# BSD 3-Clause License
# 
# Copyright 2022 Lawrence T. Clark, Vinay Vashishtha, or Arizona State
# University
# 
# Redistribution and use in source and binary forms, with or without
# modification, are permitted provided that the following conditions are met:
# 
# 1. Redistributions of source code must retain the above copyright notice,
# this list of conditions and the following disclaimer.
# 
# 2. Redistributions in binary form must reproduce the above copyright
# notice, this list of conditions and the following disclaimer in the
# documentation and/or other materials provided with the distribution.
# 
# 3. Neither the name of the copyright holder nor the names of its
# contributors may be used to endorse or promote products derived from this
# software without specific prior written permission.
# 
# THIS SOFTWARE IS PROVIDED BY THE COPYRIGHT HOLDERS AND CONTRIBUTORS "AS IS"
# AND ANY EXPRESS OR IMPLIED WARRANTIES, INCLUDING, BUT NOT LIMITED TO, THE
# IMPLIED WARRANTIES OF MERCHANTABILITY AND FITNESS FOR A PARTICULAR PURPOSE
# ARE DISCLAIMED. IN NO EVENT SHALL THE COPYRIGHT HOLDER OR CONTRIBUTORS BE
# LIABLE FOR ANY DIRECT, INDIRECT, INCIDENTAL, SPECIAL, EXEMPLARY, OR
# CONSEQUENTIAL DAMAGES (INCLUDING, BUT NOT LIMITED TO, PROCUREMENT OF
# SUBSTITUTE GOODS OR SERVICES; LOSS OF USE, DATA, OR PROFITS; OR BUSINESS
# INTERRUPTION) HOWEVER CAUSED AND ON ANY THEORY OF LIABILITY, WHETHER IN
# CONTRACT, STRICT LIABILITY, OR TORT (INCLUDING NEGLIGENCE OR OTHERWISE)
# ARISING IN ANY WAY OUT OF THE USE OF THIS SOFTWARE, EVEN IF ADVISED OF THE
# POSSIBILITY OF SUCH DAMAGE.

VERSION 5.8 ;
BUSBITCHARS "[]" ;
DIVIDERCHAR "/" ;

SITE asap7sc7p5t
 CLASS CORE ;
 SIZE 0.054 BY 0.270 ;
 SYMMETRY Y ;
END asap7sc7p5t

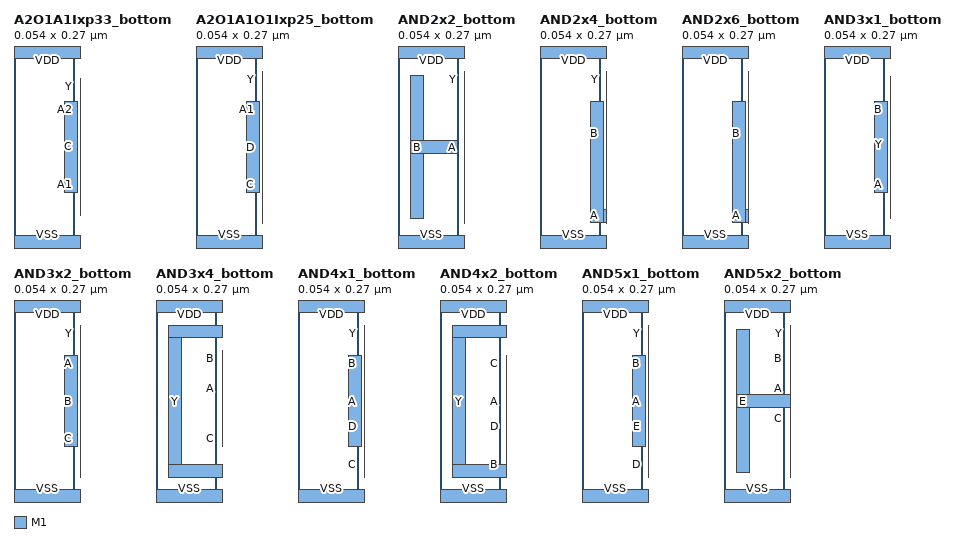
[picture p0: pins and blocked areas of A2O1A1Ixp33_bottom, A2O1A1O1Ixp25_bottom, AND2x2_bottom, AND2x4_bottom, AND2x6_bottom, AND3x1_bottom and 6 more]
MACRO A2O1A1Ixp33_bottom
  CLASS CORE ;
  ORIGIN 0 0 ;
  FOREIGN A2O1A1Ixp33_bottom 0 0 ;
  SIZE 0.054 BY 0.270 ;
  SYMMETRY X Y ;
  SITE asap7sc7p5t ;
  PIN A1
    DIRECTION INPUT ;
    USE SIGNAL ;
    PORT
      LAYER M1 ;
        RECT 0.072 0.07 0.09 0.2 ;
    END
  END A1
  PIN A2
    DIRECTION INPUT ;
    USE SIGNAL ;
    PORT
      LAYER M1 ;
        RECT 0.126 0.07 0.144 0.2 ;
    END
  END A2
  PIN B
    DIRECTION INPUT ;
    USE SIGNAL ;
    PORT
      LAYER M1 ;
        RECT 0.18 0.07 0.198 0.2 ;
    END
  END B
  PIN C
    DIRECTION INPUT ;
    USE SIGNAL ;
    PORT
      LAYER M1 ;
        RECT 0.234 0.081 0.252 0.19 ;
    END
  END C
  PIN VDD
    DIRECTION INOUT ;
    USE POWER ;
    SHAPE ABUTMENT ;
    PORT
      LAYER M1 ;
        RECT 0 0.261 0.324 0.279 ;
    END
  END VDD
  PIN VSS
    DIRECTION INOUT ;
    USE GROUND ;
    SHAPE ABUTMENT ;
    PORT
      LAYER M1 ;
        RECT 0 -0.009 0.324 0.009 ;
    END
  END VSS
  PIN Y
    DIRECTION OUTPUT ;
    USE SIGNAL ;
    PORT
      LAYER M1 ;
        RECT 0.214 0.215 0.306 0.233 ;
        RECT 0.288 0.037 0.306 0.233 ;
        RECT 0.262 0.037 0.306 0.055 ;
    END
  END Y
  OBS
    LAYER M1 ;
      RECT 0 0 0 0 ;
  END
END A2O1A1Ixp33_bottom

MACRO A2O1A1O1Ixp25_bottom
  CLASS CORE ;
  ORIGIN 0 0 ;
  FOREIGN A2O1A1O1Ixp25_bottom 0 0 ;
  SIZE 0.054 BY 0.270 ;
  SYMMETRY X Y ;
  SITE asap7sc7p5t ;
  PIN A1
    DIRECTION INPUT ;
    USE SIGNAL ;
    PORT
      LAYER M1 ;
        RECT 0.126 0.07 0.144 0.2 ;
    END
  END A1
  PIN A2
    DIRECTION INPUT ;
    USE SIGNAL ;
    PORT
      LAYER M1 ;
        RECT 0.072 0.07 0.09 0.2 ;
    END
  END A2
  PIN B
    DIRECTION INPUT ;
    USE SIGNAL ;
    PORT
      LAYER M1 ;
        RECT 0.18 0.07 0.198 0.2 ;
    END
  END B
  PIN C
    DIRECTION INPUT ;
    USE SIGNAL ;
    PORT
      LAYER M1 ;
        RECT 0.234 0.07 0.252 0.2 ;
    END
  END C
  PIN D
    DIRECTION INPUT ;
    USE SIGNAL ;
    PORT
      LAYER M1 ;
        RECT 0.342 0.127 0.414 0.145 ;
        RECT 0.342 0.07 0.36 0.2 ;
    END
  END D
  PIN VDD
    DIRECTION INOUT ;
    USE POWER ;
    SHAPE ABUTMENT ;
    PORT
      LAYER M1 ;
        RECT 0 0.261 0.486 0.279 ;
    END
  END VDD
  PIN VSS
    DIRECTION INOUT ;
    USE GROUND ;
    SHAPE ABUTMENT ;
    PORT
      LAYER M1 ;
        RECT 0 -0.009 0.486 0.009 ;
    END
  END VSS
  PIN Y
    DIRECTION OUTPUT ;
    USE SIGNAL ;
    PORT
      LAYER M1 ;
        RECT 0.423 0.225 0.468 0.243 ;
        RECT 0.45 0.027 0.468 0.243 ;
        RECT 0.261 0.027 0.468 0.045 ;
    END
  END Y
  OBS
    LAYER M1 ;
      RECT 0 0 0 0 ;
  END
END A2O1A1O1Ixp25_bottom

MACRO AND2x2_bottom
  CLASS CORE ;
  ORIGIN 0 0 ;
  FOREIGN AND2x2_bottom 0 0 ;
  SIZE 0.054 BY 0.270 ;
  SYMMETRY X Y ;
  SITE asap7sc7p5t ;
  PIN A
    DIRECTION INPUT ;
    USE SIGNAL ;
    PORT
      LAYER M1 ;
        RECT 0.126 0.07 0.144 0.2 ;
    END
  END A
  PIN B
    DIRECTION INPUT ;
    USE SIGNAL ;
    PORT
      LAYER M1 ;
        RECT 0.018 0.126 0.084 0.144 ;
        RECT 0.018 0.034 0.036 0.236 ;
    END
  END B
  PIN VDD
    DIRECTION INOUT ;
    USE POWER ;
    SHAPE ABUTMENT ;
    PORT
      LAYER M1 ;
        RECT 0 0.261 0.324 0.279 ;
    END
  END VDD
  PIN VSS
    DIRECTION INOUT ;
    USE GROUND ;
    SHAPE ABUTMENT ;
    PORT
      LAYER M1 ;
        RECT 0 -0.009 0.324 0.009 ;
    END
  END VSS
  PIN Y
    DIRECTION OUTPUT ;
    USE SIGNAL ;
    PORT
      LAYER M1 ;
        RECT 0.207 0.225 0.306 0.243 ;
        RECT 0.288 0.027 0.306 0.243 ;
        RECT 0.207 0.027 0.306 0.045 ;
        RECT 0.207 0.184 0.225 0.243 ;
        RECT 0.207 0.027 0.225 0.086 ;
    END
  END Y
  OBS
    LAYER M1 ;
      RECT 0 0 0 0 ;
  END
END AND2x2_bottom

MACRO AND2x4_bottom
  CLASS CORE ;
  ORIGIN 0 0 ;
  FOREIGN AND2x4_bottom 0 0 ;
  SIZE 0.054 BY 0.270 ;
  SYMMETRY X Y ;
  SITE asap7sc7p5t ;
  PIN A
    DIRECTION INPUT ;
    USE SIGNAL ;
    PORT
      LAYER M1 ;
        RECT 0.234 0.028 0.252 0.15 ;
        RECT 0.072 0.028 0.252 0.046 ;
        RECT 0.072 0.028 0.09 0.2 ;
    END
  END A
  PIN B
    DIRECTION INPUT ;
    USE SIGNAL ;
    PORT
      LAYER M1 ;
        RECT 0.126 0.107 0.144 0.2 ;
    END
  END B
  PIN VDD
    DIRECTION INOUT ;
    USE POWER ;
    SHAPE ABUTMENT ;
    PORT
      LAYER M1 ;
        RECT 0 0.261 0.54 0.279 ;
    END
  END VDD
  PIN VSS
    DIRECTION INOUT ;
    USE GROUND ;
    SHAPE ABUTMENT ;
    PORT
      LAYER M1 ;
        RECT 0 -0.009 0.54 0.009 ;
    END
  END VSS
  PIN Y
    DIRECTION OUTPUT ;
    USE SIGNAL ;
    PORT
      LAYER M1 ;
        RECT 0.31 0.225 0.468 0.243 ;
        RECT 0.45 0.027 0.468 0.243 ;
        RECT 0.31 0.027 0.468 0.045 ;
    END
  END Y
  OBS
    LAYER M1 ;
      RECT 0 0 0 0 ;
  END
END AND2x4_bottom

MACRO AND2x6_bottom
  CLASS CORE ;
  ORIGIN 0 0 ;
  FOREIGN AND2x6_bottom 0 0 ;
  SIZE 0.054 BY 0.270 ;
  SYMMETRY X Y ;
  SITE asap7sc7p5t ;
  PIN A
    DIRECTION INPUT ;
    USE SIGNAL ;
    PORT
      LAYER M1 ;
        RECT 0.234 0.028 0.252 0.15 ;
        RECT 0.072 0.028 0.252 0.046 ;
        RECT 0.072 0.028 0.09 0.2 ;
    END
  END A
  PIN B
    DIRECTION INPUT ;
    USE SIGNAL ;
    PORT
      LAYER M1 ;
        RECT 0.126 0.107 0.144 0.2 ;
    END
  END B
  PIN VDD
    DIRECTION INOUT ;
    USE POWER ;
    SHAPE ABUTMENT ;
    PORT
      LAYER M1 ;
        RECT 0 0.261 0.648 0.279 ;
    END
  END VDD
  PIN VSS
    DIRECTION INOUT ;
    USE GROUND ;
    SHAPE ABUTMENT ;
    PORT
      LAYER M1 ;
        RECT 0 -0.009 0.648 0.009 ;
    END
  END VSS
  PIN Y
    DIRECTION OUTPUT ;
    USE SIGNAL ;
    PORT
      LAYER M1 ;
        RECT 0.31 0.225 0.554 0.243 ;
        RECT 0.31 0.027 0.554 0.045 ;
        RECT 0.45 0.027 0.468 0.243 ;
    END
  END Y
  OBS
    LAYER M1 ;
      RECT 0 0 0 0 ;
  END
END AND2x6_bottom

MACRO AND3x1_bottom
  CLASS CORE ;
  ORIGIN 0 0 ;
  FOREIGN AND3x1_bottom 0 0 ;
  SIZE 0.054 BY 0.270 ;
  SYMMETRY X Y ;
  SITE asap7sc7p5t ;
  PIN A
    DIRECTION INPUT ;
    USE SIGNAL ;
    PORT
      LAYER M1 ;
        RECT 0.072 0.07 0.09 0.2 ;
    END
  END A
  PIN B
    DIRECTION INPUT ;
    USE SIGNAL ;
    PORT
      LAYER M1 ;
        RECT 0.126 0.07 0.144 0.2 ;
    END
  END B
  PIN C
    DIRECTION INPUT ;
    USE SIGNAL ;
    PORT
      LAYER M1 ;
        RECT 0.18 0.07 0.198 0.2 ;
    END
  END C
  PIN VDD
    DIRECTION INOUT ;
    USE POWER ;
    SHAPE ABUTMENT ;
    PORT
      LAYER M1 ;
        RECT 0 0.261 0.324 0.279 ;
    END
  END VDD
  PIN VSS
    DIRECTION INOUT ;
    USE GROUND ;
    SHAPE ABUTMENT ;
    PORT
      LAYER M1 ;
        RECT 0 -0.009 0.324 0.009 ;
    END
  END VSS
  PIN Y
    DIRECTION OUTPUT ;
    USE SIGNAL ;
    PORT
      LAYER M1 ;
        RECT 0.261 0.183 0.306 0.201 ;
        RECT 0.288 0.076 0.306 0.201 ;
        RECT 0.261 0.076 0.306 0.094 ;
        RECT 0.261 0.183 0.279 0.235 ;
        RECT 0.261 0.034 0.279 0.094 ;
    END
  END Y
  OBS
    LAYER M1 ;
      RECT 0 0 0 0 ;
  END
END AND3x1_bottom

MACRO AND3x2_bottom
  CLASS CORE ;
  ORIGIN 0 0 ;
  FOREIGN AND3x2_bottom 0 0 ;
  SIZE 0.054 BY 0.270 ;
  SYMMETRY X Y ;
  SITE asap7sc7p5t ;
  PIN A
    DIRECTION INPUT ;
    USE SIGNAL ;
    PORT
      LAYER M1 ;
        RECT 0.072 0.07 0.09 0.2 ;
    END
  END A
  PIN B
    DIRECTION INPUT ;
    USE SIGNAL ;
    PORT
      LAYER M1 ;
        RECT 0.126 0.07 0.144 0.2 ;
    END
  END B
  PIN C
    DIRECTION INPUT ;
    USE SIGNAL ;
    PORT
      LAYER M1 ;
        RECT 0.18 0.07 0.198 0.2 ;
    END
  END C
  PIN VDD
    DIRECTION INOUT ;
    USE POWER ;
    SHAPE ABUTMENT ;
    PORT
      LAYER M1 ;
        RECT 0 0.261 0.378 0.279 ;
    END
  END VDD
  PIN VSS
    DIRECTION INOUT ;
    USE GROUND ;
    SHAPE ABUTMENT ;
    PORT
      LAYER M1 ;
        RECT 0 -0.009 0.378 0.009 ;
    END
  END VSS
  PIN Y
    DIRECTION OUTPUT ;
    USE SIGNAL ;
    PORT
      LAYER M1 ;
        RECT 0.261 0.225 0.36 0.243 ;
        RECT 0.342 0.027 0.36 0.243 ;
        RECT 0.261 0.027 0.36 0.045 ;
        RECT 0.261 0.184 0.279 0.243 ;
        RECT 0.261 0.027 0.279 0.086 ;
    END
  END Y
  OBS
    LAYER M1 ;
      RECT 0 0 0 0 ;
  END
END AND3x2_bottom

MACRO AND3x4_bottom
  CLASS CORE ;
  ORIGIN 0 0 ;
  FOREIGN AND3x4_bottom 0 0 ;
  SIZE 0.054 BY 0.270 ;
  SYMMETRY X Y ;
  SITE asap7sc7p5t ;
  PIN A
    DIRECTION INPUT ;
    USE SIGNAL ;
    PORT
      LAYER M1 ;
        RECT 0.612 0.189 0.649 0.207 ;
        RECT 0.612 0.099 0.649 0.117 ;
        RECT 0.612 0.099 0.63 0.207 ;
    END
  END A
  PIN B
    DIRECTION INPUT ;
    USE SIGNAL ;
    PORT
      LAYER M1 ;
        RECT 0.504 0.189 0.541 0.207 ;
        RECT 0.504 0.099 0.541 0.117 ;
        RECT 0.504 0.099 0.522 0.207 ;
    END
  END B
  PIN C
    DIRECTION INPUT ;
    USE SIGNAL ;
    PORT
      LAYER M1 ;
        RECT 0.342 0.07 0.36 0.2 ;
    END
  END C
  PIN VDD
    DIRECTION INOUT ;
    USE POWER ;
    SHAPE ABUTMENT ;
    PORT
      LAYER M1 ;
        RECT 0 0.261 0.756 0.279 ;
    END
  END VDD
  PIN VSS
    DIRECTION INOUT ;
    USE GROUND ;
    SHAPE ABUTMENT ;
    PORT
      LAYER M1 ;
        RECT 0 -0.009 0.756 0.009 ;
    END
  END VSS
  PIN Y
    DIRECTION OUTPUT ;
    USE SIGNAL ;
    PORT
      LAYER M1 ;
        RECT 0.018 0.225 0.23 0.243 ;
        RECT 0.018 0.027 0.23 0.045 ;
        RECT 0.018 0.027 0.036 0.243 ;
    END
  END Y
  OBS
    LAYER M1 ;
      RECT 0 0 0 0 ;
  END
END AND3x4_bottom

MACRO AND4x1_bottom
  CLASS CORE ;
  ORIGIN 0 0 ;
  FOREIGN AND4x1_bottom 0 0 ;
  SIZE 0.054 BY 0.270 ;
  SYMMETRY X Y ;
  SITE asap7sc7p5t ;
  PIN A
    DIRECTION INPUT ;
    USE SIGNAL ;
    PORT
      LAYER M1 ;
        RECT 0.072 0.07 0.09 0.2 ;
    END
  END A
  PIN B
    DIRECTION INPUT ;
    USE SIGNAL ;
    PORT
      LAYER M1 ;
        RECT 0.126 0.034 0.144 0.2 ;
    END
  END B
  PIN C
    DIRECTION INPUT ;
    USE SIGNAL ;
    PORT
      LAYER M1 ;
        RECT 0.18 0.034 0.198 0.2 ;
    END
  END C
  PIN D
    DIRECTION INPUT ;
    USE SIGNAL ;
    PORT
      LAYER M1 ;
        RECT 0.234 0.034 0.252 0.164 ;
    END
  END D
  PIN VDD
    DIRECTION INOUT ;
    USE POWER ;
    SHAPE ABUTMENT ;
    PORT
      LAYER M1 ;
        RECT 0 0.261 0.378 0.279 ;
    END
  END VDD
  PIN VSS
    DIRECTION INOUT ;
    USE GROUND ;
    SHAPE ABUTMENT ;
    PORT
      LAYER M1 ;
        RECT 0 -0.009 0.378 0.009 ;
    END
  END VSS
  PIN Y
    DIRECTION OUTPUT ;
    USE SIGNAL ;
    PORT
      LAYER M1 ;
        RECT 0.299 0.225 0.36 0.243 ;
        RECT 0.342 0.027 0.36 0.243 ;
        RECT 0.31 0.027 0.36 0.045 ;
    END
  END Y
  OBS
    LAYER M1 ;
      RECT 0 0 0 0 ;
  END
END AND4x1_bottom

MACRO AND4x2_bottom
  CLASS CORE ;
  ORIGIN 0 0 ;
  FOREIGN AND4x2_bottom 0 0 ;
  SIZE 0.054 BY 0.270 ;
  SYMMETRY X Y ;
  SITE asap7sc7p5t ;
  PIN A
    DIRECTION INPUT ;
    USE SIGNAL ;
    PORT
      LAYER M1 ;
        RECT 0.342 0.07 0.36 0.2 ;
    END
  END A
  PIN B
    DIRECTION INPUT ;
    USE SIGNAL ;
    PORT
      LAYER M1 ;
        RECT 0.288 0.034 0.306 0.2 ;
    END
  END B
  PIN C
    DIRECTION INPUT ;
    USE SIGNAL ;
    PORT
      LAYER M1 ;
        RECT 0.234 0.034 0.252 0.2 ;
    END
  END C
  PIN D
    DIRECTION INPUT ;
    USE SIGNAL ;
    PORT
      LAYER M1 ;
        RECT 0.18 0.034 0.198 0.164 ;
    END
  END D
  PIN VDD
    DIRECTION INOUT ;
    USE POWER ;
    SHAPE ABUTMENT ;
    PORT
      LAYER M1 ;
        RECT 0 0.261 0.432 0.279 ;
    END
  END VDD
  PIN VSS
    DIRECTION INOUT ;
    USE GROUND ;
    SHAPE ABUTMENT ;
    PORT
      LAYER M1 ;
        RECT 0 -0.009 0.432 0.009 ;
    END
  END VSS
  PIN Y
    DIRECTION OUTPUT ;
    USE SIGNAL ;
    PORT
      LAYER M1 ;
        RECT 0.018 0.225 0.122 0.243 ;
        RECT 0.018 0.027 0.122 0.045 ;
        RECT 0.018 0.027 0.036 0.243 ;
    END
  END Y
  OBS
    LAYER M1 ;
      RECT 0 0 0 0 ;
  END
END AND4x2_bottom

MACRO AND5x1_bottom
  CLASS CORE ;
  ORIGIN 0 0 ;
  FOREIGN AND5x1_bottom 0 0 ;
  SIZE 0.054 BY 0.270 ;
  SYMMETRY X Y ;
  SITE asap7sc7p5t ;
  PIN A
    DIRECTION INPUT ;
    USE SIGNAL ;
    PORT
      LAYER M1 ;
        RECT 0.072 0.07 0.09 0.2 ;
    END
  END A
  PIN B
    DIRECTION INPUT ;
    USE SIGNAL ;
    PORT
      LAYER M1 ;
        RECT 0.126 0.034 0.144 0.2 ;
    END
  END B
  PIN C
    DIRECTION INPUT ;
    USE SIGNAL ;
    PORT
      LAYER M1 ;
        RECT 0.18 0.034 0.198 0.2 ;
    END
  END C
  PIN D
    DIRECTION INPUT ;
    USE SIGNAL ;
    PORT
      LAYER M1 ;
        RECT 0.234 0.034 0.252 0.2 ;
    END
  END D
  PIN E
    DIRECTION INPUT ;
    USE SIGNAL ;
    PORT
      LAYER M1 ;
        RECT 0.288 0.034 0.306 0.164 ;
    END
  END E
  PIN VDD
    DIRECTION INOUT ;
    USE POWER ;
    SHAPE ABUTMENT ;
    PORT
      LAYER M1 ;
        RECT 0 0.261 0.432 0.279 ;
    END
  END VDD
  PIN VSS
    DIRECTION INOUT ;
    USE GROUND ;
    SHAPE ABUTMENT ;
    PORT
      LAYER M1 ;
        RECT 0 -0.009 0.432 0.009 ;
    END
  END VSS
  PIN Y
    DIRECTION OUTPUT ;
    USE SIGNAL ;
    PORT
      LAYER M1 ;
        RECT 0.349 0.225 0.414 0.243 ;
        RECT 0.396 0.027 0.414 0.243 ;
        RECT 0.35 0.027 0.414 0.045 ;
    END
  END Y
  OBS
    LAYER M1 ;
      RECT 0 0 0 0 ;
  END
END AND5x1_bottom

MACRO AND5x2_bottom
  CLASS CORE ;
  ORIGIN 0 0 ;
  FOREIGN AND5x2_bottom 0 0 ;
  SIZE 0.054 BY 0.270 ;
  SYMMETRY X Y ;
  SITE asap7sc7p5t ;
  PIN A
    DIRECTION INPUT ;
    USE SIGNAL ;
    PORT
      LAYER M1 ;
        RECT 0.72 0.189 0.757 0.207 ;
        RECT 0.72 0.099 0.757 0.117 ;
        RECT 0.72 0.099 0.738 0.207 ;
    END
  END A
  PIN B
    DIRECTION INPUT ;
    USE SIGNAL ;
    PORT
      LAYER M1 ;
        RECT 0.593 0.189 0.63 0.207 ;
        RECT 0.612 0.099 0.63 0.207 ;
        RECT 0.593 0.099 0.63 0.117 ;
    END
  END B
  PIN C
    DIRECTION INPUT ;
    USE SIGNAL ;
    PORT
      LAYER M1 ;
        RECT 0.45 0.189 0.487 0.207 ;
        RECT 0.45 0.099 0.487 0.117 ;
        RECT 0.45 0.099 0.468 0.207 ;
    END
  END C
  PIN D
    DIRECTION INPUT ;
    USE SIGNAL ;
    PORT
      LAYER M1 ;
        RECT 0.269 0.189 0.306 0.207 ;
        RECT 0.288 0.099 0.306 0.207 ;
        RECT 0.269 0.099 0.306 0.117 ;
    END
  END D
  PIN E
    DIRECTION INPUT ;
    USE SIGNAL ;
    PORT
      LAYER M1 ;
        RECT 0.018 0.126 0.095 0.144 ;
        RECT 0.018 0.034 0.036 0.236 ;
    END
  END E
  PIN VDD
    DIRECTION INOUT ;
    USE POWER ;
    SHAPE ABUTMENT ;
    PORT
      LAYER M1 ;
        RECT 0 0.261 1.08 0.279 ;
    END
  END VDD
  PIN VSS
    DIRECTION INOUT ;
    USE GROUND ;
    SHAPE ABUTMENT ;
    PORT
      LAYER M1 ;
        RECT 0 -0.009 1.08 0.009 ;
    END
  END VSS
  PIN Y
    DIRECTION OUTPUT ;
    USE SIGNAL ;
    PORT
      LAYER M1 ;
        RECT 0.958 0.225 1.062 0.243 ;
        RECT 1.044 0.027 1.062 0.243 ;
        RECT 0.958 0.027 1.062 0.045 ;
    END
  END Y
  OBS
    LAYER M1 ;
      RECT 0 0 0 0 ;
  END
END AND5x2_bottom

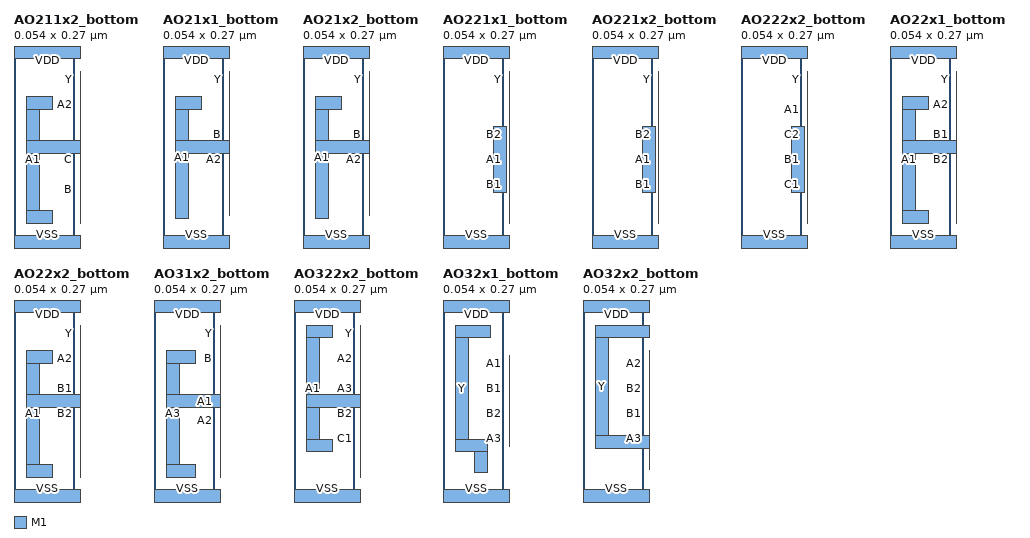
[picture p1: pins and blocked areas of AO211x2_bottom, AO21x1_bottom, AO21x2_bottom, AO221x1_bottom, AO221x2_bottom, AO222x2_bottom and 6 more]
MACRO AO211x2_bottom
  CLASS CORE ;
  ORIGIN 0 0 ;
  FOREIGN AO211x2_bottom 0 0 ;
  SIZE 0.054 BY 0.270 ;
  SYMMETRY X Y ;
  SITE asap7sc7p5t ;
  PIN A1
    DIRECTION INPUT ;
    USE SIGNAL ;
    PORT
      LAYER M1 ;
        RECT 0.018 0.126 0.095 0.144 ;
        RECT 0.018 0.189 0.055 0.207 ;
        RECT 0.018 0.027 0.055 0.045 ;
        RECT 0.018 0.027 0.036 0.207 ;
    END
  END A1
  PIN A2
    DIRECTION INPUT ;
    USE SIGNAL ;
    PORT
      LAYER M1 ;
        RECT 0.126 0.126 0.203 0.144 ;
        RECT 0.107 0.189 0.144 0.207 ;
        RECT 0.126 0.063 0.144 0.207 ;
        RECT 0.107 0.063 0.144 0.081 ;
    END
  END A2
  PIN B
    DIRECTION INPUT ;
    USE SIGNAL ;
    PORT
      LAYER M1 ;
        RECT 0.234 0.126 0.311 0.144 ;
        RECT 0.215 0.189 0.252 0.207 ;
        RECT 0.234 0.063 0.252 0.207 ;
        RECT 0.215 0.063 0.252 0.081 ;
    END
  END B
  PIN C
    DIRECTION INPUT ;
    USE SIGNAL ;
    PORT
      LAYER M1 ;
        RECT 0.504 0.153 0.541 0.171 ;
        RECT 0.504 0.063 0.522 0.171 ;
        RECT 0.485 0.063 0.522 0.081 ;
    END
  END C
  PIN VDD
    DIRECTION INOUT ;
    USE POWER ;
    SHAPE ABUTMENT ;
    PORT
      LAYER M1 ;
        RECT 0 0.261 0.864 0.279 ;
    END
  END VDD
  PIN VSS
    DIRECTION INOUT ;
    USE GROUND ;
    SHAPE ABUTMENT ;
    PORT
      LAYER M1 ;
        RECT 0 -0.009 0.864 0.009 ;
    END
  END VSS
  PIN Y
    DIRECTION OUTPUT ;
    USE SIGNAL ;
    PORT
      LAYER M1 ;
        RECT 0.742 0.225 0.846 0.243 ;
        RECT 0.828 0.027 0.846 0.243 ;
        RECT 0.742 0.027 0.846 0.045 ;
    END
  END Y
  OBS
    LAYER M1 ;
      RECT 0 0 0 0 ;
  END
END AO211x2_bottom

MACRO AO21x1_bottom
  CLASS CORE ;
  ORIGIN 0 0 ;
  FOREIGN AO21x1_bottom 0 0 ;
  SIZE 0.054 BY 0.270 ;
  SYMMETRY X Y ;
  SITE asap7sc7p5t ;
  PIN A1
    DIRECTION INPUT ;
    USE SIGNAL ;
    PORT
      LAYER M1 ;
        RECT 0.018 0.126 0.095 0.144 ;
        RECT 0.018 0.189 0.055 0.207 ;
        RECT 0.018 0.034 0.036 0.207 ;
    END
  END A1
  PIN A2
    DIRECTION INPUT ;
    USE SIGNAL ;
    PORT
      LAYER M1 ;
        RECT 0.126 0.07 0.144 0.164 ;
    END
  END A2
  PIN B
    DIRECTION INPUT ;
    USE SIGNAL ;
    PORT
      LAYER M1 ;
        RECT 0.18 0.07 0.198 0.164 ;
    END
  END B
  PIN VDD
    DIRECTION INOUT ;
    USE POWER ;
    SHAPE ABUTMENT ;
    PORT
      LAYER M1 ;
        RECT 0 0.261 0.324 0.279 ;
    END
  END VDD
  PIN VSS
    DIRECTION INOUT ;
    USE GROUND ;
    SHAPE ABUTMENT ;
    PORT
      LAYER M1 ;
        RECT 0 -0.009 0.324 0.009 ;
    END
  END VSS
  PIN Y
    DIRECTION OUTPUT ;
    USE SIGNAL ;
    PORT
      LAYER M1 ;
        RECT 0.23 0.225 0.295 0.243 ;
        RECT 0.277 0.038 0.295 0.243 ;
    END
  END Y
  OBS
    LAYER M1 ;
      RECT 0 0 0 0 ;
  END
END AO21x1_bottom

MACRO AO21x2_bottom
  CLASS CORE ;
  ORIGIN 0 0 ;
  FOREIGN AO21x2_bottom 0 0 ;
  SIZE 0.054 BY 0.270 ;
  SYMMETRY X Y ;
  SITE asap7sc7p5t ;
  PIN A1
    DIRECTION INPUT ;
    USE SIGNAL ;
    PORT
      LAYER M1 ;
        RECT 0.018 0.126 0.095 0.144 ;
        RECT 0.018 0.189 0.055 0.207 ;
        RECT 0.018 0.034 0.036 0.207 ;
    END
  END A1
  PIN A2
    DIRECTION INPUT ;
    USE SIGNAL ;
    PORT
      LAYER M1 ;
        RECT 0.126 0.07 0.144 0.164 ;
    END
  END A2
  PIN B
    DIRECTION INPUT ;
    USE SIGNAL ;
    PORT
      LAYER M1 ;
        RECT 0.18 0.07 0.198 0.164 ;
    END
  END B
  PIN VDD
    DIRECTION INOUT ;
    USE POWER ;
    SHAPE ABUTMENT ;
    PORT
      LAYER M1 ;
        RECT 0 0.261 0.378 0.279 ;
    END
  END VDD
  PIN VSS
    DIRECTION INOUT ;
    USE GROUND ;
    SHAPE ABUTMENT ;
    PORT
      LAYER M1 ;
        RECT 0 -0.009 0.378 0.009 ;
    END
  END VSS
  PIN Y
    DIRECTION OUTPUT ;
    USE SIGNAL ;
    PORT
      LAYER M1 ;
        RECT 0.23 0.225 0.333 0.243 ;
        RECT 0.315 0.069 0.333 0.243 ;
        RECT 0.276 0.069 0.333 0.087 ;
        RECT 0.276 0.038 0.294 0.087 ;
    END
  END Y
  OBS
    LAYER M1 ;
      RECT 0 0 0 0 ;
  END
END AO21x2_bottom

MACRO AO221x1_bottom
  CLASS CORE ;
  ORIGIN 0 0 ;
  FOREIGN AO221x1_bottom 0 0 ;
  SIZE 0.054 BY 0.270 ;
  SYMMETRY X Y ;
  SITE asap7sc7p5t ;
  PIN A1
    DIRECTION INPUT ;
    USE SIGNAL ;
    PORT
      LAYER M1 ;
        RECT 0.234 0.07 0.252 0.164 ;
    END
  END A1
  PIN A2
    DIRECTION INPUT ;
    USE SIGNAL ;
    PORT
      LAYER M1 ;
        RECT 0.288 0.07 0.306 0.164 ;
    END
  END A2
  PIN B1
    DIRECTION INPUT ;
    USE SIGNAL ;
    PORT
      LAYER M1 ;
        RECT 0.072 0.07 0.09 0.164 ;
    END
  END B1
  PIN B2
    DIRECTION INPUT ;
    USE SIGNAL ;
    PORT
      LAYER M1 ;
        RECT 0.126 0.07 0.144 0.164 ;
    END
  END B2
  PIN C
    DIRECTION INPUT ;
    USE SIGNAL ;
    PORT
      LAYER M1 ;
        RECT 0.18 0.07 0.198 0.164 ;
    END
  END C
  PIN VDD
    DIRECTION INOUT ;
    USE POWER ;
    SHAPE ABUTMENT ;
    PORT
      LAYER M1 ;
        RECT 0 0.261 0.54 0.279 ;
    END
  END VDD
  PIN VSS
    DIRECTION INOUT ;
    USE GROUND ;
    SHAPE ABUTMENT ;
    PORT
      LAYER M1 ;
        RECT 0 -0.009 0.54 0.009 ;
    END
  END VSS
  PIN Y
    DIRECTION OUTPUT ;
    USE SIGNAL ;
    PORT
      LAYER M1 ;
        RECT 0.472 0.225 0.522 0.243 ;
        RECT 0.504 0.027 0.522 0.243 ;
        RECT 0.459 0.027 0.522 0.045 ;
    END
  END Y
  OBS
    LAYER M1 ;
      RECT 0 0 0 0 ;
  END
END AO221x1_bottom

MACRO AO221x2_bottom
  CLASS CORE ;
  ORIGIN 0 0 ;
  FOREIGN AO221x2_bottom 0 0 ;
  SIZE 0.054 BY 0.270 ;
  SYMMETRY X Y ;
  SITE asap7sc7p5t ;
  PIN A1
    DIRECTION INPUT ;
    USE SIGNAL ;
    PORT
      LAYER M1 ;
        RECT 0.234 0.07 0.252 0.164 ;
    END
  END A1
  PIN A2
    DIRECTION INPUT ;
    USE SIGNAL ;
    PORT
      LAYER M1 ;
        RECT 0.288 0.07 0.306 0.164 ;
    END
  END A2
  PIN B1
    DIRECTION INPUT ;
    USE SIGNAL ;
    PORT
      LAYER M1 ;
        RECT 0.072 0.07 0.09 0.164 ;
    END
  END B1
  PIN B2
    DIRECTION INPUT ;
    USE SIGNAL ;
    PORT
      LAYER M1 ;
        RECT 0.126 0.07 0.144 0.164 ;
    END
  END B2
  PIN C
    DIRECTION INPUT ;
    USE SIGNAL ;
    PORT
      LAYER M1 ;
        RECT 0.18 0.07 0.198 0.164 ;
    END
  END C
  PIN VDD
    DIRECTION INOUT ;
    USE POWER ;
    SHAPE ABUTMENT ;
    PORT
      LAYER M1 ;
        RECT 0 0.261 0.594 0.279 ;
    END
  END VDD
  PIN VSS
    DIRECTION INOUT ;
    USE GROUND ;
    SHAPE ABUTMENT ;
    PORT
      LAYER M1 ;
        RECT 0 -0.009 0.594 0.009 ;
    END
  END VSS
  PIN Y
    DIRECTION OUTPUT ;
    USE SIGNAL ;
    PORT
      LAYER M1 ;
        RECT 0.472 0.225 0.549 0.243 ;
        RECT 0.531 0.027 0.549 0.243 ;
        RECT 0.459 0.027 0.549 0.045 ;
    END
  END Y
  OBS
    LAYER M1 ;
      RECT 0 0 0 0 ;
  END
END AO221x2_bottom

MACRO AO222x2_bottom
  CLASS CORE ;
  ORIGIN 0 0 ;
  FOREIGN AO222x2_bottom 0 0 ;
  SIZE 0.054 BY 0.270 ;
  SYMMETRY X Y ;
  SITE asap7sc7p5t ;
  PIN A1
    DIRECTION INPUT ;
    USE SIGNAL ;
    PORT
      LAYER M1 ;
        RECT 0.396 0.07 0.414 0.2 ;
    END
  END A1
  PIN A2
    DIRECTION INPUT ;
    USE SIGNAL ;
    PORT
      LAYER M1 ;
        RECT 0.45 0.07 0.468 0.2 ;
    END
  END A2
  PIN B1
    DIRECTION INPUT ;
    USE SIGNAL ;
    PORT
      LAYER M1 ;
        RECT 0.234 0.07 0.252 0.164 ;
    END
  END B1
  PIN B2
    DIRECTION INPUT ;
    USE SIGNAL ;
    PORT
      LAYER M1 ;
        RECT 0.18 0.07 0.198 0.164 ;
    END
  END B2
  PIN C1
    DIRECTION INPUT ;
    USE SIGNAL ;
    PORT
      LAYER M1 ;
        RECT 0.072 0.07 0.09 0.164 ;
    END
  END C1
  PIN C2
    DIRECTION INPUT ;
    USE SIGNAL ;
    PORT
      LAYER M1 ;
        RECT 0.126 0.07 0.144 0.164 ;
    END
  END C2
  PIN VDD
    DIRECTION INOUT ;
    USE POWER ;
    SHAPE ABUTMENT ;
    PORT
      LAYER M1 ;
        RECT 0 0.261 0.648 0.279 ;
    END
  END VDD
  PIN VSS
    DIRECTION INOUT ;
    USE GROUND ;
    SHAPE ABUTMENT ;
    PORT
      LAYER M1 ;
        RECT 0 -0.009 0.648 0.009 ;
    END
  END VSS
  PIN Y
    DIRECTION OUTPUT ;
    USE SIGNAL ;
    PORT
      LAYER M1 ;
        RECT 0.526 0.225 0.63 0.243 ;
        RECT 0.612 0.027 0.63 0.243 ;
        RECT 0.531 0.027 0.63 0.045 ;
        RECT 0.531 0.027 0.549 0.081 ;
    END
  END Y
  OBS
    LAYER M1 ;
      RECT 0 0 0 0 ;
  END
END AO222x2_bottom

MACRO AO22x1_bottom
  CLASS CORE ;
  ORIGIN 0 0 ;
  FOREIGN AO22x1_bottom 0 0 ;
  SIZE 0.054 BY 0.270 ;
  SYMMETRY X Y ;
  SITE asap7sc7p5t ;
  PIN A1
    DIRECTION INPUT ;
    USE SIGNAL ;
    PORT
      LAYER M1 ;
        RECT 0.018 0.126 0.095 0.144 ;
        RECT 0.018 0.189 0.055 0.207 ;
        RECT 0.018 0.027 0.055 0.045 ;
        RECT 0.018 0.027 0.036 0.207 ;
    END
  END A1
  PIN A2
    DIRECTION INPUT ;
    USE SIGNAL ;
    PORT
      LAYER M1 ;
        RECT 0.107 0.189 0.144 0.207 ;
        RECT 0.126 0.063 0.144 0.207 ;
        RECT 0.107 0.063 0.144 0.081 ;
    END
  END A2
  PIN B1
    DIRECTION INPUT ;
    USE SIGNAL ;
    PORT
      LAYER M1 ;
        RECT 0.234 0.063 0.287 0.081 ;
        RECT 0.234 0.063 0.252 0.164 ;
    END
  END B1
  PIN B2
    DIRECTION INPUT ;
    USE SIGNAL ;
    PORT
      LAYER M1 ;
        RECT 0.18 0.07 0.198 0.164 ;
    END
  END B2
  PIN VDD
    DIRECTION INOUT ;
    USE POWER ;
    SHAPE ABUTMENT ;
    PORT
      LAYER M1 ;
        RECT 0 0.261 0.486 0.279 ;
    END
  END VDD
  PIN VSS
    DIRECTION INOUT ;
    USE GROUND ;
    SHAPE ABUTMENT ;
    PORT
      LAYER M1 ;
        RECT 0 -0.009 0.486 0.009 ;
    END
  END VSS
  PIN Y
    DIRECTION OUTPUT ;
    USE SIGNAL ;
    PORT
      LAYER M1 ;
        RECT 0.418 0.225 0.468 0.243 ;
        RECT 0.45 0.027 0.468 0.243 ;
        RECT 0.418 0.027 0.468 0.045 ;
    END
  END Y
  OBS
    LAYER M1 ;
      RECT 0 0 0 0 ;
  END
END AO22x1_bottom

MACRO AO22x2_bottom
  CLASS CORE ;
  ORIGIN 0 0 ;
  FOREIGN AO22x2_bottom 0 0 ;
  SIZE 0.054 BY 0.270 ;
  SYMMETRY X Y ;
  SITE asap7sc7p5t ;
  PIN A1
    DIRECTION INPUT ;
    USE SIGNAL ;
    PORT
      LAYER M1 ;
        RECT 0.018 0.126 0.095 0.144 ;
        RECT 0.018 0.189 0.055 0.207 ;
        RECT 0.018 0.027 0.055 0.045 ;
        RECT 0.018 0.027 0.036 0.207 ;
    END
  END A1
  PIN A2
    DIRECTION INPUT ;
    USE SIGNAL ;
    PORT
      LAYER M1 ;
        RECT 0.107 0.189 0.144 0.207 ;
        RECT 0.126 0.063 0.144 0.207 ;
        RECT 0.107 0.063 0.144 0.081 ;
    END
  END A2
  PIN B1
    DIRECTION INPUT ;
    USE SIGNAL ;
    PORT
      LAYER M1 ;
        RECT 0.234 0.063 0.287 0.081 ;
        RECT 0.234 0.063 0.252 0.164 ;
    END
  END B1
  PIN B2
    DIRECTION INPUT ;
    USE SIGNAL ;
    PORT
      LAYER M1 ;
        RECT 0.18 0.07 0.198 0.164 ;
    END
  END B2
  PIN VDD
    DIRECTION INOUT ;
    USE POWER ;
    SHAPE ABUTMENT ;
    PORT
      LAYER M1 ;
        RECT 0 0.261 0.54 0.279 ;
    END
  END VDD
  PIN VSS
    DIRECTION INOUT ;
    USE GROUND ;
    SHAPE ABUTMENT ;
    PORT
      LAYER M1 ;
        RECT 0 -0.009 0.54 0.009 ;
    END
  END VSS
  PIN Y
    DIRECTION OUTPUT ;
    USE SIGNAL ;
    PORT
      LAYER M1 ;
        RECT 0.418 0.225 0.522 0.243 ;
        RECT 0.504 0.027 0.522 0.243 ;
        RECT 0.418 0.027 0.522 0.045 ;
    END
  END Y
  OBS
    LAYER M1 ;
      RECT 0 0 0 0 ;
  END
END AO22x2_bottom

MACRO AO31x2_bottom
  CLASS CORE ;
  ORIGIN 0 0 ;
  FOREIGN AO31x2_bottom 0 0 ;
  SIZE 0.054 BY 0.270 ;
  SYMMETRY X Y ;
  SITE asap7sc7p5t ;
  PIN A1
    DIRECTION INPUT ;
    USE SIGNAL ;
    PORT
      LAYER M1 ;
        RECT 0.558 0.099 0.576 0.149 ;
        RECT 0.504 0.099 0.576 0.117 ;
        RECT 0.485 0.153 0.522 0.171 ;
        RECT 0.504 0.099 0.522 0.171 ;
    END
  END A1
  PIN A2
    DIRECTION INPUT ;
    USE SIGNAL ;
    PORT
      LAYER M1 ;
        RECT 0.396 0.099 0.414 0.149 ;
        RECT 0.288 0.099 0.414 0.117 ;
        RECT 0.288 0.153 0.325 0.171 ;
        RECT 0.288 0.07 0.306 0.171 ;
    END
  END A2
  PIN A3
    DIRECTION INPUT ;
    USE SIGNAL ;
    PORT
      LAYER M1 ;
        RECT 0.018 0.126 0.095 0.144 ;
        RECT 0.018 0.189 0.059 0.207 ;
        RECT 0.018 0.027 0.059 0.045 ;
        RECT 0.018 0.027 0.036 0.207 ;
    END
  END A3
  PIN B
    DIRECTION INPUT ;
    USE SIGNAL ;
    PORT
      LAYER M1 ;
        RECT 0.126 0.126 0.203 0.144 ;
        RECT 0.107 0.189 0.144 0.207 ;
        RECT 0.126 0.063 0.144 0.207 ;
        RECT 0.107 0.063 0.144 0.081 ;
    END
  END B
  PIN VDD
    DIRECTION INOUT ;
    USE POWER ;
    SHAPE ABUTMENT ;
    PORT
      LAYER M1 ;
        RECT 0 0.261 0.864 0.279 ;
    END
  END VDD
  PIN VSS
    DIRECTION INOUT ;
    USE GROUND ;
    SHAPE ABUTMENT ;
    PORT
      LAYER M1 ;
        RECT 0 -0.009 0.864 0.009 ;
    END
  END VSS
  PIN Y
    DIRECTION OUTPUT ;
    USE SIGNAL ;
    PORT
      LAYER M1 ;
        RECT 0.741 0.225 0.846 0.243 ;
        RECT 0.828 0.027 0.846 0.243 ;
        RECT 0.742 0.027 0.846 0.045 ;
    END
  END Y
  OBS
    LAYER M1 ;
      RECT 0 0 0 0 ;
  END
END AO31x2_bottom

MACRO AO322x2_bottom
  CLASS CORE ;
  ORIGIN 0 0 ;
  FOREIGN AO322x2_bottom 0 0 ;
  SIZE 0.054 BY 0.270 ;
  SYMMETRY X Y ;
  SITE asap7sc7p5t ;
  PIN A1
    DIRECTION INPUT ;
    USE SIGNAL ;
    PORT
      LAYER M1 ;
        RECT 0.018 0.126 0.095 0.144 ;
        RECT 0.018 0.225 0.055 0.243 ;
        RECT 0.018 0.063 0.055 0.081 ;
        RECT 0.018 0.063 0.036 0.243 ;
    END
  END A1
  PIN A2
    DIRECTION INPUT ;
    USE SIGNAL ;
    PORT
      LAYER M1 ;
        RECT 0.107 0.189 0.144 0.207 ;
        RECT 0.126 0.063 0.144 0.207 ;
        RECT 0.107 0.063 0.144 0.081 ;
    END
  END A2
  PIN A3
    DIRECTION INPUT ;
    USE SIGNAL ;
    PORT
      LAYER M1 ;
        RECT 0.18 0.07 0.198 0.164 ;
    END
  END A3
  PIN B1
    DIRECTION INPUT ;
    USE SIGNAL ;
    PORT
      LAYER M1 ;
        RECT 0.288 0.153 0.325 0.171 ;
        RECT 0.288 0.063 0.325 0.081 ;
        RECT 0.288 0.063 0.306 0.171 ;
    END
  END B1
  PIN B2
    DIRECTION INPUT ;
    USE SIGNAL ;
    PORT
      LAYER M1 ;
        RECT 0.234 0.07 0.252 0.164 ;
    END
  END B2
  PIN C1
    DIRECTION INPUT ;
    USE SIGNAL ;
    PORT
      LAYER M1 ;
        RECT 0.45 0.07 0.468 0.164 ;
    END
  END C1
  PIN C2
    DIRECTION INPUT ;
    USE SIGNAL ;
    PORT
      LAYER M1 ;
        RECT 0.504 0.063 0.541 0.081 ;
        RECT 0.504 0.063 0.522 0.164 ;
    END
  END C2
  PIN VDD
    DIRECTION INOUT ;
    USE POWER ;
    SHAPE ABUTMENT ;
    PORT
      LAYER M1 ;
        RECT 0 0.261 0.81 0.279 ;
    END
  END VDD
  PIN VSS
    DIRECTION INOUT ;
    USE GROUND ;
    SHAPE ABUTMENT ;
    PORT
      LAYER M1 ;
        RECT 0 -0.009 0.81 0.009 ;
    END
  END VSS
  PIN Y
    DIRECTION OUTPUT ;
    USE SIGNAL ;
    PORT
      LAYER M1 ;
        RECT 0.634 0.225 0.792 0.243 ;
        RECT 0.774 0.027 0.792 0.243 ;
        RECT 0.634 0.027 0.792 0.045 ;
    END
  END Y
  OBS
    LAYER M1 ;
      RECT 0 0 0 0 ;
  END
END AO322x2_bottom

MACRO AO32x1_bottom
  CLASS CORE ;
  ORIGIN 0 0 ;
  FOREIGN AO32x1_bottom 0 0 ;
  SIZE 0.054 BY 0.270 ;
  SYMMETRY X Y ;
  SITE asap7sc7p5t ;
  PIN A1
    DIRECTION INPUT ;
    USE SIGNAL ;
    PORT
      LAYER M1 ;
        RECT 0.234 0.07 0.252 0.2 ;
    END
  END A1
  PIN A2
    DIRECTION INPUT ;
    USE SIGNAL ;
    PORT
      LAYER M1 ;
        RECT 0.18 0.07 0.198 0.2 ;
    END
  END A2
  PIN A3
    DIRECTION INPUT ;
    USE SIGNAL ;
    PORT
      LAYER M1 ;
        RECT 0.126 0.07 0.144 0.2 ;
    END
  END A3
  PIN B1
    DIRECTION INPUT ;
    USE SIGNAL ;
    PORT
      LAYER M1 ;
        RECT 0.288 0.07 0.306 0.164 ;
    END
  END B1
  PIN B2
    DIRECTION INPUT ;
    USE SIGNAL ;
    PORT
      LAYER M1 ;
        RECT 0.342 0.07 0.36 0.164 ;
    END
  END B2
  PIN VDD
    DIRECTION INOUT ;
    USE POWER ;
    SHAPE ABUTMENT ;
    PORT
      LAYER M1 ;
        RECT 0 0.261 0.432 0.279 ;
    END
  END VDD
  PIN VSS
    DIRECTION INOUT ;
    USE GROUND ;
    SHAPE ABUTMENT ;
    PORT
      LAYER M1 ;
        RECT 0 -0.009 0.432 0.009 ;
    END
  END VSS
  PIN Y
    DIRECTION OUTPUT ;
    USE SIGNAL ;
    PORT
      LAYER M1 ;
        RECT 0.018 0.225 0.068 0.243 ;
        RECT 0.018 0.063 0.063 0.081 ;
        RECT 0.045 0.034 0.063 0.081 ;
        RECT 0.018 0.063 0.036 0.243 ;
    END
  END Y
  OBS
    LAYER M1 ;
      RECT 0 0 0 0 ;
  END
END AO32x1_bottom

MACRO AO32x2_bottom
  CLASS CORE ;
  ORIGIN 0 0 ;
  FOREIGN AO32x2_bottom 0 0 ;
  SIZE 0.054 BY 0.270 ;
  SYMMETRY X Y ;
  SITE asap7sc7p5t ;
  PIN A1
    DIRECTION INPUT ;
    USE SIGNAL ;
    PORT
      LAYER M1 ;
        RECT 0.288 0.189 0.33 0.207 ;
        RECT 0.288 0.07 0.306 0.207 ;
    END
  END A1
  PIN A2
    DIRECTION INPUT ;
    USE SIGNAL ;
    PORT
      LAYER M1 ;
        RECT 0.234 0.07 0.252 0.2 ;
    END
  END A2
  PIN A3
    DIRECTION INPUT ;
    USE SIGNAL ;
    PORT
      LAYER M1 ;
        RECT 0.18 0.07 0.198 0.2 ;
    END
  END A3
  PIN B1
    DIRECTION INPUT ;
    USE SIGNAL ;
    PORT
      LAYER M1 ;
        RECT 0.342 0.07 0.36 0.164 ;
    END
  END B1
  PIN B2
    DIRECTION INPUT ;
    USE SIGNAL ;
    PORT
      LAYER M1 ;
        RECT 0.396 0.07 0.414 0.164 ;
    END
  END B2
  PIN VDD
    DIRECTION INOUT ;
    USE POWER ;
    SHAPE ABUTMENT ;
    PORT
      LAYER M1 ;
        RECT 0 0.261 0.486 0.279 ;
    END
  END VDD
  PIN VSS
    DIRECTION INOUT ;
    USE GROUND ;
    SHAPE ABUTMENT ;
    PORT
      LAYER M1 ;
        RECT 0 -0.009 0.486 0.009 ;
    END
  END VSS
  PIN Y
    DIRECTION OUTPUT ;
    USE SIGNAL ;
    PORT
      LAYER M1 ;
        RECT 0.018 0.225 0.122 0.243 ;
        RECT 0.018 0.068 0.117 0.086 ;
        RECT 0.099 0.037 0.117 0.086 ;
        RECT 0.018 0.068 0.036 0.243 ;
    END
  END Y
  OBS
    LAYER M1 ;
      RECT 0 0 0 0 ;
  END
END AO32x2_bottom

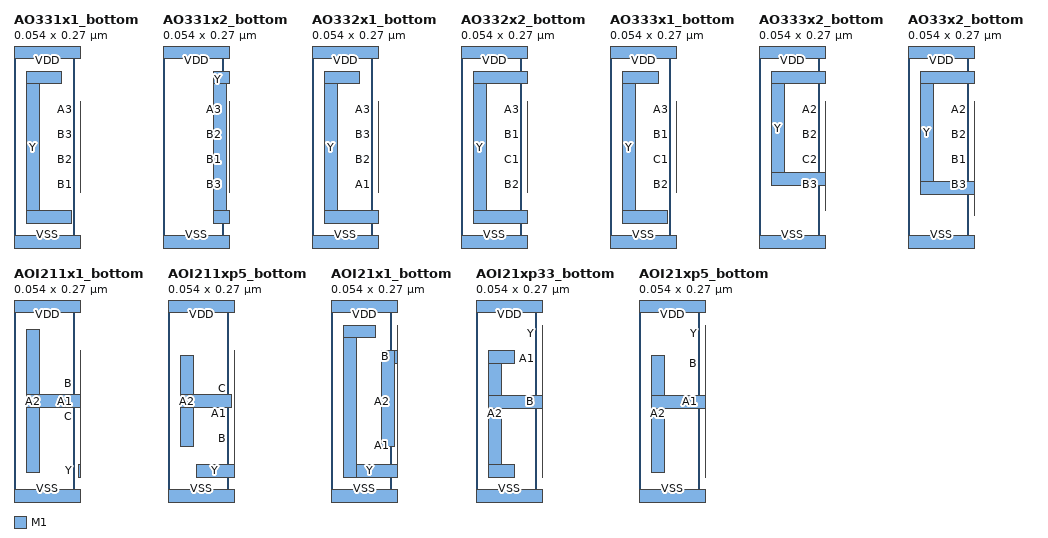
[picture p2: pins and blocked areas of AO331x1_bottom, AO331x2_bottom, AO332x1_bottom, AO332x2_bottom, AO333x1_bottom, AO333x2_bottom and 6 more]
MACRO AO331x1_bottom
  CLASS CORE ;
  ORIGIN 0 0 ;
  FOREIGN AO331x1_bottom 0 0 ;
  SIZE 0.054 BY 0.270 ;
  SYMMETRY X Y ;
  SITE asap7sc7p5t ;
  PIN A1
    DIRECTION INPUT ;
    USE SIGNAL ;
    PORT
      LAYER M1 ;
        RECT 0.234 0.07 0.252 0.2 ;
    END
  END A1
  PIN A2
    DIRECTION INPUT ;
    USE SIGNAL ;
    PORT
      LAYER M1 ;
        RECT 0.18 0.07 0.198 0.2 ;
    END
  END A2
  PIN A3
    DIRECTION INPUT ;
    USE SIGNAL ;
    PORT
      LAYER M1 ;
        RECT 0.126 0.106 0.144 0.2 ;
    END
  END A3
  PIN B1
    DIRECTION INPUT ;
    USE SIGNAL ;
    PORT
      LAYER M1 ;
        RECT 0.288 0.07 0.306 0.164 ;
    END
  END B1
  PIN B2
    DIRECTION INPUT ;
    USE SIGNAL ;
    PORT
      LAYER M1 ;
        RECT 0.342 0.07 0.36 0.164 ;
    END
  END B2
  PIN B3
    DIRECTION INPUT ;
    USE SIGNAL ;
    PORT
      LAYER M1 ;
        RECT 0.396 0.07 0.414 0.164 ;
    END
  END B3
  PIN C
    DIRECTION INPUT ;
    USE SIGNAL ;
    PORT
      LAYER M1 ;
        RECT 0.45 0.07 0.468 0.164 ;
    END
  END C
  PIN VDD
    DIRECTION INOUT ;
    USE POWER ;
    SHAPE ABUTMENT ;
    PORT
      LAYER M1 ;
        RECT 0 0.261 0.54 0.279 ;
    END
  END VDD
  PIN VSS
    DIRECTION INOUT ;
    USE GROUND ;
    SHAPE ABUTMENT ;
    PORT
      LAYER M1 ;
        RECT 0 -0.009 0.54 0.009 ;
    END
  END VSS
  PIN Y
    DIRECTION OUTPUT ;
    USE SIGNAL ;
    PORT
      LAYER M1 ;
        RECT 0.018 0.027 0.081 0.045 ;
        RECT 0.018 0.225 0.068 0.243 ;
        RECT 0.018 0.027 0.036 0.243 ;
    END
  END Y
  OBS
    LAYER M1 ;
      RECT 0 0 0 0 ;
  END
END AO331x1_bottom

MACRO AO331x2_bottom
  CLASS CORE ;
  ORIGIN 0 0 ;
  FOREIGN AO331x2_bottom 0 0 ;
  SIZE 0.054 BY 0.270 ;
  SYMMETRY X Y ;
  SITE asap7sc7p5t ;
  PIN A1
    DIRECTION INPUT ;
    USE SIGNAL ;
    PORT
      LAYER M1 ;
        RECT 0.288 0.07 0.306 0.2 ;
    END
  END A1
  PIN A2
    DIRECTION INPUT ;
    USE SIGNAL ;
    PORT
      LAYER M1 ;
        RECT 0.234 0.07 0.252 0.2 ;
    END
  END A2
  PIN A3
    DIRECTION INPUT ;
    USE SIGNAL ;
    PORT
      LAYER M1 ;
        RECT 0.18 0.106 0.198 0.2 ;
    END
  END A3
  PIN B1
    DIRECTION INPUT ;
    USE SIGNAL ;
    PORT
      LAYER M1 ;
        RECT 0.342 0.07 0.36 0.164 ;
    END
  END B1
  PIN B2
    DIRECTION INPUT ;
    USE SIGNAL ;
    PORT
      LAYER M1 ;
        RECT 0.396 0.07 0.414 0.164 ;
    END
  END B2
  PIN B3
    DIRECTION INPUT ;
    USE SIGNAL ;
    PORT
      LAYER M1 ;
        RECT 0.45 0.07 0.468 0.164 ;
    END
  END B3
  PIN C
    DIRECTION INPUT ;
    USE SIGNAL ;
    PORT
      LAYER M1 ;
        RECT 0.504 0.07 0.522 0.164 ;
    END
  END C
  PIN VDD
    DIRECTION INOUT ;
    USE POWER ;
    SHAPE ABUTMENT ;
    PORT
      LAYER M1 ;
        RECT 0 0.261 0.594 0.279 ;
    END
  END VDD
  PIN VSS
    DIRECTION INOUT ;
    USE GROUND ;
    SHAPE ABUTMENT ;
    PORT
      LAYER M1 ;
        RECT 0 -0.009 0.594 0.009 ;
    END
  END VSS
  PIN Y
    DIRECTION OUTPUT ;
    USE SIGNAL ;
    PORT
      LAYER M1 ;
        RECT 0.072 0.027 0.135 0.045 ;
        RECT 0.072 0.225 0.122 0.243 ;
        RECT 0.072 0.027 0.09 0.243 ;
    END
  END Y
  OBS
    LAYER M1 ;
      RECT 0 0 0 0 ;
  END
END AO331x2_bottom

MACRO AO332x1_bottom
  CLASS CORE ;
  ORIGIN 0 0 ;
  FOREIGN AO332x1_bottom 0 0 ;
  SIZE 0.054 BY 0.270 ;
  SYMMETRY X Y ;
  SITE asap7sc7p5t ;
  PIN A1
    DIRECTION INPUT ;
    USE SIGNAL ;
    PORT
      LAYER M1 ;
        RECT 0.234 0.07 0.252 0.164 ;
    END
  END A1
  PIN A2
    DIRECTION INPUT ;
    USE SIGNAL ;
    PORT
      LAYER M1 ;
        RECT 0.18 0.07 0.198 0.2 ;
    END
  END A2
  PIN A3
    DIRECTION INPUT ;
    USE SIGNAL ;
    PORT
      LAYER M1 ;
        RECT 0.126 0.106 0.144 0.2 ;
    END
  END A3
  PIN B1
    DIRECTION INPUT ;
    USE SIGNAL ;
    PORT
      LAYER M1 ;
        RECT 0.288 0.07 0.306 0.164 ;
    END
  END B1
  PIN B2
    DIRECTION INPUT ;
    USE SIGNAL ;
    PORT
      LAYER M1 ;
        RECT 0.342 0.07 0.36 0.164 ;
    END
  END B2
  PIN B3
    DIRECTION INPUT ;
    USE SIGNAL ;
    PORT
      LAYER M1 ;
        RECT 0.396 0.07 0.414 0.164 ;
    END
  END B3
  PIN C1
    DIRECTION INPUT ;
    USE SIGNAL ;
    PORT
      LAYER M1 ;
        RECT 0.504 0.07 0.522 0.164 ;
    END
  END C1
  PIN C2
    DIRECTION INPUT ;
    USE SIGNAL ;
    PORT
      LAYER M1 ;
        RECT 0.45 0.07 0.468 0.164 ;
    END
  END C2
  PIN VDD
    DIRECTION INOUT ;
    USE POWER ;
    SHAPE ABUTMENT ;
    PORT
      LAYER M1 ;
        RECT 0 0.261 0.594 0.279 ;
    END
  END VDD
  PIN VSS
    DIRECTION INOUT ;
    USE GROUND ;
    SHAPE ABUTMENT ;
    PORT
      LAYER M1 ;
        RECT 0 -0.009 0.594 0.009 ;
    END
  END VSS
  PIN Y
    DIRECTION OUTPUT ;
    USE SIGNAL ;
    PORT
      LAYER M1 ;
        RECT 0.018 0.027 0.094 0.045 ;
        RECT 0.018 0.225 0.068 0.243 ;
        RECT 0.018 0.027 0.036 0.243 ;
    END
  END Y
  OBS
    LAYER M1 ;
      RECT 0 0 0 0 ;
  END
END AO332x1_bottom

MACRO AO332x2_bottom
  CLASS CORE ;
  ORIGIN 0 0 ;
  FOREIGN AO332x2_bottom 0 0 ;
  SIZE 0.054 BY 0.270 ;
  SYMMETRY X Y ;
  SITE asap7sc7p5t ;
  PIN A1
    DIRECTION INPUT ;
    USE SIGNAL ;
    PORT
      LAYER M1 ;
        RECT 0.288 0.07 0.306 0.164 ;
    END
  END A1
  PIN A2
    DIRECTION INPUT ;
    USE SIGNAL ;
    PORT
      LAYER M1 ;
        RECT 0.234 0.07 0.252 0.2 ;
    END
  END A2
  PIN A3
    DIRECTION INPUT ;
    USE SIGNAL ;
    PORT
      LAYER M1 ;
        RECT 0.18 0.106 0.198 0.2 ;
    END
  END A3
  PIN B1
    DIRECTION INPUT ;
    USE SIGNAL ;
    PORT
      LAYER M1 ;
        RECT 0.342 0.07 0.36 0.164 ;
    END
  END B1
  PIN B2
    DIRECTION INPUT ;
    USE SIGNAL ;
    PORT
      LAYER M1 ;
        RECT 0.396 0.07 0.414 0.164 ;
    END
  END B2
  PIN B3
    DIRECTION INPUT ;
    USE SIGNAL ;
    PORT
      LAYER M1 ;
        RECT 0.45 0.07 0.468 0.164 ;
    END
  END B3
  PIN C1
    DIRECTION INPUT ;
    USE SIGNAL ;
    PORT
      LAYER M1 ;
        RECT 0.558 0.07 0.576 0.164 ;
    END
  END C1
  PIN C2
    DIRECTION INPUT ;
    USE SIGNAL ;
    PORT
      LAYER M1 ;
        RECT 0.504 0.07 0.522 0.164 ;
    END
  END C2
  PIN VDD
    DIRECTION INOUT ;
    USE POWER ;
    SHAPE ABUTMENT ;
    PORT
      LAYER M1 ;
        RECT 0 0.261 0.648 0.279 ;
    END
  END VDD
  PIN VSS
    DIRECTION INOUT ;
    USE GROUND ;
    SHAPE ABUTMENT ;
    PORT
      LAYER M1 ;
        RECT 0 -0.009 0.648 0.009 ;
    END
  END VSS
  PIN Y
    DIRECTION OUTPUT ;
    USE SIGNAL ;
    PORT
      LAYER M1 ;
        RECT 0.018 0.027 0.148 0.045 ;
        RECT 0.018 0.225 0.122 0.243 ;
        RECT 0.018 0.027 0.036 0.243 ;
    END
  END Y
  OBS
    LAYER M1 ;
      RECT 0 0 0 0 ;
  END
END AO332x2_bottom

MACRO AO333x1_bottom
  CLASS CORE ;
  ORIGIN 0 0 ;
  FOREIGN AO333x1_bottom 0 0 ;
  SIZE 0.054 BY 0.270 ;
  SYMMETRY X Y ;
  SITE asap7sc7p5t ;
  PIN A1
    DIRECTION INPUT ;
    USE SIGNAL ;
    PORT
      LAYER M1 ;
        RECT 0.234 0.07 0.252 0.2 ;
    END
  END A1
  PIN A2
    DIRECTION INPUT ;
    USE SIGNAL ;
    PORT
      LAYER M1 ;
        RECT 0.18 0.07 0.198 0.2 ;
    END
  END A2
  PIN A3
    DIRECTION INPUT ;
    USE SIGNAL ;
    PORT
      LAYER M1 ;
        RECT 0.126 0.106 0.144 0.2 ;
    END
  END A3
  PIN B1
    DIRECTION INPUT ;
    USE SIGNAL ;
    PORT
      LAYER M1 ;
        RECT 0.396 0.07 0.414 0.164 ;
    END
  END B1
  PIN B2
    DIRECTION INPUT ;
    USE SIGNAL ;
    PORT
      LAYER M1 ;
        RECT 0.342 0.07 0.36 0.164 ;
    END
  END B2
  PIN B3
    DIRECTION INPUT ;
    USE SIGNAL ;
    PORT
      LAYER M1 ;
        RECT 0.288 0.07 0.306 0.164 ;
    END
  END B3
  PIN C1
    DIRECTION INPUT ;
    USE SIGNAL ;
    PORT
      LAYER M1 ;
        RECT 0.558 0.07 0.576 0.164 ;
    END
  END C1
  PIN C2
    DIRECTION INPUT ;
    USE SIGNAL ;
    PORT
      LAYER M1 ;
        RECT 0.504 0.07 0.522 0.164 ;
    END
  END C2
  PIN C3
    DIRECTION INPUT ;
    USE SIGNAL ;
    PORT
      LAYER M1 ;
        RECT 0.45 0.07 0.468 0.164 ;
    END
  END C3
  PIN VDD
    DIRECTION INOUT ;
    USE POWER ;
    SHAPE ABUTMENT ;
    PORT
      LAYER M1 ;
        RECT 0 0.261 0.648 0.279 ;
    END
  END VDD
  PIN VSS
    DIRECTION INOUT ;
    USE GROUND ;
    SHAPE ABUTMENT ;
    PORT
      LAYER M1 ;
        RECT 0 -0.009 0.648 0.009 ;
    END
  END VSS
  PIN Y
    DIRECTION OUTPUT ;
    USE SIGNAL ;
    PORT
      LAYER M1 ;
        RECT 0.018 0.027 0.081 0.045 ;
        RECT 0.018 0.225 0.069 0.243 ;
        RECT 0.018 0.027 0.036 0.243 ;
    END
  END Y
  OBS
    LAYER M1 ;
      RECT 0 0 0 0 ;
  END
END AO333x1_bottom

MACRO AO333x2_bottom
  CLASS CORE ;
  ORIGIN 0 0 ;
  FOREIGN AO333x2_bottom 0 0 ;
  SIZE 0.054 BY 0.270 ;
  SYMMETRY X Y ;
  SITE asap7sc7p5t ;
  PIN A1
    DIRECTION INPUT ;
    USE SIGNAL ;
    PORT
      LAYER M1 ;
        RECT 0.288 0.07 0.306 0.2 ;
    END
  END A1
  PIN A2
    DIRECTION INPUT ;
    USE SIGNAL ;
    PORT
      LAYER M1 ;
        RECT 0.234 0.07 0.252 0.2 ;
    END
  END A2
  PIN A3
    DIRECTION INPUT ;
    USE SIGNAL ;
    PORT
      LAYER M1 ;
        RECT 0.18 0.07 0.198 0.2 ;
    END
  END A3
  PIN B1
    DIRECTION INPUT ;
    USE SIGNAL ;
    PORT
      LAYER M1 ;
        RECT 0.45 0.07 0.468 0.164 ;
    END
  END B1
  PIN B2
    DIRECTION INPUT ;
    USE SIGNAL ;
    PORT
      LAYER M1 ;
        RECT 0.396 0.07 0.414 0.164 ;
    END
  END B2
  PIN B3
    DIRECTION INPUT ;
    USE SIGNAL ;
    PORT
      LAYER M1 ;
        RECT 0.342 0.07 0.36 0.164 ;
    END
  END B3
  PIN C1
    DIRECTION INPUT ;
    USE SIGNAL ;
    PORT
      LAYER M1 ;
        RECT 0.612 0.07 0.63 0.164 ;
    END
  END C1
  PIN C2
    DIRECTION INPUT ;
    USE SIGNAL ;
    PORT
      LAYER M1 ;
        RECT 0.558 0.07 0.576 0.164 ;
    END
  END C2
  PIN C3
    DIRECTION INPUT ;
    USE SIGNAL ;
    PORT
      LAYER M1 ;
        RECT 0.504 0.07 0.522 0.164 ;
    END
  END C3
  PIN VDD
    DIRECTION INOUT ;
    USE POWER ;
    SHAPE ABUTMENT ;
    PORT
      LAYER M1 ;
        RECT 0 0.261 0.702 0.279 ;
    END
  END VDD
  PIN VSS
    DIRECTION INOUT ;
    USE GROUND ;
    SHAPE ABUTMENT ;
    PORT
      LAYER M1 ;
        RECT 0 -0.009 0.702 0.009 ;
    END
  END VSS
  PIN Y
    DIRECTION OUTPUT ;
    USE SIGNAL ;
    PORT
      LAYER M1 ;
        RECT 0.018 0.225 0.122 0.243 ;
        RECT 0.018 0.081 0.117 0.099 ;
        RECT 0.099 0.045 0.117 0.099 ;
        RECT 0.018 0.081 0.036 0.243 ;
    END
  END Y
  OBS
    LAYER M1 ;
      RECT 0 0 0 0 ;
  END
END AO333x2_bottom

MACRO AO33x2_bottom
  CLASS CORE ;
  ORIGIN 0 0 ;
  FOREIGN AO33x2_bottom 0 0 ;
  SIZE 0.054 BY 0.270 ;
  SYMMETRY X Y ;
  SITE asap7sc7p5t ;
  PIN A1
    DIRECTION INPUT ;
    USE SIGNAL ;
    PORT
      LAYER M1 ;
        RECT 0.288 0.07 0.306 0.2 ;
    END
  END A1
  PIN A2
    DIRECTION INPUT ;
    USE SIGNAL ;
    PORT
      LAYER M1 ;
        RECT 0.234 0.07 0.252 0.2 ;
    END
  END A2
  PIN A3
    DIRECTION INPUT ;
    USE SIGNAL ;
    PORT
      LAYER M1 ;
        RECT 0.18 0.07 0.198 0.2 ;
    END
  END A3
  PIN B1
    DIRECTION INPUT ;
    USE SIGNAL ;
    PORT
      LAYER M1 ;
        RECT 0.342 0.07 0.36 0.164 ;
    END
  END B1
  PIN B2
    DIRECTION INPUT ;
    USE SIGNAL ;
    PORT
      LAYER M1 ;
        RECT 0.396 0.07 0.414 0.164 ;
    END
  END B2
  PIN B3
    DIRECTION INPUT ;
    USE SIGNAL ;
    PORT
      LAYER M1 ;
        RECT 0.45 0.07 0.468 0.164 ;
    END
  END B3
  PIN VDD
    DIRECTION INOUT ;
    USE POWER ;
    SHAPE ABUTMENT ;
    PORT
      LAYER M1 ;
        RECT 0 0.261 0.54 0.279 ;
    END
  END VDD
  PIN VSS
    DIRECTION INOUT ;
    USE GROUND ;
    SHAPE ABUTMENT ;
    PORT
      LAYER M1 ;
        RECT 0 -0.009 0.54 0.009 ;
    END
  END VSS
  PIN Y
    DIRECTION OUTPUT ;
    USE SIGNAL ;
    PORT
      LAYER M1 ;
        RECT 0.018 0.225 0.122 0.243 ;
        RECT 0.018 0.068 0.117 0.086 ;
        RECT 0.099 0.037 0.117 0.086 ;
        RECT 0.018 0.068 0.036 0.243 ;
    END
  END Y
  OBS
    LAYER M1 ;
      RECT 0 0 0 0 ;
  END
END AO33x2_bottom

MACRO AOI211x1_bottom
  CLASS CORE ;
  ORIGIN 0 0 ;
  FOREIGN AOI211x1_bottom 0 0 ;
  SIZE 0.054 BY 0.270 ;
  SYMMETRY X Y ;
  SITE asap7sc7p5t ;
  PIN A1
    DIRECTION INPUT ;
    USE SIGNAL ;
    PORT
      LAYER M1 ;
        RECT 0.18 0.126 0.229 0.144 ;
        RECT 0.18 0.189 0.223 0.207 ;
        RECT 0.18 0.063 0.22 0.081 ;
        RECT 0.18 0.063 0.198 0.207 ;
    END
  END A1
  PIN A2
    DIRECTION INPUT ;
    USE SIGNAL ;
    PORT
      LAYER M1 ;
        RECT 0.018 0.126 0.123 0.144 ;
        RECT 0.018 0.034 0.036 0.236 ;
    END
  END A2
  PIN B
    DIRECTION INPUT ;
    USE SIGNAL ;
    PORT
      LAYER M1 ;
        RECT 0.396 0.153 0.442 0.171 ;
        RECT 0.396 0.063 0.442 0.081 ;
        RECT 0.396 0.063 0.414 0.171 ;
    END
  END B
  PIN C
    DIRECTION INPUT ;
    USE SIGNAL ;
    PORT
      LAYER M1 ;
        RECT 0.504 0.126 0.554 0.144 ;
        RECT 0.504 0.063 0.55 0.081 ;
        RECT 0.504 0.063 0.522 0.164 ;
    END
  END C
  PIN VDD
    DIRECTION INOUT ;
    USE POWER ;
    SHAPE ABUTMENT ;
    PORT
      LAYER M1 ;
        RECT 0 0.261 0.648 0.279 ;
    END
  END VDD
  PIN VSS
    DIRECTION INOUT ;
    USE GROUND ;
    SHAPE ABUTMENT ;
    PORT
      LAYER M1 ;
        RECT 0 -0.009 0.648 0.009 ;
    END
  END VSS
  PIN Y
    DIRECTION OUTPUT ;
    USE SIGNAL ;
    PORT
      LAYER M1 ;
        RECT 0.519 0.189 0.63 0.207 ;
        RECT 0.612 0.027 0.63 0.207 ;
        RECT 0.091 0.027 0.63 0.045 ;
    END
  END Y
  OBS
    LAYER M1 ;
      RECT 0 0 0 0 ;
  END
END AOI211x1_bottom

MACRO AOI211xp5_bottom
  CLASS CORE ;
  ORIGIN 0 0 ;
  FOREIGN AOI211xp5_bottom 0 0 ;
  SIZE 0.054 BY 0.270 ;
  SYMMETRY X Y ;
  SITE asap7sc7p5t ;
  PIN A1
    DIRECTION INPUT ;
    USE SIGNAL ;
    PORT
      LAYER M1 ;
        RECT 0.126 0.07 0.144 0.164 ;
    END
  END A1
  PIN A2
    DIRECTION INPUT ;
    USE SIGNAL ;
    PORT
      LAYER M1 ;
        RECT 0.018 0.126 0.09 0.144 ;
        RECT 0.018 0.07 0.036 0.2 ;
    END
  END A2
  PIN B
    DIRECTION INPUT ;
    USE SIGNAL ;
    PORT
      LAYER M1 ;
        RECT 0.18 0.07 0.198 0.164 ;
    END
  END B
  PIN C
    DIRECTION INPUT ;
    USE SIGNAL ;
    PORT
      LAYER M1 ;
        RECT 0.234 0.07 0.252 0.164 ;
    END
  END C
  PIN VDD
    DIRECTION INOUT ;
    USE POWER ;
    SHAPE ABUTMENT ;
    PORT
      LAYER M1 ;
        RECT 0 0.261 0.324 0.279 ;
    END
  END VDD
  PIN VSS
    DIRECTION INOUT ;
    USE GROUND ;
    SHAPE ABUTMENT ;
    PORT
      LAYER M1 ;
        RECT 0 -0.009 0.324 0.009 ;
    END
  END VSS
  PIN Y
    DIRECTION OUTPUT ;
    USE SIGNAL ;
    PORT
      LAYER M1 ;
        RECT 0.099 0.189 0.306 0.207 ;
        RECT 0.288 0.027 0.306 0.207 ;
        RECT 0.04 0.027 0.306 0.045 ;
    END
  END Y
  OBS
    LAYER M1 ;
      RECT 0 0 0 0 ;
  END
END AOI211xp5_bottom

MACRO AOI21x1_bottom
  CLASS CORE ;
  ORIGIN 0 0 ;
  FOREIGN AOI21x1_bottom 0 0 ;
  SIZE 0.054 BY 0.270 ;
  SYMMETRY X Y ;
  SITE asap7sc7p5t ;
  PIN A1
    DIRECTION INPUT ;
    USE SIGNAL ;
    PORT
      LAYER M1 ;
        RECT 0.288 0.063 0.306 0.164 ;
        RECT 0.126 0.063 0.306 0.081 ;
        RECT 0.126 0.063 0.144 0.164 ;
    END
  END A1
  PIN A2
    DIRECTION INPUT ;
    USE SIGNAL ;
    PORT
      LAYER M1 ;
        RECT 0.19 0.125 0.256 0.143 ;
        RECT 0.19 0.099 0.227 0.171 ;
    END
  END A2
  PIN B
    DIRECTION INPUT ;
    USE SIGNAL ;
    PORT
      LAYER M1 ;
        RECT 0.072 0.189 0.36 0.207 ;
        RECT 0.342 0.116 0.36 0.207 ;
        RECT 0.072 0.07 0.09 0.207 ;
    END
  END B
  PIN VDD
    DIRECTION INOUT ;
    USE POWER ;
    SHAPE ABUTMENT ;
    PORT
      LAYER M1 ;
        RECT 0 0.261 0.432 0.279 ;
    END
  END VDD
  PIN VSS
    DIRECTION INOUT ;
    USE GROUND ;
    SHAPE ABUTMENT ;
    PORT
      LAYER M1 ;
        RECT 0 -0.009 0.432 0.009 ;
    END
  END VSS
  PIN Y
    DIRECTION OUTPUT ;
    USE SIGNAL ;
    PORT
      LAYER M1 ;
        RECT 0.369 0.225 0.414 0.243 ;
        RECT 0.396 0.027 0.414 0.243 ;
        RECT 0.018 0.027 0.414 0.045 ;
        RECT 0.018 0.225 0.063 0.243 ;
        RECT 0.018 0.027 0.036 0.243 ;
    END
  END Y
  OBS
    LAYER M1 ;
      RECT 0 0 0 0 ;
  END
END AOI21x1_bottom

MACRO AOI21xp33_bottom
  CLASS CORE ;
  ORIGIN 0 0 ;
  FOREIGN AOI21xp33_bottom 0 0 ;
  SIZE 0.054 BY 0.270 ;
  SYMMETRY X Y ;
  SITE asap7sc7p5t ;
  PIN A1
    DIRECTION INPUT ;
    USE SIGNAL ;
    PORT
      LAYER M1 ;
        RECT 0.107 0.189 0.144 0.207 ;
        RECT 0.126 0.063 0.144 0.207 ;
        RECT 0.107 0.063 0.144 0.081 ;
    END
  END A1
  PIN A2
    DIRECTION INPUT ;
    USE SIGNAL ;
    PORT
      LAYER M1 ;
        RECT 0.018 0.125 0.095 0.143 ;
        RECT 0.018 0.189 0.055 0.207 ;
        RECT 0.018 0.027 0.055 0.045 ;
        RECT 0.018 0.027 0.036 0.207 ;
    END
  END A2
  PIN B
    DIRECTION INPUT ;
    USE SIGNAL ;
    PORT
      LAYER M1 ;
        RECT 0.18 0.07 0.198 0.2 ;
    END
  END B
  PIN VDD
    DIRECTION INOUT ;
    USE POWER ;
    SHAPE ABUTMENT ;
    PORT
      LAYER M1 ;
        RECT 0 0.261 0.27 0.279 ;
    END
  END VDD
  PIN VSS
    DIRECTION INOUT ;
    USE GROUND ;
    SHAPE ABUTMENT ;
    PORT
      LAYER M1 ;
        RECT 0 -0.009 0.27 0.009 ;
    END
  END VSS
  PIN Y
    DIRECTION OUTPUT ;
    USE SIGNAL ;
    PORT
      LAYER M1 ;
        RECT 0.202 0.225 0.252 0.243 ;
        RECT 0.234 0.027 0.252 0.243 ;
        RECT 0.107 0.027 0.252 0.045 ;
    END
  END Y
  OBS
    LAYER M1 ;
      RECT 0 0 0 0 ;
  END
END AOI21xp33_bottom

MACRO AOI21xp5_bottom
  CLASS CORE ;
  ORIGIN 0 0 ;
  FOREIGN AOI21xp5_bottom 0 0 ;
  SIZE 0.054 BY 0.270 ;
  SYMMETRY X Y ;
  SITE asap7sc7p5t ;
  PIN A1
    DIRECTION INPUT ;
    USE SIGNAL ;
    PORT
      LAYER M1 ;
        RECT 0.126 0.07 0.144 0.2 ;
    END
  END A1
  PIN A2
    DIRECTION INPUT ;
    USE SIGNAL ;
    PORT
      LAYER M1 ;
        RECT 0.018 0.125 0.095 0.143 ;
        RECT 0.018 0.034 0.036 0.2 ;
    END
  END A2
  PIN B
    DIRECTION INPUT ;
    USE SIGNAL ;
    PORT
      LAYER M1 ;
        RECT 0.18 0.07 0.198 0.2 ;
    END
  END B
  PIN VDD
    DIRECTION INOUT ;
    USE POWER ;
    SHAPE ABUTMENT ;
    PORT
      LAYER M1 ;
        RECT 0 0.261 0.27 0.279 ;
    END
  END VDD
  PIN VSS
    DIRECTION INOUT ;
    USE GROUND ;
    SHAPE ABUTMENT ;
    PORT
      LAYER M1 ;
        RECT 0 -0.009 0.27 0.009 ;
    END
  END VSS
  PIN Y
    DIRECTION OUTPUT ;
    USE SIGNAL ;
    PORT
      LAYER M1 ;
        RECT 0.202 0.225 0.252 0.243 ;
        RECT 0.234 0.027 0.252 0.243 ;
        RECT 0.142 0.027 0.252 0.045 ;
    END
  END Y
  OBS
    LAYER M1 ;
      RECT 0 0 0 0 ;
  END
END AOI21xp5_bottom

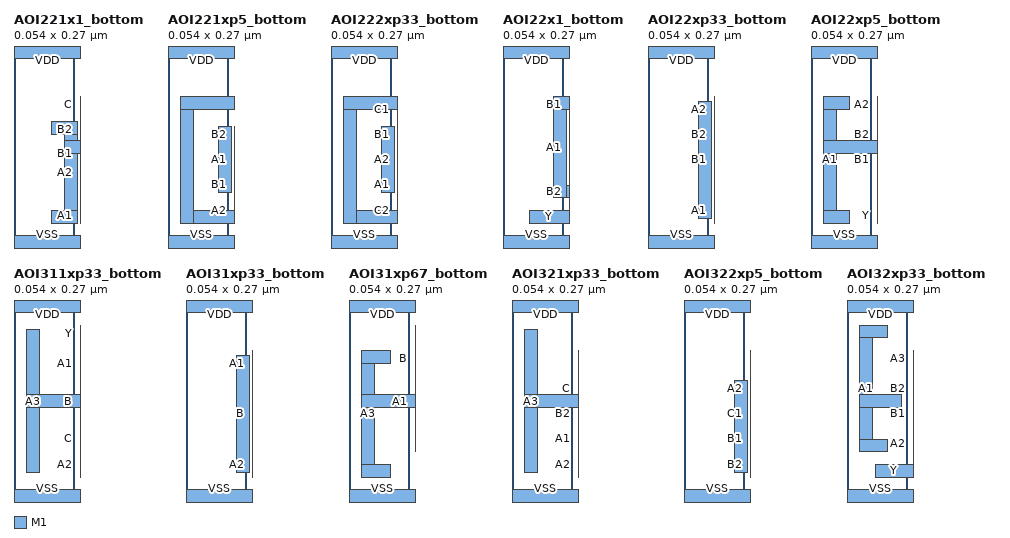
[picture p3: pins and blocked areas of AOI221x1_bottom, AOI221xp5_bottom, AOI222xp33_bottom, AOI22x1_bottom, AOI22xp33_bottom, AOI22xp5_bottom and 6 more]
MACRO AOI221x1_bottom
  CLASS CORE ;
  ORIGIN 0 0 ;
  FOREIGN AOI221x1_bottom 0 0 ;
  SIZE 0.054 BY 0.270 ;
  SYMMETRY X Y ;
  SITE asap7sc7p5t ;
  PIN A1
    DIRECTION INPUT ;
    USE SIGNAL ;
    PORT
      LAYER M1 ;
        RECT 0.18 0.153 0.217 0.171 ;
        RECT 0.18 0.027 0.198 0.171 ;
        RECT 0.161 0.027 0.198 0.045 ;
    END
  END A1
  PIN A2
    DIRECTION INPUT ;
    USE SIGNAL ;
    PORT
      LAYER M1 ;
        RECT 0.072 0.126 0.149 0.144 ;
        RECT 0.053 0.153 0.09 0.171 ;
        RECT 0.072 0.027 0.09 0.171 ;
        RECT 0.053 0.027 0.09 0.045 ;
    END
  END A2
  PIN B1
    DIRECTION INPUT ;
    USE SIGNAL ;
    PORT
      LAYER M1 ;
        RECT 0.288 0.081 0.325 0.099 ;
        RECT 0.269 0.153 0.306 0.171 ;
        RECT 0.288 0.081 0.306 0.171 ;
    END
  END B1
  PIN B2
    DIRECTION INPUT ;
    USE SIGNAL ;
    PORT
      LAYER M1 ;
        RECT 0.45 0.153 0.487 0.171 ;
        RECT 0.45 0.081 0.468 0.171 ;
        RECT 0.391 0.126 0.468 0.144 ;
        RECT 0.431 0.081 0.468 0.099 ;
    END
  END B2
  PIN C
    DIRECTION INPUT ;
    USE SIGNAL ;
    PORT
      LAYER M1 ;
        RECT 0.558 0.126 0.636 0.144 ;
        RECT 0.539 0.189 0.576 0.207 ;
        RECT 0.558 0.081 0.576 0.207 ;
        RECT 0.539 0.081 0.576 0.099 ;
    END
  END C
  PIN VDD
    DIRECTION INOUT ;
    USE POWER ;
    SHAPE ABUTMENT ;
    PORT
      LAYER M1 ;
        RECT 0 0.261 0.756 0.279 ;
    END
  END VDD
  PIN VSS
    DIRECTION INOUT ;
    USE GROUND ;
    SHAPE ABUTMENT ;
    PORT
      LAYER M1 ;
        RECT 0 -0.009 0.756 0.009 ;
    END
  END VSS
  PIN Y
    DIRECTION OUTPUT ;
    USE SIGNAL ;
    PORT
      LAYER M1 ;
        RECT 0.634 0.189 0.738 0.207 ;
        RECT 0.72 0.045 0.738 0.207 ;
        RECT 0.256 0.045 0.738 0.063 ;
    END
  END Y
  OBS
    LAYER M1 ;
      RECT 0 0 0 0 ;
  END
END AOI221x1_bottom

MACRO AOI221xp5_bottom
  CLASS CORE ;
  ORIGIN 0 0 ;
  FOREIGN AOI221xp5_bottom 0 0 ;
  SIZE 0.054 BY 0.270 ;
  SYMMETRY X Y ;
  SITE asap7sc7p5t ;
  PIN A1
    DIRECTION INPUT ;
    USE SIGNAL ;
    PORT
      LAYER M1 ;
        RECT 0.234 0.07 0.252 0.164 ;
    END
  END A1
  PIN A2
    DIRECTION INPUT ;
    USE SIGNAL ;
    PORT
      LAYER M1 ;
        RECT 0.288 0.034 0.306 0.164 ;
    END
  END A2
  PIN B1
    DIRECTION INPUT ;
    USE SIGNAL ;
    PORT
      LAYER M1 ;
        RECT 0.072 0.07 0.09 0.164 ;
    END
  END B1
  PIN B2
    DIRECTION INPUT ;
    USE SIGNAL ;
    PORT
      LAYER M1 ;
        RECT 0.126 0.07 0.144 0.164 ;
    END
  END B2
  PIN C
    DIRECTION INPUT ;
    USE SIGNAL ;
    PORT
      LAYER M1 ;
        RECT 0.18 0.07 0.198 0.164 ;
    END
  END C
  PIN VDD
    DIRECTION INOUT ;
    USE POWER ;
    SHAPE ABUTMENT ;
    PORT
      LAYER M1 ;
        RECT 0 0.261 0.378 0.279 ;
    END
  END VDD
  PIN VSS
    DIRECTION INOUT ;
    USE GROUND ;
    SHAPE ABUTMENT ;
    PORT
      LAYER M1 ;
        RECT 0 -0.009 0.378 0.009 ;
    END
  END VSS
  PIN Y
    DIRECTION OUTPUT ;
    USE SIGNAL ;
    PORT
      LAYER M1 ;
        RECT 0.018 0.027 0.23 0.045 ;
        RECT 0.018 0.189 0.123 0.207 ;
        RECT 0.018 0.027 0.036 0.207 ;
    END
  END Y
  OBS
    LAYER M1 ;
      RECT 0 0 0 0 ;
  END
END AOI221xp5_bottom

MACRO AOI222xp33_bottom
  CLASS CORE ;
  ORIGIN 0 0 ;
  FOREIGN AOI222xp33_bottom 0 0 ;
  SIZE 0.054 BY 0.270 ;
  SYMMETRY X Y ;
  SITE asap7sc7p5t ;
  PIN A1
    DIRECTION INPUT ;
    USE SIGNAL ;
    PORT
      LAYER M1 ;
        RECT 0.072 0.07 0.09 0.164 ;
    END
  END A1
  PIN A2
    DIRECTION INPUT ;
    USE SIGNAL ;
    PORT
      LAYER M1 ;
        RECT 0.126 0.07 0.144 0.164 ;
    END
  END A2
  PIN B1
    DIRECTION INPUT ;
    USE SIGNAL ;
    PORT
      LAYER M1 ;
        RECT 0.234 0.07 0.252 0.164 ;
    END
  END B1
  PIN B2
    DIRECTION INPUT ;
    USE SIGNAL ;
    PORT
      LAYER M1 ;
        RECT 0.18 0.07 0.198 0.164 ;
    END
  END B2
  PIN C1
    DIRECTION INPUT ;
    USE SIGNAL ;
    PORT
      LAYER M1 ;
        RECT 0.396 0.07 0.414 0.2 ;
    END
  END C1
  PIN C2
    DIRECTION INPUT ;
    USE SIGNAL ;
    PORT
      LAYER M1 ;
        RECT 0.45 0.034 0.468 0.2 ;
    END
  END C2
  PIN VDD
    DIRECTION INOUT ;
    USE POWER ;
    SHAPE ABUTMENT ;
    PORT
      LAYER M1 ;
        RECT 0 0.261 0.54 0.279 ;
    END
  END VDD
  PIN VSS
    DIRECTION INOUT ;
    USE GROUND ;
    SHAPE ABUTMENT ;
    PORT
      LAYER M1 ;
        RECT 0 -0.009 0.54 0.009 ;
    END
  END VSS
  PIN Y
    DIRECTION OUTPUT ;
    USE SIGNAL ;
    PORT
      LAYER M1 ;
        RECT 0.018 0.027 0.399 0.045 ;
        RECT 0.018 0.189 0.122 0.207 ;
        RECT 0.018 0.027 0.036 0.207 ;
    END
  END Y
  OBS
    LAYER M1 ;
      RECT 0 0 0 0 ;
  END
END AOI222xp33_bottom

MACRO AOI22x1_bottom
  CLASS CORE ;
  ORIGIN 0 0 ;
  FOREIGN AOI22x1_bottom 0 0 ;
  SIZE 0.054 BY 0.270 ;
  SYMMETRY X Y ;
  SITE asap7sc7p5t ;
  PIN A1
    DIRECTION INPUT ;
    USE SIGNAL ;
    PORT
      LAYER M1 ;
        RECT 0.342 0.153 0.379 0.171 ;
        RECT 0.342 0.099 0.379 0.117 ;
        RECT 0.342 0.099 0.36 0.171 ;
    END
  END A1
  PIN A2
    DIRECTION INPUT ;
    USE SIGNAL ;
    PORT
      LAYER M1 ;
        RECT 0.431 0.153 0.468 0.171 ;
        RECT 0.45 0.063 0.468 0.171 ;
        RECT 0.288 0.063 0.468 0.081 ;
        RECT 0.288 0.063 0.306 0.152 ;
    END
  END A2
  PIN B1
    DIRECTION INPUT ;
    USE SIGNAL ;
    PORT
      LAYER M1 ;
        RECT 0.161 0.189 0.198 0.207 ;
        RECT 0.18 0.099 0.198 0.207 ;
        RECT 0.161 0.099 0.198 0.117 ;
    END
  END B1
  PIN B2
    DIRECTION INPUT ;
    USE SIGNAL ;
    PORT
      LAYER M1 ;
        RECT 0.234 0.063 0.252 0.154 ;
        RECT 0.072 0.063 0.252 0.081 ;
        RECT 0.072 0.189 0.109 0.207 ;
        RECT 0.072 0.063 0.09 0.207 ;
    END
  END B2
  PIN VDD
    DIRECTION INOUT ;
    USE POWER ;
    SHAPE ABUTMENT ;
    PORT
      LAYER M1 ;
        RECT 0 0.261 0.54 0.279 ;
    END
  END VDD
  PIN VSS
    DIRECTION INOUT ;
    USE GROUND ;
    SHAPE ABUTMENT ;
    PORT
      LAYER M1 ;
        RECT 0 -0.009 0.54 0.009 ;
    END
  END VSS
  PIN Y
    DIRECTION OUTPUT ;
    USE SIGNAL ;
    PORT
      LAYER M1 ;
        RECT 0.309 0.189 0.522 0.207 ;
        RECT 0.504 0.027 0.522 0.207 ;
        RECT 0.038 0.027 0.522 0.045 ;
    END
  END Y
  OBS
    LAYER M1 ;
      RECT 0 0 0 0 ;
  END
END AOI22x1_bottom

MACRO AOI22xp33_bottom
  CLASS CORE ;
  ORIGIN 0 0 ;
  FOREIGN AOI22xp33_bottom 0 0 ;
  SIZE 0.054 BY 0.270 ;
  SYMMETRY X Y ;
  SITE asap7sc7p5t ;
  PIN A1
    DIRECTION INPUT ;
    USE SIGNAL ;
    PORT
      LAYER M1 ;
        RECT 0.072 0.034 0.09 0.2 ;
    END
  END A1
  PIN A2
    DIRECTION INPUT ;
    USE SIGNAL ;
    PORT
      LAYER M1 ;
        RECT 0.126 0.07 0.144 0.2 ;
    END
  END A2
  PIN B1
    DIRECTION INPUT ;
    USE SIGNAL ;
    PORT
      LAYER M1 ;
        RECT 0.234 0.07 0.252 0.164 ;
    END
  END B1
  PIN B2
    DIRECTION INPUT ;
    USE SIGNAL ;
    PORT
      LAYER M1 ;
        RECT 0.18 0.07 0.198 0.164 ;
    END
  END B2
  PIN VDD
    DIRECTION INOUT ;
    USE POWER ;
    SHAPE ABUTMENT ;
    PORT
      LAYER M1 ;
        RECT 0 0.261 0.324 0.279 ;
    END
  END VDD
  PIN VSS
    DIRECTION INOUT ;
    USE GROUND ;
    SHAPE ABUTMENT ;
    PORT
      LAYER M1 ;
        RECT 0 -0.009 0.324 0.009 ;
    END
  END VSS
  PIN Y
    DIRECTION OUTPUT ;
    USE SIGNAL ;
    PORT
      LAYER M1 ;
        RECT 0.202 0.189 0.306 0.207 ;
        RECT 0.288 0.027 0.306 0.207 ;
        RECT 0.148 0.027 0.306 0.045 ;
    END
  END Y
  OBS
    LAYER M1 ;
      RECT 0 0 0 0 ;
  END
END AOI22xp33_bottom

MACRO AOI22xp5_bottom
  CLASS CORE ;
  ORIGIN 0 0 ;
  FOREIGN AOI22xp5_bottom 0 0 ;
  SIZE 0.054 BY 0.270 ;
  SYMMETRY X Y ;
  SITE asap7sc7p5t ;
  PIN A1
    DIRECTION INPUT ;
    USE SIGNAL ;
    PORT
      LAYER M1 ;
        RECT 0.018 0.126 0.095 0.144 ;
        RECT 0.018 0.189 0.055 0.207 ;
        RECT 0.018 0.027 0.055 0.045 ;
        RECT 0.018 0.027 0.036 0.207 ;
    END
  END A1
  PIN A2
    DIRECTION INPUT ;
    USE SIGNAL ;
    PORT
      LAYER M1 ;
        RECT 0.107 0.189 0.144 0.207 ;
        RECT 0.126 0.07 0.144 0.207 ;
    END
  END A2
  PIN B1
    DIRECTION INPUT ;
    USE SIGNAL ;
    PORT
      LAYER M1 ;
        RECT 0.234 0.07 0.252 0.164 ;
    END
  END B1
  PIN B2
    DIRECTION INPUT ;
    USE SIGNAL ;
    PORT
      LAYER M1 ;
        RECT 0.18 0.07 0.198 0.164 ;
    END
  END B2
  PIN VDD
    DIRECTION INOUT ;
    USE POWER ;
    SHAPE ABUTMENT ;
    PORT
      LAYER M1 ;
        RECT 0 0.261 0.324 0.279 ;
    END
  END VDD
  PIN VSS
    DIRECTION INOUT ;
    USE GROUND ;
    SHAPE ABUTMENT ;
    PORT
      LAYER M1 ;
        RECT 0 -0.009 0.324 0.009 ;
    END
  END VSS
  PIN Y
    DIRECTION OUTPUT ;
    USE SIGNAL ;
    PORT
      LAYER M1 ;
        RECT 0.202 0.189 0.306 0.207 ;
        RECT 0.288 0.027 0.306 0.207 ;
        RECT 0.148 0.027 0.306 0.045 ;
    END
  END Y
  OBS
    LAYER M1 ;
      RECT 0 0 0 0 ;
  END
END AOI22xp5_bottom

MACRO AOI311xp33_bottom
  CLASS CORE ;
  ORIGIN 0 0 ;
  FOREIGN AOI311xp33_bottom 0 0 ;
  SIZE 0.054 BY 0.270 ;
  SYMMETRY X Y ;
  SITE asap7sc7p5t ;
  PIN A1
    DIRECTION INPUT ;
    USE SIGNAL ;
    PORT
      LAYER M1 ;
        RECT 0.18 0.07 0.198 0.2 ;
    END
  END A1
  PIN A2
    DIRECTION INPUT ;
    USE SIGNAL ;
    PORT
      LAYER M1 ;
        RECT 0.126 0.034 0.144 0.2 ;
    END
  END A2
  PIN A3
    DIRECTION INPUT ;
    USE SIGNAL ;
    PORT
      LAYER M1 ;
        RECT 0.018 0.126 0.095 0.144 ;
        RECT 0.018 0.034 0.036 0.236 ;
    END
  END A3
  PIN B
    DIRECTION INPUT ;
    USE SIGNAL ;
    PORT
      LAYER M1 ;
        RECT 0.234 0.07 0.252 0.2 ;
    END
  END B
  PIN C
    DIRECTION INPUT ;
    USE SIGNAL ;
    PORT
      LAYER M1 ;
        RECT 0.288 0.07 0.306 0.2 ;
    END
  END C
  PIN VDD
    DIRECTION INOUT ;
    USE POWER ;
    SHAPE ABUTMENT ;
    PORT
      LAYER M1 ;
        RECT 0 0.261 0.378 0.279 ;
    END
  END VDD
  PIN VSS
    DIRECTION INOUT ;
    USE GROUND ;
    SHAPE ABUTMENT ;
    PORT
      LAYER M1 ;
        RECT 0 -0.009 0.378 0.009 ;
    END
  END VSS
  PIN Y
    DIRECTION OUTPUT ;
    USE SIGNAL ;
    PORT
      LAYER M1 ;
        RECT 0.31 0.225 0.36 0.243 ;
        RECT 0.342 0.027 0.36 0.243 ;
        RECT 0.198 0.027 0.36 0.045 ;
    END
  END Y
  OBS
    LAYER M1 ;
      RECT 0 0 0 0 ;
  END
END AOI311xp33_bottom

MACRO AOI31xp33_bottom
  CLASS CORE ;
  ORIGIN 0 0 ;
  FOREIGN AOI31xp33_bottom 0 0 ;
  SIZE 0.054 BY 0.270 ;
  SYMMETRY X Y ;
  SITE asap7sc7p5t ;
  PIN A1
    DIRECTION INPUT ;
    USE SIGNAL ;
    PORT
      LAYER M1 ;
        RECT 0.18 0.07 0.198 0.2 ;
    END
  END A1
  PIN A2
    DIRECTION INPUT ;
    USE SIGNAL ;
    PORT
      LAYER M1 ;
        RECT 0.126 0.034 0.144 0.2 ;
    END
  END A2
  PIN A3
    DIRECTION INPUT ;
    USE SIGNAL ;
    PORT
      LAYER M1 ;
        RECT 0.072 0.034 0.09 0.2 ;
    END
  END A3
  PIN B
    DIRECTION INPUT ;
    USE SIGNAL ;
    PORT
      LAYER M1 ;
        RECT 0.234 0.07 0.252 0.164 ;
    END
  END B
  PIN VDD
    DIRECTION INOUT ;
    USE POWER ;
    SHAPE ABUTMENT ;
    PORT
      LAYER M1 ;
        RECT 0 0.261 0.324 0.279 ;
    END
  END VDD
  PIN VSS
    DIRECTION INOUT ;
    USE GROUND ;
    SHAPE ABUTMENT ;
    PORT
      LAYER M1 ;
        RECT 0 -0.009 0.324 0.009 ;
    END
  END VSS
  PIN Y
    DIRECTION OUTPUT ;
    USE SIGNAL ;
    PORT
      LAYER M1 ;
        RECT 0.256 0.189 0.306 0.207 ;
        RECT 0.288 0.027 0.306 0.207 ;
        RECT 0.201 0.027 0.306 0.045 ;
    END
  END Y
  OBS
    LAYER M1 ;
      RECT 0 0 0 0 ;
  END
END AOI31xp33_bottom

MACRO AOI31xp67_bottom
  CLASS CORE ;
  ORIGIN 0 0 ;
  FOREIGN AOI31xp67_bottom 0 0 ;
  SIZE 0.054 BY 0.270 ;
  SYMMETRY X Y ;
  SITE asap7sc7p5t ;
  PIN A1
    DIRECTION INPUT ;
    USE SIGNAL ;
    PORT
      LAYER M1 ;
        RECT 0.666 0.07 0.684 0.2 ;
        RECT 0.553 0.126 0.684 0.144 ;
    END
  END A1
  PIN A2
    DIRECTION INPUT ;
    USE SIGNAL ;
    PORT
      LAYER M1 ;
        RECT 0.288 0.126 0.419 0.144 ;
        RECT 0.288 0.063 0.325 0.081 ;
        RECT 0.288 0.063 0.306 0.164 ;
    END
  END A2
  PIN A3
    DIRECTION INPUT ;
    USE SIGNAL ;
    PORT
      LAYER M1 ;
        RECT 0.018 0.126 0.095 0.144 ;
        RECT 0.018 0.189 0.059 0.207 ;
        RECT 0.018 0.027 0.059 0.045 ;
        RECT 0.018 0.027 0.036 0.207 ;
    END
  END A3
  PIN B
    DIRECTION INPUT ;
    USE SIGNAL ;
    PORT
      LAYER M1 ;
        RECT 0.126 0.126 0.203 0.144 ;
        RECT 0.107 0.189 0.144 0.207 ;
        RECT 0.126 0.063 0.144 0.207 ;
        RECT 0.107 0.063 0.144 0.081 ;
    END
  END B
  PIN VDD
    DIRECTION INOUT ;
    USE POWER ;
    SHAPE ABUTMENT ;
    PORT
      LAYER M1 ;
        RECT 0 0.261 0.702 0.279 ;
    END
  END VDD
  PIN VSS
    DIRECTION INOUT ;
    USE GROUND ;
    SHAPE ABUTMENT ;
    PORT
      LAYER M1 ;
        RECT 0 -0.009 0.702 0.009 ;
    END
  END VSS
  PIN Y
    DIRECTION OUTPUT ;
    USE SIGNAL ;
    PORT
      LAYER M1 ;
        RECT 0.585 0.225 0.663 0.243 ;
        RECT 0.585 0.189 0.603 0.243 ;
        RECT 0.202 0.189 0.603 0.207 ;
        RECT 0.234 0.063 0.252 0.207 ;
        RECT 0.202 0.063 0.252 0.081 ;
    END
  END Y
  OBS
    LAYER M1 ;
      RECT 0 0 0 0 ;
  END
END AOI31xp67_bottom

MACRO AOI321xp33_bottom
  CLASS CORE ;
  ORIGIN 0 0 ;
  FOREIGN AOI321xp33_bottom 0 0 ;
  SIZE 0.054 BY 0.270 ;
  SYMMETRY X Y ;
  SITE asap7sc7p5t ;
  PIN A1
    DIRECTION INPUT ;
    USE SIGNAL ;
    PORT
      LAYER M1 ;
        RECT 0.18 0.07 0.198 0.164 ;
    END
  END A1
  PIN A2
    DIRECTION INPUT ;
    USE SIGNAL ;
    PORT
      LAYER M1 ;
        RECT 0.126 0.034 0.144 0.164 ;
    END
  END A2
  PIN A3
    DIRECTION INPUT ;
    USE SIGNAL ;
    PORT
      LAYER M1 ;
        RECT 0.018 0.126 0.095 0.144 ;
        RECT 0.018 0.034 0.036 0.236 ;
    END
  END A3
  PIN B1
    DIRECTION INPUT ;
    USE SIGNAL ;
    PORT
      LAYER M1 ;
        RECT 0.288 0.07 0.306 0.164 ;
    END
  END B1
  PIN B2
    DIRECTION INPUT ;
    USE SIGNAL ;
    PORT
      LAYER M1 ;
        RECT 0.342 0.07 0.36 0.164 ;
    END
  END B2
  PIN C
    DIRECTION INPUT ;
    USE SIGNAL ;
    PORT
      LAYER M1 ;
        RECT 0.234 0.07 0.252 0.164 ;
    END
  END C
  PIN VDD
    DIRECTION INOUT ;
    USE POWER ;
    SHAPE ABUTMENT ;
    PORT
      LAYER M1 ;
        RECT 0 0.261 0.432 0.279 ;
    END
  END VDD
  PIN VSS
    DIRECTION INOUT ;
    USE GROUND ;
    SHAPE ABUTMENT ;
    PORT
      LAYER M1 ;
        RECT 0 -0.009 0.432 0.009 ;
    END
  END VSS
  PIN Y
    DIRECTION OUTPUT ;
    USE SIGNAL ;
    PORT
      LAYER M1 ;
        RECT 0.31 0.189 0.414 0.207 ;
        RECT 0.396 0.027 0.414 0.207 ;
        RECT 0.198 0.027 0.414 0.045 ;
    END
  END Y
  OBS
    LAYER M1 ;
      RECT 0 0 0 0 ;
  END
END AOI321xp33_bottom

MACRO AOI322xp5_bottom
  CLASS CORE ;
  ORIGIN 0 0 ;
  FOREIGN AOI322xp5_bottom 0 0 ;
  SIZE 0.054 BY 0.270 ;
  SYMMETRY X Y ;
  SITE asap7sc7p5t ;
  PIN A1
    DIRECTION INPUT ;
    USE SIGNAL ;
    PORT
      LAYER M1 ;
        RECT 0.18 0.07 0.198 0.164 ;
    END
  END A1
  PIN A2
    DIRECTION INPUT ;
    USE SIGNAL ;
    PORT
      LAYER M1 ;
        RECT 0.234 0.07 0.252 0.164 ;
    END
  END A2
  PIN A3
    DIRECTION INPUT ;
    USE SIGNAL ;
    PORT
      LAYER M1 ;
        RECT 0.288 0.07 0.306 0.165 ;
    END
  END A3
  PIN B1
    DIRECTION INPUT ;
    USE SIGNAL ;
    PORT
      LAYER M1 ;
        RECT 0.126 0.07 0.144 0.164 ;
    END
  END B1
  PIN B2
    DIRECTION INPUT ;
    USE SIGNAL ;
    PORT
      LAYER M1 ;
        RECT 0.072 0.034 0.09 0.164 ;
    END
  END B2
  PIN C1
    DIRECTION INPUT ;
    USE SIGNAL ;
    PORT
      LAYER M1 ;
        RECT 0.396 0.07 0.414 0.164 ;
    END
  END C1
  PIN C2
    DIRECTION INPUT ;
    USE SIGNAL ;
    PORT
      LAYER M1 ;
        RECT 0.342 0.07 0.36 0.165 ;
    END
  END C2
  PIN VDD
    DIRECTION INOUT ;
    USE POWER ;
    SHAPE ABUTMENT ;
    PORT
      LAYER M1 ;
        RECT 0 0.261 0.486 0.279 ;
    END
  END VDD
  PIN VSS
    DIRECTION INOUT ;
    USE GROUND ;
    SHAPE ABUTMENT ;
    PORT
      LAYER M1 ;
        RECT 0 -0.009 0.486 0.009 ;
    END
  END VSS
  PIN Y
    DIRECTION OUTPUT ;
    USE SIGNAL ;
    PORT
      LAYER M1 ;
        RECT 0.364 0.189 0.468 0.207 ;
        RECT 0.45 0.027 0.468 0.207 ;
        RECT 0.147 0.027 0.468 0.045 ;
    END
  END Y
  OBS
    LAYER M1 ;
      RECT 0 0 0 0 ;
  END
END AOI322xp5_bottom

MACRO AOI32xp33_bottom
  CLASS CORE ;
  ORIGIN 0 0 ;
  FOREIGN AOI32xp33_bottom 0 0 ;
  SIZE 0.054 BY 0.270 ;
  SYMMETRY X Y ;
  SITE asap7sc7p5t ;
  PIN A1
    DIRECTION INPUT ;
    USE SIGNAL ;
    PORT
      LAYER M1 ;
        RECT 0.018 0.126 0.078 0.144 ;
        RECT 0.018 0.225 0.058 0.243 ;
        RECT 0.018 0.063 0.058 0.081 ;
        RECT 0.018 0.063 0.036 0.243 ;
    END
  END A1
  PIN A2
    DIRECTION INPUT ;
    USE SIGNAL ;
    PORT
      LAYER M1 ;
        RECT 0.104 0.189 0.144 0.207 ;
        RECT 0.126 0.063 0.144 0.207 ;
        RECT 0.104 0.063 0.144 0.081 ;
    END
  END A2
  PIN A3
    DIRECTION INPUT ;
    USE SIGNAL ;
    PORT
      LAYER M1 ;
        RECT 0.18 0.189 0.222 0.207 ;
        RECT 0.18 0.07 0.198 0.207 ;
    END
  END A3
  PIN B1
    DIRECTION INPUT ;
    USE SIGNAL ;
    PORT
      LAYER M1 ;
        RECT 0.234 0.07 0.252 0.164 ;
    END
  END B1
  PIN B2
    DIRECTION INPUT ;
    USE SIGNAL ;
    PORT
      LAYER M1 ;
        RECT 0.288 0.07 0.306 0.164 ;
    END
  END B2
  PIN VDD
    DIRECTION INOUT ;
    USE POWER ;
    SHAPE ABUTMENT ;
    PORT
      LAYER M1 ;
        RECT 0 0.261 0.378 0.279 ;
    END
  END VDD
  PIN VSS
    DIRECTION INOUT ;
    USE GROUND ;
    SHAPE ABUTMENT ;
    PORT
      LAYER M1 ;
        RECT 0 -0.009 0.378 0.009 ;
    END
  END VSS
  PIN Y
    DIRECTION OUTPUT ;
    USE SIGNAL ;
    PORT
      LAYER M1 ;
        RECT 0.256 0.189 0.36 0.207 ;
        RECT 0.342 0.027 0.36 0.207 ;
        RECT 0.04 0.027 0.36 0.045 ;
    END
  END Y
  OBS
    LAYER M1 ;
      RECT 0 0 0 0 ;
  END
END AOI32xp33_bottom

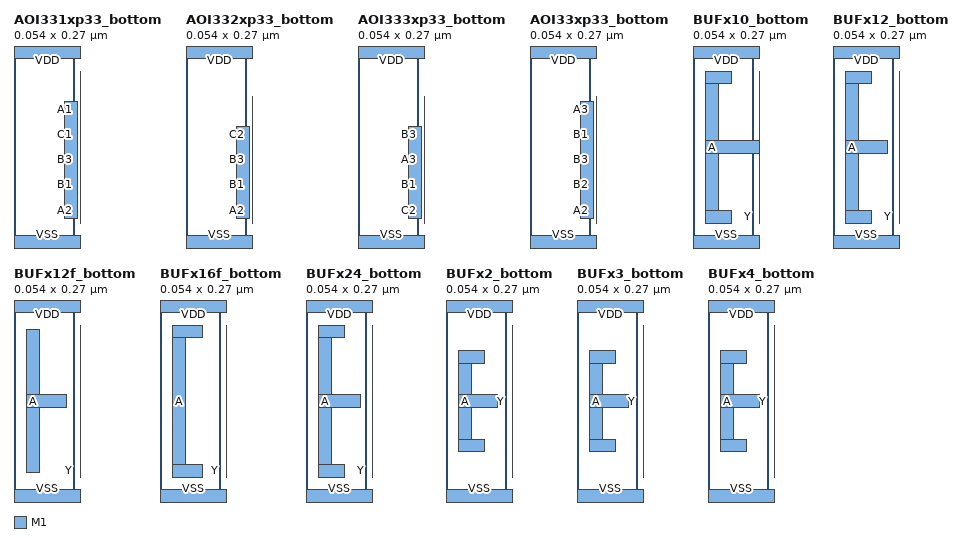
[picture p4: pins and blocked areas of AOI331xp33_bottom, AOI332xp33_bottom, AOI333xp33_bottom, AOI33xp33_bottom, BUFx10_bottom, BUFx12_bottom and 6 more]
MACRO AOI331xp33_bottom
  CLASS CORE ;
  ORIGIN 0 0 ;
  FOREIGN AOI331xp33_bottom 0 0 ;
  SIZE 0.054 BY 0.270 ;
  SYMMETRY X Y ;
  SITE asap7sc7p5t ;
  PIN A1
    DIRECTION INPUT ;
    USE SIGNAL ;
    PORT
      LAYER M1 ;
        RECT 0.18 0.07 0.198 0.2 ;
    END
  END A1
  PIN A2
    DIRECTION INPUT ;
    USE SIGNAL ;
    PORT
      LAYER M1 ;
        RECT 0.126 0.034 0.144 0.2 ;
    END
  END A2
  PIN A3
    DIRECTION INPUT ;
    USE SIGNAL ;
    PORT
      LAYER M1 ;
        RECT 0.072 0.034 0.09 0.2 ;
    END
  END A3
  PIN B1
    DIRECTION INPUT ;
    USE SIGNAL ;
    PORT
      LAYER M1 ;
        RECT 0.234 0.07 0.252 0.164 ;
    END
  END B1
  PIN B2
    DIRECTION INPUT ;
    USE SIGNAL ;
    PORT
      LAYER M1 ;
        RECT 0.288 0.07 0.306 0.164 ;
    END
  END B2
  PIN B3
    DIRECTION INPUT ;
    USE SIGNAL ;
    PORT
      LAYER M1 ;
        RECT 0.342 0.07 0.36 0.164 ;
    END
  END B3
  PIN C1
    DIRECTION INPUT ;
    USE SIGNAL ;
    PORT
      LAYER M1 ;
        RECT 0.396 0.07 0.414 0.164 ;
    END
  END C1
  PIN VDD
    DIRECTION INOUT ;
    USE POWER ;
    SHAPE ABUTMENT ;
    PORT
      LAYER M1 ;
        RECT 0 0.261 0.486 0.279 ;
    END
  END VDD
  PIN VSS
    DIRECTION INOUT ;
    USE GROUND ;
    SHAPE ABUTMENT ;
    PORT
      LAYER M1 ;
        RECT 0 -0.009 0.486 0.009 ;
    END
  END VSS
  PIN Y
    DIRECTION OUTPUT ;
    USE SIGNAL ;
    PORT
      LAYER M1 ;
        RECT 0.417 0.225 0.468 0.243 ;
        RECT 0.45 0.027 0.468 0.243 ;
        RECT 0.201 0.027 0.468 0.045 ;
    END
  END Y
  OBS
    LAYER M1 ;
      RECT 0 0 0 0 ;
  END
END AOI331xp33_bottom

MACRO AOI332xp33_bottom
  CLASS CORE ;
  ORIGIN 0 0 ;
  FOREIGN AOI332xp33_bottom 0 0 ;
  SIZE 0.054 BY 0.270 ;
  SYMMETRY X Y ;
  SITE asap7sc7p5t ;
  PIN A1
    DIRECTION INPUT ;
    USE SIGNAL ;
    PORT
      LAYER M1 ;
        RECT 0.18 0.07 0.198 0.164 ;
    END
  END A1
  PIN A2
    DIRECTION INPUT ;
    USE SIGNAL ;
    PORT
      LAYER M1 ;
        RECT 0.126 0.034 0.144 0.164 ;
    END
  END A2
  PIN A3
    DIRECTION INPUT ;
    USE SIGNAL ;
    PORT
      LAYER M1 ;
        RECT 0.072 0.034 0.09 0.164 ;
    END
  END A3
  PIN B1
    DIRECTION INPUT ;
    USE SIGNAL ;
    PORT
      LAYER M1 ;
        RECT 0.234 0.07 0.252 0.164 ;
    END
  END B1
  PIN B2
    DIRECTION INPUT ;
    USE SIGNAL ;
    PORT
      LAYER M1 ;
        RECT 0.288 0.07 0.306 0.164 ;
    END
  END B2
  PIN B3
    DIRECTION INPUT ;
    USE SIGNAL ;
    PORT
      LAYER M1 ;
        RECT 0.342 0.07 0.36 0.164 ;
    END
  END B3
  PIN C1
    DIRECTION INPUT ;
    USE SIGNAL ;
    PORT
      LAYER M1 ;
        RECT 0.45 0.07 0.468 0.164 ;
    END
  END C1
  PIN C2
    DIRECTION INPUT ;
    USE SIGNAL ;
    PORT
      LAYER M1 ;
        RECT 0.396 0.07 0.414 0.164 ;
    END
  END C2
  PIN VDD
    DIRECTION INOUT ;
    USE POWER ;
    SHAPE ABUTMENT ;
    PORT
      LAYER M1 ;
        RECT 0 0.261 0.54 0.279 ;
    END
  END VDD
  PIN VSS
    DIRECTION INOUT ;
    USE GROUND ;
    SHAPE ABUTMENT ;
    PORT
      LAYER M1 ;
        RECT 0 -0.009 0.54 0.009 ;
    END
  END VSS
  PIN Y
    DIRECTION OUTPUT ;
    USE SIGNAL ;
    PORT
      LAYER M1 ;
        RECT 0.417 0.189 0.522 0.207 ;
        RECT 0.504 0.027 0.522 0.207 ;
        RECT 0.201 0.027 0.522 0.045 ;
    END
  END Y
  OBS
    LAYER M1 ;
      RECT 0 0 0 0 ;
  END
END AOI332xp33_bottom

MACRO AOI333xp33_bottom
  CLASS CORE ;
  ORIGIN 0 0 ;
  FOREIGN AOI333xp33_bottom 0 0 ;
  SIZE 0.054 BY 0.270 ;
  SYMMETRY X Y ;
  SITE asap7sc7p5t ;
  PIN A1
    DIRECTION INPUT ;
    USE SIGNAL ;
    PORT
      LAYER M1 ;
        RECT 0.504 0.07 0.522 0.164 ;
    END
  END A1
  PIN A2
    DIRECTION INPUT ;
    USE SIGNAL ;
    PORT
      LAYER M1 ;
        RECT 0.45 0.07 0.468 0.164 ;
    END
  END A2
  PIN A3
    DIRECTION INPUT ;
    USE SIGNAL ;
    PORT
      LAYER M1 ;
        RECT 0.396 0.07 0.414 0.164 ;
    END
  END A3
  PIN B1
    DIRECTION INPUT ;
    USE SIGNAL ;
    PORT
      LAYER M1 ;
        RECT 0.234 0.07 0.252 0.164 ;
    END
  END B1
  PIN B2
    DIRECTION INPUT ;
    USE SIGNAL ;
    PORT
      LAYER M1 ;
        RECT 0.288 0.07 0.306 0.164 ;
    END
  END B2
  PIN B3
    DIRECTION INPUT ;
    USE SIGNAL ;
    PORT
      LAYER M1 ;
        RECT 0.342 0.07 0.36 0.164 ;
    END
  END B3
  PIN C1
    DIRECTION INPUT ;
    USE SIGNAL ;
    PORT
      LAYER M1 ;
        RECT 0.18 0.07 0.198 0.164 ;
    END
  END C1
  PIN C2
    DIRECTION INPUT ;
    USE SIGNAL ;
    PORT
      LAYER M1 ;
        RECT 0.126 0.034 0.144 0.164 ;
    END
  END C2
  PIN C3
    DIRECTION INPUT ;
    USE SIGNAL ;
    PORT
      LAYER M1 ;
        RECT 0.072 0.034 0.09 0.164 ;
    END
  END C3
  PIN VDD
    DIRECTION INOUT ;
    USE POWER ;
    SHAPE ABUTMENT ;
    PORT
      LAYER M1 ;
        RECT 0 0.261 0.594 0.279 ;
    END
  END VDD
  PIN VSS
    DIRECTION INOUT ;
    USE GROUND ;
    SHAPE ABUTMENT ;
    PORT
      LAYER M1 ;
        RECT 0 -0.009 0.594 0.009 ;
    END
  END VSS
  PIN Y
    DIRECTION OUTPUT ;
    USE SIGNAL ;
    PORT
      LAYER M1 ;
        RECT 0.413 0.189 0.576 0.207 ;
        RECT 0.558 0.027 0.576 0.207 ;
        RECT 0.201 0.027 0.576 0.045 ;
    END
  END Y
  OBS
    LAYER M1 ;
      RECT 0 0 0 0 ;
  END
END AOI333xp33_bottom

MACRO AOI33xp33_bottom
  CLASS CORE ;
  ORIGIN 0 0 ;
  FOREIGN AOI33xp33_bottom 0 0 ;
  SIZE 0.054 BY 0.270 ;
  SYMMETRY X Y ;
  SITE asap7sc7p5t ;
  PIN A1
    DIRECTION INPUT ;
    USE SIGNAL ;
    PORT
      LAYER M1 ;
        RECT 0.072 0.034 0.09 0.2 ;
    END
  END A1
  PIN A2
    DIRECTION INPUT ;
    USE SIGNAL ;
    PORT
      LAYER M1 ;
        RECT 0.126 0.034 0.144 0.2 ;
    END
  END A2
  PIN A3
    DIRECTION INPUT ;
    USE SIGNAL ;
    PORT
      LAYER M1 ;
        RECT 0.18 0.07 0.198 0.2 ;
    END
  END A3
  PIN B1
    DIRECTION INPUT ;
    USE SIGNAL ;
    PORT
      LAYER M1 ;
        RECT 0.234 0.07 0.252 0.164 ;
    END
  END B1
  PIN B2
    DIRECTION INPUT ;
    USE SIGNAL ;
    PORT
      LAYER M1 ;
        RECT 0.288 0.07 0.306 0.164 ;
    END
  END B2
  PIN B3
    DIRECTION INPUT ;
    USE SIGNAL ;
    PORT
      LAYER M1 ;
        RECT 0.342 0.07 0.36 0.164 ;
    END
  END B3
  PIN VDD
    DIRECTION INOUT ;
    USE POWER ;
    SHAPE ABUTMENT ;
    PORT
      LAYER M1 ;
        RECT 0 0.261 0.432 0.279 ;
    END
  END VDD
  PIN VSS
    DIRECTION INOUT ;
    USE GROUND ;
    SHAPE ABUTMENT ;
    PORT
      LAYER M1 ;
        RECT 0 -0.009 0.432 0.009 ;
    END
  END VSS
  PIN Y
    DIRECTION OUTPUT ;
    USE SIGNAL ;
    PORT
      LAYER M1 ;
        RECT 0.256 0.189 0.414 0.207 ;
        RECT 0.396 0.027 0.414 0.207 ;
        RECT 0.201 0.027 0.414 0.045 ;
    END
  END Y
  OBS
    LAYER M1 ;
      RECT 0 0 0 0 ;
  END
END AOI33xp33_bottom

MACRO BUFx10_bottom
  CLASS CORE ;
  ORIGIN 0 0 ;
  FOREIGN BUFx10_bottom 0 0 ;
  SIZE 0.054 BY 0.270 ;
  SYMMETRY X Y ;
  SITE asap7sc7p5t ;
  PIN A
    DIRECTION INPUT ;
    USE SIGNAL ;
    PORT
      LAYER M1 ;
        RECT 0.018 0.126 0.095 0.144 ;
        RECT 0.018 0.225 0.055 0.243 ;
        RECT 0.018 0.027 0.055 0.045 ;
        RECT 0.018 0.027 0.036 0.243 ;
    END
  END A
  PIN VDD
    DIRECTION INOUT ;
    USE POWER ;
    SHAPE ABUTMENT ;
    PORT
      LAYER M1 ;
        RECT 0 0.261 0.756 0.279 ;
    END
  END VDD
  PIN VSS
    DIRECTION INOUT ;
    USE GROUND ;
    SHAPE ABUTMENT ;
    PORT
      LAYER M1 ;
        RECT 0 -0.009 0.756 0.009 ;
    END
  END VSS
  PIN Y
    DIRECTION OUTPUT ;
    USE SIGNAL ;
    PORT
      LAYER M1 ;
        RECT 0.199 0.225 0.738 0.243 ;
        RECT 0.72 0.027 0.738 0.243 ;
        RECT 0.199 0.027 0.738 0.045 ;
    END
  END Y
  OBS
    LAYER M1 ;
      RECT 0 0 0 0 ;
  END
END BUFx10_bottom

MACRO BUFx12_bottom
  CLASS CORE ;
  ORIGIN 0 0 ;
  FOREIGN BUFx12_bottom 0 0 ;
  SIZE 0.054 BY 0.270 ;
  SYMMETRY X Y ;
  SITE asap7sc7p5t ;
  PIN A
    DIRECTION INPUT ;
    USE SIGNAL ;
    PORT
      LAYER M1 ;
        RECT 0.018 0.126 0.078 0.144 ;
        RECT 0.018 0.225 0.055 0.243 ;
        RECT 0.018 0.027 0.055 0.045 ;
        RECT 0.018 0.027 0.036 0.243 ;
    END
  END A
  PIN VDD
    DIRECTION INOUT ;
    USE POWER ;
    SHAPE ABUTMENT ;
    PORT
      LAYER M1 ;
        RECT 0 0.261 0.864 0.279 ;
    END
  END VDD
  PIN VSS
    DIRECTION INOUT ;
    USE GROUND ;
    SHAPE ABUTMENT ;
    PORT
      LAYER M1 ;
        RECT 0 -0.009 0.864 0.009 ;
    END
  END VSS
  PIN Y
    DIRECTION OUTPUT ;
    USE SIGNAL ;
    PORT
      LAYER M1 ;
        RECT 0.199 0.225 0.846 0.243 ;
        RECT 0.828 0.027 0.846 0.243 ;
        RECT 0.199 0.027 0.846 0.045 ;
    END
  END Y
  OBS
    LAYER M1 ;
      RECT 0 0 0 0 ;
  END
END BUFx12_bottom

MACRO BUFx12f_bottom
  CLASS CORE ;
  ORIGIN 0 0 ;
  FOREIGN BUFx12f_bottom 0 0 ;
  SIZE 0.054 BY 0.270 ;
  SYMMETRY X Y ;
  SITE asap7sc7p5t ;
  PIN A
    DIRECTION INPUT ;
    USE SIGNAL ;
    PORT
      LAYER M1 ;
        RECT 0.018 0.126 0.074 0.144 ;
        RECT 0.018 0.034 0.036 0.236 ;
    END
  END A
  PIN VDD
    DIRECTION INOUT ;
    USE POWER ;
    SHAPE ABUTMENT ;
    PORT
      LAYER M1 ;
        RECT 0 0.261 0.972 0.279 ;
    END
  END VDD
  PIN VSS
    DIRECTION INOUT ;
    USE GROUND ;
    SHAPE ABUTMENT ;
    PORT
      LAYER M1 ;
        RECT 0 -0.009 0.972 0.009 ;
    END
  END VSS
  PIN Y
    DIRECTION OUTPUT ;
    USE SIGNAL ;
    PORT
      LAYER M1 ;
        RECT 0.31 0.225 0.954 0.243 ;
        RECT 0.936 0.027 0.954 0.243 ;
        RECT 0.31 0.027 0.954 0.045 ;
    END
  END Y
  OBS
    LAYER M1 ;
      RECT 0 0 0 0 ;
  END
END BUFx12f_bottom

MACRO BUFx16f_bottom
  CLASS CORE ;
  ORIGIN 0 0 ;
  FOREIGN BUFx16f_bottom 0 0 ;
  SIZE 0.054 BY 0.270 ;
  SYMMETRY X Y ;
  SITE asap7sc7p5t ;
  PIN A
    DIRECTION INPUT ;
    USE SIGNAL ;
    PORT
      LAYER M1 ;
        RECT 0.018 0.225 0.06 0.243 ;
        RECT 0.018 0.027 0.06 0.045 ;
        RECT 0.018 0.027 0.036 0.243 ;
    END
  END A
  PIN VDD
    DIRECTION INOUT ;
    USE POWER ;
    SHAPE ABUTMENT ;
    PORT
      LAYER M1 ;
        RECT 0 0.261 1.188 0.279 ;
    END
  END VDD
  PIN VSS
    DIRECTION INOUT ;
    USE GROUND ;
    SHAPE ABUTMENT ;
    PORT
      LAYER M1 ;
        RECT 0 -0.009 1.188 0.009 ;
    END
  END VSS
  PIN Y
    DIRECTION OUTPUT ;
    USE SIGNAL ;
    PORT
      LAYER M1 ;
        RECT 0.31 0.225 1.17 0.243 ;
        RECT 1.152 0.027 1.17 0.243 ;
        RECT 0.31 0.027 1.17 0.045 ;
    END
  END Y
  OBS
    LAYER M1 ;
      RECT 0 0 0 0 ;
  END
END BUFx16f_bottom

MACRO BUFx24_bottom
  CLASS CORE ;
  ORIGIN 0 0 ;
  FOREIGN BUFx24_bottom 0 0 ;
  SIZE 0.054 BY 0.270 ;
  SYMMETRY X Y ;
  SITE asap7sc7p5t ;
  PIN A
    DIRECTION INPUT ;
    USE SIGNAL ;
    PORT
      LAYER M1 ;
        RECT 0.018 0.126 0.078 0.144 ;
        RECT 0.018 0.225 0.055 0.243 ;
        RECT 0.018 0.027 0.055 0.045 ;
        RECT 0.018 0.027 0.036 0.243 ;
    END
  END A
  PIN VDD
    DIRECTION INOUT ;
    USE POWER ;
    SHAPE ABUTMENT ;
    PORT
      LAYER M1 ;
        RECT 0 0.261 1.62 0.279 ;
    END
  END VDD
  PIN VSS
    DIRECTION INOUT ;
    USE GROUND ;
    SHAPE ABUTMENT ;
    PORT
      LAYER M1 ;
        RECT 0 -0.009 1.62 0.009 ;
    END
  END VSS
  PIN Y
    DIRECTION OUTPUT ;
    USE SIGNAL ;
    PORT
      LAYER M1 ;
        RECT 0.31 0.225 1.602 0.243 ;
        RECT 1.584 0.027 1.602 0.243 ;
        RECT 0.31 0.027 1.602 0.045 ;
    END
  END Y
  OBS
    LAYER M1 ;
      RECT 0 0 0 0 ;
  END
END BUFx24_bottom

MACRO BUFx2_bottom
  CLASS CORE ;
  ORIGIN 0 0 ;
  FOREIGN BUFx2_bottom 0 0 ;
  SIZE 0.054 BY 0.270 ;
  SYMMETRY X Y ;
  SITE asap7sc7p5t ;
  PIN A
    DIRECTION INPUT ;
    USE SIGNAL ;
    PORT
      LAYER M1 ;
        RECT 0.018 0.126 0.073 0.144 ;
        RECT 0.018 0.189 0.055 0.207 ;
        RECT 0.018 0.063 0.055 0.081 ;
        RECT 0.018 0.063 0.036 0.207 ;
    END
  END A
  PIN VDD
    DIRECTION INOUT ;
    USE POWER ;
    SHAPE ABUTMENT ;
    PORT
      LAYER M1 ;
        RECT 0 0.261 0.27 0.279 ;
    END
  END VDD
  PIN VSS
    DIRECTION INOUT ;
    USE GROUND ;
    SHAPE ABUTMENT ;
    PORT
      LAYER M1 ;
        RECT 0 -0.009 0.27 0.009 ;
    END
  END VSS
  PIN Y
    DIRECTION OUTPUT ;
    USE SIGNAL ;
    PORT
      LAYER M1 ;
        RECT 0.145 0.225 0.252 0.243 ;
        RECT 0.234 0.027 0.252 0.243 ;
        RECT 0.145 0.027 0.252 0.045 ;
    END
  END Y
  OBS
    LAYER M1 ;
      RECT 0 0 0 0 ;
  END
END BUFx2_bottom

MACRO BUFx3_bottom
  CLASS CORE ;
  ORIGIN 0 0 ;
  FOREIGN BUFx3_bottom 0 0 ;
  SIZE 0.054 BY 0.270 ;
  SYMMETRY X Y ;
  SITE asap7sc7p5t ;
  PIN A
    DIRECTION INPUT ;
    USE SIGNAL ;
    PORT
      LAYER M1 ;
        RECT 0.018 0.126 0.073 0.144 ;
        RECT 0.018 0.189 0.055 0.207 ;
        RECT 0.018 0.063 0.055 0.081 ;
        RECT 0.018 0.063 0.036 0.207 ;
    END
  END A
  PIN VDD
    DIRECTION INOUT ;
    USE POWER ;
    SHAPE ABUTMENT ;
    PORT
      LAYER M1 ;
        RECT 0 0.261 0.324 0.279 ;
    END
  END VDD
  PIN VSS
    DIRECTION INOUT ;
    USE GROUND ;
    SHAPE ABUTMENT ;
    PORT
      LAYER M1 ;
        RECT 0 -0.009 0.324 0.009 ;
    END
  END VSS
  PIN Y
    DIRECTION OUTPUT ;
    USE SIGNAL ;
    PORT
      LAYER M1 ;
        RECT 0.145 0.225 0.306 0.243 ;
        RECT 0.288 0.027 0.306 0.243 ;
        RECT 0.145 0.027 0.306 0.045 ;
    END
  END Y
  OBS
    LAYER M1 ;
      RECT 0 0 0 0 ;
  END
END BUFx3_bottom

MACRO BUFx4_bottom
  CLASS CORE ;
  ORIGIN 0 0 ;
  FOREIGN BUFx4_bottom 0 0 ;
  SIZE 0.054 BY 0.270 ;
  SYMMETRY X Y ;
  SITE asap7sc7p5t ;
  PIN A
    DIRECTION INPUT ;
    USE SIGNAL ;
    PORT
      LAYER M1 ;
        RECT 0.018 0.126 0.073 0.144 ;
        RECT 0.018 0.189 0.055 0.207 ;
        RECT 0.018 0.063 0.055 0.081 ;
        RECT 0.018 0.063 0.036 0.207 ;
    END
  END A
  PIN VDD
    DIRECTION INOUT ;
    USE POWER ;
    SHAPE ABUTMENT ;
    PORT
      LAYER M1 ;
        RECT 0 0.261 0.378 0.279 ;
    END
  END VDD
  PIN VSS
    DIRECTION INOUT ;
    USE GROUND ;
    SHAPE ABUTMENT ;
    PORT
      LAYER M1 ;
        RECT 0 -0.009 0.378 0.009 ;
    END
  END VSS
  PIN Y
    DIRECTION OUTPUT ;
    USE SIGNAL ;
    PORT
      LAYER M1 ;
        RECT 0.145 0.225 0.357 0.243 ;
        RECT 0.339 0.027 0.357 0.243 ;
        RECT 0.145 0.027 0.357 0.045 ;
    END
  END Y
  OBS
    LAYER M1 ;
      RECT 0 0 0 0 ;
  END
END BUFx4_bottom

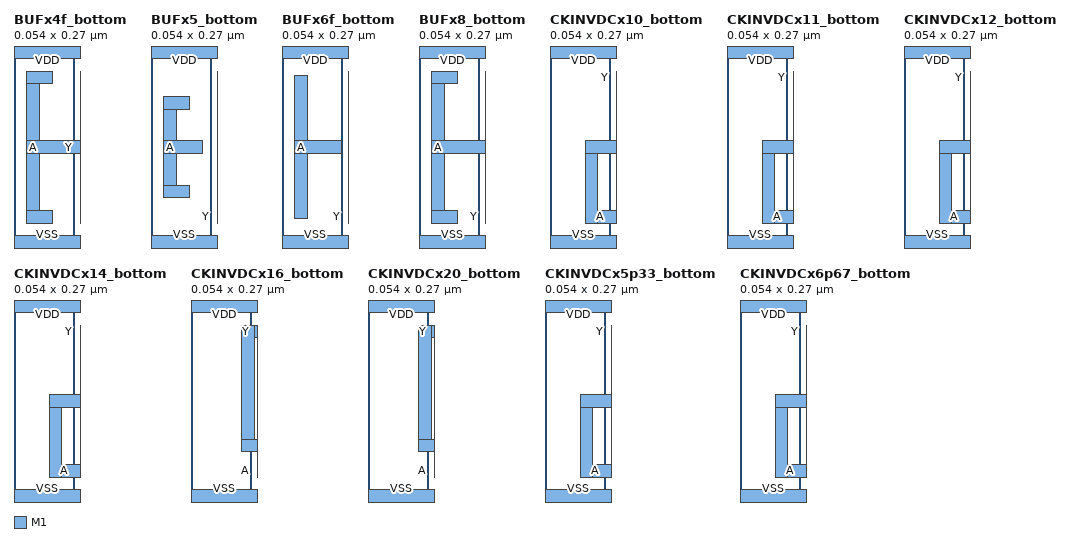
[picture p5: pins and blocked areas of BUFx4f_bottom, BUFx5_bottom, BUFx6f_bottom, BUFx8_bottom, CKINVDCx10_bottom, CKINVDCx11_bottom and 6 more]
MACRO BUFx4f_bottom
  CLASS CORE ;
  ORIGIN 0 0 ;
  FOREIGN BUFx4f_bottom 0 0 ;
  SIZE 0.054 BY 0.270 ;
  SYMMETRY X Y ;
  SITE asap7sc7p5t ;
  PIN A
    DIRECTION INPUT ;
    USE SIGNAL ;
    PORT
      LAYER M1 ;
        RECT 0.018 0.126 0.098 0.144 ;
        RECT 0.018 0.225 0.055 0.243 ;
        RECT 0.018 0.027 0.055 0.045 ;
        RECT 0.018 0.027 0.036 0.243 ;
    END
  END A
  PIN VDD
    DIRECTION INOUT ;
    USE POWER ;
    SHAPE ABUTMENT ;
    PORT
      LAYER M1 ;
        RECT 0 0.261 0.432 0.279 ;
    END
  END VDD
  PIN VSS
    DIRECTION INOUT ;
    USE GROUND ;
    SHAPE ABUTMENT ;
    PORT
      LAYER M1 ;
        RECT 0 -0.009 0.432 0.009 ;
    END
  END VSS
  PIN Y
    DIRECTION OUTPUT ;
    USE SIGNAL ;
    PORT
      LAYER M1 ;
        RECT 0.199 0.225 0.414 0.243 ;
        RECT 0.396 0.027 0.414 0.243 ;
        RECT 0.199 0.027 0.414 0.045 ;
    END
  END Y
  OBS
    LAYER M1 ;
      RECT 0 0 0 0 ;
  END
END BUFx4f_bottom

MACRO BUFx5_bottom
  CLASS CORE ;
  ORIGIN 0 0 ;
  FOREIGN BUFx5_bottom 0 0 ;
  SIZE 0.054 BY 0.270 ;
  SYMMETRY X Y ;
  SITE asap7sc7p5t ;
  PIN A
    DIRECTION INPUT ;
    USE SIGNAL ;
    PORT
      LAYER M1 ;
        RECT 0.018 0.126 0.073 0.144 ;
        RECT 0.018 0.189 0.055 0.207 ;
        RECT 0.018 0.063 0.055 0.081 ;
        RECT 0.018 0.063 0.036 0.207 ;
    END
  END A
  PIN VDD
    DIRECTION INOUT ;
    USE POWER ;
    SHAPE ABUTMENT ;
    PORT
      LAYER M1 ;
        RECT 0 0.261 0.432 0.279 ;
    END
  END VDD
  PIN VSS
    DIRECTION INOUT ;
    USE GROUND ;
    SHAPE ABUTMENT ;
    PORT
      LAYER M1 ;
        RECT 0 -0.009 0.432 0.009 ;
    END
  END VSS
  PIN Y
    DIRECTION OUTPUT ;
    USE SIGNAL ;
    PORT
      LAYER M1 ;
        RECT 0.145 0.225 0.414 0.243 ;
        RECT 0.396 0.027 0.414 0.243 ;
        RECT 0.145 0.027 0.414 0.045 ;
    END
  END Y
  OBS
    LAYER M1 ;
      RECT 0 0 0 0 ;
  END
END BUFx5_bottom

MACRO BUFx6f_bottom
  CLASS CORE ;
  ORIGIN 0 0 ;
  FOREIGN BUFx6f_bottom 0 0 ;
  SIZE 0.054 BY 0.270 ;
  SYMMETRY X Y ;
  SITE asap7sc7p5t ;
  PIN A
    DIRECTION INPUT ;
    USE SIGNAL ;
    PORT
      LAYER M1 ;
        RECT 0.018 0.126 0.084 0.144 ;
        RECT 0.018 0.034 0.036 0.236 ;
    END
  END A
  PIN VDD
    DIRECTION INOUT ;
    USE POWER ;
    SHAPE ABUTMENT ;
    PORT
      LAYER M1 ;
        RECT 0 0.261 0.54 0.279 ;
    END
  END VDD
  PIN VSS
    DIRECTION INOUT ;
    USE GROUND ;
    SHAPE ABUTMENT ;
    PORT
      LAYER M1 ;
        RECT 0 -0.009 0.54 0.009 ;
    END
  END VSS
  PIN Y
    DIRECTION OUTPUT ;
    USE SIGNAL ;
    PORT
      LAYER M1 ;
        RECT 0.202 0.225 0.522 0.243 ;
        RECT 0.504 0.027 0.522 0.243 ;
        RECT 0.202 0.027 0.522 0.045 ;
    END
  END Y
  OBS
    LAYER M1 ;
      RECT 0 0 0 0 ;
  END
END BUFx6f_bottom

MACRO BUFx8_bottom
  CLASS CORE ;
  ORIGIN 0 0 ;
  FOREIGN BUFx8_bottom 0 0 ;
  SIZE 0.054 BY 0.270 ;
  SYMMETRY X Y ;
  SITE asap7sc7p5t ;
  PIN A
    DIRECTION INPUT ;
    USE SIGNAL ;
    PORT
      LAYER M1 ;
        RECT 0.018 0.126 0.098 0.144 ;
        RECT 0.018 0.225 0.055 0.243 ;
        RECT 0.018 0.027 0.055 0.045 ;
        RECT 0.018 0.027 0.036 0.243 ;
    END
  END A
  PIN VDD
    DIRECTION INOUT ;
    USE POWER ;
    SHAPE ABUTMENT ;
    PORT
      LAYER M1 ;
        RECT 0 0.261 0.648 0.279 ;
    END
  END VDD
  PIN VSS
    DIRECTION INOUT ;
    USE GROUND ;
    SHAPE ABUTMENT ;
    PORT
      LAYER M1 ;
        RECT 0 -0.009 0.648 0.009 ;
    END
  END VSS
  PIN Y
    DIRECTION OUTPUT ;
    USE SIGNAL ;
    PORT
      LAYER M1 ;
        RECT 0.202 0.225 0.63 0.243 ;
        RECT 0.612 0.027 0.63 0.243 ;
        RECT 0.202 0.027 0.63 0.045 ;
    END
  END Y
  OBS
    LAYER M1 ;
      RECT 0 0 0 0 ;
  END
END BUFx8_bottom

MACRO CKINVDCx10_bottom
  CLASS CORE ;
  ORIGIN 0 0 ;
  FOREIGN CKINVDCx10_bottom 0 0 ;
  SIZE 0.054 BY 0.270 ;
  SYMMETRY X Y ;
  SITE asap7sc7p5t ;
  PIN A
    DIRECTION INPUT ;
    USE SIGNAL ;
    PORT
      LAYER M1 ;
        RECT 1.088 0.126 1.17 0.144 ;
        RECT 1.12 0.027 1.138 0.144 ;
        RECT 0.05 0.027 1.138 0.045 ;
        RECT 0.764 0.126 0.814 0.144 ;
        RECT 0.796 0.027 0.814 0.144 ;
        RECT 0.374 0.126 0.424 0.144 ;
        RECT 0.374 0.027 0.392 0.144 ;
        RECT 0.05 0.126 0.1 0.144 ;
        RECT 0.05 0.027 0.068 0.144 ;
    END
  END A
  PIN VDD
    DIRECTION INOUT ;
    USE POWER ;
    SHAPE ABUTMENT ;
    PORT
      LAYER M1 ;
        RECT 0 0.261 1.296 0.279 ;
    END
  END VDD
  PIN VSS
    DIRECTION INOUT ;
    USE GROUND ;
    SHAPE ABUTMENT ;
    PORT
      LAYER M1 ;
        RECT 0 -0.009 1.296 0.009 ;
    END
  END VSS
  PIN Y
    DIRECTION OUTPUT ;
    USE SIGNAL ;
    PORT
      LAYER M1 ;
        RECT 0.094 0.225 1.224 0.243 ;
        RECT 1.206 0.063 1.224 0.243 ;
        RECT 1.174 0.063 1.224 0.081 ;
        RECT 1.044 0.063 1.094 0.081 ;
        RECT 1.044 0.063 1.062 0.243 ;
        RECT 0.72 0.063 0.77 0.081 ;
        RECT 0.72 0.063 0.738 0.243 ;
        RECT 0.45 0.063 0.468 0.243 ;
        RECT 0.418 0.063 0.468 0.081 ;
        RECT 0.126 0.063 0.144 0.243 ;
        RECT 0.094 0.063 0.144 0.081 ;
    END
  END Y
  OBS
    LAYER M1 ;
      RECT 0 0 0 0 ;
  END
END CKINVDCx10_bottom

MACRO CKINVDCx11_bottom
  CLASS CORE ;
  ORIGIN 0 0 ;
  FOREIGN CKINVDCx11_bottom 0 0 ;
  SIZE 0.054 BY 0.270 ;
  SYMMETRY X Y ;
  SITE asap7sc7p5t ;
  PIN A
    DIRECTION INPUT ;
    USE SIGNAL ;
    PORT
      LAYER M1 ;
        RECT 1.304 0.126 1.354 0.144 ;
        RECT 1.336 0.027 1.354 0.144 ;
        RECT 0.05 0.027 1.354 0.045 ;
        RECT 0.872 0.126 0.964 0.144 ;
        RECT 0.909 0.027 0.927 0.144 ;
        RECT 0.439 0.126 0.531 0.144 ;
        RECT 0.476 0.027 0.494 0.144 ;
        RECT 0.05 0.126 0.1 0.144 ;
        RECT 0.05 0.027 0.068 0.144 ;
    END
  END A
  PIN VDD
    DIRECTION INOUT ;
    USE POWER ;
    SHAPE ABUTMENT ;
    PORT
      LAYER M1 ;
        RECT 0 0.261 1.404 0.279 ;
    END
  END VDD
  PIN VSS
    DIRECTION INOUT ;
    USE GROUND ;
    SHAPE ABUTMENT ;
    PORT
      LAYER M1 ;
        RECT 0 -0.009 1.404 0.009 ;
    END
  END VSS
  PIN Y
    DIRECTION OUTPUT ;
    USE SIGNAL ;
    PORT
      LAYER M1 ;
        RECT 0.094 0.225 1.31 0.243 ;
        RECT 1.26 0.063 1.31 0.081 ;
        RECT 1.26 0.063 1.278 0.243 ;
        RECT 0.99 0.063 1.008 0.243 ;
        RECT 0.958 0.063 1.008 0.081 ;
        RECT 0.828 0.063 0.878 0.081 ;
        RECT 0.828 0.063 0.846 0.243 ;
        RECT 0.558 0.063 0.576 0.243 ;
        RECT 0.526 0.063 0.576 0.081 ;
        RECT 0.396 0.063 0.446 0.081 ;
        RECT 0.396 0.063 0.414 0.243 ;
        RECT 0.126 0.063 0.144 0.243 ;
        RECT 0.094 0.063 0.144 0.081 ;
    END
  END Y
  OBS
    LAYER M1 ;
      RECT 0 0 0 0 ;
  END
END CKINVDCx11_bottom

MACRO CKINVDCx12_bottom
  CLASS CORE ;
  ORIGIN 0 0 ;
  FOREIGN CKINVDCx12_bottom 0 0 ;
  SIZE 0.054 BY 0.270 ;
  SYMMETRY X Y ;
  SITE asap7sc7p5t ;
  PIN A
    DIRECTION INPUT ;
    USE SIGNAL ;
    PORT
      LAYER M1 ;
        RECT 1.304 0.126 1.354 0.144 ;
        RECT 1.336 0.027 1.354 0.144 ;
        RECT 0.05 0.027 1.354 0.045 ;
        RECT 0.872 0.126 0.964 0.144 ;
        RECT 0.909 0.027 0.927 0.144 ;
        RECT 0.439 0.126 0.531 0.144 ;
        RECT 0.476 0.027 0.494 0.144 ;
        RECT 0.05 0.126 0.1 0.144 ;
        RECT 0.05 0.027 0.068 0.144 ;
    END
  END A
  PIN VDD
    DIRECTION INOUT ;
    USE POWER ;
    SHAPE ABUTMENT ;
    PORT
      LAYER M1 ;
        RECT 0 0.261 1.404 0.279 ;
    END
  END VDD
  PIN VSS
    DIRECTION INOUT ;
    USE GROUND ;
    SHAPE ABUTMENT ;
    PORT
      LAYER M1 ;
        RECT 0 -0.009 1.404 0.009 ;
    END
  END VSS
  PIN Y
    DIRECTION OUTPUT ;
    USE SIGNAL ;
    PORT
      LAYER M1 ;
        RECT 0.094 0.225 1.31 0.243 ;
        RECT 1.26 0.063 1.31 0.081 ;
        RECT 1.26 0.063 1.278 0.243 ;
        RECT 0.99 0.063 1.008 0.243 ;
        RECT 0.958 0.063 1.008 0.081 ;
        RECT 0.828 0.063 0.878 0.081 ;
        RECT 0.828 0.063 0.846 0.243 ;
        RECT 0.558 0.063 0.576 0.243 ;
        RECT 0.526 0.063 0.576 0.081 ;
        RECT 0.396 0.063 0.446 0.081 ;
        RECT 0.396 0.063 0.414 0.243 ;
        RECT 0.126 0.063 0.144 0.243 ;
        RECT 0.094 0.063 0.144 0.081 ;
    END
  END Y
  OBS
    LAYER M1 ;
      RECT 0 0 0 0 ;
  END
END CKINVDCx12_bottom

MACRO CKINVDCx14_bottom
  CLASS CORE ;
  ORIGIN 0 0 ;
  FOREIGN CKINVDCx14_bottom 0 0 ;
  SIZE 0.054 BY 0.270 ;
  SYMMETRY X Y ;
  SITE asap7sc7p5t ;
  PIN A
    DIRECTION INPUT ;
    USE SIGNAL ;
    PORT
      LAYER M1 ;
        RECT 1.304 0.126 1.397 0.144 ;
        RECT 1.336 0.027 1.354 0.144 ;
        RECT 0.05 0.027 1.354 0.045 ;
        RECT 0.872 0.126 0.964 0.144 ;
        RECT 0.909 0.027 0.927 0.144 ;
        RECT 0.439 0.126 0.531 0.144 ;
        RECT 0.476 0.027 0.494 0.144 ;
        RECT 0.05 0.126 0.1 0.144 ;
        RECT 0.05 0.027 0.068 0.144 ;
    END
  END A
  PIN VDD
    DIRECTION INOUT ;
    USE POWER ;
    SHAPE ABUTMENT ;
    PORT
      LAYER M1 ;
        RECT 0 0.261 1.512 0.279 ;
    END
  END VDD
  PIN VSS
    DIRECTION INOUT ;
    USE GROUND ;
    SHAPE ABUTMENT ;
    PORT
      LAYER M1 ;
        RECT 0 -0.009 1.512 0.009 ;
    END
  END VSS
  PIN Y
    DIRECTION OUTPUT ;
    USE SIGNAL ;
    PORT
      LAYER M1 ;
        RECT 0.094 0.225 1.44 0.243 ;
        RECT 1.422 0.063 1.44 0.243 ;
        RECT 1.39 0.063 1.44 0.081 ;
        RECT 1.26 0.063 1.31 0.081 ;
        RECT 1.26 0.063 1.278 0.243 ;
        RECT 0.99 0.063 1.008 0.243 ;
        RECT 0.958 0.063 1.008 0.081 ;
        RECT 0.828 0.063 0.878 0.081 ;
        RECT 0.828 0.063 0.846 0.243 ;
        RECT 0.558 0.063 0.576 0.243 ;
        RECT 0.526 0.063 0.576 0.081 ;
        RECT 0.396 0.063 0.446 0.081 ;
        RECT 0.396 0.063 0.414 0.243 ;
        RECT 0.126 0.063 0.144 0.243 ;
        RECT 0.094 0.063 0.144 0.081 ;
    END
  END Y
  OBS
    LAYER M1 ;
      RECT 0 0 0 0 ;
  END
END CKINVDCx14_bottom

MACRO CKINVDCx16_bottom
  CLASS CORE ;
  ORIGIN 0 0 ;
  FOREIGN CKINVDCx16_bottom 0 0 ;
  SIZE 0.054 BY 0.270 ;
  SYMMETRY X Y ;
  SITE asap7sc7p5t ;
  PIN A
    DIRECTION INPUT ;
    USE SIGNAL ;
    PORT
      LAYER M1 ;
        RECT 1.412 0.126 1.505 0.144 ;
        RECT 1.444 0.027 1.462 0.144 ;
        RECT 0.158 0.027 1.462 0.045 ;
        RECT 0.98 0.126 1.072 0.144 ;
        RECT 1.017 0.027 1.035 0.144 ;
        RECT 0.547 0.126 0.639 0.144 ;
        RECT 0.584 0.027 0.602 0.144 ;
        RECT 0.126 0.126 0.208 0.144 ;
        RECT 0.158 0.027 0.176 0.144 ;
    END
  END A
  PIN VDD
    DIRECTION INOUT ;
    USE POWER ;
    SHAPE ABUTMENT ;
    PORT
      LAYER M1 ;
        RECT 0 0.261 1.62 0.279 ;
    END
  END VDD
  PIN VSS
    DIRECTION INOUT ;
    USE GROUND ;
    SHAPE ABUTMENT ;
    PORT
      LAYER M1 ;
        RECT 0 -0.009 1.62 0.009 ;
    END
  END VSS
  PIN Y
    DIRECTION OUTPUT ;
    USE SIGNAL ;
    PORT
      LAYER M1 ;
        RECT 0.072 0.225 1.548 0.243 ;
        RECT 1.53 0.063 1.548 0.243 ;
        RECT 1.498 0.063 1.548 0.081 ;
        RECT 1.368 0.063 1.418 0.081 ;
        RECT 1.368 0.063 1.386 0.243 ;
        RECT 1.098 0.063 1.116 0.243 ;
        RECT 1.066 0.063 1.116 0.081 ;
        RECT 0.936 0.063 0.986 0.081 ;
        RECT 0.936 0.063 0.954 0.243 ;
        RECT 0.666 0.063 0.684 0.243 ;
        RECT 0.634 0.063 0.684 0.081 ;
        RECT 0.504 0.063 0.554 0.081 ;
        RECT 0.504 0.063 0.522 0.243 ;
        RECT 0.234 0.063 0.252 0.243 ;
        RECT 0.202 0.063 0.252 0.081 ;
        RECT 0.072 0.063 0.122 0.081 ;
        RECT 0.072 0.063 0.09 0.243 ;
    END
  END Y
  OBS
    LAYER M1 ;
      RECT 0 0 0 0 ;
  END
END CKINVDCx16_bottom

MACRO CKINVDCx20_bottom
  CLASS CORE ;
  ORIGIN 0 0 ;
  FOREIGN CKINVDCx20_bottom 0 0 ;
  SIZE 0.054 BY 0.270 ;
  SYMMETRY X Y ;
  SITE asap7sc7p5t ;
  PIN A
    DIRECTION INPUT ;
    USE SIGNAL ;
    PORT
      LAYER M1 ;
        RECT 1.844 0.126 1.937 0.144 ;
        RECT 1.876 0.027 1.894 0.144 ;
        RECT 0.158 0.027 1.894 0.045 ;
        RECT 1.412 0.126 1.505 0.144 ;
        RECT 1.444 0.027 1.462 0.144 ;
        RECT 0.98 0.126 1.072 0.144 ;
        RECT 1.017 0.027 1.035 0.144 ;
        RECT 0.547 0.126 0.639 0.144 ;
        RECT 0.584 0.027 0.602 0.144 ;
        RECT 0.126 0.126 0.208 0.144 ;
        RECT 0.158 0.027 0.176 0.144 ;
    END
  END A
  PIN VDD
    DIRECTION INOUT ;
    USE POWER ;
    SHAPE ABUTMENT ;
    PORT
      LAYER M1 ;
        RECT 0 0.261 2.052 0.279 ;
    END
  END VDD
  PIN VSS
    DIRECTION INOUT ;
    USE GROUND ;
    SHAPE ABUTMENT ;
    PORT
      LAYER M1 ;
        RECT 0 -0.009 2.052 0.009 ;
    END
  END VSS
  PIN Y
    DIRECTION OUTPUT ;
    USE SIGNAL ;
    PORT
      LAYER M1 ;
        RECT 0.072 0.225 1.98 0.243 ;
        RECT 1.962 0.063 1.98 0.243 ;
        RECT 1.93 0.063 1.98 0.081 ;
        RECT 1.8 0.063 1.85 0.081 ;
        RECT 1.8 0.063 1.818 0.243 ;
        RECT 1.53 0.063 1.548 0.243 ;
        RECT 1.498 0.063 1.548 0.081 ;
        RECT 1.368 0.063 1.418 0.081 ;
        RECT 1.368 0.063 1.386 0.243 ;
        RECT 1.098 0.063 1.116 0.243 ;
        RECT 1.066 0.063 1.116 0.081 ;
        RECT 0.936 0.063 0.986 0.081 ;
        RECT 0.936 0.063 0.954 0.243 ;
        RECT 0.666 0.063 0.684 0.243 ;
        RECT 0.634 0.063 0.684 0.081 ;
        RECT 0.504 0.063 0.554 0.081 ;
        RECT 0.504 0.063 0.522 0.243 ;
        RECT 0.234 0.063 0.252 0.243 ;
        RECT 0.202 0.063 0.252 0.081 ;
        RECT 0.072 0.063 0.122 0.081 ;
        RECT 0.072 0.063 0.09 0.243 ;
    END
  END Y
  OBS
    LAYER M1 ;
      RECT 0 0 0 0 ;
  END
END CKINVDCx20_bottom

MACRO CKINVDCx5p33_bottom
  CLASS CORE ;
  ORIGIN 0 0 ;
  FOREIGN CKINVDCx5p33_bottom 0 0 ;
  SIZE 0.054 BY 0.270 ;
  SYMMETRY X Y ;
  SITE asap7sc7p5t ;
  PIN A
    DIRECTION INPUT ;
    USE SIGNAL ;
    PORT
      LAYER M1 ;
        RECT 1.088 0.126 1.138 0.144 ;
        RECT 1.12 0.027 1.138 0.144 ;
        RECT 0.05 0.027 1.138 0.045 ;
        RECT 0.764 0.126 0.814 0.144 ;
        RECT 0.796 0.027 0.814 0.144 ;
        RECT 0.374 0.126 0.424 0.144 ;
        RECT 0.374 0.027 0.392 0.144 ;
        RECT 0.05 0.126 0.1 0.144 ;
        RECT 0.05 0.027 0.068 0.144 ;
    END
  END A
  PIN VDD
    DIRECTION INOUT ;
    USE POWER ;
    SHAPE ABUTMENT ;
    PORT
      LAYER M1 ;
        RECT 0 0.261 1.188 0.279 ;
    END
  END VDD
  PIN VSS
    DIRECTION INOUT ;
    USE GROUND ;
    SHAPE ABUTMENT ;
    PORT
      LAYER M1 ;
        RECT 0 -0.009 1.188 0.009 ;
    END
  END VSS
  PIN Y
    DIRECTION OUTPUT ;
    USE SIGNAL ;
    PORT
      LAYER M1 ;
        RECT 0.094 0.225 1.094 0.243 ;
        RECT 1.044 0.063 1.094 0.081 ;
        RECT 1.044 0.063 1.062 0.243 ;
        RECT 0.72 0.063 0.77 0.081 ;
        RECT 0.72 0.063 0.738 0.243 ;
        RECT 0.45 0.063 0.468 0.243 ;
        RECT 0.418 0.063 0.468 0.081 ;
        RECT 0.126 0.063 0.144 0.243 ;
        RECT 0.094 0.063 0.144 0.081 ;
    END
  END Y
  OBS
    LAYER M1 ;
      RECT 0 0 0 0 ;
  END
END CKINVDCx5p33_bottom

MACRO CKINVDCx6p67_bottom
  CLASS CORE ;
  ORIGIN 0 0 ;
  FOREIGN CKINVDCx6p67_bottom 0 0 ;
  SIZE 0.054 BY 0.270 ;
  SYMMETRY X Y ;
  SITE asap7sc7p5t ;
  PIN A
    DIRECTION INPUT ;
    USE SIGNAL ;
    PORT
      LAYER M1 ;
        RECT 1.088 0.126 1.17 0.144 ;
        RECT 1.12 0.027 1.138 0.144 ;
        RECT 0.05 0.027 1.138 0.045 ;
        RECT 0.764 0.126 0.814 0.144 ;
        RECT 0.796 0.027 0.814 0.144 ;
        RECT 0.374 0.126 0.424 0.144 ;
        RECT 0.374 0.027 0.392 0.144 ;
        RECT 0.05 0.126 0.1 0.144 ;
        RECT 0.05 0.027 0.068 0.144 ;
    END
  END A
  PIN VDD
    DIRECTION INOUT ;
    USE POWER ;
    SHAPE ABUTMENT ;
    PORT
      LAYER M1 ;
        RECT 0 0.261 1.296 0.279 ;
    END
  END VDD
  PIN VSS
    DIRECTION INOUT ;
    USE GROUND ;
    SHAPE ABUTMENT ;
    PORT
      LAYER M1 ;
        RECT 0 -0.009 1.296 0.009 ;
    END
  END VSS
  PIN Y
    DIRECTION OUTPUT ;
    USE SIGNAL ;
    PORT
      LAYER M1 ;
        RECT 0.094 0.225 1.224 0.243 ;
        RECT 1.206 0.063 1.224 0.243 ;
        RECT 1.174 0.063 1.224 0.081 ;
        RECT 1.044 0.063 1.094 0.081 ;
        RECT 1.044 0.063 1.062 0.243 ;
        RECT 0.72 0.063 0.77 0.081 ;
        RECT 0.72 0.063 0.738 0.243 ;
        RECT 0.45 0.063 0.468 0.243 ;
        RECT 0.418 0.063 0.468 0.081 ;
        RECT 0.126 0.063 0.144 0.243 ;
        RECT 0.094 0.063 0.144 0.081 ;
    END
  END Y
  OBS
    LAYER M1 ;
      RECT 0 0 0 0 ;
  END
END CKINVDCx6p67_bottom

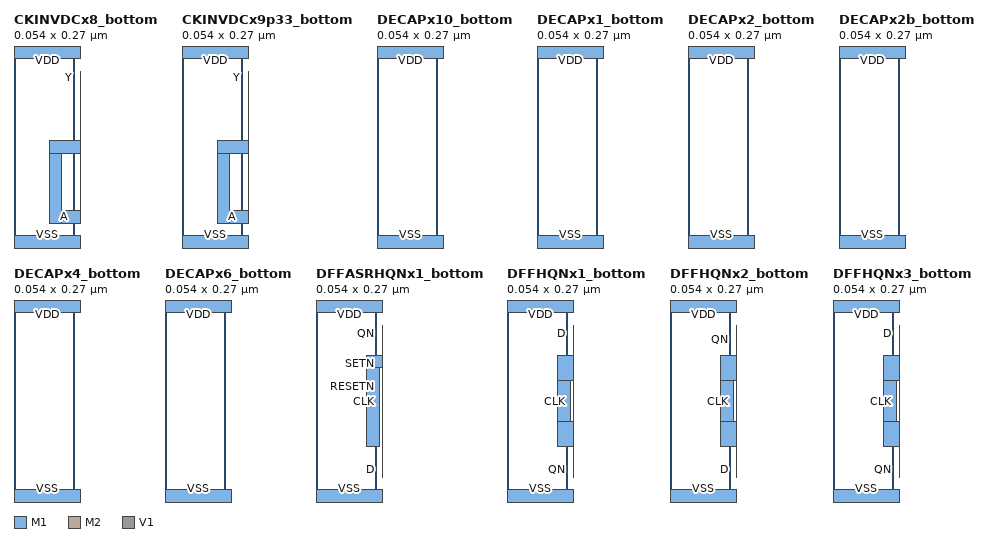
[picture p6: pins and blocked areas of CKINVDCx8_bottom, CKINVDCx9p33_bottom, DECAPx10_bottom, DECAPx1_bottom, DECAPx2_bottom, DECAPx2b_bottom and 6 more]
MACRO CKINVDCx8_bottom
  CLASS CORE ;
  ORIGIN 0 0 ;
  FOREIGN CKINVDCx8_bottom 0 0 ;
  SIZE 0.054 BY 0.270 ;
  SYMMETRY X Y ;
  SITE asap7sc7p5t ;
  PIN A
    DIRECTION INPUT ;
    USE SIGNAL ;
    PORT
      LAYER M1 ;
        RECT 1.088 0.126 1.138 0.144 ;
        RECT 1.12 0.027 1.138 0.144 ;
        RECT 0.05 0.027 1.138 0.045 ;
        RECT 0.764 0.126 0.814 0.144 ;
        RECT 0.796 0.027 0.814 0.144 ;
        RECT 0.374 0.126 0.424 0.144 ;
        RECT 0.374 0.027 0.392 0.144 ;
        RECT 0.05 0.126 0.1 0.144 ;
        RECT 0.05 0.027 0.068 0.144 ;
    END
  END A
  PIN VDD
    DIRECTION INOUT ;
    USE POWER ;
    SHAPE ABUTMENT ;
    PORT
      LAYER M1 ;
        RECT 0 0.261 1.188 0.279 ;
    END
  END VDD
  PIN VSS
    DIRECTION INOUT ;
    USE GROUND ;
    SHAPE ABUTMENT ;
    PORT
      LAYER M1 ;
        RECT 0 -0.009 1.188 0.009 ;
    END
  END VSS
  PIN Y
    DIRECTION OUTPUT ;
    USE SIGNAL ;
    PORT
      LAYER M1 ;
        RECT 0.094 0.225 1.094 0.243 ;
        RECT 1.044 0.063 1.094 0.081 ;
        RECT 1.044 0.063 1.062 0.243 ;
        RECT 0.72 0.063 0.77 0.081 ;
        RECT 0.72 0.063 0.738 0.243 ;
        RECT 0.45 0.063 0.468 0.243 ;
        RECT 0.418 0.063 0.468 0.081 ;
        RECT 0.126 0.063 0.144 0.243 ;
        RECT 0.094 0.063 0.144 0.081 ;
    END
  END Y
  OBS
    LAYER M1 ;
      RECT 0 0 0 0 ;
  END
END CKINVDCx8_bottom

MACRO CKINVDCx9p33_bottom
  CLASS CORE ;
  ORIGIN 0 0 ;
  FOREIGN CKINVDCx9p33_bottom 0 0 ;
  SIZE 0.054 BY 0.270 ;
  SYMMETRY X Y ;
  SITE asap7sc7p5t ;
  PIN A
    DIRECTION INPUT ;
    USE SIGNAL ;
    PORT
      LAYER M1 ;
        RECT 1.304 0.126 1.397 0.144 ;
        RECT 1.336 0.027 1.354 0.144 ;
        RECT 0.05 0.027 1.354 0.045 ;
        RECT 0.872 0.126 0.964 0.144 ;
        RECT 0.909 0.027 0.927 0.144 ;
        RECT 0.439 0.126 0.531 0.144 ;
        RECT 0.476 0.027 0.494 0.144 ;
        RECT 0.05 0.126 0.1 0.144 ;
        RECT 0.05 0.027 0.068 0.144 ;
    END
  END A
  PIN VDD
    DIRECTION INOUT ;
    USE POWER ;
    SHAPE ABUTMENT ;
    PORT
      LAYER M1 ;
        RECT 0 0.261 1.512 0.279 ;
    END
  END VDD
  PIN VSS
    DIRECTION INOUT ;
    USE GROUND ;
    SHAPE ABUTMENT ;
    PORT
      LAYER M1 ;
        RECT 0 -0.009 1.512 0.009 ;
    END
  END VSS
  PIN Y
    DIRECTION OUTPUT ;
    USE SIGNAL ;
    PORT
      LAYER M1 ;
        RECT 0.094 0.225 1.44 0.243 ;
        RECT 1.422 0.063 1.44 0.243 ;
        RECT 1.39 0.063 1.44 0.081 ;
        RECT 1.26 0.063 1.31 0.081 ;
        RECT 1.26 0.063 1.278 0.243 ;
        RECT 0.99 0.063 1.008 0.243 ;
        RECT 0.958 0.063 1.008 0.081 ;
        RECT 0.828 0.063 0.878 0.081 ;
        RECT 0.828 0.063 0.846 0.243 ;
        RECT 0.558 0.063 0.576 0.243 ;
        RECT 0.526 0.063 0.576 0.081 ;
        RECT 0.396 0.063 0.446 0.081 ;
        RECT 0.396 0.063 0.414 0.243 ;
        RECT 0.126 0.063 0.144 0.243 ;
        RECT 0.094 0.063 0.144 0.081 ;
    END
  END Y
  OBS
    LAYER M1 ;
      RECT 0 0 0 0 ;
  END
END CKINVDCx9p33_bottom

MACRO DECAPx10_bottom
  CLASS CORE SPACER ;
  ORIGIN 0 0 ;
  FOREIGN DECAPx10_bottom 0 0 ;
  SIZE 0.054 BY 0.270 ;
  SYMMETRY X Y ;
  SITE asap7sc7p5t ;
  PIN VDD
    DIRECTION INOUT ;
    USE POWER ;
    SHAPE ABUTMENT ;
    PORT
      LAYER M1 ;
        RECT 0 0.261 1.188 0.279 ;
    END
  END VDD
  PIN VSS
    DIRECTION INOUT ;
    USE GROUND ;
    SHAPE ABUTMENT ;
    PORT
      LAYER M1 ;
        RECT 0 -0.009 1.188 0.009 ;
    END
  END VSS
  OBS
    LAYER M1 ;
      RECT 0 0 0 0 ;
  END
END DECAPx10_bottom

MACRO DECAPx1_bottom
  CLASS CORE SPACER ;
  ORIGIN 0 0 ;
  FOREIGN DECAPx1_bottom 0 0 ;
  SIZE 0.054 BY 0.270 ;
  SYMMETRY X Y ;
  SITE asap7sc7p5t ;
  PIN VDD
    DIRECTION INOUT ;
    USE POWER ;
    SHAPE ABUTMENT ;
    PORT
      LAYER M1 ;
        RECT 0 0.261 0.216 0.279 ;
    END
  END VDD
  PIN VSS
    DIRECTION INOUT ;
    USE GROUND ;
    SHAPE ABUTMENT ;
    PORT
      LAYER M1 ;
        RECT 0 -0.009 0.216 0.009 ;
    END
  END VSS
  OBS
    LAYER M1 ;
      RECT 0 0 0 0 ;
  END
END DECAPx1_bottom

MACRO DECAPx2_bottom
  CLASS CORE SPACER ;
  ORIGIN 0 0 ;
  FOREIGN DECAPx2_bottom 0 0 ;
  SIZE 0.054 BY 0.270 ;
  SYMMETRY X Y ;
  SITE asap7sc7p5t ;
  PIN VDD
    DIRECTION INOUT ;
    USE POWER ;
    SHAPE ABUTMENT ;
    PORT
      LAYER M1 ;
        RECT 0 0.261 0.324 0.279 ;
    END
  END VDD
  PIN VSS
    DIRECTION INOUT ;
    USE GROUND ;
    SHAPE ABUTMENT ;
    PORT
      LAYER M1 ;
        RECT 0 -0.009 0.324 0.009 ;
    END
  END VSS
  OBS
    LAYER M1 ;
      RECT 0 0 0 0 ;
  END
END DECAPx2_bottom

MACRO DECAPx2b_bottom
  CLASS CORE SPACER ;
  ORIGIN 0 0 ;
  FOREIGN DECAPx2b_bottom 0 0 ;
  SIZE 0.054 BY 0.270 ;
  SYMMETRY X Y ;
  SITE asap7sc7p5t ;
  PIN VDD
    DIRECTION INOUT ;
    USE POWER ;
    SHAPE ABUTMENT ;
    PORT
      LAYER M1 ;
        RECT 0 0.261 0.324 0.279 ;
    END
  END VDD
  PIN VSS
    DIRECTION INOUT ;
    USE GROUND ;
    SHAPE ABUTMENT ;
    PORT
      LAYER M1 ;
        RECT 0 -0.009 0.324 0.009 ;
    END
  END VSS
  OBS
    LAYER M1 ;
      RECT 0 0 0 0 ;
  END
END DECAPx2b_bottom

MACRO DECAPx4_bottom
  CLASS CORE SPACER ;
  ORIGIN 0 0 ;
  FOREIGN DECAPx4_bottom 0 0 ;
  SIZE 0.054 BY 0.270 ;
  SYMMETRY X Y ;
  SITE asap7sc7p5t ;
  PIN VDD
    DIRECTION INOUT ;
    USE POWER ;
    SHAPE ABUTMENT ;
    PORT
      LAYER M1 ;
        RECT 0 0.261 0.54 0.279 ;
    END
  END VDD
  PIN VSS
    DIRECTION INOUT ;
    USE GROUND ;
    SHAPE ABUTMENT ;
    PORT
      LAYER M1 ;
        RECT 0 -0.009 0.54 0.009 ;
    END
  END VSS
  OBS
    LAYER M1 ;
      RECT 0 0 0 0 ;
  END
END DECAPx4_bottom

MACRO DECAPx6_bottom
  CLASS CORE SPACER ;
  ORIGIN 0 0 ;
  FOREIGN DECAPx6_bottom 0 0 ;
  SIZE 0.054 BY 0.270 ;
  SYMMETRY X Y ;
  SITE asap7sc7p5t ;
  PIN VDD
    DIRECTION INOUT ;
    USE POWER ;
    SHAPE ABUTMENT ;
    PORT
      LAYER M1 ;
        RECT 0 0.261 0.756 0.279 ;
    END
  END VDD
  PIN VSS
    DIRECTION INOUT ;
    USE GROUND ;
    SHAPE ABUTMENT ;
    PORT
      LAYER M1 ;
        RECT 0 -0.009 0.756 0.009 ;
    END
  END VSS
  OBS
    LAYER M1 ;
      RECT 0 0 0 0 ;
  END
END DECAPx6_bottom

MACRO DFFASRHQNx1_bottom
  CLASS CORE ;
  ORIGIN 0 0 ;
  FOREIGN DFFASRHQNx1_bottom 0 0 ;
  SIZE 0.054 BY 0.270 ;
  SYMMETRY X Y ;
  SITE asap7sc7p5t ;
  PIN CLK
    DIRECTION INPUT ;
    USE CLOCK ;
    PORT
      LAYER M1 ;
        RECT 0.099 0.182 0.117 0.236 ;
        RECT 0.072 0.182 0.117 0.2 ;
        RECT 0.072 0.07 0.09 0.2 ;
    END
  END CLK
  PIN D
    DIRECTION INPUT ;
    USE SIGNAL ;
    PORT
      LAYER M1 ;
        RECT 0.234 0.126 0.29 0.144 ;
        RECT 0.234 0.225 0.271 0.243 ;
        RECT 0.234 0.027 0.271 0.045 ;
        RECT 0.234 0.027 0.252 0.243 ;
    END
  END D
  PIN QN
    DIRECTION OUTPUT ;
    USE SIGNAL ;
    PORT
      LAYER M1 ;
        RECT 1.336 0.225 1.386 0.243 ;
        RECT 1.368 0.027 1.386 0.243 ;
        RECT 1.336 0.027 1.386 0.045 ;
    END
  END QN
  PIN VDD
    DIRECTION INOUT ;
    USE POWER ;
    SHAPE ABUTMENT ;
    PORT
      LAYER M1 ;
        RECT 0 0.261 1.404 0.279 ;
    END
  END VDD
  PIN VSS
    DIRECTION INOUT ;
    USE GROUND ;
    SHAPE ABUTMENT ;
    PORT
      LAYER M1 ;
        RECT 0 -0.009 1.404 0.009 ;
    END
  END VSS
  PIN RESETN
    DIRECTION INPUT ;
    USE SIGNAL ;
    PORT
      LAYER M2 ;
        RECT 0.632 0.144 1.067 0.162 ;
      LAYER M1 ;
        RECT 1.044 0.102 1.062 0.167 ;
        RECT 0.612 0.072 0.668 0.09 ;
        RECT 0.612 0.144 0.662 0.162 ;
        RECT 0.612 0.072 0.63 0.162 ;
      LAYER V1 ;
        RECT 0.637 0.144 0.655 0.162 ;
        RECT 1.044 0.144 1.062 0.162 ;
    END
  END RESETN
  PIN SETN
    DIRECTION INPUT ;
    USE SIGNAL ;
    PORT
      LAYER M2 ;
        RECT 0.783 0.18 1.067 0.198 ;
      LAYER M1 ;
        RECT 0.774 0.18 0.811 0.198 ;
        RECT 0.774 0.097 0.792 0.198 ;
      LAYER V1 ;
        RECT 0.788 0.18 0.806 0.198 ;
    END
  END SETN
  OBS
    LAYER M1 ;
      RECT 0 0 0 0 ;
  END
END DFFASRHQNx1_bottom

MACRO DFFHQNx1_bottom
  CLASS CORE ;
  ORIGIN 0 0 ;
  FOREIGN DFFHQNx1_bottom 0 0 ;
  SIZE 0.054 BY 0.270 ;
  SYMMETRY X Y ;
  SITE asap7sc7p5t ;
  PIN CLK
    DIRECTION INPUT ;
    USE CLOCK ;
    PORT
      LAYER M1 ;
        RECT 0.099 0.164 0.117 0.236 ;
        RECT 0.072 0.07 0.117 0.106 ;
        RECT 0.099 0.034 0.117 0.106 ;
        RECT 0.072 0.164 0.117 0.2 ;
        RECT 0.072 0.07 0.09 0.2 ;
    END
  END CLK
  PIN D
    DIRECTION INPUT ;
    USE SIGNAL ;
    PORT
      LAYER M1 ;
        RECT 0.234 0.126 0.29 0.144 ;
        RECT 0.234 0.225 0.271 0.243 ;
        RECT 0.234 0.027 0.271 0.045 ;
        RECT 0.234 0.027 0.252 0.243 ;
    END
  END D
  PIN QN
    DIRECTION OUTPUT ;
    USE SIGNAL ;
    PORT
      LAYER M1 ;
        RECT 1.012 0.225 1.062 0.243 ;
        RECT 1.044 0.027 1.062 0.243 ;
        RECT 1.012 0.027 1.062 0.045 ;
    END
  END QN
  PIN VDD
    DIRECTION INOUT ;
    USE POWER ;
    SHAPE ABUTMENT ;
    PORT
      LAYER M1 ;
        RECT 0 0.261 1.08 0.279 ;
    END
  END VDD
  PIN VSS
    DIRECTION INOUT ;
    USE GROUND ;
    SHAPE ABUTMENT ;
    PORT
      LAYER M1 ;
        RECT 0 -0.009 1.08 0.009 ;
    END
  END VSS
  OBS
    LAYER M1 ;
      RECT 0 0 0 0 ;
  END
END DFFHQNx1_bottom

MACRO DFFHQNx2_bottom
  CLASS CORE ;
  ORIGIN 0 0 ;
  FOREIGN DFFHQNx2_bottom 0 0 ;
  SIZE 0.054 BY 0.270 ;
  SYMMETRY X Y ;
  SITE asap7sc7p5t ;
  PIN CLK
    DIRECTION INPUT ;
    USE CLOCK ;
    PORT
      LAYER M1 ;
        RECT 0.099 0.164 0.117 0.236 ;
        RECT 0.072 0.07 0.117 0.106 ;
        RECT 0.099 0.034 0.117 0.106 ;
        RECT 0.072 0.164 0.117 0.2 ;
        RECT 0.072 0.07 0.09 0.2 ;
    END
  END CLK
  PIN D
    DIRECTION INPUT ;
    USE SIGNAL ;
    PORT
      LAYER M1 ;
        RECT 0.234 0.126 0.29 0.144 ;
        RECT 0.234 0.225 0.271 0.243 ;
        RECT 0.234 0.027 0.271 0.045 ;
        RECT 0.234 0.027 0.252 0.243 ;
    END
  END D
  PIN QN
    DIRECTION OUTPUT ;
    USE SIGNAL ;
    PORT
      LAYER M1 ;
        RECT 1.012 0.216 1.117 0.234 ;
        RECT 1.099 0.036 1.117 0.234 ;
        RECT 1.012 0.036 1.117 0.054 ;
    END
  END QN
  PIN VDD
    DIRECTION INOUT ;
    USE POWER ;
    SHAPE ABUTMENT ;
    PORT
      LAYER M1 ;
        RECT 0 0.261 1.134 0.279 ;
    END
  END VDD
  PIN VSS
    DIRECTION INOUT ;
    USE GROUND ;
    SHAPE ABUTMENT ;
    PORT
      LAYER M1 ;
        RECT 0 -0.009 1.134 0.009 ;
    END
  END VSS
  OBS
    LAYER M1 ;
      RECT 0 0 0 0 ;
  END
END DFFHQNx2_bottom

MACRO DFFHQNx3_bottom
  CLASS CORE ;
  ORIGIN 0 0 ;
  FOREIGN DFFHQNx3_bottom 0 0 ;
  SIZE 0.054 BY 0.270 ;
  SYMMETRY X Y ;
  SITE asap7sc7p5t ;
  PIN CLK
    DIRECTION INPUT ;
    USE CLOCK ;
    PORT
      LAYER M1 ;
        RECT 0.099 0.164 0.117 0.236 ;
        RECT 0.072 0.07 0.117 0.106 ;
        RECT 0.099 0.034 0.117 0.106 ;
        RECT 0.072 0.164 0.117 0.2 ;
        RECT 0.072 0.07 0.09 0.2 ;
    END
  END CLK
  PIN D
    DIRECTION INPUT ;
    USE SIGNAL ;
    PORT
      LAYER M1 ;
        RECT 0.234 0.126 0.29 0.144 ;
        RECT 0.234 0.225 0.271 0.243 ;
        RECT 0.234 0.027 0.271 0.045 ;
        RECT 0.234 0.027 0.252 0.243 ;
    END
  END D
  PIN QN
    DIRECTION OUTPUT ;
    USE SIGNAL ;
    PORT
      LAYER M1 ;
        RECT 1.012 0.225 1.171 0.243 ;
        RECT 1.153 0.027 1.171 0.243 ;
        RECT 1.012 0.027 1.171 0.045 ;
    END
  END QN
  PIN VDD
    DIRECTION INOUT ;
    USE POWER ;
    SHAPE ABUTMENT ;
    PORT
      LAYER M1 ;
        RECT 0 0.261 1.188 0.279 ;
    END
  END VDD
  PIN VSS
    DIRECTION INOUT ;
    USE GROUND ;
    SHAPE ABUTMENT ;
    PORT
      LAYER M1 ;
        RECT 0 -0.009 1.188 0.009 ;
    END
  END VSS
  OBS
    LAYER M1 ;
      RECT 0 0 0 0 ;
  END
END DFFHQNx3_bottom

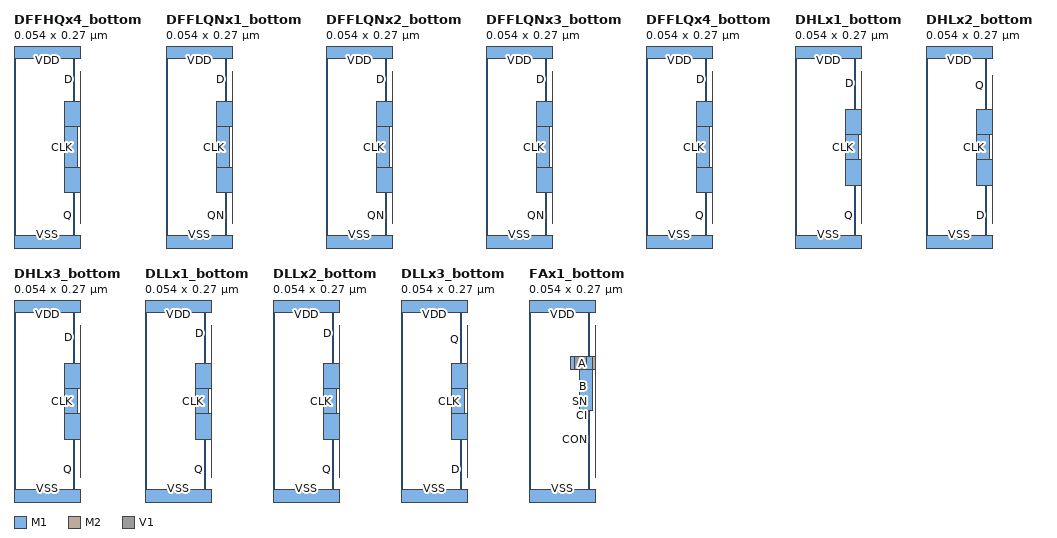
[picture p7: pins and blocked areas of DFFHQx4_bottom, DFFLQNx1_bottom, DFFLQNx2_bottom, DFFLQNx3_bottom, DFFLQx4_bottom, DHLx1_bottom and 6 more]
MACRO DFFHQx4_bottom
  CLASS CORE ;
  ORIGIN 0 0 ;
  FOREIGN DFFHQx4_bottom 0 0 ;
  SIZE 0.054 BY 0.270 ;
  SYMMETRY X Y ;
  SITE asap7sc7p5t ;
  PIN CLK
    DIRECTION INPUT ;
    USE CLOCK ;
    PORT
      LAYER M1 ;
        RECT 0.099 0.164 0.117 0.236 ;
        RECT 0.072 0.07 0.117 0.106 ;
        RECT 0.099 0.034 0.117 0.106 ;
        RECT 0.072 0.164 0.117 0.2 ;
        RECT 0.072 0.07 0.09 0.2 ;
    END
  END CLK
  PIN D
    DIRECTION INPUT ;
    USE SIGNAL ;
    PORT
      LAYER M1 ;
        RECT 0.234 0.126 0.29 0.144 ;
        RECT 0.234 0.225 0.271 0.243 ;
        RECT 0.234 0.027 0.271 0.045 ;
        RECT 0.234 0.027 0.252 0.243 ;
    END
  END D
  PIN Q
    DIRECTION OUTPUT ;
    USE SIGNAL ;
    PORT
      LAYER M1 ;
        RECT 1.125 0.225 1.333 0.243 ;
        RECT 1.313 0.027 1.333 0.243 ;
        RECT 1.125 0.027 1.333 0.045 ;
        RECT 1.125 0.201 1.143 0.243 ;
        RECT 1.125 0.027 1.143 0.069 ;
    END
  END Q
  PIN VDD
    DIRECTION INOUT ;
    USE POWER ;
    SHAPE ABUTMENT ;
    PORT
      LAYER M1 ;
        RECT 0 0.261 1.35 0.279 ;
    END
  END VDD
  PIN VSS
    DIRECTION INOUT ;
    USE GROUND ;
    SHAPE ABUTMENT ;
    PORT
      LAYER M1 ;
        RECT 0 -0.009 1.35 0.009 ;
    END
  END VSS
  OBS
    LAYER M1 ;
      RECT 0 0 0 0 ;
  END
END DFFHQx4_bottom

MACRO DFFLQNx1_bottom
  CLASS CORE ;
  ORIGIN 0 0 ;
  FOREIGN DFFLQNx1_bottom 0 0 ;
  SIZE 0.054 BY 0.270 ;
  SYMMETRY X Y ;
  SITE asap7sc7p5t ;
  PIN CLK
    DIRECTION INPUT ;
    USE CLOCK ;
    PORT
      LAYER M1 ;
        RECT 0.099 0.164 0.117 0.236 ;
        RECT 0.072 0.07 0.117 0.106 ;
        RECT 0.099 0.034 0.117 0.106 ;
        RECT 0.072 0.164 0.117 0.2 ;
        RECT 0.072 0.07 0.09 0.2 ;
    END
  END CLK
  PIN D
    DIRECTION INPUT ;
    USE SIGNAL ;
    PORT
      LAYER M1 ;
        RECT 0.288 0.225 0.325 0.243 ;
        RECT 0.288 0.027 0.325 0.045 ;
        RECT 0.288 0.027 0.306 0.243 ;
    END
  END D
  PIN QN
    DIRECTION OUTPUT ;
    USE SIGNAL ;
    PORT
      LAYER M1 ;
        RECT 1.012 0.225 1.062 0.243 ;
        RECT 1.044 0.027 1.062 0.243 ;
        RECT 1.012 0.027 1.062 0.045 ;
    END
  END QN
  PIN VDD
    DIRECTION INOUT ;
    USE POWER ;
    SHAPE ABUTMENT ;
    PORT
      LAYER M1 ;
        RECT 0 0.261 1.08 0.279 ;
    END
  END VDD
  PIN VSS
    DIRECTION INOUT ;
    USE GROUND ;
    SHAPE ABUTMENT ;
    PORT
      LAYER M1 ;
        RECT 0 -0.009 1.08 0.009 ;
    END
  END VSS
  OBS
    LAYER M1 ;
      RECT 0 0 0 0 ;
  END
END DFFLQNx1_bottom

MACRO DFFLQNx2_bottom
  CLASS CORE ;
  ORIGIN 0 0 ;
  FOREIGN DFFLQNx2_bottom 0 0 ;
  SIZE 0.054 BY 0.270 ;
  SYMMETRY X Y ;
  SITE asap7sc7p5t ;
  PIN QN
    DIRECTION OUTPUT ;
    USE SIGNAL ;
    PORT
      LAYER M1 ;
        RECT 1.012 0.225 1.115 0.243 ;
        RECT 1.097 0.027 1.115 0.243 ;
        RECT 1.012 0.027 1.115 0.045 ;
    END
  END QN
  PIN CLK
    DIRECTION INPUT ;
    USE CLOCK ;
    PORT
      LAYER M1 ;
        RECT 0.099 0.164 0.117 0.236 ;
        RECT 0.072 0.07 0.117 0.106 ;
        RECT 0.099 0.034 0.117 0.106 ;
        RECT 0.072 0.164 0.117 0.2 ;
        RECT 0.072 0.07 0.09 0.2 ;
    END
  END CLK
  PIN D
    DIRECTION INPUT ;
    USE SIGNAL ;
    PORT
      LAYER M1 ;
        RECT 0.288 0.225 0.325 0.243 ;
        RECT 0.288 0.027 0.325 0.045 ;
        RECT 0.288 0.027 0.306 0.243 ;
    END
  END D
  PIN VDD
    DIRECTION INOUT ;
    USE POWER ;
    SHAPE ABUTMENT ;
    PORT
      LAYER M1 ;
        RECT 0 0.261 1.134 0.279 ;
    END
  END VDD
  PIN VSS
    DIRECTION INOUT ;
    USE GROUND ;
    SHAPE ABUTMENT ;
    PORT
      LAYER M1 ;
        RECT 0 -0.009 1.134 0.009 ;
    END
  END VSS
  OBS
    LAYER M1 ;
      RECT 0 0 0 0 ;
  END
END DFFLQNx2_bottom

MACRO DFFLQNx3_bottom
  CLASS CORE ;
  ORIGIN 0 0 ;
  FOREIGN DFFLQNx3_bottom 0 0 ;
  SIZE 0.054 BY 0.270 ;
  SYMMETRY X Y ;
  SITE asap7sc7p5t ;
  PIN CLK
    DIRECTION INPUT ;
    USE CLOCK ;
    PORT
      LAYER M1 ;
        RECT 0.099 0.164 0.117 0.236 ;
        RECT 0.072 0.07 0.117 0.106 ;
        RECT 0.099 0.034 0.117 0.106 ;
        RECT 0.072 0.164 0.117 0.2 ;
        RECT 0.072 0.07 0.09 0.2 ;
    END
  END CLK
  PIN D
    DIRECTION INPUT ;
    USE SIGNAL ;
    PORT
      LAYER M1 ;
        RECT 0.288 0.225 0.325 0.243 ;
        RECT 0.288 0.027 0.325 0.045 ;
        RECT 0.288 0.027 0.306 0.243 ;
    END
  END D
  PIN QN
    DIRECTION OUTPUT ;
    USE SIGNAL ;
    PORT
      LAYER M1 ;
        RECT 1.012 0.225 1.171 0.243 ;
        RECT 1.153 0.027 1.171 0.243 ;
        RECT 1.011 0.027 1.171 0.045 ;
    END
  END QN
  PIN VDD
    DIRECTION INOUT ;
    USE POWER ;
    SHAPE ABUTMENT ;
    PORT
      LAYER M1 ;
        RECT 0 0.261 1.188 0.279 ;
    END
  END VDD
  PIN VSS
    DIRECTION INOUT ;
    USE GROUND ;
    SHAPE ABUTMENT ;
    PORT
      LAYER M1 ;
        RECT 0 -0.009 1.188 0.009 ;
    END
  END VSS
  OBS
    LAYER M1 ;
      RECT 0 0 0 0 ;
  END
END DFFLQNx3_bottom

MACRO DFFLQx4_bottom
  CLASS CORE ;
  ORIGIN 0 0 ;
  FOREIGN DFFLQx4_bottom 0 0 ;
  SIZE 0.054 BY 0.270 ;
  SYMMETRY X Y ;
  SITE asap7sc7p5t ;
  PIN CLK
    DIRECTION INPUT ;
    USE CLOCK ;
    PORT
      LAYER M1 ;
        RECT 0.099 0.164 0.117 0.236 ;
        RECT 0.072 0.07 0.117 0.106 ;
        RECT 0.099 0.034 0.117 0.106 ;
        RECT 0.072 0.164 0.117 0.2 ;
        RECT 0.072 0.07 0.09 0.2 ;
    END
  END CLK
  PIN D
    DIRECTION INPUT ;
    USE SIGNAL ;
    PORT
      LAYER M1 ;
        RECT 0.288 0.225 0.325 0.243 ;
        RECT 0.288 0.027 0.325 0.045 ;
        RECT 0.288 0.027 0.306 0.243 ;
    END
  END D
  PIN Q
    DIRECTION OUTPUT ;
    USE SIGNAL ;
    PORT
      LAYER M1 ;
        RECT 1.125 0.225 1.333 0.243 ;
        RECT 1.313 0.027 1.333 0.243 ;
        RECT 1.125 0.027 1.333 0.045 ;
        RECT 1.125 0.201 1.143 0.243 ;
        RECT 1.125 0.027 1.143 0.069 ;
    END
  END Q
  PIN VDD
    DIRECTION INOUT ;
    USE POWER ;
    SHAPE ABUTMENT ;
    PORT
      LAYER M1 ;
        RECT 0 0.261 1.35 0.279 ;
    END
  END VDD
  PIN VSS
    DIRECTION INOUT ;
    USE GROUND ;
    SHAPE ABUTMENT ;
    PORT
      LAYER M1 ;
        RECT 0 -0.009 1.35 0.009 ;
    END
  END VSS
  OBS
    LAYER M1 ;
      RECT 0 0 0 0 ;
  END
END DFFLQx4_bottom

MACRO DHLx1_bottom
  CLASS CORE ;
  ORIGIN 0 0 ;
  FOREIGN DHLx1_bottom 0 0 ;
  SIZE 0.054 BY 0.270 ;
  SYMMETRY X Y ;
  SITE asap7sc7p5t ;
  PIN CLK
    DIRECTION INPUT ;
    USE CLOCK ;
    PORT
      LAYER M1 ;
        RECT 0.099 0.153 0.117 0.236 ;
        RECT 0.072 0.081 0.117 0.117 ;
        RECT 0.099 0.034 0.117 0.117 ;
        RECT 0.072 0.153 0.117 0.189 ;
        RECT 0.072 0.081 0.09 0.189 ;
    END
  END CLK
  PIN D
    DIRECTION INPUT ;
    USE SIGNAL ;
    PORT
      LAYER M1 ;
        RECT 0.288 0.027 0.325 0.045 ;
        RECT 0.288 0.027 0.306 0.236 ;
    END
  END D
  PIN Q
    DIRECTION OUTPUT ;
    USE SIGNAL ;
    PORT
      LAYER M1 ;
        RECT 0.742 0.225 0.792 0.243 ;
        RECT 0.774 0.027 0.792 0.243 ;
        RECT 0.742 0.027 0.792 0.045 ;
    END
  END Q
  PIN VDD
    DIRECTION INOUT ;
    USE POWER ;
    SHAPE ABUTMENT ;
    PORT
      LAYER M1 ;
        RECT 0 0.261 0.81 0.279 ;
    END
  END VDD
  PIN VSS
    DIRECTION INOUT ;
    USE GROUND ;
    SHAPE ABUTMENT ;
    PORT
      LAYER M1 ;
        RECT 0 -0.009 0.81 0.009 ;
    END
  END VSS
  OBS
    LAYER M1 ;
      RECT 0 0 0 0 ;
  END
END DHLx1_bottom

MACRO DHLx2_bottom
  CLASS CORE ;
  ORIGIN 0 0 ;
  FOREIGN DHLx2_bottom 0 0 ;
  SIZE 0.054 BY 0.270 ;
  SYMMETRY X Y ;
  SITE asap7sc7p5t ;
  PIN CLK
    DIRECTION INPUT ;
    USE CLOCK ;
    PORT
      LAYER M1 ;
        RECT 0.099 0.153 0.117 0.236 ;
        RECT 0.072 0.081 0.117 0.117 ;
        RECT 0.099 0.034 0.117 0.117 ;
        RECT 0.072 0.153 0.117 0.189 ;
        RECT 0.072 0.081 0.09 0.189 ;
    END
  END CLK
  PIN D
    DIRECTION INPUT ;
    USE SIGNAL ;
    PORT
      LAYER M1 ;
        RECT 0.288 0.027 0.325 0.045 ;
        RECT 0.288 0.027 0.306 0.236 ;
    END
  END D
  PIN Q
    DIRECTION OUTPUT ;
    USE SIGNAL ;
    PORT
      LAYER M1 ;
        RECT 0.741 0.216 0.85 0.234 ;
        RECT 0.832 0.036 0.85 0.234 ;
        RECT 0.742 0.036 0.85 0.054 ;
    END
  END Q
  PIN VDD
    DIRECTION INOUT ;
    USE POWER ;
    SHAPE ABUTMENT ;
    PORT
      LAYER M1 ;
        RECT 0 0.261 0.864 0.279 ;
    END
  END VDD
  PIN VSS
    DIRECTION INOUT ;
    USE GROUND ;
    SHAPE ABUTMENT ;
    PORT
      LAYER M1 ;
        RECT 0 -0.009 0.864 0.009 ;
    END
  END VSS
  OBS
    LAYER M1 ;
      RECT 0 0 0 0 ;
  END
END DHLx2_bottom

MACRO DHLx3_bottom
  CLASS CORE ;
  ORIGIN 0 0 ;
  FOREIGN DHLx3_bottom 0 0 ;
  SIZE 0.054 BY 0.270 ;
  SYMMETRY X Y ;
  SITE asap7sc7p5t ;
  PIN CLK
    DIRECTION INPUT ;
    USE CLOCK ;
    PORT
      LAYER M1 ;
        RECT 0.099 0.153 0.117 0.236 ;
        RECT 0.072 0.081 0.117 0.117 ;
        RECT 0.099 0.034 0.117 0.117 ;
        RECT 0.072 0.153 0.117 0.189 ;
        RECT 0.072 0.081 0.09 0.189 ;
    END
  END CLK
  PIN D
    DIRECTION INPUT ;
    USE SIGNAL ;
    PORT
      LAYER M1 ;
        RECT 0.288 0.027 0.325 0.045 ;
        RECT 0.288 0.027 0.306 0.236 ;
    END
  END D
  PIN Q
    DIRECTION OUTPUT ;
    USE SIGNAL ;
    PORT
      LAYER M1 ;
        RECT 0.688 0.225 0.9 0.243 ;
        RECT 0.882 0.027 0.9 0.243 ;
        RECT 0.688 0.027 0.9 0.045 ;
    END
  END Q
  PIN VDD
    DIRECTION INOUT ;
    USE POWER ;
    SHAPE ABUTMENT ;
    PORT
      LAYER M1 ;
        RECT 0 0.261 0.918 0.279 ;
    END
  END VDD
  PIN VSS
    DIRECTION INOUT ;
    USE GROUND ;
    SHAPE ABUTMENT ;
    PORT
      LAYER M1 ;
        RECT 0 -0.009 0.918 0.009 ;
    END
  END VSS
  OBS
    LAYER M1 ;
      RECT 0 0 0 0 ;
  END
END DHLx3_bottom

MACRO DLLx1_bottom
  CLASS CORE ;
  ORIGIN 0 0 ;
  FOREIGN DLLx1_bottom 0 0 ;
  SIZE 0.054 BY 0.270 ;
  SYMMETRY X Y ;
  SITE asap7sc7p5t ;
  PIN CLK
    DIRECTION INPUT ;
    USE CLOCK ;
    PORT
      LAYER M1 ;
        RECT 0.099 0.153 0.117 0.236 ;
        RECT 0.072 0.081 0.117 0.117 ;
        RECT 0.099 0.034 0.117 0.117 ;
        RECT 0.072 0.153 0.117 0.189 ;
        RECT 0.072 0.081 0.09 0.189 ;
    END
  END CLK
  PIN D
    DIRECTION INPUT ;
    USE SIGNAL ;
    PORT
      LAYER M1 ;
        RECT 0.288 0.225 0.325 0.243 ;
        RECT 0.288 0.027 0.325 0.045 ;
        RECT 0.288 0.027 0.306 0.243 ;
    END
  END D
  PIN Q
    DIRECTION OUTPUT ;
    USE SIGNAL ;
    PORT
      LAYER M1 ;
        RECT 0.742 0.225 0.792 0.243 ;
        RECT 0.774 0.027 0.792 0.243 ;
        RECT 0.735 0.027 0.792 0.045 ;
    END
  END Q
  PIN VDD
    DIRECTION INOUT ;
    USE POWER ;
    SHAPE ABUTMENT ;
    PORT
      LAYER M1 ;
        RECT 0 0.261 0.81 0.279 ;
    END
  END VDD
  PIN VSS
    DIRECTION INOUT ;
    USE GROUND ;
    SHAPE ABUTMENT ;
    PORT
      LAYER M1 ;
        RECT 0 -0.009 0.81 0.009 ;
    END
  END VSS
  OBS
    LAYER M1 ;
      RECT 0 0 0 0 ;
  END
END DLLx1_bottom

MACRO DLLx2_bottom
  CLASS CORE ;
  ORIGIN 0 0 ;
  FOREIGN DLLx2_bottom 0 0 ;
  SIZE 0.054 BY 0.270 ;
  SYMMETRY X Y ;
  SITE asap7sc7p5t ;
  PIN CLK
    DIRECTION INPUT ;
    USE CLOCK ;
    PORT
      LAYER M1 ;
        RECT 0.099 0.153 0.117 0.236 ;
        RECT 0.072 0.081 0.117 0.117 ;
        RECT 0.099 0.034 0.117 0.117 ;
        RECT 0.072 0.153 0.117 0.189 ;
        RECT 0.072 0.081 0.09 0.189 ;
    END
  END CLK
  PIN D
    DIRECTION INPUT ;
    USE SIGNAL ;
    PORT
      LAYER M1 ;
        RECT 0.288 0.225 0.325 0.243 ;
        RECT 0.288 0.027 0.325 0.045 ;
        RECT 0.288 0.027 0.306 0.243 ;
    END
  END D
  PIN Q
    DIRECTION OUTPUT ;
    USE SIGNAL ;
    PORT
      LAYER M1 ;
        RECT 0.688 0.225 0.847 0.243 ;
        RECT 0.829 0.027 0.847 0.243 ;
        RECT 0.688 0.027 0.847 0.045 ;
    END
  END Q
  PIN VDD
    DIRECTION INOUT ;
    USE POWER ;
    SHAPE ABUTMENT ;
    PORT
      LAYER M1 ;
        RECT 0 0.261 0.864 0.279 ;
    END
  END VDD
  PIN VSS
    DIRECTION INOUT ;
    USE GROUND ;
    SHAPE ABUTMENT ;
    PORT
      LAYER M1 ;
        RECT 0 -0.009 0.864 0.009 ;
    END
  END VSS
  OBS
    LAYER M1 ;
      RECT 0 0 0 0 ;
  END
END DLLx2_bottom

MACRO DLLx3_bottom
  CLASS CORE ;
  ORIGIN 0 0 ;
  FOREIGN DLLx3_bottom 0 0 ;
  SIZE 0.054 BY 0.270 ;
  SYMMETRY X Y ;
  SITE asap7sc7p5t ;
  PIN CLK
    DIRECTION INPUT ;
    USE CLOCK ;
    PORT
      LAYER M1 ;
        RECT 0.099 0.153 0.117 0.236 ;
        RECT 0.072 0.081 0.117 0.117 ;
        RECT 0.099 0.034 0.117 0.117 ;
        RECT 0.072 0.153 0.117 0.189 ;
        RECT 0.072 0.081 0.09 0.189 ;
    END
  END CLK
  PIN D
    DIRECTION INPUT ;
    USE SIGNAL ;
    PORT
      LAYER M1 ;
        RECT 0.288 0.225 0.325 0.243 ;
        RECT 0.288 0.027 0.325 0.045 ;
        RECT 0.288 0.027 0.306 0.243 ;
    END
  END D
  PIN Q
    DIRECTION OUTPUT ;
    USE SIGNAL ;
    PORT
      LAYER M1 ;
        RECT 0.742 0.216 0.901 0.234 ;
        RECT 0.882 0.036 0.901 0.234 ;
        RECT 0.742 0.036 0.901 0.054 ;
    END
  END Q
  PIN VDD
    DIRECTION INOUT ;
    USE POWER ;
    SHAPE ABUTMENT ;
    PORT
      LAYER M1 ;
        RECT 0 0.261 0.918 0.279 ;
    END
  END VDD
  PIN VSS
    DIRECTION INOUT ;
    USE GROUND ;
    SHAPE ABUTMENT ;
    PORT
      LAYER M1 ;
        RECT 0 -0.009 0.918 0.009 ;
    END
  END VSS
  OBS
    LAYER M1 ;
      RECT 0 0 0 0 ;
  END
END DLLx3_bottom

MACRO FAx1_bottom
  CLASS CORE ;
  ORIGIN 0 0 ;
  FOREIGN FAx1_bottom 0 0 ;
  SIZE 0.054 BY 0.270 ;
  SYMMETRY X Y ;
  SITE asap7sc7p5t ;
  PIN SN
    DIRECTION OUTPUT ;
    USE SIGNAL ;
    PORT
      LAYER M1 ;
        RECT 0.324 0.225 0.495 0.243 ;
        RECT 0.477 0.184 0.495 0.243 ;
        RECT 0.477 0.027 0.495 0.068 ;
        RECT 0.324 0.027 0.495 0.045 ;
        RECT 0.324 0.027 0.342 0.243 ;
    END
  END SN
  PIN VDD
    DIRECTION INOUT ;
    USE POWER ;
    SHAPE ABUTMENT ;
    PORT
      LAYER M1 ;
        RECT 0 0.261 0.756 0.279 ;
    END
  END VDD
  PIN VSS
    DIRECTION INOUT ;
    USE GROUND ;
    SHAPE ABUTMENT ;
    PORT
      LAYER M1 ;
        RECT 0 -0.009 0.756 0.009 ;
    END
  END VSS
  PIN A
    DIRECTION INPUT ;
    USE SIGNAL ;
    PORT
      LAYER M2 ;
        RECT 0.059 0.18 0.627 0.198 ;
      LAYER M1 ;
        RECT 0.599 0.18 0.63 0.198 ;
        RECT 0.612 0.121 0.63 0.198 ;
        RECT 0.383 0.18 0.414 0.198 ;
        RECT 0.396 0.121 0.414 0.198 ;
        RECT 0.059 0.18 0.09 0.198 ;
        RECT 0.072 0.121 0.09 0.198 ;
      LAYER V1 ;
        RECT 0.064 0.18 0.082 0.198 ;
        RECT 0.388 0.18 0.406 0.198 ;
        RECT 0.604 0.18 0.622 0.198 ;
    END
  END A
  PIN B
    DIRECTION INPUT ;
    USE SIGNAL ;
    PORT
      LAYER M2 ;
        RECT 0.167 0.144 0.689 0.162 ;
      LAYER M1 ;
        RECT 0.666 0.121 0.684 0.167 ;
        RECT 0.288 0.121 0.306 0.167 ;
        RECT 0.167 0.144 0.198 0.162 ;
        RECT 0.18 0.121 0.198 0.162 ;
      LAYER V1 ;
        RECT 0.172 0.144 0.19 0.162 ;
        RECT 0.288 0.144 0.306 0.162 ;
        RECT 0.666 0.144 0.684 0.162 ;
    END
  END B
  PIN CI
    DIRECTION INPUT ;
    USE SIGNAL ;
    PORT
      LAYER M2 ;
        RECT 0.229 0.108 0.587 0.126 ;
      LAYER M1 ;
        RECT 0.558 0.108 0.587 0.126 ;
        RECT 0.558 0.108 0.576 0.149 ;
        RECT 0.45 0.103 0.468 0.149 ;
        RECT 0.226 0.108 0.263 0.126 ;
        RECT 0.234 0.108 0.252 0.149 ;
      LAYER V1 ;
        RECT 0.234 0.108 0.252 0.126 ;
        RECT 0.45 0.108 0.468 0.126 ;
        RECT 0.564 0.108 0.582 0.126 ;
    END
  END CI
  PIN CON
    DIRECTION OUTPUT ;
    USE SIGNAL ;
    PORT
      LAYER M2 ;
        RECT 0.128 0.072 0.543 0.09 ;
      LAYER M1 ;
        RECT 0.515 0.072 0.543 0.09 ;
        RECT 0.504 0.09 0.533 0.108 ;
        RECT 0.504 0.09 0.522 0.149 ;
        RECT 0.124 0.072 0.282 0.09 ;
        RECT 0.124 0.189 0.23 0.207 ;
        RECT 0.124 0.072 0.142 0.207 ;
      LAYER V1 ;
        RECT 0.133 0.072 0.151 0.09 ;
        RECT 0.52 0.072 0.538 0.09 ;
    END
  END CON
  OBS
    LAYER M1 ;
      RECT 0 0 0 0 ;
  END
END FAx1_bottom

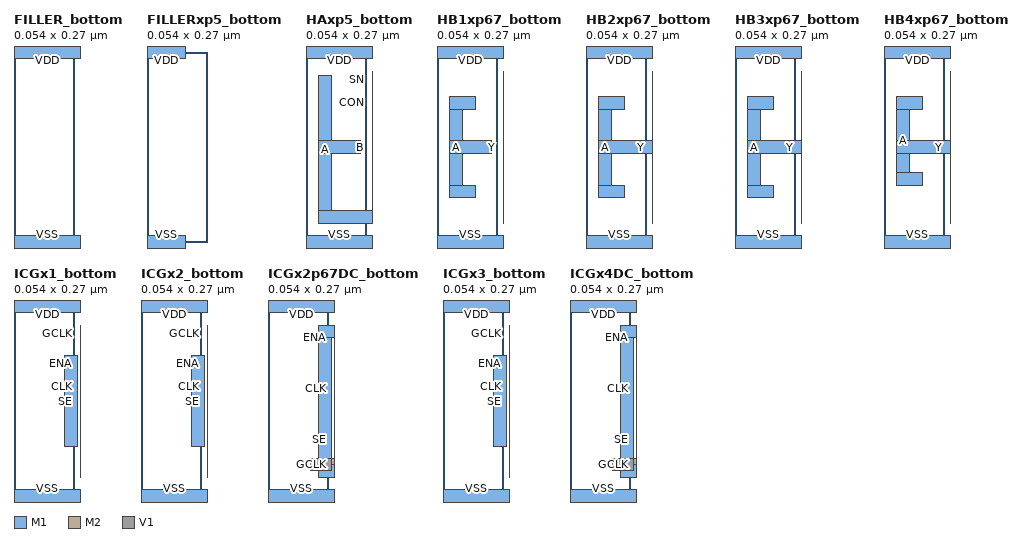
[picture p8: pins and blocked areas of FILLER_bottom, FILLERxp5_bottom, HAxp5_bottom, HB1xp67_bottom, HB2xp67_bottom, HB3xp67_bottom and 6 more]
MACRO FILLER_bottom
  CLASS CORE SPACER ;
  ORIGIN 0 0 ;
  FOREIGN FILLER_bottom 0 0 ;
  SIZE 0.054 BY 0.270 ;
  SYMMETRY X Y ;
  SITE asap7sc7p5t ;
  PIN VDD
    DIRECTION INOUT ;
    USE POWER ;
    SHAPE ABUTMENT ;
    PORT
      LAYER M1 ;
        RECT 0 0.261 0.108 0.279 ;
    END
  END VDD
  PIN VSS
    DIRECTION INOUT ;
    USE GROUND ;
    SHAPE ABUTMENT ;
    PORT
      LAYER M1 ;
        RECT 0 -0.009 0.108 0.009 ;
    END
  END VSS
END FILLER_bottom

MACRO FILLERxp5_bottom
  CLASS CORE SPACER ;
  ORIGIN 0 0 ;
  FOREIGN FILLERxp5_bottom 0 0 ;
  SIZE 0.054 BY 0.270 ;
  SYMMETRY X Y ;
  SITE asap7sc7p5t ;
  PIN VDD
    DIRECTION INOUT ;
    USE POWER ;
    SHAPE ABUTMENT ;
    PORT
      LAYER M1 ;
        RECT 0 0.261 0.054 0.279 ;
    END
  END VDD
  PIN VSS
    DIRECTION INOUT ;
    USE GROUND ;
    SHAPE ABUTMENT ;
    PORT
      LAYER M1 ;
        RECT 0 -0.009 0.054 0.009 ;
    END
  END VSS
END FILLERxp5_bottom

MACRO HAxp5_bottom
  CLASS CORE ;
  ORIGIN 0 0 ;
  FOREIGN HAxp5_bottom 0 0 ;
  SIZE 0.054 BY 0.270 ;
  SYMMETRY X Y ;
  SITE asap7sc7p5t ;
  PIN A
    DIRECTION INPUT ;
    USE SIGNAL ;
    PORT
      LAYER M1 ;
        RECT 0.342 0.063 0.36 0.15 ;
        RECT 0.207 0.063 0.36 0.081 ;
        RECT 0.207 0.027 0.225 0.081 ;
        RECT 0.018 0.027 0.225 0.045 ;
        RECT 0.018 0.126 0.078 0.144 ;
        RECT 0.018 0.027 0.036 0.236 ;
    END
  END A
  PIN B
    DIRECTION INPUT ;
    USE SIGNAL ;
    PORT
      LAYER M1 ;
        RECT 0.107 0.189 0.144 0.207 ;
        RECT 0.126 0.063 0.144 0.207 ;
        RECT 0.106 0.063 0.144 0.081 ;
    END
  END B
  PIN CON
    DIRECTION OUTPUT ;
    USE SIGNAL ;
    PORT
      LAYER M1 ;
        RECT 0.162 0.189 0.414 0.207 ;
        RECT 0.396 0.121 0.414 0.207 ;
        RECT 0.094 0.225 0.18 0.243 ;
        RECT 0.162 0.075 0.18 0.243 ;
    END
  END CON
  PIN SN
    DIRECTION OUTPUT ;
    USE SIGNAL ;
    PORT
      LAYER M1 ;
        RECT 0.256 0.225 0.468 0.243 ;
        RECT 0.45 0.027 0.468 0.243 ;
        RECT 0.423 0.027 0.468 0.045 ;
    END
  END SN
  PIN VDD
    DIRECTION INOUT ;
    USE POWER ;
    SHAPE ABUTMENT ;
    PORT
      LAYER M1 ;
        RECT 0 0.261 0.486 0.279 ;
    END
  END VDD
  PIN VSS
    DIRECTION INOUT ;
    USE GROUND ;
    SHAPE ABUTMENT ;
    PORT
      LAYER M1 ;
        RECT 0 -0.009 0.486 0.009 ;
    END
  END VSS
  OBS
    LAYER M1 ;
      RECT 0 0 0 0 ;
  END
END HAxp5_bottom

MACRO HB1xp67_bottom
  CLASS CORE ;
  ORIGIN 0 0 ;
  FOREIGN HB1xp67_bottom 0 0 ;
  SIZE 0.054 BY 0.270 ;
  SYMMETRY X Y ;
  SITE asap7sc7p5t ;
  PIN A
    DIRECTION INPUT ;
    USE SIGNAL ;
    PORT
      LAYER M1 ;
        RECT 0.018 0.126 0.078 0.144 ;
        RECT 0.018 0.189 0.055 0.207 ;
        RECT 0.018 0.063 0.055 0.081 ;
        RECT 0.018 0.063 0.036 0.207 ;
    END
  END A
  PIN VDD
    DIRECTION INOUT ;
    USE POWER ;
    SHAPE ABUTMENT ;
    PORT
      LAYER M1 ;
        RECT 0 0.261 0.216 0.279 ;
    END
  END VDD
  PIN VSS
    DIRECTION INOUT ;
    USE GROUND ;
    SHAPE ABUTMENT ;
    PORT
      LAYER M1 ;
        RECT 0 -0.009 0.216 0.009 ;
    END
  END VSS
  PIN Y
    DIRECTION OUTPUT ;
    USE SIGNAL ;
    PORT
      LAYER M1 ;
        RECT 0.148 0.225 0.198 0.243 ;
        RECT 0.18 0.027 0.198 0.243 ;
        RECT 0.148 0.027 0.198 0.045 ;
    END
  END Y
  OBS
    LAYER M1 ;
      RECT 0 0 0 0 ;
  END
END HB1xp67_bottom

MACRO HB2xp67_bottom
  CLASS CORE ;
  ORIGIN 0 0 ;
  FOREIGN HB2xp67_bottom 0 0 ;
  SIZE 0.054 BY 0.270 ;
  SYMMETRY X Y ;
  SITE asap7sc7p5t ;
  PIN A
    DIRECTION INPUT ;
    USE SIGNAL ;
    PORT
      LAYER M1 ;
        RECT 0.018 0.126 0.095 0.144 ;
        RECT 0.018 0.189 0.055 0.207 ;
        RECT 0.018 0.063 0.055 0.081 ;
        RECT 0.018 0.063 0.036 0.207 ;
    END
  END A
  PIN VDD
    DIRECTION INOUT ;
    USE POWER ;
    SHAPE ABUTMENT ;
    PORT
      LAYER M1 ;
        RECT 0 0.261 0.27 0.279 ;
    END
  END VDD
  PIN VSS
    DIRECTION INOUT ;
    USE GROUND ;
    SHAPE ABUTMENT ;
    PORT
      LAYER M1 ;
        RECT 0 -0.009 0.27 0.009 ;
    END
  END VSS
  PIN Y
    DIRECTION OUTPUT ;
    USE SIGNAL ;
    PORT
      LAYER M1 ;
        RECT 0.202 0.225 0.252 0.243 ;
        RECT 0.234 0.027 0.252 0.243 ;
        RECT 0.202 0.027 0.252 0.045 ;
    END
  END Y
  OBS
    LAYER M1 ;
      RECT 0 0 0 0 ;
  END
END HB2xp67_bottom

MACRO HB3xp67_bottom
  CLASS CORE ;
  ORIGIN 0 0 ;
  FOREIGN HB3xp67_bottom 0 0 ;
  SIZE 0.054 BY 0.270 ;
  SYMMETRY X Y ;
  SITE asap7sc7p5t ;
  PIN A
    DIRECTION INPUT ;
    USE SIGNAL ;
    PORT
      LAYER M1 ;
        RECT 0.018 0.126 0.095 0.144 ;
        RECT 0.018 0.189 0.055 0.207 ;
        RECT 0.018 0.063 0.055 0.081 ;
        RECT 0.018 0.063 0.036 0.207 ;
    END
  END A
  PIN VDD
    DIRECTION INOUT ;
    USE POWER ;
    SHAPE ABUTMENT ;
    PORT
      LAYER M1 ;
        RECT 0 0.261 0.324 0.279 ;
    END
  END VDD
  PIN VSS
    DIRECTION INOUT ;
    USE GROUND ;
    SHAPE ABUTMENT ;
    PORT
      LAYER M1 ;
        RECT 0 -0.009 0.324 0.009 ;
    END
  END VSS
  PIN Y
    DIRECTION OUTPUT ;
    USE SIGNAL ;
    PORT
      LAYER M1 ;
        RECT 0.256 0.225 0.306 0.243 ;
        RECT 0.288 0.027 0.306 0.243 ;
        RECT 0.256 0.027 0.306 0.045 ;
    END
  END Y
  OBS
    LAYER M1 ;
      RECT 0 0 0 0 ;
  END
END HB3xp67_bottom

MACRO HB4xp67_bottom
  CLASS CORE ;
  ORIGIN 0 0 ;
  FOREIGN HB4xp67_bottom 0 0 ;
  SIZE 0.054 BY 0.270 ;
  SYMMETRY X Y ;
  SITE asap7sc7p5t ;
  PIN A
    DIRECTION INPUT ;
    USE SIGNAL ;
    PORT
      LAYER M1 ;
        RECT 0.018 0.126 0.095 0.144 ;
        RECT 0.018 0.189 0.055 0.207 ;
        RECT 0.018 0.081 0.055 0.099 ;
        RECT 0.018 0.081 0.036 0.207 ;
    END
  END A
  PIN VDD
    DIRECTION INOUT ;
    USE POWER ;
    SHAPE ABUTMENT ;
    PORT
      LAYER M1 ;
        RECT 0 0.261 0.378 0.279 ;
    END
  END VDD
  PIN VSS
    DIRECTION INOUT ;
    USE GROUND ;
    SHAPE ABUTMENT ;
    PORT
      LAYER M1 ;
        RECT 0 -0.009 0.378 0.009 ;
    END
  END VSS
  PIN Y
    DIRECTION OUTPUT ;
    USE SIGNAL ;
    PORT
      LAYER M1 ;
        RECT 0.31 0.225 0.36 0.243 ;
        RECT 0.342 0.027 0.36 0.243 ;
        RECT 0.31 0.027 0.36 0.045 ;
    END
  END Y
  OBS
    LAYER M1 ;
      RECT 0 0 0 0 ;
  END
END HB4xp67_bottom

MACRO ICGx1_bottom
  CLASS CORE ;
  ORIGIN 0 0 ;
  FOREIGN ICGx1_bottom 0 0 ;
  SIZE 0.054 BY 0.270 ;
  SYMMETRY X Y ;
  SITE asap7sc7p5t ;
  PIN ENA
    DIRECTION INPUT ;
    USE SIGNAL ;
    PORT
      LAYER M1 ;
        RECT 0.072 0.07 0.09 0.199 ;
    END
  END ENA
  PIN GCLK
    DIRECTION OUTPUT ;
    USE SIGNAL ;
    PORT
      LAYER M1 ;
        RECT 0.899 0.225 0.954 0.243 ;
        RECT 0.936 0.027 0.954 0.243 ;
        RECT 0.879 0.027 0.954 0.045 ;
    END
  END GCLK
  PIN SE
    DIRECTION INPUT ;
    USE SIGNAL ;
    PORT
      LAYER M1 ;
        RECT 0.126 0.07 0.144 0.199 ;
    END
  END SE
  PIN VDD
    DIRECTION INOUT ;
    USE POWER ;
    SHAPE ABUTMENT ;
    PORT
      LAYER M1 ;
        RECT 0 0.261 0.972 0.279 ;
    END
  END VDD
  PIN VSS
    DIRECTION INOUT ;
    USE GROUND ;
    SHAPE ABUTMENT ;
    PORT
      LAYER M1 ;
        RECT 0 -0.009 0.972 0.009 ;
    END
  END VSS
  PIN CLK
    DIRECTION INPUT ;
    USE CLOCK ;
    PORT
      LAYER M2 ;
        RECT 0.229 0.144 0.635 0.162 ;
      LAYER M1 ;
        RECT 0.612 0.178 0.765 0.196 ;
        RECT 0.747 0.142 0.765 0.196 ;
        RECT 0.612 0.116 0.63 0.196 ;
        RECT 0.396 0.144 0.447 0.162 ;
        RECT 0.396 0.12 0.414 0.162 ;
        RECT 0.234 0.119 0.252 0.184 ;
      LAYER V1 ;
        RECT 0.234 0.144 0.252 0.162 ;
        RECT 0.414 0.144 0.432 0.162 ;
        RECT 0.612 0.144 0.63 0.162 ;
    END
  END CLK
  OBS
    LAYER M1 ;
      RECT 0 0 0 0 ;
  END
END ICGx1_bottom

MACRO ICGx2_bottom
  CLASS CORE ;
  ORIGIN 0 0 ;
  FOREIGN ICGx2_bottom 0 0 ;
  SIZE 0.054 BY 0.270 ;
  SYMMETRY X Y ;
  SITE asap7sc7p5t ;
  PIN ENA
    DIRECTION INPUT ;
    USE SIGNAL ;
    PORT
      LAYER M1 ;
        RECT 0.072 0.07 0.09 0.199 ;
    END
  END ENA
  PIN GCLK
    DIRECTION OUTPUT ;
    USE SIGNAL ;
    PORT
      LAYER M1 ;
        RECT 0.899 0.225 1.008 0.243 ;
        RECT 0.99 0.027 1.008 0.243 ;
        RECT 0.879 0.027 1.008 0.045 ;
    END
  END GCLK
  PIN SE
    DIRECTION INPUT ;
    USE SIGNAL ;
    PORT
      LAYER M1 ;
        RECT 0.126 0.07 0.144 0.199 ;
    END
  END SE
  PIN VDD
    DIRECTION INOUT ;
    USE POWER ;
    SHAPE ABUTMENT ;
    PORT
      LAYER M1 ;
        RECT 0 0.261 1.026 0.279 ;
    END
  END VDD
  PIN VSS
    DIRECTION INOUT ;
    USE GROUND ;
    SHAPE ABUTMENT ;
    PORT
      LAYER M1 ;
        RECT 0 -0.009 1.026 0.009 ;
    END
  END VSS
  PIN CLK
    DIRECTION INPUT ;
    USE CLOCK ;
    PORT
      LAYER M2 ;
        RECT 0.229 0.144 0.635 0.162 ;
      LAYER M1 ;
        RECT 0.612 0.178 0.765 0.196 ;
        RECT 0.747 0.142 0.765 0.196 ;
        RECT 0.612 0.116 0.63 0.196 ;
        RECT 0.396 0.144 0.447 0.162 ;
        RECT 0.396 0.12 0.414 0.162 ;
        RECT 0.234 0.119 0.252 0.184 ;
      LAYER V1 ;
        RECT 0.234 0.144 0.252 0.162 ;
        RECT 0.414 0.144 0.432 0.162 ;
        RECT 0.612 0.144 0.63 0.162 ;
    END
  END CLK
  OBS
    LAYER M1 ;
      RECT 0 0 0 0 ;
  END
END ICGx2_bottom

MACRO ICGx2p67DC_bottom
  CLASS CORE ;
  ORIGIN 0 0 ;
  FOREIGN ICGx2p67DC_bottom 0 0 ;
  SIZE 0.054 BY 0.270 ;
  SYMMETRY X Y ;
  SITE asap7sc7p5t ;
  PIN GCLK
    DIRECTION OUTPUT ;
    USE SIGNAL ;
    PORT
      LAYER M1 ;
        RECT 2.465 0.225 2.52 0.243 ;
        RECT 2.502 0.027 2.52 0.243 ;
        RECT 2.445 0.027 2.52 0.045 ;
        RECT 1.925 0.225 1.98 0.243 ;
        RECT 1.962 0.027 1.98 0.243 ;
        RECT 1.905 0.027 1.98 0.045 ;
        RECT 0.612 0.027 0.687 0.045 ;
        RECT 0.612 0.225 0.667 0.243 ;
        RECT 0.612 0.027 0.63 0.243 ;
        RECT 0.072 0.027 0.147 0.045 ;
        RECT 0.072 0.225 0.127 0.243 ;
        RECT 0.072 0.027 0.09 0.243 ;
      LAYER M2 ;
        RECT 0.061 0.036 2.531 0.054 ;
      LAYER V1 ;
        RECT 0.072 0.036 0.09 0.054 ;
        RECT 0.612 0.036 0.63 0.054 ;
        RECT 1.962 0.036 1.98 0.054 ;
        RECT 2.502 0.036 2.52 0.054 ;
    END
  END GCLK
  PIN VDD
    DIRECTION INOUT ;
    USE POWER ;
    SHAPE ABUTMENT ;
    PORT
      LAYER M1 ;
        RECT 0 0.261 2.592 0.279 ;
    END
  END VDD
  PIN VSS
    DIRECTION INOUT ;
    USE GROUND ;
    SHAPE ABUTMENT ;
    PORT
      LAYER M1 ;
        RECT 0 -0.009 2.592 0.009 ;
    END
  END VSS
  PIN CLK
    DIRECTION INPUT ;
    USE CLOCK ;
    PORT
      LAYER M1 ;
        RECT 2.281 0.171 2.35 0.189 ;
        RECT 2.332 0.135 2.35 0.189 ;
        RECT 2.292 0.135 2.35 0.153 ;
        RECT 1.638 0.178 1.791 0.196 ;
        RECT 1.773 0.142 1.791 0.196 ;
        RECT 1.638 0.116 1.656 0.196 ;
        RECT 1.422 0.144 1.473 0.162 ;
        RECT 1.422 0.12 1.44 0.162 ;
        RECT 1.26 0.119 1.278 0.184 ;
        RECT 0.801 0.178 0.954 0.196 ;
        RECT 0.936 0.116 0.954 0.196 ;
        RECT 0.801 0.142 0.819 0.196 ;
        RECT 0.248 0.171 0.317 0.189 ;
        RECT 0.248 0.135 0.306 0.153 ;
        RECT 0.248 0.135 0.266 0.189 ;
      LAYER M2 ;
        RECT 0.235 0.144 2.358 0.162 ;
      LAYER V1 ;
        RECT 0.248 0.144 0.266 0.162 ;
        RECT 0.936 0.144 0.954 0.162 ;
        RECT 1.26 0.144 1.278 0.162 ;
        RECT 1.44 0.144 1.458 0.162 ;
        RECT 1.638 0.144 1.656 0.162 ;
        RECT 2.332 0.144 2.35 0.162 ;
    END
  END CLK
  PIN ENA
    DIRECTION INPUT ;
    USE SIGNAL ;
    PORT
      LAYER M1 ;
        RECT 1.076 0.172 1.116 0.199 ;
        RECT 1.098 0.07 1.116 0.199 ;
        RECT 1.032 0.222 1.095 0.241 ;
        RECT 1.076 0.172 1.095 0.241 ;
      LAYER M2 ;
        RECT 0.982 0.216 1.237 0.234 ;
      LAYER V1 ;
        RECT 1.076 0.216 1.095 0.234 ;
    END
  END ENA
  PIN SE
    DIRECTION INPUT ;
    USE SIGNAL ;
    PORT
      LAYER M1 ;
        RECT 1.152 0.07 1.17 0.199 ;
      LAYER M2 ;
        RECT 0.982 0.072 1.237 0.09 ;
      LAYER V1 ;
        RECT 1.152 0.072 1.17 0.09 ;
    END
  END SE
  OBS
    LAYER M1 ;
      RECT 0 0 0 0 ;
  END
END ICGx2p67DC_bottom

MACRO ICGx3_bottom
  CLASS CORE ;
  ORIGIN 0 0 ;
  FOREIGN ICGx3_bottom 0 0 ;
  SIZE 0.054 BY 0.270 ;
  SYMMETRY X Y ;
  SITE asap7sc7p5t ;
  PIN ENA
    DIRECTION INPUT ;
    USE SIGNAL ;
    PORT
      LAYER M1 ;
        RECT 0.072 0.07 0.09 0.199 ;
    END
  END ENA
  PIN GCLK
    DIRECTION OUTPUT ;
    USE SIGNAL ;
    PORT
      LAYER M1 ;
        RECT 0.899 0.225 1.062 0.243 ;
        RECT 1.044 0.027 1.062 0.243 ;
        RECT 0.879 0.027 1.062 0.045 ;
    END
  END GCLK
  PIN SE
    DIRECTION INPUT ;
    USE SIGNAL ;
    PORT
      LAYER M1 ;
        RECT 0.126 0.07 0.144 0.199 ;
    END
  END SE
  PIN VDD
    DIRECTION INOUT ;
    USE POWER ;
    SHAPE ABUTMENT ;
    PORT
      LAYER M1 ;
        RECT 0 0.261 1.08 0.279 ;
    END
  END VDD
  PIN VSS
    DIRECTION INOUT ;
    USE GROUND ;
    SHAPE ABUTMENT ;
    PORT
      LAYER M1 ;
        RECT 0 -0.009 1.08 0.009 ;
    END
  END VSS
  PIN CLK
    DIRECTION INPUT ;
    USE CLOCK ;
    PORT
      LAYER M2 ;
        RECT 0.229 0.144 0.635 0.162 ;
      LAYER M1 ;
        RECT 0.612 0.178 0.765 0.196 ;
        RECT 0.747 0.142 0.765 0.196 ;
        RECT 0.612 0.116 0.63 0.196 ;
        RECT 0.396 0.144 0.447 0.162 ;
        RECT 0.396 0.12 0.414 0.162 ;
        RECT 0.234 0.119 0.252 0.184 ;
      LAYER V1 ;
        RECT 0.234 0.144 0.252 0.162 ;
        RECT 0.414 0.144 0.432 0.162 ;
        RECT 0.612 0.144 0.63 0.162 ;
    END
  END CLK
  OBS
    LAYER M1 ;
      RECT 0 0 0 0 ;
  END
END ICGx3_bottom

MACRO ICGx4DC_bottom
  CLASS CORE ;
  ORIGIN 0 0 ;
  FOREIGN ICGx4DC_bottom 0 0 ;
  SIZE 0.054 BY 0.270 ;
  SYMMETRY X Y ;
  SITE asap7sc7p5t ;
  PIN GCLK
    DIRECTION OUTPUT ;
    USE SIGNAL ;
    PORT
      LAYER M1 ;
        RECT 2.465 0.225 2.52 0.243 ;
        RECT 2.502 0.027 2.52 0.243 ;
        RECT 2.445 0.027 2.52 0.045 ;
        RECT 1.925 0.225 1.98 0.243 ;
        RECT 1.962 0.027 1.98 0.243 ;
        RECT 1.905 0.027 1.98 0.045 ;
        RECT 0.612 0.027 0.687 0.045 ;
        RECT 0.612 0.225 0.667 0.243 ;
        RECT 0.612 0.027 0.63 0.243 ;
        RECT 0.072 0.027 0.147 0.045 ;
        RECT 0.072 0.225 0.127 0.243 ;
        RECT 0.072 0.027 0.09 0.243 ;
      LAYER M2 ;
        RECT 0.061 0.036 2.531 0.054 ;
      LAYER V1 ;
        RECT 0.072 0.036 0.09 0.054 ;
        RECT 0.612 0.036 0.63 0.054 ;
        RECT 1.962 0.036 1.98 0.054 ;
        RECT 2.502 0.036 2.52 0.054 ;
    END
  END GCLK
  PIN VDD
    DIRECTION INOUT ;
    USE POWER ;
    SHAPE ABUTMENT ;
    PORT
      LAYER M1 ;
        RECT 0 0.261 2.592 0.279 ;
    END
  END VDD
  PIN VSS
    DIRECTION INOUT ;
    USE GROUND ;
    SHAPE ABUTMENT ;
    PORT
      LAYER M1 ;
        RECT 0 -0.009 2.592 0.009 ;
    END
  END VSS
  PIN CLK
    DIRECTION INPUT ;
    USE CLOCK ;
    PORT
      LAYER M1 ;
        RECT 2.281 0.171 2.35 0.189 ;
        RECT 2.332 0.135 2.35 0.189 ;
        RECT 2.292 0.135 2.35 0.153 ;
        RECT 1.638 0.178 1.791 0.196 ;
        RECT 1.773 0.142 1.791 0.196 ;
        RECT 1.638 0.116 1.656 0.196 ;
        RECT 1.422 0.144 1.473 0.162 ;
        RECT 1.422 0.12 1.44 0.162 ;
        RECT 1.26 0.119 1.278 0.184 ;
        RECT 0.801 0.178 0.954 0.196 ;
        RECT 0.936 0.116 0.954 0.196 ;
        RECT 0.801 0.142 0.819 0.196 ;
        RECT 0.248 0.171 0.317 0.189 ;
        RECT 0.248 0.135 0.306 0.153 ;
        RECT 0.248 0.135 0.266 0.189 ;
      LAYER M2 ;
        RECT 0.235 0.144 2.358 0.162 ;
      LAYER V1 ;
        RECT 0.248 0.144 0.266 0.162 ;
        RECT 0.936 0.144 0.954 0.162 ;
        RECT 1.26 0.144 1.278 0.162 ;
        RECT 1.44 0.144 1.458 0.162 ;
        RECT 1.638 0.144 1.656 0.162 ;
        RECT 2.332 0.144 2.35 0.162 ;
    END
  END CLK
  PIN ENA
    DIRECTION INPUT ;
    USE SIGNAL ;
    PORT
      LAYER M1 ;
        RECT 1.076 0.172 1.116 0.199 ;
        RECT 1.098 0.07 1.116 0.199 ;
        RECT 1.032 0.222 1.095 0.241 ;
        RECT 1.076 0.172 1.095 0.241 ;
      LAYER M2 ;
        RECT 0.982 0.216 1.237 0.234 ;
      LAYER V1 ;
        RECT 1.076 0.216 1.095 0.234 ;
    END
  END ENA
  PIN SE
    DIRECTION INPUT ;
    USE SIGNAL ;
    PORT
      LAYER M1 ;
        RECT 1.152 0.07 1.17 0.199 ;
      LAYER M2 ;
        RECT 0.982 0.072 1.237 0.09 ;
      LAYER V1 ;
        RECT 1.152 0.072 1.17 0.09 ;
    END
  END SE
  OBS
    LAYER M1 ;
      RECT 0 0 0 0 ;
  END
END ICGx4DC_bottom

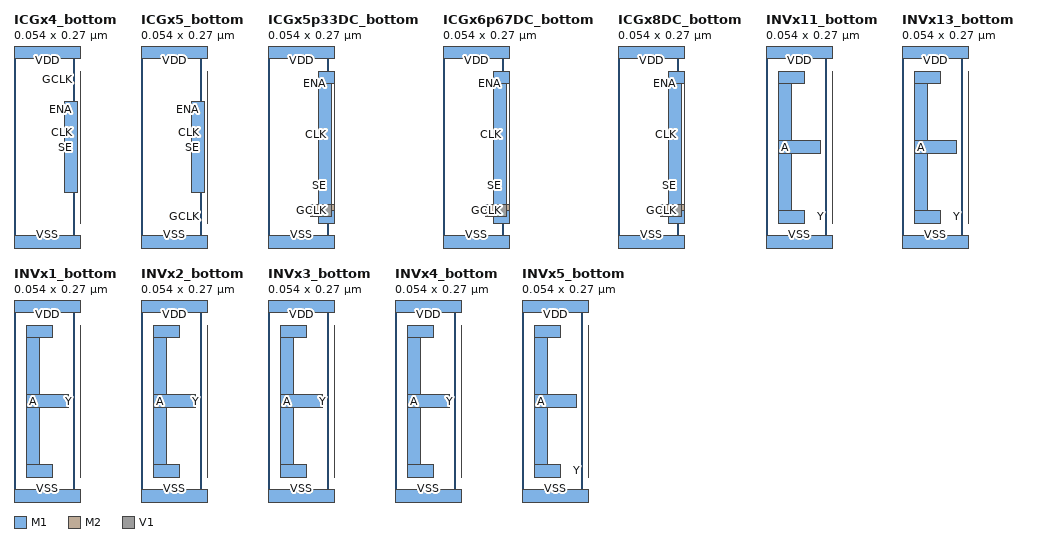
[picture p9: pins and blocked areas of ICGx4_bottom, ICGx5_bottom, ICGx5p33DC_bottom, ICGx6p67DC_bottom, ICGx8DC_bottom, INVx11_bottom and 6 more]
MACRO ICGx4_bottom
  CLASS CORE ;
  ORIGIN 0 0 ;
  FOREIGN ICGx4_bottom 0 0 ;
  SIZE 0.054 BY 0.270 ;
  SYMMETRY X Y ;
  SITE asap7sc7p5t ;
  PIN ENA
    DIRECTION INPUT ;
    USE SIGNAL ;
    PORT
      LAYER M1 ;
        RECT 0.072 0.07 0.09 0.199 ;
    END
  END ENA
  PIN GCLK
    DIRECTION OUTPUT ;
    USE SIGNAL ;
    PORT
      LAYER M1 ;
        RECT 0.89 0.225 1.062 0.243 ;
        RECT 1.044 0.027 1.062 0.243 ;
        RECT 0.889 0.027 1.062 0.045 ;
    END
  END GCLK
  PIN SE
    DIRECTION INPUT ;
    USE SIGNAL ;
    PORT
      LAYER M1 ;
        RECT 0.126 0.07 0.144 0.199 ;
    END
  END SE
  PIN VDD
    DIRECTION INOUT ;
    USE POWER ;
    SHAPE ABUTMENT ;
    PORT
      LAYER M1 ;
        RECT 0 0.261 1.134 0.279 ;
    END
  END VDD
  PIN VSS
    DIRECTION INOUT ;
    USE GROUND ;
    SHAPE ABUTMENT ;
    PORT
      LAYER M1 ;
        RECT 0 -0.009 1.134 0.009 ;
    END
  END VSS
  PIN CLK
    DIRECTION INPUT ;
    USE CLOCK ;
    PORT
      LAYER M2 ;
        RECT 0.229 0.144 0.635 0.162 ;
      LAYER M1 ;
        RECT 0.612 0.178 0.765 0.196 ;
        RECT 0.747 0.142 0.765 0.196 ;
        RECT 0.612 0.116 0.63 0.196 ;
        RECT 0.396 0.144 0.447 0.162 ;
        RECT 0.396 0.12 0.414 0.162 ;
        RECT 0.234 0.119 0.252 0.184 ;
      LAYER V1 ;
        RECT 0.234 0.144 0.252 0.162 ;
        RECT 0.414 0.144 0.432 0.162 ;
        RECT 0.612 0.144 0.63 0.162 ;
    END
  END CLK
  OBS
    LAYER M1 ;
      RECT 0 0 0 0 ;
  END
END ICGx4_bottom

MACRO ICGx5_bottom
  CLASS CORE ;
  ORIGIN 0 0 ;
  FOREIGN ICGx5_bottom 0 0 ;
  SIZE 0.054 BY 0.270 ;
  SYMMETRY X Y ;
  SITE asap7sc7p5t ;
  PIN ENA
    DIRECTION INPUT ;
    USE SIGNAL ;
    PORT
      LAYER M1 ;
        RECT 0.072 0.07 0.09 0.199 ;
    END
  END ENA
  PIN GCLK
    DIRECTION OUTPUT ;
    USE SIGNAL ;
    PORT
      LAYER M1 ;
        RECT 0.89 0.225 1.17 0.243 ;
        RECT 1.152 0.027 1.17 0.243 ;
        RECT 0.889 0.027 1.17 0.045 ;
    END
  END GCLK
  PIN SE
    DIRECTION INPUT ;
    USE SIGNAL ;
    PORT
      LAYER M1 ;
        RECT 0.126 0.07 0.144 0.199 ;
    END
  END SE
  PIN VDD
    DIRECTION INOUT ;
    USE POWER ;
    SHAPE ABUTMENT ;
    PORT
      LAYER M1 ;
        RECT 0 0.261 1.188 0.279 ;
    END
  END VDD
  PIN VSS
    DIRECTION INOUT ;
    USE GROUND ;
    SHAPE ABUTMENT ;
    PORT
      LAYER M1 ;
        RECT 0 -0.009 1.188 0.009 ;
    END
  END VSS
  PIN CLK
    DIRECTION INPUT ;
    USE CLOCK ;
    PORT
      LAYER M2 ;
        RECT 0.229 0.144 0.635 0.162 ;
      LAYER M1 ;
        RECT 0.612 0.178 0.765 0.196 ;
        RECT 0.747 0.142 0.765 0.196 ;
        RECT 0.612 0.116 0.63 0.196 ;
        RECT 0.396 0.144 0.447 0.162 ;
        RECT 0.396 0.12 0.414 0.162 ;
        RECT 0.234 0.119 0.252 0.184 ;
      LAYER V1 ;
        RECT 0.234 0.144 0.252 0.162 ;
        RECT 0.414 0.144 0.432 0.162 ;
        RECT 0.612 0.144 0.63 0.162 ;
    END
  END CLK
  OBS
    LAYER M1 ;
      RECT 0 0 0 0 ;
  END
END ICGx5_bottom

MACRO ICGx5p33DC_bottom
  CLASS CORE ;
  ORIGIN 0 0 ;
  FOREIGN ICGx5p33DC_bottom 0 0 ;
  SIZE 0.054 BY 0.270 ;
  SYMMETRY X Y ;
  SITE asap7sc7p5t ;
  PIN GCLK
    DIRECTION OUTPUT ;
    USE SIGNAL ;
    PORT
      LAYER M1 ;
        RECT 2.465 0.225 2.52 0.243 ;
        RECT 2.502 0.027 2.52 0.243 ;
        RECT 2.445 0.027 2.52 0.045 ;
        RECT 1.925 0.225 1.98 0.243 ;
        RECT 1.962 0.027 1.98 0.243 ;
        RECT 1.905 0.027 1.98 0.045 ;
        RECT 0.612 0.027 0.687 0.045 ;
        RECT 0.612 0.225 0.667 0.243 ;
        RECT 0.612 0.027 0.63 0.243 ;
        RECT 0.072 0.027 0.147 0.045 ;
        RECT 0.072 0.225 0.127 0.243 ;
        RECT 0.072 0.027 0.09 0.243 ;
      LAYER M2 ;
        RECT 0.061 0.036 2.531 0.054 ;
      LAYER V1 ;
        RECT 0.072 0.036 0.09 0.054 ;
        RECT 0.612 0.036 0.63 0.054 ;
        RECT 1.962 0.036 1.98 0.054 ;
        RECT 2.502 0.036 2.52 0.054 ;
    END
  END GCLK
  PIN VDD
    DIRECTION INOUT ;
    USE POWER ;
    SHAPE ABUTMENT ;
    PORT
      LAYER M1 ;
        RECT 0 0.261 2.592 0.279 ;
    END
  END VDD
  PIN VSS
    DIRECTION INOUT ;
    USE GROUND ;
    SHAPE ABUTMENT ;
    PORT
      LAYER M1 ;
        RECT 0 -0.009 2.592 0.009 ;
    END
  END VSS
  PIN CLK
    DIRECTION INPUT ;
    USE CLOCK ;
    PORT
      LAYER M1 ;
        RECT 2.281 0.171 2.35 0.189 ;
        RECT 2.332 0.135 2.35 0.189 ;
        RECT 2.292 0.135 2.35 0.153 ;
        RECT 1.638 0.178 1.791 0.196 ;
        RECT 1.773 0.142 1.791 0.196 ;
        RECT 1.638 0.116 1.656 0.196 ;
        RECT 1.422 0.144 1.473 0.162 ;
        RECT 1.422 0.12 1.44 0.162 ;
        RECT 1.26 0.119 1.278 0.184 ;
        RECT 0.801 0.178 0.954 0.196 ;
        RECT 0.936 0.116 0.954 0.196 ;
        RECT 0.801 0.142 0.819 0.196 ;
        RECT 0.248 0.171 0.317 0.189 ;
        RECT 0.248 0.135 0.306 0.153 ;
        RECT 0.248 0.135 0.266 0.189 ;
      LAYER M2 ;
        RECT 0.235 0.144 2.358 0.162 ;
      LAYER V1 ;
        RECT 0.248 0.144 0.266 0.162 ;
        RECT 0.936 0.144 0.954 0.162 ;
        RECT 1.26 0.144 1.278 0.162 ;
        RECT 1.44 0.144 1.458 0.162 ;
        RECT 1.638 0.144 1.656 0.162 ;
        RECT 2.332 0.144 2.35 0.162 ;
    END
  END CLK
  PIN ENA
    DIRECTION INPUT ;
    USE SIGNAL ;
    PORT
      LAYER M1 ;
        RECT 1.076 0.172 1.116 0.199 ;
        RECT 1.098 0.07 1.116 0.199 ;
        RECT 1.032 0.222 1.095 0.241 ;
        RECT 1.076 0.172 1.095 0.241 ;
      LAYER M2 ;
        RECT 0.982 0.216 1.237 0.234 ;
      LAYER V1 ;
        RECT 1.076 0.216 1.095 0.234 ;
    END
  END ENA
  PIN SE
    DIRECTION INPUT ;
    USE SIGNAL ;
    PORT
      LAYER M1 ;
        RECT 1.152 0.07 1.17 0.199 ;
      LAYER M2 ;
        RECT 0.982 0.072 1.237 0.09 ;
      LAYER V1 ;
        RECT 1.152 0.072 1.17 0.09 ;
    END
  END SE
  OBS
    LAYER M1 ;
      RECT 0 0 0 0 ;
  END
END ICGx5p33DC_bottom

MACRO ICGx6p67DC_bottom
  CLASS CORE ;
  ORIGIN 0 0 ;
  FOREIGN ICGx6p67DC_bottom 0 0 ;
  SIZE 0.054 BY 0.270 ;
  SYMMETRY X Y ;
  SITE asap7sc7p5t ;
  PIN GCLK
    DIRECTION OUTPUT ;
    USE SIGNAL ;
    PORT
      LAYER M1 ;
        RECT 2.465 0.225 2.52 0.243 ;
        RECT 2.502 0.027 2.52 0.243 ;
        RECT 2.445 0.027 2.52 0.045 ;
        RECT 1.925 0.225 1.98 0.243 ;
        RECT 1.962 0.027 1.98 0.243 ;
        RECT 1.905 0.027 1.98 0.045 ;
        RECT 0.612 0.027 0.687 0.045 ;
        RECT 0.612 0.225 0.667 0.243 ;
        RECT 0.612 0.027 0.63 0.243 ;
        RECT 0.072 0.027 0.147 0.045 ;
        RECT 0.072 0.225 0.127 0.243 ;
        RECT 0.072 0.027 0.09 0.243 ;
      LAYER M2 ;
        RECT 0.061 0.036 2.531 0.054 ;
      LAYER V1 ;
        RECT 0.072 0.036 0.09 0.054 ;
        RECT 0.612 0.036 0.63 0.054 ;
        RECT 1.962 0.036 1.98 0.054 ;
        RECT 2.502 0.036 2.52 0.054 ;
    END
  END GCLK
  PIN VDD
    DIRECTION INOUT ;
    USE POWER ;
    SHAPE ABUTMENT ;
    PORT
      LAYER M1 ;
        RECT 0 0.261 2.592 0.279 ;
    END
  END VDD
  PIN VSS
    DIRECTION INOUT ;
    USE GROUND ;
    SHAPE ABUTMENT ;
    PORT
      LAYER M1 ;
        RECT 0 -0.009 2.592 0.009 ;
    END
  END VSS
  PIN CLK
    DIRECTION INPUT ;
    USE CLOCK ;
    PORT
      LAYER M1 ;
        RECT 2.281 0.171 2.35 0.189 ;
        RECT 2.332 0.135 2.35 0.189 ;
        RECT 2.292 0.135 2.35 0.153 ;
        RECT 1.638 0.178 1.791 0.196 ;
        RECT 1.773 0.142 1.791 0.196 ;
        RECT 1.638 0.116 1.656 0.196 ;
        RECT 1.422 0.144 1.473 0.162 ;
        RECT 1.422 0.12 1.44 0.162 ;
        RECT 1.26 0.119 1.278 0.184 ;
        RECT 0.801 0.178 0.954 0.196 ;
        RECT 0.936 0.116 0.954 0.196 ;
        RECT 0.801 0.142 0.819 0.196 ;
        RECT 0.248 0.171 0.317 0.189 ;
        RECT 0.248 0.135 0.306 0.153 ;
        RECT 0.248 0.135 0.266 0.189 ;
      LAYER M2 ;
        RECT 0.235 0.144 2.358 0.162 ;
      LAYER V1 ;
        RECT 0.248 0.144 0.266 0.162 ;
        RECT 0.936 0.144 0.954 0.162 ;
        RECT 1.26 0.144 1.278 0.162 ;
        RECT 1.44 0.144 1.458 0.162 ;
        RECT 1.638 0.144 1.656 0.162 ;
        RECT 2.332 0.144 2.35 0.162 ;
    END
  END CLK
  PIN ENA
    DIRECTION INPUT ;
    USE SIGNAL ;
    PORT
      LAYER M1 ;
        RECT 1.076 0.172 1.116 0.199 ;
        RECT 1.098 0.07 1.116 0.199 ;
        RECT 1.032 0.222 1.095 0.241 ;
        RECT 1.076 0.172 1.095 0.241 ;
      LAYER M2 ;
        RECT 0.982 0.216 1.237 0.234 ;
      LAYER V1 ;
        RECT 1.076 0.216 1.095 0.234 ;
    END
  END ENA
  PIN SE
    DIRECTION INPUT ;
    USE SIGNAL ;
    PORT
      LAYER M1 ;
        RECT 1.152 0.07 1.17 0.199 ;
      LAYER M2 ;
        RECT 0.982 0.072 1.237 0.09 ;
      LAYER V1 ;
        RECT 1.152 0.072 1.17 0.09 ;
    END
  END SE
  OBS
    LAYER M1 ;
      RECT 0 0 0 0 ;
  END
END ICGx6p67DC_bottom

MACRO ICGx8DC_bottom
  CLASS CORE ;
  ORIGIN 0 0 ;
  FOREIGN ICGx8DC_bottom 0 0 ;
  SIZE 0.054 BY 0.270 ;
  SYMMETRY X Y ;
  SITE asap7sc7p5t ;
  PIN GCLK
    DIRECTION OUTPUT ;
    USE SIGNAL ;
    PORT
      LAYER M1 ;
        RECT 2.465 0.225 2.52 0.243 ;
        RECT 2.502 0.027 2.52 0.243 ;
        RECT 2.445 0.027 2.52 0.045 ;
        RECT 1.925 0.225 1.98 0.243 ;
        RECT 1.962 0.027 1.98 0.243 ;
        RECT 1.905 0.027 1.98 0.045 ;
        RECT 0.612 0.027 0.687 0.045 ;
        RECT 0.612 0.225 0.667 0.243 ;
        RECT 0.612 0.027 0.63 0.243 ;
        RECT 0.072 0.027 0.147 0.045 ;
        RECT 0.072 0.225 0.127 0.243 ;
        RECT 0.072 0.027 0.09 0.243 ;
      LAYER M2 ;
        RECT 0.061 0.036 2.531 0.054 ;
      LAYER V1 ;
        RECT 0.072 0.036 0.09 0.054 ;
        RECT 0.612 0.036 0.63 0.054 ;
        RECT 1.962 0.036 1.98 0.054 ;
        RECT 2.502 0.036 2.52 0.054 ;
    END
  END GCLK
  PIN VDD
    DIRECTION INOUT ;
    USE POWER ;
    SHAPE ABUTMENT ;
    PORT
      LAYER M1 ;
        RECT 0 0.261 2.592 0.279 ;
    END
  END VDD
  PIN VSS
    DIRECTION INOUT ;
    USE GROUND ;
    SHAPE ABUTMENT ;
    PORT
      LAYER M1 ;
        RECT 0 -0.009 2.592 0.009 ;
    END
  END VSS
  PIN CLK
    DIRECTION INPUT ;
    USE CLOCK ;
    PORT
      LAYER M1 ;
        RECT 2.281 0.171 2.35 0.189 ;
        RECT 2.332 0.135 2.35 0.189 ;
        RECT 2.292 0.135 2.35 0.153 ;
        RECT 1.638 0.178 1.791 0.196 ;
        RECT 1.773 0.142 1.791 0.196 ;
        RECT 1.638 0.116 1.656 0.196 ;
        RECT 1.422 0.144 1.473 0.162 ;
        RECT 1.422 0.12 1.44 0.162 ;
        RECT 1.26 0.119 1.278 0.184 ;
        RECT 0.801 0.178 0.954 0.196 ;
        RECT 0.936 0.116 0.954 0.196 ;
        RECT 0.801 0.142 0.819 0.196 ;
        RECT 0.248 0.171 0.317 0.189 ;
        RECT 0.248 0.135 0.306 0.153 ;
        RECT 0.248 0.135 0.266 0.189 ;
      LAYER M2 ;
        RECT 0.235 0.144 2.358 0.162 ;
      LAYER V1 ;
        RECT 0.248 0.144 0.266 0.162 ;
        RECT 0.936 0.144 0.954 0.162 ;
        RECT 1.26 0.144 1.278 0.162 ;
        RECT 1.44 0.144 1.458 0.162 ;
        RECT 1.638 0.144 1.656 0.162 ;
        RECT 2.332 0.144 2.35 0.162 ;
    END
  END CLK
  PIN ENA
    DIRECTION INPUT ;
    USE SIGNAL ;
    PORT
      LAYER M1 ;
        RECT 1.076 0.172 1.116 0.199 ;
        RECT 1.098 0.07 1.116 0.199 ;
        RECT 1.032 0.222 1.095 0.241 ;
        RECT 1.076 0.172 1.095 0.241 ;
      LAYER M2 ;
        RECT 0.982 0.216 1.237 0.234 ;
      LAYER V1 ;
        RECT 1.076 0.216 1.095 0.234 ;
    END
  END ENA
  PIN SE
    DIRECTION INPUT ;
    USE SIGNAL ;
    PORT
      LAYER M1 ;
        RECT 1.152 0.07 1.17 0.199 ;
      LAYER M2 ;
        RECT 0.982 0.072 1.237 0.09 ;
      LAYER V1 ;
        RECT 1.152 0.072 1.17 0.09 ;
    END
  END SE
  OBS
    LAYER M1 ;
      RECT 0 0 0 0 ;
  END
END ICGx8DC_bottom

MACRO INVx11_bottom
  CLASS CORE ;
  ORIGIN 0 0 ;
  FOREIGN INVx11_bottom 0 0 ;
  SIZE 0.054 BY 0.270 ;
  SYMMETRY X Y ;
  SITE asap7sc7p5t ;
  PIN A
    DIRECTION INPUT ;
    USE SIGNAL ;
    PORT
      LAYER M1 ;
        RECT 0.018 0.126 0.078 0.144 ;
        RECT 0.018 0.225 0.055 0.243 ;
        RECT 0.018 0.027 0.055 0.045 ;
        RECT 0.018 0.027 0.036 0.243 ;
    END
  END A
  PIN VDD
    DIRECTION INOUT ;
    USE POWER ;
    SHAPE ABUTMENT ;
    PORT
      LAYER M1 ;
        RECT 0 0.261 0.702 0.279 ;
    END
  END VDD
  PIN VSS
    DIRECTION INOUT ;
    USE GROUND ;
    SHAPE ABUTMENT ;
    PORT
      LAYER M1 ;
        RECT 0 -0.009 0.702 0.009 ;
    END
  END VSS
  PIN Y
    DIRECTION OUTPUT ;
    USE SIGNAL ;
    PORT
      LAYER M1 ;
        RECT 0.094 0.225 0.684 0.243 ;
        RECT 0.666 0.027 0.684 0.243 ;
        RECT 0.094 0.027 0.684 0.045 ;
    END
  END Y
END INVx11_bottom

MACRO INVx13_bottom
  CLASS CORE ;
  ORIGIN 0 0 ;
  FOREIGN INVx13_bottom 0 0 ;
  SIZE 0.054 BY 0.270 ;
  SYMMETRY X Y ;
  SITE asap7sc7p5t ;
  PIN A
    DIRECTION INPUT ;
    USE SIGNAL ;
    PORT
      LAYER M1 ;
        RECT 0.018 0.126 0.078 0.144 ;
        RECT 0.018 0.225 0.055 0.243 ;
        RECT 0.018 0.027 0.055 0.045 ;
        RECT 0.018 0.027 0.036 0.243 ;
    END
  END A
  PIN VDD
    DIRECTION INOUT ;
    USE POWER ;
    SHAPE ABUTMENT ;
    PORT
      LAYER M1 ;
        RECT 0 0.261 0.81 0.279 ;
    END
  END VDD
  PIN VSS
    DIRECTION INOUT ;
    USE GROUND ;
    SHAPE ABUTMENT ;
    PORT
      LAYER M1 ;
        RECT 0 -0.009 0.81 0.009 ;
    END
  END VSS
  PIN Y
    DIRECTION OUTPUT ;
    USE SIGNAL ;
    PORT
      LAYER M1 ;
        RECT 0.094 0.225 0.792 0.243 ;
        RECT 0.774 0.027 0.792 0.243 ;
        RECT 0.094 0.027 0.792 0.045 ;
    END
  END Y
END INVx13_bottom

MACRO INVx1_bottom
  CLASS CORE ;
  ORIGIN 0 0 ;
  FOREIGN INVx1_bottom 0 0 ;
  SIZE 0.054 BY 0.270 ;
  SYMMETRY X Y ;
  SITE asap7sc7p5t ;
  PIN A
    DIRECTION INPUT ;
    USE SIGNAL ;
    PORT
      LAYER M1 ;
        RECT 0.018 0.126 0.078 0.144 ;
        RECT 0.018 0.225 0.055 0.243 ;
        RECT 0.018 0.027 0.055 0.045 ;
        RECT 0.018 0.027 0.036 0.243 ;
    END
  END A
  PIN VDD
    DIRECTION INOUT ;
    USE POWER ;
    SHAPE ABUTMENT ;
    PORT
      LAYER M1 ;
        RECT 0 0.261 0.162 0.279 ;
    END
  END VDD
  PIN VSS
    DIRECTION INOUT ;
    USE GROUND ;
    SHAPE ABUTMENT ;
    PORT
      LAYER M1 ;
        RECT 0 -0.009 0.162 0.009 ;
    END
  END VSS
  PIN Y
    DIRECTION OUTPUT ;
    USE SIGNAL ;
    PORT
      LAYER M1 ;
        RECT 0.094 0.225 0.144 0.243 ;
        RECT 0.126 0.027 0.144 0.243 ;
        RECT 0.094 0.027 0.144 0.045 ;
    END
  END Y
END INVx1_bottom

MACRO INVx2_bottom
  CLASS CORE ;
  ORIGIN 0 0 ;
  FOREIGN INVx2_bottom 0 0 ;
  SIZE 0.054 BY 0.270 ;
  SYMMETRY X Y ;
  SITE asap7sc7p5t ;
  PIN A
    DIRECTION INPUT ;
    USE SIGNAL ;
    PORT
      LAYER M1 ;
        RECT 0.018 0.126 0.078 0.144 ;
        RECT 0.018 0.225 0.055 0.243 ;
        RECT 0.018 0.027 0.055 0.045 ;
        RECT 0.018 0.027 0.036 0.243 ;
    END
  END A
  PIN VDD
    DIRECTION INOUT ;
    USE POWER ;
    SHAPE ABUTMENT ;
    PORT
      LAYER M1 ;
        RECT 0 0.261 0.216 0.279 ;
    END
  END VDD
  PIN VSS
    DIRECTION INOUT ;
    USE GROUND ;
    SHAPE ABUTMENT ;
    PORT
      LAYER M1 ;
        RECT 0 -0.009 0.216 0.009 ;
    END
  END VSS
  PIN Y
    DIRECTION OUTPUT ;
    USE SIGNAL ;
    PORT
      LAYER M1 ;
        RECT 0.094 0.225 0.144 0.243 ;
        RECT 0.126 0.027 0.144 0.243 ;
        RECT 0.094 0.027 0.144 0.045 ;
    END
  END Y
END INVx2_bottom

MACRO INVx3_bottom
  CLASS CORE ;
  ORIGIN 0 0 ;
  FOREIGN INVx3_bottom 0 0 ;
  SIZE 0.054 BY 0.270 ;
  SYMMETRY X Y ;
  SITE asap7sc7p5t ;
  PIN A
    DIRECTION INPUT ;
    USE SIGNAL ;
    PORT
      LAYER M1 ;
        RECT 0.018 0.126 0.078 0.144 ;
        RECT 0.018 0.225 0.055 0.243 ;
        RECT 0.018 0.027 0.055 0.045 ;
        RECT 0.018 0.027 0.036 0.243 ;
    END
  END A
  PIN VDD
    DIRECTION INOUT ;
    USE POWER ;
    SHAPE ABUTMENT ;
    PORT
      LAYER M1 ;
        RECT 0 0.261 0.27 0.279 ;
    END
  END VDD
  PIN VSS
    DIRECTION INOUT ;
    USE GROUND ;
    SHAPE ABUTMENT ;
    PORT
      LAYER M1 ;
        RECT 0 -0.009 0.27 0.009 ;
    END
  END VSS
  PIN Y
    DIRECTION OUTPUT ;
    USE SIGNAL ;
    PORT
      LAYER M1 ;
        RECT 0.094 0.225 0.252 0.243 ;
        RECT 0.234 0.027 0.252 0.243 ;
        RECT 0.094 0.027 0.252 0.045 ;
    END
  END Y
END INVx3_bottom

MACRO INVx4_bottom
  CLASS CORE ;
  ORIGIN 0 0 ;
  FOREIGN INVx4_bottom 0 0 ;
  SIZE 0.054 BY 0.270 ;
  SYMMETRY X Y ;
  SITE asap7sc7p5t ;
  PIN A
    DIRECTION INPUT ;
    USE SIGNAL ;
    PORT
      LAYER M1 ;
        RECT 0.018 0.126 0.078 0.144 ;
        RECT 0.018 0.225 0.055 0.243 ;
        RECT 0.018 0.027 0.055 0.045 ;
        RECT 0.018 0.027 0.036 0.243 ;
    END
  END A
  PIN VDD
    DIRECTION INOUT ;
    USE POWER ;
    SHAPE ABUTMENT ;
    PORT
      LAYER M1 ;
        RECT 0 0.261 0.324 0.279 ;
    END
  END VDD
  PIN VSS
    DIRECTION INOUT ;
    USE GROUND ;
    SHAPE ABUTMENT ;
    PORT
      LAYER M1 ;
        RECT 0 -0.009 0.324 0.009 ;
    END
  END VSS
  PIN Y
    DIRECTION OUTPUT ;
    USE SIGNAL ;
    PORT
      LAYER M1 ;
        RECT 0.094 0.225 0.306 0.243 ;
        RECT 0.288 0.027 0.306 0.243 ;
        RECT 0.094 0.027 0.306 0.045 ;
    END
  END Y
END INVx4_bottom

MACRO INVx5_bottom
  CLASS CORE ;
  ORIGIN 0 0 ;
  FOREIGN INVx5_bottom 0 0 ;
  SIZE 0.054 BY 0.270 ;
  SYMMETRY X Y ;
  SITE asap7sc7p5t ;
  PIN A
    DIRECTION INPUT ;
    USE SIGNAL ;
    PORT
      LAYER M1 ;
        RECT 0.018 0.126 0.078 0.144 ;
        RECT 0.018 0.225 0.055 0.243 ;
        RECT 0.018 0.027 0.055 0.045 ;
        RECT 0.018 0.027 0.036 0.243 ;
    END
  END A
  PIN VDD
    DIRECTION INOUT ;
    USE POWER ;
    SHAPE ABUTMENT ;
    PORT
      LAYER M1 ;
        RECT 0 0.261 0.378 0.279 ;
    END
  END VDD
  PIN VSS
    DIRECTION INOUT ;
    USE GROUND ;
    SHAPE ABUTMENT ;
    PORT
      LAYER M1 ;
        RECT 0 -0.009 0.378 0.009 ;
    END
  END VSS
  PIN Y
    DIRECTION OUTPUT ;
    USE SIGNAL ;
    PORT
      LAYER M1 ;
        RECT 0.094 0.225 0.36 0.243 ;
        RECT 0.342 0.027 0.36 0.243 ;
        RECT 0.094 0.027 0.36 0.045 ;
    END
  END Y
END INVx5_bottom

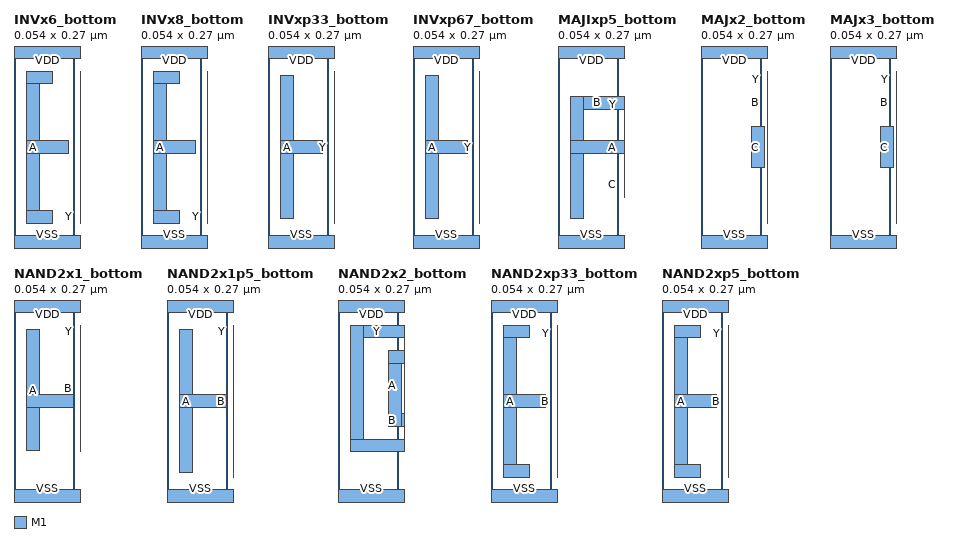
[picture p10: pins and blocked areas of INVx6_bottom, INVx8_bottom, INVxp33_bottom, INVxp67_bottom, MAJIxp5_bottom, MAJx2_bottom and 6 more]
MACRO INVx6_bottom
  CLASS CORE ;
  ORIGIN 0 0 ;
  FOREIGN INVx6_bottom 0 0 ;
  SIZE 0.054 BY 0.270 ;
  SYMMETRY X Y ;
  SITE asap7sc7p5t ;
  PIN A
    DIRECTION INPUT ;
    USE SIGNAL ;
    PORT
      LAYER M1 ;
        RECT 0.018 0.126 0.078 0.144 ;
        RECT 0.018 0.225 0.055 0.243 ;
        RECT 0.018 0.027 0.055 0.045 ;
        RECT 0.018 0.027 0.036 0.243 ;
    END
  END A
  PIN VDD
    DIRECTION INOUT ;
    USE POWER ;
    SHAPE ABUTMENT ;
    PORT
      LAYER M1 ;
        RECT 0 0.261 0.432 0.279 ;
    END
  END VDD
  PIN VSS
    DIRECTION INOUT ;
    USE GROUND ;
    SHAPE ABUTMENT ;
    PORT
      LAYER M1 ;
        RECT 0 -0.009 0.432 0.009 ;
    END
  END VSS
  PIN Y
    DIRECTION OUTPUT ;
    USE SIGNAL ;
    PORT
      LAYER M1 ;
        RECT 0.094 0.225 0.414 0.243 ;
        RECT 0.396 0.027 0.414 0.243 ;
        RECT 0.094 0.027 0.414 0.045 ;
    END
  END Y
END INVx6_bottom

MACRO INVx8_bottom
  CLASS CORE ;
  ORIGIN 0 0 ;
  FOREIGN INVx8_bottom 0 0 ;
  SIZE 0.054 BY 0.270 ;
  SYMMETRY X Y ;
  SITE asap7sc7p5t ;
  PIN A
    DIRECTION INPUT ;
    USE SIGNAL ;
    PORT
      LAYER M1 ;
        RECT 0.018 0.126 0.078 0.144 ;
        RECT 0.018 0.225 0.055 0.243 ;
        RECT 0.018 0.027 0.055 0.045 ;
        RECT 0.018 0.027 0.036 0.243 ;
    END
  END A
  PIN VDD
    DIRECTION INOUT ;
    USE POWER ;
    SHAPE ABUTMENT ;
    PORT
      LAYER M1 ;
        RECT 0 0.261 0.54 0.279 ;
    END
  END VDD
  PIN VSS
    DIRECTION INOUT ;
    USE GROUND ;
    SHAPE ABUTMENT ;
    PORT
      LAYER M1 ;
        RECT 0 -0.009 0.54 0.009 ;
    END
  END VSS
  PIN Y
    DIRECTION OUTPUT ;
    USE SIGNAL ;
    PORT
      LAYER M1 ;
        RECT 0.094 0.225 0.522 0.243 ;
        RECT 0.504 0.027 0.522 0.243 ;
        RECT 0.094 0.027 0.522 0.045 ;
    END
  END Y
END INVx8_bottom

MACRO INVxp33_bottom
  CLASS CORE ;
  ORIGIN 0 0 ;
  FOREIGN INVxp33_bottom 0 0 ;
  SIZE 0.054 BY 0.270 ;
  SYMMETRY X Y ;
  SITE asap7sc7p5t ;
  PIN A
    DIRECTION INPUT ;
    USE SIGNAL ;
    PORT
      LAYER M1 ;
        RECT 0.018 0.126 0.078 0.144 ;
        RECT 0.018 0.034 0.036 0.236 ;
    END
  END A
  PIN VDD
    DIRECTION INOUT ;
    USE POWER ;
    SHAPE ABUTMENT ;
    PORT
      LAYER M1 ;
        RECT 0 0.261 0.162 0.279 ;
    END
  END VDD
  PIN VSS
    DIRECTION INOUT ;
    USE GROUND ;
    SHAPE ABUTMENT ;
    PORT
      LAYER M1 ;
        RECT 0 -0.009 0.162 0.009 ;
    END
  END VSS
  PIN Y
    DIRECTION OUTPUT ;
    USE SIGNAL ;
    PORT
      LAYER M1 ;
        RECT 0.094 0.225 0.144 0.243 ;
        RECT 0.126 0.027 0.144 0.243 ;
        RECT 0.094 0.027 0.144 0.045 ;
    END
  END Y
END INVxp33_bottom

MACRO INVxp67_bottom
  CLASS CORE ;
  ORIGIN 0 0 ;
  FOREIGN INVxp67_bottom 0 0 ;
  SIZE 0.054 BY 0.270 ;
  SYMMETRY X Y ;
  SITE asap7sc7p5t ;
  PIN A
    DIRECTION INPUT ;
    USE SIGNAL ;
    PORT
      LAYER M1 ;
        RECT 0.018 0.126 0.078 0.144 ;
        RECT 0.018 0.034 0.036 0.236 ;
    END
  END A
  PIN VDD
    DIRECTION INOUT ;
    USE POWER ;
    SHAPE ABUTMENT ;
    PORT
      LAYER M1 ;
        RECT 0 0.261 0.162 0.279 ;
    END
  END VDD
  PIN VSS
    DIRECTION INOUT ;
    USE GROUND ;
    SHAPE ABUTMENT ;
    PORT
      LAYER M1 ;
        RECT 0 -0.009 0.162 0.009 ;
    END
  END VSS
  PIN Y
    DIRECTION OUTPUT ;
    USE SIGNAL ;
    PORT
      LAYER M1 ;
        RECT 0.094 0.225 0.144 0.243 ;
        RECT 0.126 0.027 0.144 0.243 ;
        RECT 0.094 0.027 0.144 0.045 ;
    END
  END Y
END INVxp67_bottom

MACRO MAJIxp5_bottom
  CLASS CORE ;
  ORIGIN 0 0 ;
  FOREIGN MAJIxp5_bottom 0 0 ;
  SIZE 0.054 BY 0.270 ;
  SYMMETRY X Y ;
  SITE asap7sc7p5t ;
  PIN A
    DIRECTION INPUT ;
    USE SIGNAL ;
    PORT
      LAYER M1 ;
        RECT 0.288 0.106 0.306 0.164 ;
    END
  END A
  PIN B
    DIRECTION INPUT ;
    USE SIGNAL ;
    PORT
      LAYER M1 ;
        RECT 0.18 0.126 0.257 0.144 ;
        RECT 0.018 0.189 0.198 0.207 ;
        RECT 0.18 0.126 0.198 0.207 ;
        RECT 0.018 0.126 0.095 0.144 ;
        RECT 0.018 0.034 0.036 0.207 ;
    END
  END B
  PIN C
    DIRECTION INPUT ;
    USE SIGNAL ;
    PORT
      LAYER M1 ;
        RECT 0.126 0.07 0.144 0.164 ;
    END
  END C
  PIN VDD
    DIRECTION INOUT ;
    USE POWER ;
    SHAPE ABUTMENT ;
    PORT
      LAYER M1 ;
        RECT 0 0.261 0.378 0.279 ;
    END
  END VDD
  PIN VSS
    DIRECTION INOUT ;
    USE GROUND ;
    SHAPE ABUTMENT ;
    PORT
      LAYER M1 ;
        RECT 0 -0.009 0.378 0.009 ;
    END
  END VSS
  PIN Y
    DIRECTION OUTPUT ;
    USE SIGNAL ;
    PORT
      LAYER M1 ;
        RECT 0.255 0.189 0.361 0.207 ;
        RECT 0.343 0.063 0.361 0.207 ;
        RECT 0.255 0.063 0.361 0.081 ;
    END
  END Y
  OBS
    LAYER M1 ;
      RECT 0 0 0 0 ;
  END
END MAJIxp5_bottom

MACRO MAJx2_bottom
  CLASS CORE ;
  ORIGIN 0 0 ;
  FOREIGN MAJx2_bottom 0 0 ;
  SIZE 0.054 BY 0.270 ;
  SYMMETRY X Y ;
  SITE asap7sc7p5t ;
  PIN A
    DIRECTION INPUT ;
    USE SIGNAL ;
    PORT
      LAYER M1 ;
        RECT 0.072 0.106 0.09 0.164 ;
    END
  END A
  PIN B
    DIRECTION INPUT ;
    USE SIGNAL ;
    PORT
      LAYER M1 ;
        RECT 0.18 0.189 0.333 0.207 ;
        RECT 0.315 0.106 0.333 0.207 ;
        RECT 0.283 0.126 0.333 0.144 ;
        RECT 0.18 0.126 0.198 0.207 ;
        RECT 0.121 0.126 0.198 0.144 ;
    END
  END B
  PIN C
    DIRECTION INPUT ;
    USE SIGNAL ;
    PORT
      LAYER M1 ;
        RECT 0.234 0.106 0.252 0.164 ;
    END
  END C
  PIN VDD
    DIRECTION INOUT ;
    USE POWER ;
    SHAPE ABUTMENT ;
    PORT
      LAYER M1 ;
        RECT 0 0.261 0.486 0.279 ;
    END
  END VDD
  PIN VSS
    DIRECTION INOUT ;
    USE GROUND ;
    SHAPE ABUTMENT ;
    PORT
      LAYER M1 ;
        RECT 0 -0.009 0.486 0.009 ;
    END
  END VSS
  PIN Y
    DIRECTION OUTPUT ;
    USE SIGNAL ;
    PORT
      LAYER M1 ;
        RECT 0.364 0.225 0.468 0.243 ;
        RECT 0.45 0.027 0.468 0.243 ;
        RECT 0.364 0.027 0.468 0.045 ;
    END
  END Y
  OBS
    LAYER M1 ;
      RECT 0 0 0 0 ;
  END
END MAJx2_bottom

MACRO MAJx3_bottom
  CLASS CORE ;
  ORIGIN 0 0 ;
  FOREIGN MAJx3_bottom 0 0 ;
  SIZE 0.054 BY 0.270 ;
  SYMMETRY X Y ;
  SITE asap7sc7p5t ;
  PIN A
    DIRECTION INPUT ;
    USE SIGNAL ;
    PORT
      LAYER M1 ;
        RECT 0.072 0.106 0.09 0.164 ;
    END
  END A
  PIN B
    DIRECTION INPUT ;
    USE SIGNAL ;
    PORT
      LAYER M1 ;
        RECT 0.18 0.189 0.333 0.207 ;
        RECT 0.315 0.106 0.333 0.207 ;
        RECT 0.283 0.126 0.333 0.144 ;
        RECT 0.18 0.126 0.198 0.207 ;
        RECT 0.121 0.126 0.198 0.144 ;
    END
  END B
  PIN C
    DIRECTION INPUT ;
    USE SIGNAL ;
    PORT
      LAYER M1 ;
        RECT 0.234 0.106 0.252 0.164 ;
    END
  END C
  PIN VDD
    DIRECTION INOUT ;
    USE POWER ;
    SHAPE ABUTMENT ;
    PORT
      LAYER M1 ;
        RECT 0 0.261 0.54 0.279 ;
    END
  END VDD
  PIN VSS
    DIRECTION INOUT ;
    USE GROUND ;
    SHAPE ABUTMENT ;
    PORT
      LAYER M1 ;
        RECT 0 -0.009 0.54 0.009 ;
    END
  END VSS
  PIN Y
    DIRECTION OUTPUT ;
    USE SIGNAL ;
    PORT
      LAYER M1 ;
        RECT 0.364 0.225 0.504 0.243 ;
        RECT 0.364 0.027 0.504 0.045 ;
        RECT 0.45 0.027 0.468 0.243 ;
    END
  END Y
  OBS
    LAYER M1 ;
      RECT 0 0 0 0 ;
  END
END MAJx3_bottom

MACRO NAND2x1_bottom
  CLASS CORE ;
  ORIGIN 0 0 ;
  FOREIGN NAND2x1_bottom 0 0 ;
  SIZE 0.054 BY 0.270 ;
  SYMMETRY X Y ;
  SITE asap7sc7p5t ;
  PIN A
    DIRECTION INPUT ;
    USE SIGNAL ;
    PORT
      LAYER M1 ;
        RECT 0.018 0.126 0.084 0.144 ;
        RECT 0.018 0.065 0.036 0.236 ;
    END
  END A
  PIN B
    DIRECTION INPUT ;
    USE SIGNAL ;
    PORT
      LAYER M1 ;
        RECT 0.234 0.106 0.252 0.2 ;
    END
  END B
  PIN VDD
    DIRECTION INOUT ;
    USE POWER ;
    SHAPE ABUTMENT ;
    PORT
      LAYER M1 ;
        RECT 0 0.261 0.324 0.279 ;
    END
  END VDD
  PIN VSS
    DIRECTION INOUT ;
    USE GROUND ;
    SHAPE ABUTMENT ;
    PORT
      LAYER M1 ;
        RECT 0 -0.009 0.324 0.009 ;
    END
  END VSS
  PIN Y
    DIRECTION OUTPUT ;
    USE SIGNAL ;
    PORT
      LAYER M1 ;
        RECT 0.094 0.225 0.306 0.243 ;
        RECT 0.288 0.063 0.306 0.243 ;
        RECT 0.202 0.063 0.306 0.081 ;
    END
  END Y
  OBS
    LAYER M1 ;
      RECT 0 0 0 0 ;
  END
END NAND2x1_bottom

MACRO NAND2x1p5_bottom
  CLASS CORE ;
  ORIGIN 0 0 ;
  FOREIGN NAND2x1p5_bottom 0 0 ;
  SIZE 0.054 BY 0.270 ;
  SYMMETRY X Y ;
  SITE asap7sc7p5t ;
  PIN A
    DIRECTION INPUT ;
    USE SIGNAL ;
    PORT
      LAYER M1 ;
        RECT 0.018 0.126 0.084 0.144 ;
        RECT 0.018 0.034 0.036 0.236 ;
    END
  END A
  PIN B
    DIRECTION INPUT ;
    USE SIGNAL ;
    PORT
      LAYER M1 ;
        RECT 0.126 0.126 0.257 0.144 ;
        RECT 0.126 0.07 0.144 0.2 ;
    END
  END B
  PIN VDD
    DIRECTION INOUT ;
    USE POWER ;
    SHAPE ABUTMENT ;
    PORT
      LAYER M1 ;
        RECT 0 0.261 0.432 0.279 ;
    END
  END VDD
  PIN VSS
    DIRECTION INOUT ;
    USE GROUND ;
    SHAPE ABUTMENT ;
    PORT
      LAYER M1 ;
        RECT 0 -0.009 0.432 0.009 ;
    END
  END VSS
  PIN Y
    DIRECTION OUTPUT ;
    USE SIGNAL ;
    PORT
      LAYER M1 ;
        RECT 0.094 0.225 0.414 0.243 ;
        RECT 0.396 0.027 0.414 0.243 ;
        RECT 0.261 0.027 0.414 0.045 ;
    END
  END Y
  OBS
    LAYER M1 ;
      RECT 0 0 0 0 ;
  END
END NAND2x1p5_bottom

MACRO NAND2x2_bottom
  CLASS CORE ;
  ORIGIN 0 0 ;
  FOREIGN NAND2x2_bottom 0 0 ;
  SIZE 0.054 BY 0.270 ;
  SYMMETRY X Y ;
  SITE asap7sc7p5t ;
  PIN A
    DIRECTION INPUT ;
    USE SIGNAL ;
    PORT
      LAYER M1 ;
        RECT 0.242 0.189 0.279 0.207 ;
        RECT 0.261 0.106 0.279 0.207 ;
    END
  END A
  PIN B
    DIRECTION INPUT ;
    USE SIGNAL ;
    PORT
      LAYER M1 ;
        RECT 0.45 0.099 0.468 0.177 ;
        RECT 0.322 0.099 0.468 0.117 ;
        RECT 0.322 0.063 0.34 0.117 ;
        RECT 0.2 0.063 0.34 0.081 ;
        RECT 0.072 0.099 0.218 0.117 ;
        RECT 0.2 0.063 0.218 0.117 ;
        RECT 0.072 0.189 0.109 0.207 ;
        RECT 0.072 0.099 0.09 0.207 ;
    END
  END B
  PIN VDD
    DIRECTION INOUT ;
    USE POWER ;
    SHAPE ABUTMENT ;
    PORT
      LAYER M1 ;
        RECT 0 0.261 0.54 0.279 ;
    END
  END VDD
  PIN VSS
    DIRECTION INOUT ;
    USE GROUND ;
    SHAPE ABUTMENT ;
    PORT
      LAYER M1 ;
        RECT 0 -0.009 0.54 0.009 ;
    END
  END VSS
  PIN Y
    DIRECTION OUTPUT ;
    USE SIGNAL ;
    PORT
      LAYER M1 ;
        RECT 0.018 0.225 0.522 0.243 ;
        RECT 0.504 0.063 0.522 0.243 ;
        RECT 0.418 0.063 0.522 0.081 ;
        RECT 0.018 0.063 0.122 0.081 ;
        RECT 0.018 0.063 0.036 0.243 ;
    END
  END Y
  OBS
    LAYER M1 ;
      RECT 0 0 0 0 ;
  END
END NAND2x2_bottom

MACRO NAND2xp33_bottom
  CLASS CORE ;
  ORIGIN 0 0 ;
  FOREIGN NAND2xp33_bottom 0 0 ;
  SIZE 0.054 BY 0.270 ;
  SYMMETRY X Y ;
  SITE asap7sc7p5t ;
  PIN A
    DIRECTION INPUT ;
    USE SIGNAL ;
    PORT
      LAYER M1 ;
        RECT 0.018 0.126 0.078 0.144 ;
        RECT 0.018 0.225 0.055 0.243 ;
        RECT 0.018 0.027 0.055 0.045 ;
        RECT 0.018 0.027 0.036 0.243 ;
    END
  END A
  PIN B
    DIRECTION INPUT ;
    USE SIGNAL ;
    PORT
      LAYER M1 ;
        RECT 0.107 0.189 0.144 0.207 ;
        RECT 0.126 0.063 0.144 0.207 ;
        RECT 0.107 0.063 0.144 0.081 ;
    END
  END B
  PIN VDD
    DIRECTION INOUT ;
    USE POWER ;
    SHAPE ABUTMENT ;
    PORT
      LAYER M1 ;
        RECT 0 0.261 0.216 0.279 ;
    END
  END VDD
  PIN VSS
    DIRECTION INOUT ;
    USE GROUND ;
    SHAPE ABUTMENT ;
    PORT
      LAYER M1 ;
        RECT 0 -0.009 0.216 0.009 ;
    END
  END VSS
  PIN Y
    DIRECTION OUTPUT ;
    USE SIGNAL ;
    PORT
      LAYER M1 ;
        RECT 0.094 0.225 0.198 0.243 ;
        RECT 0.18 0.027 0.198 0.243 ;
        RECT 0.143 0.027 0.198 0.045 ;
    END
  END Y
END NAND2xp33_bottom

MACRO NAND2xp5_bottom
  CLASS CORE ;
  ORIGIN 0 0 ;
  FOREIGN NAND2xp5_bottom 0 0 ;
  SIZE 0.054 BY 0.270 ;
  SYMMETRY X Y ;
  SITE asap7sc7p5t ;
  PIN A
    DIRECTION INPUT ;
    USE SIGNAL ;
    PORT
      LAYER M1 ;
        RECT 0.018 0.126 0.078 0.144 ;
        RECT 0.018 0.225 0.055 0.243 ;
        RECT 0.018 0.027 0.055 0.045 ;
        RECT 0.018 0.027 0.036 0.243 ;
    END
  END A
  PIN B
    DIRECTION INPUT ;
    USE SIGNAL ;
    PORT
      LAYER M1 ;
        RECT 0.107 0.189 0.144 0.207 ;
        RECT 0.126 0.063 0.144 0.207 ;
        RECT 0.106 0.063 0.144 0.081 ;
    END
  END B
  PIN VDD
    DIRECTION INOUT ;
    USE POWER ;
    SHAPE ABUTMENT ;
    PORT
      LAYER M1 ;
        RECT 0 0.261 0.216 0.279 ;
    END
  END VDD
  PIN VSS
    DIRECTION INOUT ;
    USE GROUND ;
    SHAPE ABUTMENT ;
    PORT
      LAYER M1 ;
        RECT 0 -0.009 0.216 0.009 ;
    END
  END VSS
  PIN Y
    DIRECTION OUTPUT ;
    USE SIGNAL ;
    PORT
      LAYER M1 ;
        RECT 0.094 0.225 0.198 0.243 ;
        RECT 0.18 0.027 0.198 0.243 ;
        RECT 0.143 0.027 0.198 0.045 ;
    END
  END Y
END NAND2xp5_bottom

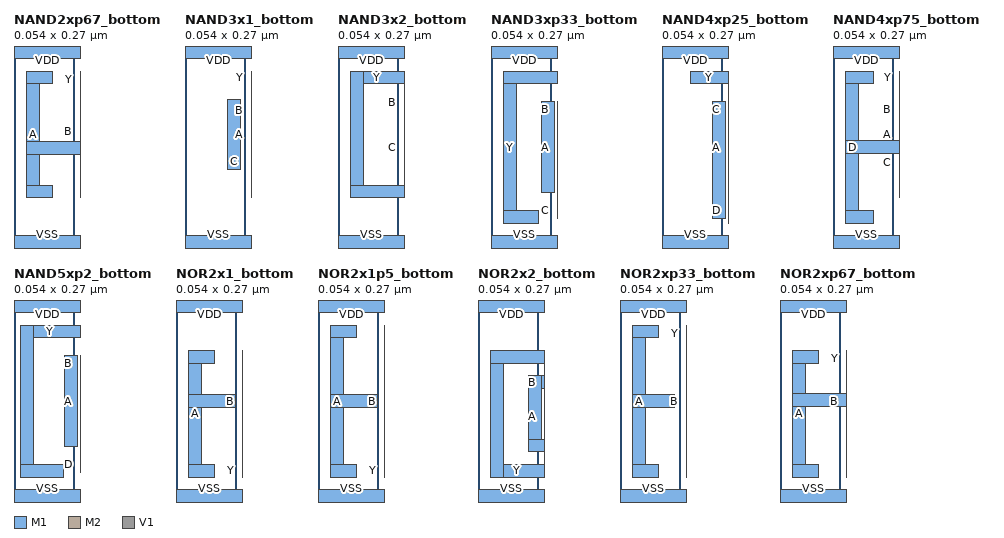
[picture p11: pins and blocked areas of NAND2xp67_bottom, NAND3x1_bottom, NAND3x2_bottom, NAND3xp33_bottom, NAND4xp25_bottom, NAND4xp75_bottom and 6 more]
MACRO NAND2xp67_bottom
  CLASS CORE ;
  ORIGIN 0 0 ;
  FOREIGN NAND2xp67_bottom 0 0 ;
  SIZE 0.054 BY 0.270 ;
  SYMMETRY X Y ;
  SITE asap7sc7p5t ;
  PIN A
    DIRECTION INPUT ;
    USE SIGNAL ;
    PORT
      LAYER M1 ;
        RECT 0.018 0.125 0.095 0.143 ;
        RECT 0.018 0.225 0.055 0.243 ;
        RECT 0.018 0.063 0.055 0.081 ;
        RECT 0.018 0.063 0.036 0.243 ;
    END
  END A
  PIN B
    DIRECTION INPUT ;
    USE SIGNAL ;
    PORT
      LAYER M1 ;
        RECT 0.215 0.189 0.252 0.207 ;
        RECT 0.234 0.106 0.252 0.207 ;
    END
  END B
  PIN VDD
    DIRECTION INOUT ;
    USE POWER ;
    SHAPE ABUTMENT ;
    PORT
      LAYER M1 ;
        RECT 0 0.261 0.324 0.279 ;
    END
  END VDD
  PIN VSS
    DIRECTION INOUT ;
    USE GROUND ;
    SHAPE ABUTMENT ;
    PORT
      LAYER M1 ;
        RECT 0 -0.009 0.324 0.009 ;
    END
  END VSS
  PIN Y
    DIRECTION OUTPUT ;
    USE SIGNAL ;
    PORT
      LAYER M1 ;
        RECT 0.148 0.225 0.306 0.243 ;
        RECT 0.288 0.063 0.306 0.243 ;
        RECT 0.202 0.063 0.306 0.081 ;
    END
  END Y
  OBS
    LAYER M1 ;
      RECT 0 0 0 0 ;
  END
END NAND2xp67_bottom

MACRO NAND3x1_bottom
  CLASS CORE ;
  ORIGIN 0 0 ;
  FOREIGN NAND3x1_bottom 0 0 ;
  SIZE 0.054 BY 0.270 ;
  SYMMETRY X Y ;
  SITE asap7sc7p5t ;
  PIN A
    DIRECTION INPUT ;
    USE SIGNAL ;
    PORT
      LAYER M1 ;
        RECT 0.402 0.18 0.468 0.198 ;
        RECT 0.45 0.108 0.468 0.198 ;
        RECT 0.4 0.108 0.468 0.126 ;
    END
  END A
  PIN B
    DIRECTION INPUT ;
    USE SIGNAL ;
    PORT
      LAYER M1 ;
        RECT 0.243 0.18 0.306 0.198 ;
        RECT 0.288 0.108 0.306 0.198 ;
        RECT 0.246 0.108 0.306 0.126 ;
    END
  END B
  PIN C
    DIRECTION INPUT ;
    USE SIGNAL ;
    PORT
      LAYER M1 ;
        RECT 0.061 0.103 0.079 0.203 ;
    END
  END C
  PIN VDD
    DIRECTION INOUT ;
    USE POWER ;
    SHAPE ABUTMENT ;
    PORT
      LAYER M1 ;
        RECT 0 0.261 0.594 0.279 ;
    END
  END VDD
  PIN VSS
    DIRECTION INOUT ;
    USE GROUND ;
    SHAPE ABUTMENT ;
    PORT
      LAYER M1 ;
        RECT 0 -0.009 0.594 0.009 ;
    END
  END VSS
  PIN Y
    DIRECTION OUTPUT ;
    USE SIGNAL ;
    PORT
      LAYER M1 ;
        RECT 0.202 0.225 0.576 0.243 ;
        RECT 0.558 0.063 0.576 0.243 ;
        RECT 0.418 0.063 0.576 0.081 ;
    END
  END Y
  OBS
    LAYER M1 ;
      RECT 0 0 0 0 ;
  END
END NAND3x1_bottom

MACRO NAND3x2_bottom
  CLASS CORE ;
  ORIGIN 0 0 ;
  FOREIGN NAND3x2_bottom 0 0 ;
  SIZE 0.054 BY 0.270 ;
  SYMMETRY X Y ;
  SITE asap7sc7p5t ;
  PIN B
    DIRECTION INPUT ;
    USE SIGNAL ;
    PORT
      LAYER M1 ;
        RECT 0.338 0.189 0.743 0.207 ;
        RECT 0.725 0.106 0.743 0.207 ;
        RECT 0.338 0.106 0.356 0.207 ;
    END
  END B
  PIN C
    DIRECTION INPUT ;
    USE SIGNAL ;
    PORT
      LAYER M1 ;
        RECT 0.547 0.106 0.565 0.164 ;
    END
  END C
  PIN VDD
    DIRECTION INOUT ;
    USE POWER ;
    SHAPE ABUTMENT ;
    PORT
      LAYER M1 ;
        RECT 0 0.261 1.08 0.279 ;
    END
  END VDD
  PIN VSS
    DIRECTION INOUT ;
    USE GROUND ;
    SHAPE ABUTMENT ;
    PORT
      LAYER M1 ;
        RECT 0 -0.009 1.08 0.009 ;
    END
  END VSS
  PIN Y
    DIRECTION OUTPUT ;
    USE SIGNAL ;
    PORT
      LAYER M1 ;
        RECT 0.018 0.225 1.062 0.243 ;
        RECT 1.044 0.063 1.062 0.243 ;
        RECT 0.904 0.063 1.062 0.081 ;
        RECT 0.018 0.063 0.176 0.081 ;
        RECT 0.018 0.063 0.036 0.243 ;
    END
  END Y
  PIN A
    DIRECTION INPUT ;
    USE SIGNAL ;
    PORT
      LAYER M2 ;
        RECT 0.169 0.18 0.908 0.198 ;
      LAYER M1 ;
        RECT 0.866 0.189 0.903 0.207 ;
        RECT 0.885 0.108 0.903 0.207 ;
        RECT 0.174 0.189 0.211 0.207 ;
        RECT 0.174 0.106 0.192 0.207 ;
      LAYER V1 ;
        RECT 0.174 0.18 0.192 0.198 ;
        RECT 0.885 0.18 0.903 0.198 ;
    END
  END A
  OBS
    LAYER M1 ;
      RECT 0 0 0 0 ;
  END
END NAND3x2_bottom

MACRO NAND3xp33_bottom
  CLASS CORE ;
  ORIGIN 0 0 ;
  FOREIGN NAND3xp33_bottom 0 0 ;
  SIZE 0.054 BY 0.270 ;
  SYMMETRY X Y ;
  SITE asap7sc7p5t ;
  PIN A
    DIRECTION INPUT ;
    USE SIGNAL ;
    PORT
      LAYER M1 ;
        RECT 0.072 0.07 0.09 0.2 ;
    END
  END A
  PIN B
    DIRECTION INPUT ;
    USE SIGNAL ;
    PORT
      LAYER M1 ;
        RECT 0.126 0.034 0.144 0.2 ;
    END
  END B
  PIN C
    DIRECTION INPUT ;
    USE SIGNAL ;
    PORT
      LAYER M1 ;
        RECT 0.18 0.034 0.198 0.2 ;
    END
  END C
  PIN VDD
    DIRECTION INOUT ;
    USE POWER ;
    SHAPE ABUTMENT ;
    PORT
      LAYER M1 ;
        RECT 0 0.261 0.27 0.279 ;
    END
  END VDD
  PIN VSS
    DIRECTION INOUT ;
    USE GROUND ;
    SHAPE ABUTMENT ;
    PORT
      LAYER M1 ;
        RECT 0 -0.009 0.27 0.009 ;
    END
  END VSS
  PIN Y
    DIRECTION OUTPUT ;
    USE SIGNAL ;
    PORT
      LAYER M1 ;
        RECT 0.018 0.225 0.176 0.243 ;
        RECT 0.018 0.027 0.068 0.045 ;
        RECT 0.018 0.027 0.036 0.243 ;
    END
  END Y
END NAND3xp33_bottom

MACRO NAND4xp25_bottom
  CLASS CORE ;
  ORIGIN 0 0 ;
  FOREIGN NAND4xp25_bottom 0 0 ;
  SIZE 0.054 BY 0.270 ;
  SYMMETRY X Y ;
  SITE asap7sc7p5t ;
  PIN A
    DIRECTION INPUT ;
    USE SIGNAL ;
    PORT
      LAYER M1 ;
        RECT 0.234 0.07 0.252 0.2 ;
    END
  END A
  PIN B
    DIRECTION INPUT ;
    USE SIGNAL ;
    PORT
      LAYER M1 ;
        RECT 0.18 0.034 0.198 0.2 ;
    END
  END B
  PIN C
    DIRECTION INPUT ;
    USE SIGNAL ;
    PORT
      LAYER M1 ;
        RECT 0.126 0.034 0.144 0.2 ;
    END
  END C
  PIN D
    DIRECTION INPUT ;
    USE SIGNAL ;
    PORT
      LAYER M1 ;
        RECT 0.072 0.034 0.09 0.2 ;
    END
  END D
  PIN VDD
    DIRECTION INOUT ;
    USE POWER ;
    SHAPE ABUTMENT ;
    PORT
      LAYER M1 ;
        RECT 0 0.261 0.324 0.279 ;
    END
  END VDD
  PIN VSS
    DIRECTION INOUT ;
    USE GROUND ;
    SHAPE ABUTMENT ;
    PORT
      LAYER M1 ;
        RECT 0 -0.009 0.324 0.009 ;
    END
  END VSS
  PIN Y
    DIRECTION OUTPUT ;
    USE SIGNAL ;
    PORT
      LAYER M1 ;
        RECT 0.04 0.225 0.306 0.243 ;
        RECT 0.288 0.027 0.306 0.243 ;
        RECT 0.256 0.027 0.306 0.045 ;
    END
  END Y
END NAND4xp25_bottom

MACRO NAND4xp75_bottom
  CLASS CORE ;
  ORIGIN 0 0 ;
  FOREIGN NAND4xp75_bottom 0 0 ;
  SIZE 0.054 BY 0.270 ;
  SYMMETRY X Y ;
  SITE asap7sc7p5t ;
  PIN A
    DIRECTION INPUT ;
    USE SIGNAL ;
    PORT
      LAYER M1 ;
        RECT 0.612 0.106 0.63 0.2 ;
    END
  END A
  PIN B
    DIRECTION INPUT ;
    USE SIGNAL ;
    PORT
      LAYER M1 ;
        RECT 0.504 0.101 0.549 0.119 ;
        RECT 0.531 0.07 0.549 0.119 ;
        RECT 0.504 0.101 0.522 0.2 ;
    END
  END B
  PIN C
    DIRECTION INPUT ;
    USE SIGNAL ;
    PORT
      LAYER M1 ;
        RECT 0.288 0.101 0.306 0.2 ;
        RECT 0.207 0.101 0.306 0.119 ;
        RECT 0.207 0.07 0.225 0.119 ;
    END
  END C
  PIN D
    DIRECTION INPUT ;
    USE SIGNAL ;
    PORT
      LAYER M1 ;
        RECT 0.018 0.126 0.095 0.144 ;
        RECT 0.018 0.225 0.057 0.243 ;
        RECT 0.018 0.027 0.057 0.045 ;
        RECT 0.018 0.027 0.036 0.243 ;
    END
  END D
  PIN VDD
    DIRECTION INOUT ;
    USE POWER ;
    SHAPE ABUTMENT ;
    PORT
      LAYER M1 ;
        RECT 0 0.261 0.756 0.279 ;
    END
  END VDD
  PIN VSS
    DIRECTION INOUT ;
    USE GROUND ;
    SHAPE ABUTMENT ;
    PORT
      LAYER M1 ;
        RECT 0 -0.009 0.756 0.009 ;
    END
  END VSS
  PIN Y
    DIRECTION OUTPUT ;
    USE SIGNAL ;
    PORT
      LAYER M1 ;
        RECT 0.094 0.225 0.738 0.243 ;
        RECT 0.72 0.063 0.738 0.243 ;
        RECT 0.58 0.063 0.738 0.081 ;
    END
  END Y
  OBS
    LAYER M1 ;
      RECT 0 0 0 0 ;
  END
END NAND4xp75_bottom

MACRO NAND5xp2_bottom
  CLASS CORE ;
  ORIGIN 0 0 ;
  FOREIGN NAND5xp2_bottom 0 0 ;
  SIZE 0.054 BY 0.270 ;
  SYMMETRY X Y ;
  SITE asap7sc7p5t ;
  PIN A
    DIRECTION INPUT ;
    USE SIGNAL ;
    PORT
      LAYER M1 ;
        RECT 0.072 0.07 0.09 0.2 ;
    END
  END A
  PIN B
    DIRECTION INPUT ;
    USE SIGNAL ;
    PORT
      LAYER M1 ;
        RECT 0.126 0.034 0.144 0.2 ;
    END
  END B
  PIN C
    DIRECTION INPUT ;
    USE SIGNAL ;
    PORT
      LAYER M1 ;
        RECT 0.18 0.034 0.198 0.2 ;
    END
  END C
  PIN D
    DIRECTION INPUT ;
    USE SIGNAL ;
    PORT
      LAYER M1 ;
        RECT 0.234 0.034 0.252 0.2 ;
    END
  END D
  PIN E
    DIRECTION INPUT ;
    USE SIGNAL ;
    PORT
      LAYER M1 ;
        RECT 0.288 0.034 0.306 0.2 ;
    END
  END E
  PIN VDD
    DIRECTION INOUT ;
    USE POWER ;
    SHAPE ABUTMENT ;
    PORT
      LAYER M1 ;
        RECT 0 0.261 0.378 0.279 ;
    END
  END VDD
  PIN VSS
    DIRECTION INOUT ;
    USE GROUND ;
    SHAPE ABUTMENT ;
    PORT
      LAYER M1 ;
        RECT 0 -0.009 0.378 0.009 ;
    END
  END VSS
  PIN Y
    DIRECTION OUTPUT ;
    USE SIGNAL ;
    PORT
      LAYER M1 ;
        RECT 0.009 0.225 0.317 0.243 ;
        RECT 0.009 0.027 0.07 0.045 ;
        RECT 0.009 0.027 0.027 0.243 ;
    END
  END Y
END NAND5xp2_bottom

MACRO NOR2x1_bottom
  CLASS CORE ;
  ORIGIN 0 0 ;
  FOREIGN NOR2x1_bottom 0 0 ;
  SIZE 0.054 BY 0.270 ;
  SYMMETRY X Y ;
  SITE asap7sc7p5t ;
  PIN A
    DIRECTION INPUT ;
    USE SIGNAL ;
    PORT
      LAYER M1 ;
        RECT 0.018 0.126 0.084 0.144 ;
        RECT 0.018 0.189 0.055 0.207 ;
        RECT 0.018 0.027 0.055 0.045 ;
        RECT 0.018 0.027 0.036 0.207 ;
    END
  END A
  PIN B
    DIRECTION INPUT ;
    USE SIGNAL ;
    PORT
      LAYER M1 ;
        RECT 0.126 0.126 0.23 0.144 ;
        RECT 0.107 0.189 0.144 0.207 ;
        RECT 0.126 0.063 0.144 0.207 ;
        RECT 0.107 0.063 0.144 0.081 ;
    END
  END B
  PIN VDD
    DIRECTION INOUT ;
    USE POWER ;
    SHAPE ABUTMENT ;
    PORT
      LAYER M1 ;
        RECT 0 0.261 0.324 0.279 ;
    END
  END VDD
  PIN VSS
    DIRECTION INOUT ;
    USE GROUND ;
    SHAPE ABUTMENT ;
    PORT
      LAYER M1 ;
        RECT 0 -0.009 0.324 0.009 ;
    END
  END VSS
  PIN Y
    DIRECTION OUTPUT ;
    USE SIGNAL ;
    PORT
      LAYER M1 ;
        RECT 0.202 0.189 0.306 0.207 ;
        RECT 0.288 0.027 0.306 0.207 ;
        RECT 0.094 0.027 0.306 0.045 ;
    END
  END Y
  OBS
    LAYER M1 ;
      RECT 0 0 0 0 ;
  END
END NOR2x1_bottom

MACRO NOR2x1p5_bottom
  CLASS CORE ;
  ORIGIN 0 0 ;
  FOREIGN NOR2x1p5_bottom 0 0 ;
  SIZE 0.054 BY 0.270 ;
  SYMMETRY X Y ;
  SITE asap7sc7p5t ;
  PIN A
    DIRECTION INPUT ;
    USE SIGNAL ;
    PORT
      LAYER M1 ;
        RECT 0.018 0.126 0.084 0.144 ;
        RECT 0.018 0.225 0.055 0.243 ;
        RECT 0.018 0.027 0.055 0.045 ;
        RECT 0.018 0.027 0.036 0.243 ;
    END
  END A
  PIN B
    DIRECTION INPUT ;
    USE SIGNAL ;
    PORT
      LAYER M1 ;
        RECT 0.126 0.126 0.257 0.144 ;
        RECT 0.126 0.063 0.163 0.081 ;
        RECT 0.107 0.189 0.144 0.207 ;
        RECT 0.126 0.063 0.144 0.207 ;
    END
  END B
  PIN VDD
    DIRECTION INOUT ;
    USE POWER ;
    SHAPE ABUTMENT ;
    PORT
      LAYER M1 ;
        RECT 0 0.261 0.432 0.279 ;
    END
  END VDD
  PIN VSS
    DIRECTION INOUT ;
    USE GROUND ;
    SHAPE ABUTMENT ;
    PORT
      LAYER M1 ;
        RECT 0 -0.009 0.432 0.009 ;
    END
  END VSS
  PIN Y
    DIRECTION OUTPUT ;
    USE SIGNAL ;
    PORT
      LAYER M1 ;
        RECT 0.261 0.225 0.414 0.243 ;
        RECT 0.396 0.027 0.414 0.243 ;
        RECT 0.094 0.027 0.414 0.045 ;
    END
  END Y
  OBS
    LAYER M1 ;
      RECT 0 0 0 0 ;
  END
END NOR2x1p5_bottom

MACRO NOR2x2_bottom
  CLASS CORE ;
  ORIGIN 0 0 ;
  FOREIGN NOR2x2_bottom 0 0 ;
  SIZE 0.054 BY 0.270 ;
  SYMMETRY X Y ;
  SITE asap7sc7p5t ;
  PIN A
    DIRECTION INPUT ;
    USE SIGNAL ;
    PORT
      LAYER M1 ;
        RECT 0.261 0.063 0.279 0.164 ;
        RECT 0.242 0.063 0.279 0.081 ;
    END
  END A
  PIN B
    DIRECTION INPUT ;
    USE SIGNAL ;
    PORT
      LAYER M1 ;
        RECT 0.322 0.153 0.468 0.171 ;
        RECT 0.45 0.093 0.468 0.171 ;
        RECT 0.2 0.189 0.34 0.207 ;
        RECT 0.322 0.153 0.34 0.207 ;
        RECT 0.2 0.153 0.218 0.207 ;
        RECT 0.072 0.153 0.218 0.171 ;
        RECT 0.072 0.063 0.109 0.081 ;
        RECT 0.072 0.063 0.09 0.171 ;
    END
  END B
  PIN VDD
    DIRECTION INOUT ;
    USE POWER ;
    SHAPE ABUTMENT ;
    PORT
      LAYER M1 ;
        RECT 0 0.261 0.54 0.279 ;
    END
  END VDD
  PIN VSS
    DIRECTION INOUT ;
    USE GROUND ;
    SHAPE ABUTMENT ;
    PORT
      LAYER M1 ;
        RECT 0 -0.009 0.54 0.009 ;
    END
  END VSS
  PIN Y
    DIRECTION OUTPUT ;
    USE SIGNAL ;
    PORT
      LAYER M1 ;
        RECT 0.418 0.189 0.522 0.207 ;
        RECT 0.504 0.027 0.522 0.207 ;
        RECT 0.018 0.027 0.522 0.045 ;
        RECT 0.018 0.189 0.122 0.207 ;
        RECT 0.018 0.027 0.036 0.207 ;
    END
  END Y
  OBS
    LAYER M1 ;
      RECT 0 0 0 0 ;
  END
END NOR2x2_bottom

MACRO NOR2xp33_bottom
  CLASS CORE ;
  ORIGIN 0 0 ;
  FOREIGN NOR2xp33_bottom 0 0 ;
  SIZE 0.054 BY 0.270 ;
  SYMMETRY X Y ;
  SITE asap7sc7p5t ;
  PIN A
    DIRECTION INPUT ;
    USE SIGNAL ;
    PORT
      LAYER M1 ;
        RECT 0.018 0.126 0.078 0.144 ;
        RECT 0.018 0.225 0.055 0.243 ;
        RECT 0.018 0.027 0.055 0.045 ;
        RECT 0.018 0.027 0.036 0.243 ;
    END
  END A
  PIN B
    DIRECTION INPUT ;
    USE SIGNAL ;
    PORT
      LAYER M1 ;
        RECT 0.107 0.189 0.144 0.207 ;
        RECT 0.126 0.063 0.144 0.207 ;
        RECT 0.107 0.063 0.144 0.081 ;
    END
  END B
  PIN VDD
    DIRECTION INOUT ;
    USE POWER ;
    SHAPE ABUTMENT ;
    PORT
      LAYER M1 ;
        RECT 0 0.261 0.216 0.279 ;
    END
  END VDD
  PIN VSS
    DIRECTION INOUT ;
    USE GROUND ;
    SHAPE ABUTMENT ;
    PORT
      LAYER M1 ;
        RECT 0 -0.009 0.216 0.009 ;
    END
  END VSS
  PIN Y
    DIRECTION OUTPUT ;
    USE SIGNAL ;
    PORT
      LAYER M1 ;
        RECT 0.143 0.225 0.198 0.243 ;
        RECT 0.18 0.027 0.198 0.243 ;
        RECT 0.094 0.027 0.198 0.045 ;
    END
  END Y
END NOR2xp33_bottom

MACRO NOR2xp67_bottom
  CLASS CORE ;
  ORIGIN 0 0 ;
  FOREIGN NOR2xp67_bottom 0 0 ;
  SIZE 0.054 BY 0.270 ;
  SYMMETRY X Y ;
  SITE asap7sc7p5t ;
  PIN A
    DIRECTION INPUT ;
    USE SIGNAL ;
    PORT
      LAYER M1 ;
        RECT 0.018 0.127 0.095 0.145 ;
        RECT 0.018 0.189 0.055 0.207 ;
        RECT 0.018 0.027 0.055 0.045 ;
        RECT 0.018 0.027 0.036 0.207 ;
    END
  END A
  PIN B
    DIRECTION INPUT ;
    USE SIGNAL ;
    PORT
      LAYER M1 ;
        RECT 0.126 0.126 0.257 0.144 ;
        RECT 0.126 0.063 0.163 0.081 ;
        RECT 0.107 0.189 0.144 0.207 ;
        RECT 0.126 0.063 0.144 0.207 ;
    END
  END B
  PIN VDD
    DIRECTION INOUT ;
    USE POWER ;
    SHAPE ABUTMENT ;
    PORT
      LAYER M1 ;
        RECT 0 0.261 0.324 0.279 ;
    END
  END VDD
  PIN VSS
    DIRECTION INOUT ;
    USE GROUND ;
    SHAPE ABUTMENT ;
    PORT
      LAYER M1 ;
        RECT 0 -0.009 0.324 0.009 ;
    END
  END VSS
  PIN Y
    DIRECTION OUTPUT ;
    USE SIGNAL ;
    PORT
      LAYER M1 ;
        RECT 0.202 0.189 0.306 0.207 ;
        RECT 0.288 0.027 0.306 0.207 ;
        RECT 0.148 0.027 0.306 0.045 ;
    END
  END Y
  OBS
    LAYER M1 ;
      RECT 0 0 0 0 ;
  END
END NOR2xp67_bottom

MACRO NOR3x1_bottom
  CLASS CORE ;
  ORIGIN 0 0 ;
  FOREIGN NOR3x1_bottom 0 0 ;
  SIZE 0.054 BY 0.270 ;
  SYMMETRY X Y ;
  SITE asap7sc7p5t ;
  PIN A
    DIRECTION INPUT ;
    USE SIGNAL ;
    PORT
      LAYER M1 ;
        RECT 0.396 0.153 0.468 0.171 ;
        RECT 0.45 0.063 0.468 0.171 ;
        RECT 0.396 0.063 0.468 0.081 ;
    END
  END A
  PIN B
    DIRECTION INPUT ;
    USE SIGNAL ;
    PORT
      LAYER M1 ;
        RECT 0.234 0.153 0.306 0.171 ;
        RECT 0.288 0.063 0.306 0.171 ;
        RECT 0.234 0.063 0.306 0.081 ;
    END
  END B
  PIN C
    DIRECTION INPUT ;
    USE SIGNAL ;
    PORT
      LAYER M1 ;
        RECT 0.018 0.126 0.09 0.144 ;
        RECT 0.018 0.189 0.055 0.207 ;
        RECT 0.018 0.027 0.055 0.045 ;
        RECT 0.018 0.027 0.036 0.207 ;
    END
  END C
  PIN VDD
    DIRECTION INOUT ;
    USE POWER ;
    SHAPE ABUTMENT ;
    PORT
      LAYER M1 ;
        RECT 0 0.261 0.594 0.279 ;
    END
  END VDD
  PIN VSS
    DIRECTION INOUT ;
    USE GROUND ;
    SHAPE ABUTMENT ;
    PORT
      LAYER M1 ;
        RECT 0 -0.009 0.594 0.009 ;
    END
  END VSS
  PIN Y
    DIRECTION OUTPUT ;
    USE SIGNAL ;
    PORT
      LAYER M1 ;
        RECT 0.418 0.189 0.576 0.207 ;
        RECT 0.558 0.027 0.576 0.207 ;
        RECT 0.202 0.027 0.576 0.045 ;
    END
  END Y
  OBS
    LAYER M1 ;
      RECT 0 0 0 0 ;
  END
END NOR3x1_bottom

MACRO NOR3x2_bottom
  CLASS CORE ;
  ORIGIN 0 0 ;
  FOREIGN NOR3x2_bottom 0 0 ;
  SIZE 0.054 BY 0.270 ;
  SYMMETRY X Y ;
  SITE asap7sc7p5t ;
  PIN B
    DIRECTION INPUT ;
    USE SIGNAL ;
    PORT
      LAYER M1 ;
        RECT 0.725 0.063 0.743 0.164 ;
        RECT 0.338 0.063 0.743 0.081 ;
        RECT 0.338 0.063 0.356 0.164 ;
    END
  END B
  PIN C
    DIRECTION INPUT ;
    USE SIGNAL ;
    PORT
      LAYER M1 ;
        RECT 0.547 0.106 0.565 0.164 ;
    END
  END C
  PIN VDD
    DIRECTION INOUT ;
    USE POWER ;
    SHAPE ABUTMENT ;
    PORT
      LAYER M1 ;
        RECT 0 0.261 1.08 0.279 ;
    END
  END VDD
  PIN VSS
    DIRECTION INOUT ;
    USE GROUND ;
    SHAPE ABUTMENT ;
    PORT
      LAYER M1 ;
        RECT 0 -0.009 1.08 0.009 ;
    END
  END VSS
  PIN Y
    DIRECTION OUTPUT ;
    USE SIGNAL ;
    PORT
      LAYER M1 ;
        RECT 0.904 0.189 1.062 0.207 ;
        RECT 1.044 0.027 1.062 0.207 ;
        RECT 0.018 0.027 1.062 0.045 ;
        RECT 0.018 0.189 0.176 0.207 ;
        RECT 0.018 0.027 0.036 0.207 ;
    END
  END Y
  PIN A
    DIRECTION INPUT ;
    USE SIGNAL ;
    PORT
      LAYER M2 ;
        RECT 0.169 0.072 0.908 0.09 ;
      LAYER M1 ;
        RECT 0.885 0.063 0.903 0.162 ;
        RECT 0.866 0.063 0.903 0.081 ;
        RECT 0.174 0.063 0.211 0.081 ;
        RECT 0.174 0.063 0.192 0.164 ;
      LAYER V1 ;
        RECT 0.174 0.072 0.192 0.09 ;
        RECT 0.885 0.072 0.903 0.09 ;
    END
  END A
  OBS
    LAYER M1 ;
      RECT 0 0 0 0 ;
  END
END NOR3x2_bottom

MACRO NOR3xp33_bottom
  CLASS CORE ;
  ORIGIN 0 0 ;
  FOREIGN NOR3xp33_bottom 0 0 ;
  SIZE 0.054 BY 0.270 ;
  SYMMETRY X Y ;
  SITE asap7sc7p5t ;
  PIN A
    DIRECTION INPUT ;
    USE SIGNAL ;
    PORT
      LAYER M1 ;
        RECT 0.072 0.07 0.09 0.2 ;
    END
  END A
  PIN B
    DIRECTION INPUT ;
    USE SIGNAL ;
    PORT
      LAYER M1 ;
        RECT 0.126 0.07 0.144 0.236 ;
    END
  END B
  PIN C
    DIRECTION INPUT ;
    USE SIGNAL ;
    PORT
      LAYER M1 ;
        RECT 0.18 0.07 0.198 0.236 ;
    END
  END C
  PIN VDD
    DIRECTION INOUT ;
    USE POWER ;
    SHAPE ABUTMENT ;
    PORT
      LAYER M1 ;
        RECT 0 0.261 0.27 0.279 ;
    END
  END VDD
  PIN VSS
    DIRECTION INOUT ;
    USE GROUND ;
    SHAPE ABUTMENT ;
    PORT
      LAYER M1 ;
        RECT 0 -0.009 0.27 0.009 ;
    END
  END VSS
  PIN Y
    DIRECTION OUTPUT ;
    USE SIGNAL ;
    PORT
      LAYER M1 ;
        RECT 0.018 0.027 0.176 0.045 ;
        RECT 0.018 0.225 0.068 0.243 ;
        RECT 0.018 0.027 0.036 0.243 ;
    END
  END Y
END NOR3xp33_bottom

MACRO NOR4xp25_bottom
  CLASS CORE ;
  ORIGIN 0 0 ;
  FOREIGN NOR4xp25_bottom 0 0 ;
  SIZE 0.054 BY 0.270 ;
  SYMMETRY X Y ;
  SITE asap7sc7p5t ;
  PIN A
    DIRECTION INPUT ;
    USE SIGNAL ;
    PORT
      LAYER M1 ;
        RECT 0.234 0.07 0.252 0.2 ;
    END
  END A
  PIN B
    DIRECTION INPUT ;
    USE SIGNAL ;
    PORT
      LAYER M1 ;
        RECT 0.18 0.07 0.198 0.236 ;
    END
  END B
  PIN C
    DIRECTION INPUT ;
    USE SIGNAL ;
    PORT
      LAYER M1 ;
        RECT 0.126 0.07 0.144 0.236 ;
    END
  END C
  PIN D
    DIRECTION INPUT ;
    USE SIGNAL ;
    PORT
      LAYER M1 ;
        RECT 0.072 0.07 0.09 0.236 ;
    END
  END D
  PIN VDD
    DIRECTION INOUT ;
    USE POWER ;
    SHAPE ABUTMENT ;
    PORT
      LAYER M1 ;
        RECT 0 0.261 0.324 0.279 ;
    END
  END VDD
  PIN VSS
    DIRECTION INOUT ;
    USE GROUND ;
    SHAPE ABUTMENT ;
    PORT
      LAYER M1 ;
        RECT 0 -0.009 0.324 0.009 ;
    END
  END VSS
  PIN Y
    DIRECTION OUTPUT ;
    USE SIGNAL ;
    PORT
      LAYER M1 ;
        RECT 0.256 0.225 0.306 0.243 ;
        RECT 0.288 0.027 0.306 0.243 ;
        RECT 0.04 0.027 0.306 0.045 ;
    END
  END Y
END NOR4xp25_bottom

MACRO NOR4xp75_bottom
  CLASS CORE ;
  ORIGIN 0 0 ;
  FOREIGN NOR4xp75_bottom 0 0 ;
  SIZE 0.054 BY 0.270 ;
  SYMMETRY X Y ;
  SITE asap7sc7p5t ;
  PIN A
    DIRECTION INPUT ;
    USE SIGNAL ;
    PORT
      LAYER M1 ;
        RECT 0.612 0.07 0.63 0.164 ;
    END
  END A
  PIN B
    DIRECTION INPUT ;
    USE SIGNAL ;
    PORT
      LAYER M1 ;
        RECT 0.531 0.151 0.549 0.2 ;
        RECT 0.504 0.151 0.549 0.169 ;
        RECT 0.504 0.07 0.522 0.169 ;
    END
  END B
  PIN C
    DIRECTION INPUT ;
    USE SIGNAL ;
    PORT
      LAYER M1 ;
        RECT 0.207 0.151 0.306 0.169 ;
        RECT 0.288 0.07 0.306 0.169 ;
        RECT 0.207 0.151 0.225 0.2 ;
    END
  END C
  PIN D
    DIRECTION INPUT ;
    USE SIGNAL ;
    PORT
      LAYER M1 ;
        RECT 0.018 0.126 0.095 0.144 ;
        RECT 0.018 0.225 0.057 0.243 ;
        RECT 0.018 0.027 0.057 0.045 ;
        RECT 0.018 0.027 0.036 0.243 ;
    END
  END D
  PIN VDD
    DIRECTION INOUT ;
    USE POWER ;
    SHAPE ABUTMENT ;
    PORT
      LAYER M1 ;
        RECT 0 0.261 0.756 0.279 ;
    END
  END VDD
  PIN VSS
    DIRECTION INOUT ;
    USE GROUND ;
    SHAPE ABUTMENT ;
    PORT
      LAYER M1 ;
        RECT 0 -0.009 0.756 0.009 ;
    END
  END VSS
  PIN Y
    DIRECTION OUTPUT ;
    USE SIGNAL ;
    PORT
      LAYER M1 ;
        RECT 0.58 0.189 0.738 0.207 ;
        RECT 0.72 0.027 0.738 0.207 ;
        RECT 0.094 0.027 0.738 0.045 ;
    END
  END Y
  OBS
    LAYER M1 ;
      RECT 0 0 0 0 ;
  END
END NOR4xp75_bottom

MACRO NOR5xp2_bottom
  CLASS CORE ;
  ORIGIN 0 0 ;
  FOREIGN NOR5xp2_bottom 0 0 ;
  SIZE 0.054 BY 0.270 ;
  SYMMETRY X Y ;
  SITE asap7sc7p5t ;
  PIN A
    DIRECTION INPUT ;
    USE SIGNAL ;
    PORT
      LAYER M1 ;
        RECT 0.072 0.07 0.09 0.198 ;
    END
  END A
  PIN B
    DIRECTION INPUT ;
    USE SIGNAL ;
    PORT
      LAYER M1 ;
        RECT 0.126 0.07 0.144 0.236 ;
    END
  END B
  PIN C
    DIRECTION INPUT ;
    USE SIGNAL ;
    PORT
      LAYER M1 ;
        RECT 0.18 0.07 0.198 0.236 ;
    END
  END C
  PIN D
    DIRECTION INPUT ;
    USE SIGNAL ;
    PORT
      LAYER M1 ;
        RECT 0.234 0.07 0.252 0.236 ;
    END
  END D
  PIN E
    DIRECTION INPUT ;
    USE SIGNAL ;
    PORT
      LAYER M1 ;
        RECT 0.288 0.07 0.306 0.236 ;
    END
  END E
  PIN VDD
    DIRECTION INOUT ;
    USE POWER ;
    SHAPE ABUTMENT ;
    PORT
      LAYER M1 ;
        RECT 0 0.261 0.378 0.279 ;
    END
  END VDD
  PIN VSS
    DIRECTION INOUT ;
    USE GROUND ;
    SHAPE ABUTMENT ;
    PORT
      LAYER M1 ;
        RECT 0 -0.009 0.378 0.009 ;
    END
  END VSS
  PIN Y
    DIRECTION OUTPUT ;
    USE SIGNAL ;
    PORT
      LAYER M1 ;
        RECT 0.017 0.027 0.338 0.045 ;
        RECT 0.017 0.225 0.07 0.243 ;
        RECT 0.017 0.027 0.037 0.243 ;
    END
  END Y
END NOR5xp2_bottom

MACRO O2A1O1Ixp33_bottom
  CLASS CORE ;
  ORIGIN 0 0 ;
  FOREIGN O2A1O1Ixp33_bottom 0 0 ;
  SIZE 0.054 BY 0.270 ;
  SYMMETRY X Y ;
  SITE asap7sc7p5t ;
  PIN A1
    DIRECTION INPUT ;
    USE SIGNAL ;
    PORT
      LAYER M1 ;
        RECT 0.126 0.106 0.144 0.2 ;
    END
  END A1
  PIN A2
    DIRECTION INPUT ;
    USE SIGNAL ;
    PORT
      LAYER M1 ;
        RECT 0.072 0.106 0.09 0.2 ;
    END
  END A2
  PIN B
    DIRECTION INPUT ;
    USE SIGNAL ;
    PORT
      LAYER M1 ;
        RECT 0.18 0.106 0.198 0.2 ;
    END
  END B
  PIN C
    DIRECTION INPUT ;
    USE SIGNAL ;
    PORT
      LAYER M1 ;
        RECT 0.234 0.07 0.252 0.206 ;
    END
  END C
  PIN VDD
    DIRECTION INOUT ;
    USE POWER ;
    SHAPE ABUTMENT ;
    PORT
      LAYER M1 ;
        RECT 0 0.261 0.324 0.279 ;
    END
  END VDD
  PIN VSS
    DIRECTION INOUT ;
    USE GROUND ;
    SHAPE ABUTMENT ;
    PORT
      LAYER M1 ;
        RECT 0 -0.009 0.324 0.009 ;
    END
  END VSS
  PIN Y
    DIRECTION OUTPUT ;
    USE SIGNAL ;
    PORT
      LAYER M1 ;
        RECT 0.261 0.225 0.306 0.243 ;
        RECT 0.288 0.027 0.306 0.243 ;
        RECT 0.094 0.027 0.306 0.045 ;
    END
  END Y
  OBS
    LAYER M1 ;
      RECT 0 0 0 0 ;
  END
END O2A1O1Ixp33_bottom

MACRO O2A1O1Ixp5_bottom
  CLASS CORE ;
  ORIGIN 0 0 ;
  FOREIGN O2A1O1Ixp5_bottom 0 0 ;
  SIZE 0.054 BY 0.270 ;
  SYMMETRY X Y ;
  SITE asap7sc7p5t ;
  PIN A1
    DIRECTION INPUT ;
    USE SIGNAL ;
    PORT
      LAYER M1 ;
        RECT 0.234 0.063 0.252 0.164 ;
        RECT 0.072 0.063 0.252 0.081 ;
        RECT 0.072 0.063 0.09 0.2 ;
    END
  END A1
  PIN A2
    DIRECTION INPUT ;
    USE SIGNAL ;
    PORT
      LAYER M1 ;
        RECT 0.126 0.106 0.144 0.164 ;
    END
  END A2
  PIN B
    DIRECTION INPUT ;
    USE SIGNAL ;
    PORT
      LAYER M1 ;
        RECT 0.288 0.07 0.306 0.164 ;
    END
  END B
  PIN C
    DIRECTION INPUT ;
    USE SIGNAL ;
    PORT
      LAYER M1 ;
        RECT 0.342 0.07 0.36 0.164 ;
    END
  END C
  PIN VDD
    DIRECTION INOUT ;
    USE POWER ;
    SHAPE ABUTMENT ;
    PORT
      LAYER M1 ;
        RECT 0 0.261 0.432 0.279 ;
    END
  END VDD
  PIN VSS
    DIRECTION INOUT ;
    USE GROUND ;
    SHAPE ABUTMENT ;
    PORT
      LAYER M1 ;
        RECT 0 -0.009 0.432 0.009 ;
    END
  END VSS
  PIN Y
    DIRECTION OUTPUT ;
    USE SIGNAL ;
    PORT
      LAYER M1 ;
        RECT 0.364 0.225 0.414 0.243 ;
        RECT 0.396 0.027 0.414 0.243 ;
        RECT 0.315 0.027 0.414 0.045 ;
    END
  END Y
  OBS
    LAYER M1 ;
      RECT 0 0 0 0 ;
  END
END O2A1O1Ixp5_bottom

MACRO OA211x2_bottom
  CLASS CORE ;
  ORIGIN 0 0 ;
  FOREIGN OA211x2_bottom 0 0 ;
  SIZE 0.054 BY 0.270 ;
  SYMMETRY X Y ;
  SITE asap7sc7p5t ;
  PIN A1
    DIRECTION INPUT ;
    USE SIGNAL ;
    PORT
      LAYER M1 ;
        RECT 0.126 0.106 0.144 0.2 ;
    END
  END A1
  PIN A2
    DIRECTION INPUT ;
    USE SIGNAL ;
    PORT
      LAYER M1 ;
        RECT 0.018 0.126 0.09 0.144 ;
        RECT 0.018 0.07 0.036 0.2 ;
    END
  END A2
  PIN B
    DIRECTION INPUT ;
    USE SIGNAL ;
    PORT
      LAYER M1 ;
        RECT 0.18 0.106 0.198 0.2 ;
    END
  END B
  PIN C
    DIRECTION INPUT ;
    USE SIGNAL ;
    PORT
      LAYER M1 ;
        RECT 0.234 0.106 0.252 0.164 ;
    END
  END C
  PIN VDD
    DIRECTION INOUT ;
    USE POWER ;
    SHAPE ABUTMENT ;
    PORT
      LAYER M1 ;
        RECT 0 0.261 0.432 0.279 ;
    END
  END VDD
  PIN VSS
    DIRECTION INOUT ;
    USE GROUND ;
    SHAPE ABUTMENT ;
    PORT
      LAYER M1 ;
        RECT 0 -0.009 0.432 0.009 ;
    END
  END VSS
  PIN Y
    DIRECTION OUTPUT ;
    USE SIGNAL ;
    PORT
      LAYER M1 ;
        RECT 0.296 0.225 0.414 0.243 ;
        RECT 0.396 0.027 0.414 0.243 ;
        RECT 0.286 0.027 0.414 0.045 ;
    END
  END Y
  OBS
    LAYER M1 ;
      RECT 0 0 0 0 ;
  END
END OA211x2_bottom

MACRO OA21x2_bottom
  CLASS CORE ;
  ORIGIN 0 0 ;
  FOREIGN OA21x2_bottom 0 0 ;
  SIZE 0.054 BY 0.270 ;
  SYMMETRY X Y ;
  SITE asap7sc7p5t ;
  PIN A1
    DIRECTION INPUT ;
    USE SIGNAL ;
    PORT
      LAYER M1 ;
        RECT 0.018 0.07 0.036 0.236 ;
    END
  END A1
  PIN A2
    DIRECTION INPUT ;
    USE SIGNAL ;
    PORT
      LAYER M1 ;
        RECT 0.126 0.106 0.144 0.2 ;
    END
  END A2
  PIN B
    DIRECTION INPUT ;
    USE SIGNAL ;
    PORT
      LAYER M1 ;
        RECT 0.18 0.153 0.239 0.171 ;
        RECT 0.18 0.106 0.198 0.171 ;
    END
  END B
  PIN VDD
    DIRECTION INOUT ;
    USE POWER ;
    SHAPE ABUTMENT ;
    PORT
      LAYER M1 ;
        RECT 0 0.261 0.378 0.279 ;
    END
  END VDD
  PIN VSS
    DIRECTION INOUT ;
    USE GROUND ;
    SHAPE ABUTMENT ;
    PORT
      LAYER M1 ;
        RECT 0 -0.009 0.378 0.009 ;
    END
  END VSS
  PIN Y
    DIRECTION OUTPUT ;
    USE SIGNAL ;
    PORT
      LAYER M1 ;
        RECT 0.256 0.225 0.36 0.243 ;
        RECT 0.342 0.027 0.36 0.243 ;
        RECT 0.256 0.027 0.36 0.045 ;
    END
  END Y
  OBS
    LAYER M1 ;
      RECT 0 0 0 0 ;
  END
END OA21x2_bottom

MACRO OA221x2_bottom
  CLASS CORE ;
  ORIGIN 0 0 ;
  FOREIGN OA221x2_bottom 0 0 ;
  SIZE 0.054 BY 0.270 ;
  SYMMETRY X Y ;
  SITE asap7sc7p5t ;
  PIN A1
    DIRECTION INPUT ;
    USE SIGNAL ;
    PORT
      LAYER M1 ;
        RECT 0.215 0.189 0.252 0.207 ;
        RECT 0.234 0.099 0.252 0.207 ;
        RECT 0.215 0.099 0.252 0.117 ;
    END
  END A1
  PIN A2
    DIRECTION INPUT ;
    USE SIGNAL ;
    PORT
      LAYER M1 ;
        RECT 0.342 0.189 0.379 0.207 ;
        RECT 0.342 0.099 0.379 0.117 ;
        RECT 0.342 0.099 0.36 0.207 ;
    END
  END A2
  PIN B1
    DIRECTION INPUT ;
    USE SIGNAL ;
    PORT
      LAYER M1 ;
        RECT 0.593 0.189 0.63 0.207 ;
        RECT 0.612 0.099 0.63 0.207 ;
        RECT 0.593 0.099 0.63 0.117 ;
    END
  END B1
  PIN B2
    DIRECTION INPUT ;
    USE SIGNAL ;
    PORT
      LAYER M1 ;
        RECT 0.485 0.189 0.522 0.207 ;
        RECT 0.504 0.099 0.522 0.207 ;
        RECT 0.485 0.099 0.522 0.117 ;
    END
  END B2
  PIN C
    DIRECTION INPUT ;
    USE SIGNAL ;
    PORT
      LAYER M1 ;
        RECT 0.72 0.189 0.757 0.207 ;
        RECT 0.72 0.099 0.757 0.117 ;
        RECT 0.72 0.099 0.738 0.207 ;
    END
  END C
  PIN VDD
    DIRECTION INOUT ;
    USE POWER ;
    SHAPE ABUTMENT ;
    PORT
      LAYER M1 ;
        RECT 0 0.261 0.864 0.279 ;
    END
  END VDD
  PIN VSS
    DIRECTION INOUT ;
    USE GROUND ;
    SHAPE ABUTMENT ;
    PORT
      LAYER M1 ;
        RECT 0 -0.009 0.864 0.009 ;
    END
  END VSS
  PIN Y
    DIRECTION OUTPUT ;
    USE SIGNAL ;
    PORT
      LAYER M1 ;
        RECT 0.018 0.027 0.122 0.045 ;
        RECT 0.018 0.225 0.117 0.243 ;
        RECT 0.099 0.189 0.117 0.243 ;
        RECT 0.018 0.027 0.036 0.243 ;
    END
  END Y
  OBS
    LAYER M1 ;
      RECT 0 0 0 0 ;
  END
END OA221x2_bottom

MACRO OA222x2_bottom
  CLASS CORE ;
  ORIGIN 0 0 ;
  FOREIGN OA222x2_bottom 0 0 ;
  SIZE 0.054 BY 0.270 ;
  SYMMETRY X Y ;
  SITE asap7sc7p5t ;
  PIN A1
    DIRECTION INPUT ;
    USE SIGNAL ;
    PORT
      LAYER M1 ;
        RECT 0.072 0.106 0.09 0.2 ;
    END
  END A1
  PIN A2
    DIRECTION INPUT ;
    USE SIGNAL ;
    PORT
      LAYER M1 ;
        RECT 0.126 0.106 0.144 0.2 ;
    END
  END A2
  PIN B1
    DIRECTION INPUT ;
    USE SIGNAL ;
    PORT
      LAYER M1 ;
        RECT 0.234 0.106 0.252 0.2 ;
    END
  END B1
  PIN B2
    DIRECTION INPUT ;
    USE SIGNAL ;
    PORT
      LAYER M1 ;
        RECT 0.18 0.106 0.198 0.2 ;
    END
  END B2
  PIN C1
    DIRECTION INPUT ;
    USE SIGNAL ;
    PORT
      LAYER M1 ;
        RECT 0.396 0.07 0.414 0.2 ;
    END
  END C1
  PIN C2
    DIRECTION INPUT ;
    USE SIGNAL ;
    PORT
      LAYER M1 ;
        RECT 0.45 0.07 0.468 0.2 ;
    END
  END C2
  PIN VDD
    DIRECTION INOUT ;
    USE POWER ;
    SHAPE ABUTMENT ;
    PORT
      LAYER M1 ;
        RECT 0 0.261 0.648 0.279 ;
    END
  END VDD
  PIN VSS
    DIRECTION INOUT ;
    USE GROUND ;
    SHAPE ABUTMENT ;
    PORT
      LAYER M1 ;
        RECT 0 -0.009 0.648 0.009 ;
    END
  END VSS
  PIN Y
    DIRECTION OUTPUT ;
    USE SIGNAL ;
    PORT
      LAYER M1 ;
        RECT 0.531 0.225 0.63 0.243 ;
        RECT 0.612 0.027 0.63 0.243 ;
        RECT 0.526 0.027 0.63 0.045 ;
        RECT 0.531 0.189 0.549 0.243 ;
    END
  END Y
  OBS
    LAYER M1 ;
      RECT 0 0 0 0 ;
  END
END OA222x2_bottom

MACRO OA22x2_bottom
  CLASS CORE ;
  ORIGIN 0 0 ;
  FOREIGN OA22x2_bottom 0 0 ;
  SIZE 0.054 BY 0.270 ;
  SYMMETRY X Y ;
  SITE asap7sc7p5t ;
  PIN A1
    DIRECTION INPUT ;
    USE SIGNAL ;
    PORT
      LAYER M1 ;
        RECT 0.288 0.106 0.306 0.2 ;
    END
  END A1
  PIN A2
    DIRECTION INPUT ;
    USE SIGNAL ;
    PORT
      LAYER M1 ;
        RECT 0.342 0.106 0.36 0.2 ;
    END
  END A2
  PIN B1
    DIRECTION INPUT ;
    USE SIGNAL ;
    PORT
      LAYER M1 ;
        RECT 0.45 0.07 0.468 0.236 ;
    END
  END B1
  PIN B2
    DIRECTION INPUT ;
    USE SIGNAL ;
    PORT
      LAYER M1 ;
        RECT 0.396 0.063 0.414 0.2 ;
        RECT 0.367 0.063 0.414 0.081 ;
    END
  END B2
  PIN VDD
    DIRECTION INOUT ;
    USE POWER ;
    SHAPE ABUTMENT ;
    PORT
      LAYER M1 ;
        RECT 0 0.261 0.54 0.279 ;
    END
  END VDD
  PIN VSS
    DIRECTION INOUT ;
    USE GROUND ;
    SHAPE ABUTMENT ;
    PORT
      LAYER M1 ;
        RECT 0 -0.009 0.54 0.009 ;
    END
  END VSS
  PIN Y
    DIRECTION OUTPUT ;
    USE SIGNAL ;
    PORT
      LAYER M1 ;
        RECT 0.071 0.225 0.122 0.243 ;
        RECT 0.071 0.027 0.122 0.045 ;
        RECT 0.071 0.027 0.091 0.243 ;
    END
  END Y
  OBS
    LAYER M1 ;
      RECT 0 0 0 0 ;
  END
END OA22x2_bottom

MACRO OA31x2_bottom
  CLASS CORE ;
  ORIGIN 0 0 ;
  FOREIGN OA31x2_bottom 0 0 ;
  SIZE 0.054 BY 0.270 ;
  SYMMETRY X Y ;
  SITE asap7sc7p5t ;
  PIN A1
    DIRECTION INPUT ;
    USE SIGNAL ;
    PORT
      LAYER M1 ;
        RECT 0.053 0.189 0.09 0.207 ;
        RECT 0.072 0.099 0.09 0.207 ;
        RECT 0.053 0.099 0.09 0.117 ;
    END
  END A1
  PIN A2
    DIRECTION INPUT ;
    USE SIGNAL ;
    PORT
      LAYER M1 ;
        RECT 0.126 0.126 0.203 0.144 ;
        RECT 0.126 0.189 0.163 0.207 ;
        RECT 0.126 0.106 0.144 0.207 ;
    END
  END A2
  PIN A3
    DIRECTION INPUT ;
    USE SIGNAL ;
    PORT
      LAYER M1 ;
        RECT 0.342 0.126 0.414 0.144 ;
        RECT 0.342 0.063 0.36 0.164 ;
        RECT 0.323 0.063 0.36 0.081 ;
    END
  END A3
  PIN B1
    DIRECTION INPUT ;
    USE SIGNAL ;
    PORT
      LAYER M1 ;
        RECT 0.485 0.153 0.522 0.171 ;
        RECT 0.504 0.106 0.522 0.171 ;
    END
  END B1
  PIN VDD
    DIRECTION INOUT ;
    USE POWER ;
    SHAPE ABUTMENT ;
    PORT
      LAYER M1 ;
        RECT 0 0.261 0.81 0.279 ;
    END
  END VDD
  PIN VSS
    DIRECTION INOUT ;
    USE GROUND ;
    SHAPE ABUTMENT ;
    PORT
      LAYER M1 ;
        RECT 0 -0.009 0.81 0.009 ;
    END
  END VSS
  PIN Y
    DIRECTION OUTPUT ;
    USE SIGNAL ;
    PORT
      LAYER M1 ;
        RECT 0.693 0.225 0.792 0.243 ;
        RECT 0.774 0.027 0.792 0.243 ;
        RECT 0.693 0.027 0.792 0.045 ;
    END
  END Y
  OBS
    LAYER M1 ;
      RECT 0 0 0 0 ;
  END
END OA31x2_bottom

MACRO OA331x1_bottom
  CLASS CORE ;
  ORIGIN 0 0 ;
  FOREIGN OA331x1_bottom 0 0 ;
  SIZE 0.054 BY 0.270 ;
  SYMMETRY X Y ;
  SITE asap7sc7p5t ;
  PIN A1
    DIRECTION INPUT ;
    USE SIGNAL ;
    PORT
      LAYER M1 ;
        RECT 0.234 0.106 0.252 0.2 ;
    END
  END A1
  PIN A2
    DIRECTION INPUT ;
    USE SIGNAL ;
    PORT
      LAYER M1 ;
        RECT 0.18 0.106 0.198 0.2 ;
    END
  END A2
  PIN A3
    DIRECTION INPUT ;
    USE SIGNAL ;
    PORT
      LAYER M1 ;
        RECT 0.126 0.07 0.144 0.166 ;
    END
  END A3
  PIN B1
    DIRECTION INPUT ;
    USE SIGNAL ;
    PORT
      LAYER M1 ;
        RECT 0.288 0.106 0.306 0.2 ;
    END
  END B1
  PIN B2
    DIRECTION INPUT ;
    USE SIGNAL ;
    PORT
      LAYER M1 ;
        RECT 0.342 0.106 0.36 0.2 ;
    END
  END B2
  PIN B3
    DIRECTION INPUT ;
    USE SIGNAL ;
    PORT
      LAYER M1 ;
        RECT 0.396 0.106 0.414 0.2 ;
    END
  END B3
  PIN C1
    DIRECTION INPUT ;
    USE SIGNAL ;
    PORT
      LAYER M1 ;
        RECT 0.45 0.106 0.468 0.2 ;
    END
  END C1
  PIN VDD
    DIRECTION INOUT ;
    USE POWER ;
    SHAPE ABUTMENT ;
    PORT
      LAYER M1 ;
        RECT 0 0.261 0.54 0.279 ;
    END
  END VDD
  PIN VSS
    DIRECTION INOUT ;
    USE GROUND ;
    SHAPE ABUTMENT ;
    PORT
      LAYER M1 ;
        RECT 0 -0.009 0.54 0.009 ;
    END
  END VSS
  PIN Y
    DIRECTION OUTPUT ;
    USE SIGNAL ;
    PORT
      LAYER M1 ;
        RECT 0.018 0.225 0.068 0.243 ;
        RECT 0.018 0.027 0.068 0.045 ;
        RECT 0.018 0.027 0.036 0.243 ;
    END
  END Y
  OBS
    LAYER M1 ;
      RECT 0 0 0 0 ;
  END
END OA331x1_bottom

MACRO OA331x2_bottom
  CLASS CORE ;
  ORIGIN 0 0 ;
  FOREIGN OA331x2_bottom 0 0 ;
  SIZE 0.054 BY 0.270 ;
  SYMMETRY X Y ;
  SITE asap7sc7p5t ;
  PIN A1
    DIRECTION INPUT ;
    USE SIGNAL ;
    PORT
      LAYER M1 ;
        RECT 0.288 0.106 0.306 0.2 ;
    END
  END A1
  PIN A2
    DIRECTION INPUT ;
    USE SIGNAL ;
    PORT
      LAYER M1 ;
        RECT 0.234 0.106 0.252 0.2 ;
    END
  END A2
  PIN A3
    DIRECTION INPUT ;
    USE SIGNAL ;
    PORT
      LAYER M1 ;
        RECT 0.18 0.07 0.198 0.166 ;
    END
  END A3
  PIN B1
    DIRECTION INPUT ;
    USE SIGNAL ;
    PORT
      LAYER M1 ;
        RECT 0.342 0.106 0.36 0.2 ;
    END
  END B1
  PIN B2
    DIRECTION INPUT ;
    USE SIGNAL ;
    PORT
      LAYER M1 ;
        RECT 0.396 0.106 0.414 0.2 ;
    END
  END B2
  PIN B3
    DIRECTION INPUT ;
    USE SIGNAL ;
    PORT
      LAYER M1 ;
        RECT 0.45 0.106 0.468 0.2 ;
    END
  END B3
  PIN C1
    DIRECTION INPUT ;
    USE SIGNAL ;
    PORT
      LAYER M1 ;
        RECT 0.504 0.106 0.522 0.2 ;
    END
  END C1
  PIN VDD
    DIRECTION INOUT ;
    USE POWER ;
    SHAPE ABUTMENT ;
    PORT
      LAYER M1 ;
        RECT 0 0.261 0.594 0.279 ;
    END
  END VDD
  PIN VSS
    DIRECTION INOUT ;
    USE GROUND ;
    SHAPE ABUTMENT ;
    PORT
      LAYER M1 ;
        RECT 0 -0.009 0.594 0.009 ;
    END
  END VSS
  PIN Y
    DIRECTION OUTPUT ;
    USE SIGNAL ;
    PORT
      LAYER M1 ;
        RECT 0.045 0.225 0.122 0.243 ;
        RECT 0.045 0.027 0.122 0.045 ;
        RECT 0.045 0.027 0.063 0.243 ;
    END
  END Y
  OBS
    LAYER M1 ;
      RECT 0 0 0 0 ;
  END
END OA331x2_bottom

MACRO OA332x1_bottom
  CLASS CORE ;
  ORIGIN 0 0 ;
  FOREIGN OA332x1_bottom 0 0 ;
  SIZE 0.054 BY 0.270 ;
  SYMMETRY X Y ;
  SITE asap7sc7p5t ;
  PIN A1
    DIRECTION INPUT ;
    USE SIGNAL ;
    PORT
      LAYER M1 ;
        RECT 0.234 0.106 0.252 0.2 ;
    END
  END A1
  PIN A2
    DIRECTION INPUT ;
    USE SIGNAL ;
    PORT
      LAYER M1 ;
        RECT 0.18 0.07 0.198 0.2 ;
    END
  END A2
  PIN A3
    DIRECTION INPUT ;
    USE SIGNAL ;
    PORT
      LAYER M1 ;
        RECT 0.126 0.07 0.144 0.164 ;
    END
  END A3
  PIN B1
    DIRECTION INPUT ;
    USE SIGNAL ;
    PORT
      LAYER M1 ;
        RECT 0.288 0.106 0.306 0.2 ;
    END
  END B1
  PIN B2
    DIRECTION INPUT ;
    USE SIGNAL ;
    PORT
      LAYER M1 ;
        RECT 0.342 0.106 0.36 0.2 ;
    END
  END B2
  PIN B3
    DIRECTION INPUT ;
    USE SIGNAL ;
    PORT
      LAYER M1 ;
        RECT 0.396 0.106 0.414 0.2 ;
    END
  END B3
  PIN C1
    DIRECTION INPUT ;
    USE SIGNAL ;
    PORT
      LAYER M1 ;
        RECT 0.504 0.106 0.522 0.2 ;
    END
  END C1
  PIN C2
    DIRECTION INPUT ;
    USE SIGNAL ;
    PORT
      LAYER M1 ;
        RECT 0.45 0.106 0.468 0.2 ;
    END
  END C2
  PIN VDD
    DIRECTION INOUT ;
    USE POWER ;
    SHAPE ABUTMENT ;
    PORT
      LAYER M1 ;
        RECT 0 0.261 0.594 0.279 ;
    END
  END VDD
  PIN VSS
    DIRECTION INOUT ;
    USE GROUND ;
    SHAPE ABUTMENT ;
    PORT
      LAYER M1 ;
        RECT 0 -0.009 0.594 0.009 ;
    END
  END VSS
  PIN Y
    DIRECTION OUTPUT ;
    USE SIGNAL ;
    PORT
      LAYER M1 ;
        RECT 0.018 0.225 0.094 0.243 ;
        RECT 0.018 0.027 0.068 0.045 ;
        RECT 0.018 0.027 0.036 0.243 ;
    END
  END Y
  OBS
    LAYER M1 ;
      RECT 0 0 0 0 ;
  END
END OA332x1_bottom

MACRO OA332x2_bottom
  CLASS CORE ;
  ORIGIN 0 0 ;
  FOREIGN OA332x2_bottom 0 0 ;
  SIZE 0.054 BY 0.270 ;
  SYMMETRY X Y ;
  SITE asap7sc7p5t ;
  PIN A1
    DIRECTION INPUT ;
    USE SIGNAL ;
    PORT
      LAYER M1 ;
        RECT 0.288 0.106 0.306 0.2 ;
    END
  END A1
  PIN A2
    DIRECTION INPUT ;
    USE SIGNAL ;
    PORT
      LAYER M1 ;
        RECT 0.234 0.07 0.252 0.2 ;
    END
  END A2
  PIN A3
    DIRECTION INPUT ;
    USE SIGNAL ;
    PORT
      LAYER M1 ;
        RECT 0.18 0.07 0.198 0.164 ;
    END
  END A3
  PIN B1
    DIRECTION INPUT ;
    USE SIGNAL ;
    PORT
      LAYER M1 ;
        RECT 0.342 0.106 0.36 0.2 ;
    END
  END B1
  PIN B2
    DIRECTION INPUT ;
    USE SIGNAL ;
    PORT
      LAYER M1 ;
        RECT 0.396 0.106 0.414 0.2 ;
    END
  END B2
  PIN B3
    DIRECTION INPUT ;
    USE SIGNAL ;
    PORT
      LAYER M1 ;
        RECT 0.45 0.106 0.468 0.2 ;
    END
  END B3
  PIN C1
    DIRECTION INPUT ;
    USE SIGNAL ;
    PORT
      LAYER M1 ;
        RECT 0.558 0.106 0.576 0.2 ;
    END
  END C1
  PIN C2
    DIRECTION INPUT ;
    USE SIGNAL ;
    PORT
      LAYER M1 ;
        RECT 0.504 0.106 0.522 0.2 ;
    END
  END C2
  PIN VDD
    DIRECTION INOUT ;
    USE POWER ;
    SHAPE ABUTMENT ;
    PORT
      LAYER M1 ;
        RECT 0 0.261 0.648 0.279 ;
    END
  END VDD
  PIN VSS
    DIRECTION INOUT ;
    USE GROUND ;
    SHAPE ABUTMENT ;
    PORT
      LAYER M1 ;
        RECT 0 -0.009 0.648 0.009 ;
    END
  END VSS
  PIN Y
    DIRECTION OUTPUT ;
    USE SIGNAL ;
    PORT
      LAYER M1 ;
        RECT 0.018 0.225 0.137 0.243 ;
        RECT 0.018 0.027 0.122 0.045 ;
        RECT 0.018 0.027 0.036 0.243 ;
    END
  END Y
  OBS
    LAYER M1 ;
      RECT 0 0 0 0 ;
  END
END OA332x2_bottom

MACRO OA333x1_bottom
  CLASS CORE ;
  ORIGIN 0 0 ;
  FOREIGN OA333x1_bottom 0 0 ;
  SIZE 0.054 BY 0.270 ;
  SYMMETRY X Y ;
  SITE asap7sc7p5t ;
  PIN A1
    DIRECTION INPUT ;
    USE SIGNAL ;
    PORT
      LAYER M1 ;
        RECT 0.558 0.106 0.576 0.2 ;
    END
  END A1
  PIN A2
    DIRECTION INPUT ;
    USE SIGNAL ;
    PORT
      LAYER M1 ;
        RECT 0.504 0.106 0.522 0.2 ;
    END
  END A2
  PIN A3
    DIRECTION INPUT ;
    USE SIGNAL ;
    PORT
      LAYER M1 ;
        RECT 0.45 0.106 0.468 0.2 ;
    END
  END A3
  PIN B1
    DIRECTION INPUT ;
    USE SIGNAL ;
    PORT
      LAYER M1 ;
        RECT 0.288 0.106 0.306 0.2 ;
    END
  END B1
  PIN B2
    DIRECTION INPUT ;
    USE SIGNAL ;
    PORT
      LAYER M1 ;
        RECT 0.342 0.106 0.36 0.2 ;
    END
  END B2
  PIN B3
    DIRECTION INPUT ;
    USE SIGNAL ;
    PORT
      LAYER M1 ;
        RECT 0.396 0.106 0.414 0.2 ;
    END
  END B3
  PIN C1
    DIRECTION INPUT ;
    USE SIGNAL ;
    PORT
      LAYER M1 ;
        RECT 0.234 0.106 0.252 0.2 ;
    END
  END C1
  PIN C2
    DIRECTION INPUT ;
    USE SIGNAL ;
    PORT
      LAYER M1 ;
        RECT 0.18 0.07 0.198 0.2 ;
    END
  END C2
  PIN C3
    DIRECTION INPUT ;
    USE SIGNAL ;
    PORT
      LAYER M1 ;
        RECT 0.126 0.07 0.144 0.164 ;
    END
  END C3
  PIN VDD
    DIRECTION INOUT ;
    USE POWER ;
    SHAPE ABUTMENT ;
    PORT
      LAYER M1 ;
        RECT 0 0.261 0.648 0.279 ;
    END
  END VDD
  PIN VSS
    DIRECTION INOUT ;
    USE GROUND ;
    SHAPE ABUTMENT ;
    PORT
      LAYER M1 ;
        RECT 0 -0.009 0.648 0.009 ;
    END
  END VSS
  PIN Y
    DIRECTION OUTPUT ;
    USE SIGNAL ;
    PORT
      LAYER M1 ;
        RECT 0.018 0.225 0.068 0.243 ;
        RECT 0.018 0.027 0.068 0.045 ;
        RECT 0.018 0.027 0.036 0.243 ;
    END
  END Y
  OBS
    LAYER M1 ;
      RECT 0 0 0 0 ;
  END
END OA333x1_bottom

MACRO OA333x2_bottom
  CLASS CORE ;
  ORIGIN 0 0 ;
  FOREIGN OA333x2_bottom 0 0 ;
  SIZE 0.054 BY 0.270 ;
  SYMMETRY X Y ;
  SITE asap7sc7p5t ;
  PIN A1
    DIRECTION INPUT ;
    USE SIGNAL ;
    PORT
      LAYER M1 ;
        RECT 0.612 0.106 0.63 0.2 ;
    END
  END A1
  PIN A2
    DIRECTION INPUT ;
    USE SIGNAL ;
    PORT
      LAYER M1 ;
        RECT 0.558 0.106 0.576 0.2 ;
    END
  END A2
  PIN A3
    DIRECTION INPUT ;
    USE SIGNAL ;
    PORT
      LAYER M1 ;
        RECT 0.504 0.106 0.522 0.2 ;
    END
  END A3
  PIN B1
    DIRECTION INPUT ;
    USE SIGNAL ;
    PORT
      LAYER M1 ;
        RECT 0.342 0.106 0.36 0.2 ;
    END
  END B1
  PIN B2
    DIRECTION INPUT ;
    USE SIGNAL ;
    PORT
      LAYER M1 ;
        RECT 0.396 0.106 0.414 0.2 ;
    END
  END B2
  PIN B3
    DIRECTION INPUT ;
    USE SIGNAL ;
    PORT
      LAYER M1 ;
        RECT 0.45 0.106 0.468 0.2 ;
    END
  END B3
  PIN C1
    DIRECTION INPUT ;
    USE SIGNAL ;
    PORT
      LAYER M1 ;
        RECT 0.288 0.106 0.306 0.2 ;
    END
  END C1
  PIN C2
    DIRECTION INPUT ;
    USE SIGNAL ;
    PORT
      LAYER M1 ;
        RECT 0.234 0.07 0.252 0.2 ;
    END
  END C2
  PIN C3
    DIRECTION INPUT ;
    USE SIGNAL ;
    PORT
      LAYER M1 ;
        RECT 0.18 0.07 0.198 0.164 ;
    END
  END C3
  PIN VDD
    DIRECTION INOUT ;
    USE POWER ;
    SHAPE ABUTMENT ;
    PORT
      LAYER M1 ;
        RECT 0 0.261 0.702 0.279 ;
    END
  END VDD
  PIN VSS
    DIRECTION INOUT ;
    USE GROUND ;
    SHAPE ABUTMENT ;
    PORT
      LAYER M1 ;
        RECT 0 -0.009 0.702 0.009 ;
    END
  END VSS
  PIN Y
    DIRECTION OUTPUT ;
    USE SIGNAL ;
    PORT
      LAYER M1 ;
        RECT 0.072 0.225 0.122 0.243 ;
        RECT 0.072 0.027 0.122 0.045 ;
        RECT 0.072 0.027 0.09 0.243 ;
    END
  END Y
  OBS
    LAYER M1 ;
      RECT 0 0 0 0 ;
  END
END OA333x2_bottom

MACRO OA33x2_bottom
  CLASS CORE ;
  ORIGIN 0 0 ;
  FOREIGN OA33x2_bottom 0 0 ;
  SIZE 0.054 BY 0.270 ;
  SYMMETRY X Y ;
  SITE asap7sc7p5t ;
  PIN A1
    DIRECTION INPUT ;
    USE SIGNAL ;
    PORT
      LAYER M1 ;
        RECT 0.18 0.07 0.198 0.2 ;
    END
  END A1
  PIN A2
    DIRECTION INPUT ;
    USE SIGNAL ;
    PORT
      LAYER M1 ;
        RECT 0.234 0.07 0.252 0.2 ;
    END
  END A2
  PIN A3
    DIRECTION INPUT ;
    USE SIGNAL ;
    PORT
      LAYER M1 ;
        RECT 0.288 0.07 0.306 0.2 ;
    END
  END A3
  PIN B1
    DIRECTION INPUT ;
    USE SIGNAL ;
    PORT
      LAYER M1 ;
        RECT 0.45 0.106 0.468 0.2 ;
    END
  END B1
  PIN B2
    DIRECTION INPUT ;
    USE SIGNAL ;
    PORT
      LAYER M1 ;
        RECT 0.396 0.106 0.414 0.2 ;
    END
  END B2
  PIN B3
    DIRECTION INPUT ;
    USE SIGNAL ;
    PORT
      LAYER M1 ;
        RECT 0.342 0.106 0.36 0.2 ;
    END
  END B3
  PIN VDD
    DIRECTION INOUT ;
    USE POWER ;
    SHAPE ABUTMENT ;
    PORT
      LAYER M1 ;
        RECT 0 0.261 0.54 0.279 ;
    END
  END VDD
  PIN VSS
    DIRECTION INOUT ;
    USE GROUND ;
    SHAPE ABUTMENT ;
    PORT
      LAYER M1 ;
        RECT 0 -0.009 0.54 0.009 ;
    END
  END VSS
  PIN Y
    DIRECTION OUTPUT ;
    USE SIGNAL ;
    PORT
      LAYER M1 ;
        RECT 0.018 0.027 0.122 0.045 ;
        RECT 0.018 0.225 0.117 0.243 ;
        RECT 0.099 0.189 0.117 0.243 ;
        RECT 0.062 0.189 0.117 0.207 ;
        RECT 0.018 0.027 0.036 0.243 ;
    END
  END Y
  OBS
    LAYER M1 ;
      RECT 0 0 0 0 ;
  END
END OA33x2_bottom

MACRO OAI211xp5_bottom
  CLASS CORE ;
  ORIGIN 0 0 ;
  FOREIGN OAI211xp5_bottom 0 0 ;
  SIZE 0.054 BY 0.270 ;
  SYMMETRY X Y ;
  SITE asap7sc7p5t ;
  PIN A1
    DIRECTION INPUT ;
    USE SIGNAL ;
    PORT
      LAYER M1 ;
        RECT 0.126 0.106 0.144 0.2 ;
    END
  END A1
  PIN A2
    DIRECTION INPUT ;
    USE SIGNAL ;
    PORT
      LAYER M1 ;
        RECT 0.018 0.126 0.09 0.144 ;
        RECT 0.018 0.07 0.036 0.2 ;
    END
  END A2
  PIN B
    DIRECTION INPUT ;
    USE SIGNAL ;
    PORT
      LAYER M1 ;
        RECT 0.18 0.106 0.198 0.2 ;
    END
  END B
  PIN C
    DIRECTION INPUT ;
    USE SIGNAL ;
    PORT
      LAYER M1 ;
        RECT 0.234 0.106 0.252 0.2 ;
    END
  END C
  PIN VDD
    DIRECTION INOUT ;
    USE POWER ;
    SHAPE ABUTMENT ;
    PORT
      LAYER M1 ;
        RECT 0 0.261 0.324 0.279 ;
    END
  END VDD
  PIN VSS
    DIRECTION INOUT ;
    USE GROUND ;
    SHAPE ABUTMENT ;
    PORT
      LAYER M1 ;
        RECT 0 -0.009 0.324 0.009 ;
    END
  END VSS
  PIN Y
    DIRECTION OUTPUT ;
    USE SIGNAL ;
    PORT
      LAYER M1 ;
        RECT 0.04 0.225 0.306 0.243 ;
        RECT 0.288 0.063 0.306 0.243 ;
        RECT 0.099 0.063 0.306 0.081 ;
    END
  END Y
  OBS
    LAYER M1 ;
      RECT 0 0 0 0 ;
  END
END OAI211xp5_bottom

MACRO OAI21x1_bottom
  CLASS CORE ;
  ORIGIN 0 0 ;
  FOREIGN OAI21x1_bottom 0 0 ;
  SIZE 0.054 BY 0.270 ;
  SYMMETRY X Y ;
  SITE asap7sc7p5t ;
  PIN A1
    DIRECTION INPUT ;
    USE SIGNAL ;
    PORT
      LAYER M1 ;
        RECT 0.126 0.189 0.306 0.207 ;
        RECT 0.288 0.106 0.306 0.207 ;
        RECT 0.126 0.106 0.144 0.207 ;
    END
  END A1
  PIN A2
    DIRECTION INPUT ;
    USE SIGNAL ;
    PORT
      LAYER M1 ;
        RECT 0.19 0.127 0.256 0.145 ;
        RECT 0.19 0.099 0.227 0.171 ;
    END
  END A2
  PIN B
    DIRECTION INPUT ;
    USE SIGNAL ;
    PORT
      LAYER M1 ;
        RECT 0.342 0.063 0.36 0.154 ;
        RECT 0.072 0.063 0.36 0.081 ;
        RECT 0.072 0.063 0.09 0.2 ;
    END
  END B
  PIN VDD
    DIRECTION INOUT ;
    USE POWER ;
    SHAPE ABUTMENT ;
    PORT
      LAYER M1 ;
        RECT 0 0.261 0.432 0.279 ;
    END
  END VDD
  PIN VSS
    DIRECTION INOUT ;
    USE GROUND ;
    SHAPE ABUTMENT ;
    PORT
      LAYER M1 ;
        RECT 0 -0.009 0.432 0.009 ;
    END
  END VSS
  PIN Y
    DIRECTION OUTPUT ;
    USE SIGNAL ;
    PORT
      LAYER M1 ;
        RECT 0.018 0.225 0.414 0.243 ;
        RECT 0.396 0.027 0.414 0.243 ;
        RECT 0.369 0.027 0.414 0.045 ;
        RECT 0.018 0.027 0.063 0.045 ;
        RECT 0.018 0.027 0.036 0.243 ;
    END
  END Y
  OBS
    LAYER M1 ;
      RECT 0 0 0 0 ;
  END
END OAI21x1_bottom

MACRO OAI21xp33_bottom
  CLASS CORE ;
  ORIGIN 0 0 ;
  FOREIGN OAI21xp33_bottom 0 0 ;
  SIZE 0.054 BY 0.270 ;
  SYMMETRY X Y ;
  SITE asap7sc7p5t ;
  PIN A1
    DIRECTION INPUT ;
    USE SIGNAL ;
    PORT
      LAYER M1 ;
        RECT 0.018 0.07 0.036 0.236 ;
    END
  END A1
  PIN A2
    DIRECTION INPUT ;
    USE SIGNAL ;
    PORT
      LAYER M1 ;
        RECT 0.126 0.106 0.144 0.203 ;
    END
  END A2
  PIN B
    DIRECTION INPUT ;
    USE SIGNAL ;
    PORT
      LAYER M1 ;
        RECT 0.18 0.106 0.198 0.2 ;
    END
  END B
  PIN VDD
    DIRECTION INOUT ;
    USE POWER ;
    SHAPE ABUTMENT ;
    PORT
      LAYER M1 ;
        RECT 0 0.261 0.27 0.279 ;
    END
  END VDD
  PIN VSS
    DIRECTION INOUT ;
    USE GROUND ;
    SHAPE ABUTMENT ;
    PORT
      LAYER M1 ;
        RECT 0 -0.009 0.27 0.009 ;
    END
  END VSS
  PIN Y
    DIRECTION OUTPUT ;
    USE SIGNAL ;
    PORT
      LAYER M1 ;
        RECT 0.148 0.225 0.252 0.243 ;
        RECT 0.234 0.063 0.252 0.243 ;
        RECT 0.099 0.063 0.252 0.081 ;
    END
  END Y
  OBS
    LAYER M1 ;
      RECT 0 0 0 0 ;
  END
END OAI21xp33_bottom

MACRO OAI21xp5_bottom
  CLASS CORE ;
  ORIGIN 0 0 ;
  FOREIGN OAI21xp5_bottom 0 0 ;
  SIZE 0.054 BY 0.270 ;
  SYMMETRY X Y ;
  SITE asap7sc7p5t ;
  PIN A1
    DIRECTION INPUT ;
    USE SIGNAL ;
    PORT
      LAYER M1 ;
        RECT 0.018 0.07 0.036 0.236 ;
    END
  END A1
  PIN A2
    DIRECTION INPUT ;
    USE SIGNAL ;
    PORT
      LAYER M1 ;
        RECT 0.126 0.106 0.144 0.203 ;
    END
  END A2
  PIN B
    DIRECTION INPUT ;
    USE SIGNAL ;
    PORT
      LAYER M1 ;
        RECT 0.18 0.106 0.198 0.171 ;
    END
  END B
  PIN VDD
    DIRECTION INOUT ;
    USE POWER ;
    SHAPE ABUTMENT ;
    PORT
      LAYER M1 ;
        RECT 0 0.261 0.27 0.279 ;
    END
  END VDD
  PIN VSS
    DIRECTION INOUT ;
    USE GROUND ;
    SHAPE ABUTMENT ;
    PORT
      LAYER M1 ;
        RECT 0 -0.009 0.27 0.009 ;
    END
  END VSS
  PIN Y
    DIRECTION OUTPUT ;
    USE SIGNAL ;
    PORT
      LAYER M1 ;
        RECT 0.148 0.225 0.252 0.243 ;
        RECT 0.234 0.063 0.252 0.243 ;
        RECT 0.099 0.063 0.252 0.081 ;
    END
  END Y
  OBS
    LAYER M1 ;
      RECT 0 0 0 0 ;
  END
END OAI21xp5_bottom

MACRO OAI221xp5_bottom
  CLASS CORE ;
  ORIGIN 0 0 ;
  FOREIGN OAI221xp5_bottom 0 0 ;
  SIZE 0.054 BY 0.270 ;
  SYMMETRY X Y ;
  SITE asap7sc7p5t ;
  PIN A1
    DIRECTION INPUT ;
    USE SIGNAL ;
    PORT
      LAYER M1 ;
        RECT 0.234 0.106 0.252 0.2 ;
    END
  END A1
  PIN A2
    DIRECTION INPUT ;
    USE SIGNAL ;
    PORT
      LAYER M1 ;
        RECT 0.288 0.106 0.306 0.236 ;
    END
  END A2
  PIN B1
    DIRECTION INPUT ;
    USE SIGNAL ;
    PORT
      LAYER M1 ;
        RECT 0.072 0.106 0.09 0.2 ;
    END
  END B1
  PIN B2
    DIRECTION INPUT ;
    USE SIGNAL ;
    PORT
      LAYER M1 ;
        RECT 0.126 0.106 0.144 0.2 ;
    END
  END B2
  PIN C
    DIRECTION INPUT ;
    USE SIGNAL ;
    PORT
      LAYER M1 ;
        RECT 0.18 0.106 0.198 0.2 ;
    END
  END C
  PIN VDD
    DIRECTION INOUT ;
    USE POWER ;
    SHAPE ABUTMENT ;
    PORT
      LAYER M1 ;
        RECT 0 0.261 0.378 0.279 ;
    END
  END VDD
  PIN VSS
    DIRECTION INOUT ;
    USE GROUND ;
    SHAPE ABUTMENT ;
    PORT
      LAYER M1 ;
        RECT 0 -0.009 0.378 0.009 ;
    END
  END VSS
  PIN Y
    DIRECTION OUTPUT ;
    USE SIGNAL ;
    PORT
      LAYER M1 ;
        RECT 0.018 0.225 0.23 0.243 ;
        RECT 0.018 0.063 0.123 0.081 ;
        RECT 0.018 0.063 0.036 0.243 ;
    END
  END Y
  OBS
    LAYER M1 ;
      RECT 0 0 0 0 ;
  END
END OAI221xp5_bottom

MACRO OAI222xp33_bottom
  CLASS CORE ;
  ORIGIN 0 0 ;
  FOREIGN OAI222xp33_bottom 0 0 ;
  SIZE 0.054 BY 0.270 ;
  SYMMETRY X Y ;
  SITE asap7sc7p5t ;
  PIN A1
    DIRECTION INPUT ;
    USE SIGNAL ;
    PORT
      LAYER M1 ;
        RECT 0.072 0.106 0.09 0.2 ;
    END
  END A1
  PIN A2
    DIRECTION INPUT ;
    USE SIGNAL ;
    PORT
      LAYER M1 ;
        RECT 0.126 0.106 0.144 0.2 ;
    END
  END A2
  PIN B1
    DIRECTION INPUT ;
    USE SIGNAL ;
    PORT
      LAYER M1 ;
        RECT 0.234 0.106 0.252 0.2 ;
    END
  END B1
  PIN B2
    DIRECTION INPUT ;
    USE SIGNAL ;
    PORT
      LAYER M1 ;
        RECT 0.18 0.106 0.198 0.2 ;
    END
  END B2
  PIN C1
    DIRECTION INPUT ;
    USE SIGNAL ;
    PORT
      LAYER M1 ;
        RECT 0.396 0.07 0.414 0.2 ;
    END
  END C1
  PIN C2
    DIRECTION INPUT ;
    USE SIGNAL ;
    PORT
      LAYER M1 ;
        RECT 0.45 0.07 0.468 0.2 ;
    END
  END C2
  PIN VDD
    DIRECTION INOUT ;
    USE POWER ;
    SHAPE ABUTMENT ;
    PORT
      LAYER M1 ;
        RECT 0 0.261 0.54 0.279 ;
    END
  END VDD
  PIN VSS
    DIRECTION INOUT ;
    USE GROUND ;
    SHAPE ABUTMENT ;
    PORT
      LAYER M1 ;
        RECT 0 -0.009 0.54 0.009 ;
    END
  END VSS
  PIN Y
    DIRECTION OUTPUT ;
    USE SIGNAL ;
    PORT
      LAYER M1 ;
        RECT 0.018 0.225 0.522 0.243 ;
        RECT 0.504 0.055 0.522 0.243 ;
        RECT 0.018 0.063 0.122 0.081 ;
        RECT 0.018 0.063 0.036 0.243 ;
    END
  END Y
  OBS
    LAYER M1 ;
      RECT 0 0 0 0 ;
  END
END OAI222xp33_bottom

MACRO OAI22x1_bottom
  CLASS CORE ;
  ORIGIN 0 0 ;
  FOREIGN OAI22x1_bottom 0 0 ;
  SIZE 0.054 BY 0.270 ;
  SYMMETRY X Y ;
  SITE asap7sc7p5t ;
  PIN A1
    DIRECTION INPUT ;
    USE SIGNAL ;
    PORT
      LAYER M1 ;
        RECT 0.342 0.153 0.379 0.171 ;
        RECT 0.342 0.099 0.379 0.117 ;
        RECT 0.342 0.099 0.36 0.171 ;
    END
  END A1
  PIN A2
    DIRECTION INPUT ;
    USE SIGNAL ;
    PORT
      LAYER M1 ;
        RECT 0.288 0.189 0.468 0.207 ;
        RECT 0.45 0.099 0.468 0.207 ;
        RECT 0.431 0.099 0.468 0.117 ;
        RECT 0.288 0.118 0.306 0.207 ;
    END
  END A2
  PIN B1
    DIRECTION INPUT ;
    USE SIGNAL ;
    PORT
      LAYER M1 ;
        RECT 0.161 0.153 0.198 0.171 ;
        RECT 0.18 0.063 0.198 0.171 ;
        RECT 0.161 0.063 0.198 0.081 ;
    END
  END B1
  PIN B2
    DIRECTION INPUT ;
    USE SIGNAL ;
    PORT
      LAYER M1 ;
        RECT 0.072 0.189 0.252 0.207 ;
        RECT 0.234 0.116 0.252 0.207 ;
        RECT 0.072 0.063 0.109 0.081 ;
        RECT 0.072 0.063 0.09 0.207 ;
    END
  END B2
  PIN VDD
    DIRECTION INOUT ;
    USE POWER ;
    SHAPE ABUTMENT ;
    PORT
      LAYER M1 ;
        RECT 0 0.261 0.54 0.279 ;
    END
  END VDD
  PIN VSS
    DIRECTION INOUT ;
    USE GROUND ;
    SHAPE ABUTMENT ;
    PORT
      LAYER M1 ;
        RECT 0 -0.009 0.54 0.009 ;
    END
  END VSS
  PIN Y
    DIRECTION OUTPUT ;
    USE SIGNAL ;
    PORT
      LAYER M1 ;
        RECT 0.038 0.225 0.522 0.243 ;
        RECT 0.504 0.063 0.522 0.243 ;
        RECT 0.309 0.063 0.522 0.081 ;
    END
  END Y
  OBS
    LAYER M1 ;
      RECT 0 0 0 0 ;
  END
END OAI22x1_bottom

MACRO OAI22xp33_bottom
  CLASS CORE ;
  ORIGIN 0 0 ;
  FOREIGN OAI22xp33_bottom 0 0 ;
  SIZE 0.054 BY 0.270 ;
  SYMMETRY X Y ;
  SITE asap7sc7p5t ;
  PIN A1
    DIRECTION INPUT ;
    USE SIGNAL ;
    PORT
      LAYER M1 ;
        RECT 0.072 0.106 0.09 0.2 ;
    END
  END A1
  PIN A2
    DIRECTION INPUT ;
    USE SIGNAL ;
    PORT
      LAYER M1 ;
        RECT 0.126 0.106 0.144 0.2 ;
    END
  END A2
  PIN B1
    DIRECTION INPUT ;
    USE SIGNAL ;
    PORT
      LAYER M1 ;
        RECT 0.234 0.225 0.275 0.243 ;
        RECT 0.234 0.07 0.252 0.243 ;
    END
  END B1
  PIN B2
    DIRECTION INPUT ;
    USE SIGNAL ;
    PORT
      LAYER M1 ;
        RECT 0.18 0.07 0.198 0.2 ;
    END
  END B2
  PIN VDD
    DIRECTION INOUT ;
    USE POWER ;
    SHAPE ABUTMENT ;
    PORT
      LAYER M1 ;
        RECT 0 0.261 0.324 0.279 ;
    END
  END VDD
  PIN VSS
    DIRECTION INOUT ;
    USE GROUND ;
    SHAPE ABUTMENT ;
    PORT
      LAYER M1 ;
        RECT 0 -0.009 0.324 0.009 ;
    END
  END VSS
  PIN Y
    DIRECTION OUTPUT ;
    USE SIGNAL ;
    PORT
      LAYER M1 ;
        RECT 0.018 0.225 0.176 0.243 ;
        RECT 0.018 0.063 0.117 0.081 ;
        RECT 0.018 0.063 0.036 0.243 ;
    END
  END Y
  OBS
    LAYER M1 ;
      RECT 0 0 0 0 ;
  END
END OAI22xp33_bottom

MACRO OAI22xp5_bottom
  CLASS CORE ;
  ORIGIN 0 0 ;
  FOREIGN OAI22xp5_bottom 0 0 ;
  SIZE 0.054 BY 0.270 ;
  SYMMETRY X Y ;
  SITE asap7sc7p5t ;
  PIN A1
    DIRECTION INPUT ;
    USE SIGNAL ;
    PORT
      LAYER M1 ;
        RECT 0.072 0.106 0.09 0.2 ;
    END
  END A1
  PIN A2
    DIRECTION INPUT ;
    USE SIGNAL ;
    PORT
      LAYER M1 ;
        RECT 0.126 0.106 0.144 0.2 ;
    END
  END A2
  PIN B1
    DIRECTION INPUT ;
    USE SIGNAL ;
    PORT
      LAYER M1 ;
        RECT 0.234 0.225 0.275 0.243 ;
        RECT 0.234 0.07 0.252 0.243 ;
    END
  END B1
  PIN B2
    DIRECTION INPUT ;
    USE SIGNAL ;
    PORT
      LAYER M1 ;
        RECT 0.18 0.063 0.198 0.164 ;
        RECT 0.151 0.063 0.198 0.081 ;
    END
  END B2
  PIN VDD
    DIRECTION INOUT ;
    USE POWER ;
    SHAPE ABUTMENT ;
    PORT
      LAYER M1 ;
        RECT 0 0.261 0.324 0.279 ;
    END
  END VDD
  PIN VSS
    DIRECTION INOUT ;
    USE GROUND ;
    SHAPE ABUTMENT ;
    PORT
      LAYER M1 ;
        RECT 0 -0.009 0.324 0.009 ;
    END
  END VSS
  PIN Y
    DIRECTION OUTPUT ;
    USE SIGNAL ;
    PORT
      LAYER M1 ;
        RECT 0.018 0.225 0.176 0.243 ;
        RECT 0.018 0.063 0.117 0.081 ;
        RECT 0.018 0.063 0.036 0.243 ;
    END
  END Y
  OBS
    LAYER M1 ;
      RECT 0 0 0 0 ;
  END
END OAI22xp5_bottom

MACRO OAI311xp33_bottom
  CLASS CORE ;
  ORIGIN 0 0 ;
  FOREIGN OAI311xp33_bottom 0 0 ;
  SIZE 0.054 BY 0.270 ;
  SYMMETRY X Y ;
  SITE asap7sc7p5t ;
  PIN A1
    DIRECTION INPUT ;
    USE SIGNAL ;
    PORT
      LAYER M1 ;
        RECT 0.18 0.07 0.198 0.2 ;
    END
  END A1
  PIN A2
    DIRECTION INPUT ;
    USE SIGNAL ;
    PORT
      LAYER M1 ;
        RECT 0.126 0.07 0.144 0.236 ;
    END
  END A2
  PIN A3
    DIRECTION INPUT ;
    USE SIGNAL ;
    PORT
      LAYER M1 ;
        RECT 0.018 0.126 0.095 0.144 ;
        RECT 0.018 0.034 0.036 0.236 ;
    END
  END A3
  PIN B1
    DIRECTION INPUT ;
    USE SIGNAL ;
    PORT
      LAYER M1 ;
        RECT 0.234 0.07 0.252 0.2 ;
    END
  END B1
  PIN C1
    DIRECTION INPUT ;
    USE SIGNAL ;
    PORT
      LAYER M1 ;
        RECT 0.288 0.07 0.306 0.2 ;
    END
  END C1
  PIN VDD
    DIRECTION INOUT ;
    USE POWER ;
    SHAPE ABUTMENT ;
    PORT
      LAYER M1 ;
        RECT 0 0.261 0.378 0.279 ;
    END
  END VDD
  PIN VSS
    DIRECTION INOUT ;
    USE GROUND ;
    SHAPE ABUTMENT ;
    PORT
      LAYER M1 ;
        RECT 0 -0.009 0.378 0.009 ;
    END
  END VSS
  PIN Y
    DIRECTION OUTPUT ;
    USE SIGNAL ;
    PORT
      LAYER M1 ;
        RECT 0.198 0.225 0.36 0.243 ;
        RECT 0.342 0.027 0.36 0.243 ;
        RECT 0.31 0.027 0.36 0.045 ;
    END
  END Y
  OBS
    LAYER M1 ;
      RECT 0 0 0 0 ;
  END
END OAI311xp33_bottom

MACRO OAI31xp33_bottom
  CLASS CORE ;
  ORIGIN 0 0 ;
  FOREIGN OAI31xp33_bottom 0 0 ;
  SIZE 0.054 BY 0.270 ;
  SYMMETRY X Y ;
  SITE asap7sc7p5t ;
  PIN A1
    DIRECTION INPUT ;
    USE SIGNAL ;
    PORT
      LAYER M1 ;
        RECT 0.18 0.07 0.198 0.2 ;
    END
  END A1
  PIN A2
    DIRECTION INPUT ;
    USE SIGNAL ;
    PORT
      LAYER M1 ;
        RECT 0.126 0.07 0.144 0.236 ;
    END
  END A2
  PIN A3
    DIRECTION INPUT ;
    USE SIGNAL ;
    PORT
      LAYER M1 ;
        RECT 0.072 0.07 0.09 0.236 ;
    END
  END A3
  PIN B
    DIRECTION INPUT ;
    USE SIGNAL ;
    PORT
      LAYER M1 ;
        RECT 0.234 0.106 0.252 0.2 ;
    END
  END B
  PIN VDD
    DIRECTION INOUT ;
    USE POWER ;
    SHAPE ABUTMENT ;
    PORT
      LAYER M1 ;
        RECT 0 0.261 0.324 0.279 ;
    END
  END VDD
  PIN VSS
    DIRECTION INOUT ;
    USE GROUND ;
    SHAPE ABUTMENT ;
    PORT
      LAYER M1 ;
        RECT 0 -0.009 0.324 0.009 ;
    END
  END VSS
  PIN Y
    DIRECTION OUTPUT ;
    USE SIGNAL ;
    PORT
      LAYER M1 ;
        RECT 0.201 0.225 0.306 0.243 ;
        RECT 0.288 0.063 0.306 0.243 ;
        RECT 0.256 0.063 0.306 0.081 ;
    END
  END Y
  OBS
    LAYER M1 ;
      RECT 0 0 0 0 ;
  END
END OAI31xp33_bottom

MACRO OAI31xp67_bottom
  CLASS CORE ;
  ORIGIN 0 0 ;
  FOREIGN OAI31xp67_bottom 0 0 ;
  SIZE 0.054 BY 0.270 ;
  SYMMETRY X Y ;
  SITE asap7sc7p5t ;
  PIN A1
    DIRECTION INPUT ;
    USE SIGNAL ;
    PORT
      LAYER M1 ;
        RECT 0.666 0.126 0.684 0.198 ;
        RECT 0.553 0.126 0.684 0.144 ;
    END
  END A1
  PIN A2
    DIRECTION INPUT ;
    USE SIGNAL ;
    PORT
      LAYER M1 ;
        RECT 0.288 0.126 0.419 0.144 ;
        RECT 0.288 0.126 0.306 0.2 ;
    END
  END A2
  PIN A3
    DIRECTION INPUT ;
    USE SIGNAL ;
    PORT
      LAYER M1 ;
        RECT 0.018 0.126 0.095 0.144 ;
        RECT 0.018 0.07 0.036 0.236 ;
    END
  END A3
  PIN B
    DIRECTION INPUT ;
    USE SIGNAL ;
    PORT
      LAYER M1 ;
        RECT 0.126 0.126 0.203 0.144 ;
        RECT 0.126 0.07 0.144 0.2 ;
    END
  END B
  PIN VDD
    DIRECTION INOUT ;
    USE POWER ;
    SHAPE ABUTMENT ;
    PORT
      LAYER M1 ;
        RECT 0 0.261 0.702 0.279 ;
    END
  END VDD
  PIN VSS
    DIRECTION INOUT ;
    USE GROUND ;
    SHAPE ABUTMENT ;
    PORT
      LAYER M1 ;
        RECT 0 -0.009 0.702 0.009 ;
    END
  END VSS
  PIN Y
    DIRECTION OUTPUT ;
    USE SIGNAL ;
    PORT
      LAYER M1 ;
        RECT 0.202 0.063 0.663 0.081 ;
        RECT 0.202 0.189 0.252 0.207 ;
        RECT 0.234 0.063 0.252 0.207 ;
    END
  END Y
  OBS
    LAYER M1 ;
      RECT 0 0 0 0 ;
  END
END OAI31xp67_bottom

MACRO OAI321xp33_bottom
  CLASS CORE ;
  ORIGIN 0 0 ;
  FOREIGN OAI321xp33_bottom 0 0 ;
  SIZE 0.054 BY 0.270 ;
  SYMMETRY X Y ;
  SITE asap7sc7p5t ;
  PIN A1
    DIRECTION INPUT ;
    USE SIGNAL ;
    PORT
      LAYER M1 ;
        RECT 0.18 0.106 0.198 0.2 ;
    END
  END A1
  PIN A2
    DIRECTION INPUT ;
    USE SIGNAL ;
    PORT
      LAYER M1 ;
        RECT 0.126 0.106 0.144 0.236 ;
    END
  END A2
  PIN A3
    DIRECTION INPUT ;
    USE SIGNAL ;
    PORT
      LAYER M1 ;
        RECT 0.018 0.126 0.095 0.144 ;
        RECT 0.018 0.034 0.036 0.236 ;
    END
  END A3
  PIN B1
    DIRECTION INPUT ;
    USE SIGNAL ;
    PORT
      LAYER M1 ;
        RECT 0.288 0.106 0.306 0.2 ;
    END
  END B1
  PIN B2
    DIRECTION INPUT ;
    USE SIGNAL ;
    PORT
      LAYER M1 ;
        RECT 0.342 0.106 0.36 0.2 ;
    END
  END B2
  PIN C
    DIRECTION INPUT ;
    USE SIGNAL ;
    PORT
      LAYER M1 ;
        RECT 0.234 0.106 0.252 0.2 ;
    END
  END C
  PIN VDD
    DIRECTION INOUT ;
    USE POWER ;
    SHAPE ABUTMENT ;
    PORT
      LAYER M1 ;
        RECT 0 0.261 0.432 0.279 ;
    END
  END VDD
  PIN VSS
    DIRECTION INOUT ;
    USE GROUND ;
    SHAPE ABUTMENT ;
    PORT
      LAYER M1 ;
        RECT 0 -0.009 0.432 0.009 ;
    END
  END VSS
  PIN Y
    DIRECTION OUTPUT ;
    USE SIGNAL ;
    PORT
      LAYER M1 ;
        RECT 0.198 0.225 0.414 0.243 ;
        RECT 0.396 0.063 0.414 0.243 ;
        RECT 0.31 0.063 0.414 0.081 ;
    END
  END Y
  OBS
    LAYER M1 ;
      RECT 0 0 0 0 ;
  END
END OAI321xp33_bottom

MACRO OAI322xp33_bottom
  CLASS CORE ;
  ORIGIN 0 0 ;
  FOREIGN OAI322xp33_bottom 0 0 ;
  SIZE 0.054 BY 0.270 ;
  SYMMETRY X Y ;
  SITE asap7sc7p5t ;
  PIN A1
    DIRECTION INPUT ;
    USE SIGNAL ;
    PORT
      LAYER M1 ;
        RECT 0.18 0.106 0.198 0.2 ;
    END
  END A1
  PIN A2
    DIRECTION INPUT ;
    USE SIGNAL ;
    PORT
      LAYER M1 ;
        RECT 0.234 0.106 0.252 0.2 ;
    END
  END A2
  PIN A3
    DIRECTION INPUT ;
    USE SIGNAL ;
    PORT
      LAYER M1 ;
        RECT 0.288 0.105 0.306 0.2 ;
    END
  END A3
  PIN B1
    DIRECTION INPUT ;
    USE SIGNAL ;
    PORT
      LAYER M1 ;
        RECT 0.126 0.106 0.144 0.2 ;
    END
  END B1
  PIN B2
    DIRECTION INPUT ;
    USE SIGNAL ;
    PORT
      LAYER M1 ;
        RECT 0.072 0.106 0.09 0.236 ;
    END
  END B2
  PIN C1
    DIRECTION INPUT ;
    USE SIGNAL ;
    PORT
      LAYER M1 ;
        RECT 0.396 0.106 0.414 0.2 ;
    END
  END C1
  PIN C2
    DIRECTION INPUT ;
    USE SIGNAL ;
    PORT
      LAYER M1 ;
        RECT 0.342 0.105 0.36 0.2 ;
    END
  END C2
  PIN VDD
    DIRECTION INOUT ;
    USE POWER ;
    SHAPE ABUTMENT ;
    PORT
      LAYER M1 ;
        RECT 0 0.261 0.486 0.279 ;
    END
  END VDD
  PIN VSS
    DIRECTION INOUT ;
    USE GROUND ;
    SHAPE ABUTMENT ;
    PORT
      LAYER M1 ;
        RECT 0 -0.009 0.486 0.009 ;
    END
  END VSS
  PIN Y
    DIRECTION OUTPUT ;
    USE SIGNAL ;
    PORT
      LAYER M1 ;
        RECT 0.147 0.225 0.468 0.243 ;
        RECT 0.45 0.063 0.468 0.243 ;
        RECT 0.364 0.063 0.468 0.081 ;
    END
  END Y
  OBS
    LAYER M1 ;
      RECT 0 0 0 0 ;
  END
END OAI322xp33_bottom

MACRO OAI32xp33_bottom
  CLASS CORE ;
  ORIGIN 0 0 ;
  FOREIGN OAI32xp33_bottom 0 0 ;
  SIZE 0.054 BY 0.270 ;
  SYMMETRY X Y ;
  SITE asap7sc7p5t ;
  PIN A1
    DIRECTION INPUT ;
    USE SIGNAL ;
    PORT
      LAYER M1 ;
        RECT 0.072 0.07 0.09 0.2 ;
    END
  END A1
  PIN A2
    DIRECTION INPUT ;
    USE SIGNAL ;
    PORT
      LAYER M1 ;
        RECT 0.126 0.07 0.144 0.2 ;
    END
  END A2
  PIN A3
    DIRECTION INPUT ;
    USE SIGNAL ;
    PORT
      LAYER M1 ;
        RECT 0.18 0.063 0.222 0.081 ;
        RECT 0.18 0.063 0.198 0.2 ;
    END
  END A3
  PIN B1
    DIRECTION INPUT ;
    USE SIGNAL ;
    PORT
      LAYER M1 ;
        RECT 0.234 0.106 0.252 0.2 ;
    END
  END B1
  PIN B2
    DIRECTION INPUT ;
    USE SIGNAL ;
    PORT
      LAYER M1 ;
        RECT 0.288 0.106 0.306 0.2 ;
    END
  END B2
  PIN VDD
    DIRECTION INOUT ;
    USE POWER ;
    SHAPE ABUTMENT ;
    PORT
      LAYER M1 ;
        RECT 0 0.261 0.378 0.279 ;
    END
  END VDD
  PIN VSS
    DIRECTION INOUT ;
    USE GROUND ;
    SHAPE ABUTMENT ;
    PORT
      LAYER M1 ;
        RECT 0 -0.009 0.378 0.009 ;
    END
  END VSS
  PIN Y
    DIRECTION OUTPUT ;
    USE SIGNAL ;
    PORT
      LAYER M1 ;
        RECT 0.04 0.225 0.36 0.243 ;
        RECT 0.342 0.063 0.36 0.243 ;
        RECT 0.256 0.063 0.36 0.081 ;
    END
  END Y
  OBS
    LAYER M1 ;
      RECT 0 0 0 0 ;
  END
END OAI32xp33_bottom

MACRO OAI331xp33_bottom
  CLASS CORE ;
  ORIGIN 0 0 ;
  FOREIGN OAI331xp33_bottom 0 0 ;
  SIZE 0.054 BY 0.270 ;
  SYMMETRY X Y ;
  SITE asap7sc7p5t ;
  PIN A1
    DIRECTION INPUT ;
    USE SIGNAL ;
    PORT
      LAYER M1 ;
        RECT 0.18 0.106 0.198 0.2 ;
    END
  END A1
  PIN A2
    DIRECTION INPUT ;
    USE SIGNAL ;
    PORT
      LAYER M1 ;
        RECT 0.126 0.106 0.144 0.236 ;
    END
  END A2
  PIN A3
    DIRECTION INPUT ;
    USE SIGNAL ;
    PORT
      LAYER M1 ;
        RECT 0.072 0.106 0.09 0.236 ;
    END
  END A3
  PIN B1
    DIRECTION INPUT ;
    USE SIGNAL ;
    PORT
      LAYER M1 ;
        RECT 0.234 0.106 0.252 0.2 ;
    END
  END B1
  PIN B2
    DIRECTION INPUT ;
    USE SIGNAL ;
    PORT
      LAYER M1 ;
        RECT 0.288 0.106 0.306 0.2 ;
    END
  END B2
  PIN B3
    DIRECTION INPUT ;
    USE SIGNAL ;
    PORT
      LAYER M1 ;
        RECT 0.342 0.106 0.36 0.2 ;
    END
  END B3
  PIN C1
    DIRECTION INPUT ;
    USE SIGNAL ;
    PORT
      LAYER M1 ;
        RECT 0.396 0.106 0.414 0.2 ;
    END
  END C1
  PIN VDD
    DIRECTION INOUT ;
    USE POWER ;
    SHAPE ABUTMENT ;
    PORT
      LAYER M1 ;
        RECT 0 0.261 0.486 0.279 ;
    END
  END VDD
  PIN VSS
    DIRECTION INOUT ;
    USE GROUND ;
    SHAPE ABUTMENT ;
    PORT
      LAYER M1 ;
        RECT 0 -0.009 0.486 0.009 ;
    END
  END VSS
  PIN Y
    DIRECTION OUTPUT ;
    USE SIGNAL ;
    PORT
      LAYER M1 ;
        RECT 0.201 0.225 0.468 0.243 ;
        RECT 0.45 0.063 0.468 0.243 ;
        RECT 0.417 0.063 0.468 0.081 ;
    END
  END Y
  OBS
    LAYER M1 ;
      RECT 0 0 0 0 ;
  END
END OAI331xp33_bottom

MACRO OAI332xp33_bottom
  CLASS CORE ;
  ORIGIN 0 0 ;
  FOREIGN OAI332xp33_bottom 0 0 ;
  SIZE 0.054 BY 0.270 ;
  SYMMETRY X Y ;
  SITE asap7sc7p5t ;
  PIN A1
    DIRECTION INPUT ;
    USE SIGNAL ;
    PORT
      LAYER M1 ;
        RECT 0.18 0.106 0.198 0.2 ;
    END
  END A1
  PIN A2
    DIRECTION INPUT ;
    USE SIGNAL ;
    PORT
      LAYER M1 ;
        RECT 0.126 0.106 0.144 0.236 ;
    END
  END A2
  PIN A3
    DIRECTION INPUT ;
    USE SIGNAL ;
    PORT
      LAYER M1 ;
        RECT 0.072 0.106 0.09 0.236 ;
    END
  END A3
  PIN B1
    DIRECTION INPUT ;
    USE SIGNAL ;
    PORT
      LAYER M1 ;
        RECT 0.234 0.106 0.252 0.2 ;
    END
  END B1
  PIN B2
    DIRECTION INPUT ;
    USE SIGNAL ;
    PORT
      LAYER M1 ;
        RECT 0.288 0.106 0.306 0.2 ;
    END
  END B2
  PIN B3
    DIRECTION INPUT ;
    USE SIGNAL ;
    PORT
      LAYER M1 ;
        RECT 0.342 0.106 0.36 0.2 ;
    END
  END B3
  PIN C1
    DIRECTION INPUT ;
    USE SIGNAL ;
    PORT
      LAYER M1 ;
        RECT 0.45 0.106 0.468 0.2 ;
    END
  END C1
  PIN C2
    DIRECTION INPUT ;
    USE SIGNAL ;
    PORT
      LAYER M1 ;
        RECT 0.396 0.106 0.414 0.2 ;
    END
  END C2
  PIN VDD
    DIRECTION INOUT ;
    USE POWER ;
    SHAPE ABUTMENT ;
    PORT
      LAYER M1 ;
        RECT 0 0.261 0.54 0.279 ;
    END
  END VDD
  PIN VSS
    DIRECTION INOUT ;
    USE GROUND ;
    SHAPE ABUTMENT ;
    PORT
      LAYER M1 ;
        RECT 0 -0.009 0.54 0.009 ;
    END
  END VSS
  PIN Y
    DIRECTION OUTPUT ;
    USE SIGNAL ;
    PORT
      LAYER M1 ;
        RECT 0.201 0.225 0.522 0.243 ;
        RECT 0.504 0.063 0.522 0.243 ;
        RECT 0.417 0.063 0.522 0.081 ;
    END
  END Y
  OBS
    LAYER M1 ;
      RECT 0 0 0 0 ;
  END
END OAI332xp33_bottom

MACRO OAI333xp33_bottom
  CLASS CORE ;
  ORIGIN 0 0 ;
  FOREIGN OAI333xp33_bottom 0 0 ;
  SIZE 0.054 BY 0.270 ;
  SYMMETRY X Y ;
  SITE asap7sc7p5t ;
  PIN A1
    DIRECTION INPUT ;
    USE SIGNAL ;
    PORT
      LAYER M1 ;
        RECT 0.504 0.106 0.522 0.2 ;
    END
  END A1
  PIN A2
    DIRECTION INPUT ;
    USE SIGNAL ;
    PORT
      LAYER M1 ;
        RECT 0.45 0.106 0.468 0.2 ;
    END
  END A2
  PIN A3
    DIRECTION INPUT ;
    USE SIGNAL ;
    PORT
      LAYER M1 ;
        RECT 0.396 0.106 0.414 0.2 ;
    END
  END A3
  PIN B1
    DIRECTION INPUT ;
    USE SIGNAL ;
    PORT
      LAYER M1 ;
        RECT 0.234 0.106 0.252 0.2 ;
    END
  END B1
  PIN B2
    DIRECTION INPUT ;
    USE SIGNAL ;
    PORT
      LAYER M1 ;
        RECT 0.288 0.106 0.306 0.2 ;
    END
  END B2
  PIN B3
    DIRECTION INPUT ;
    USE SIGNAL ;
    PORT
      LAYER M1 ;
        RECT 0.342 0.106 0.36 0.2 ;
    END
  END B3
  PIN C1
    DIRECTION INPUT ;
    USE SIGNAL ;
    PORT
      LAYER M1 ;
        RECT 0.18 0.106 0.198 0.2 ;
    END
  END C1
  PIN C2
    DIRECTION INPUT ;
    USE SIGNAL ;
    PORT
      LAYER M1 ;
        RECT 0.126 0.106 0.144 0.236 ;
    END
  END C2
  PIN C3
    DIRECTION INPUT ;
    USE SIGNAL ;
    PORT
      LAYER M1 ;
        RECT 0.072 0.106 0.09 0.236 ;
    END
  END C3
  PIN VDD
    DIRECTION INOUT ;
    USE POWER ;
    SHAPE ABUTMENT ;
    PORT
      LAYER M1 ;
        RECT 0 0.261 0.594 0.279 ;
    END
  END VDD
  PIN VSS
    DIRECTION INOUT ;
    USE GROUND ;
    SHAPE ABUTMENT ;
    PORT
      LAYER M1 ;
        RECT 0 -0.009 0.594 0.009 ;
    END
  END VSS
  PIN Y
    DIRECTION OUTPUT ;
    USE SIGNAL ;
    PORT
      LAYER M1 ;
        RECT 0.201 0.225 0.576 0.243 ;
        RECT 0.558 0.063 0.576 0.243 ;
        RECT 0.413 0.063 0.576 0.081 ;
    END
  END Y
  OBS
    LAYER M1 ;
      RECT 0 0 0 0 ;
  END
END OAI333xp33_bottom

MACRO OAI33xp33_bottom
  CLASS CORE ;
  ORIGIN 0 0 ;
  FOREIGN OAI33xp33_bottom 0 0 ;
  SIZE 0.054 BY 0.270 ;
  SYMMETRY X Y ;
  SITE asap7sc7p5t ;
  PIN A1
    DIRECTION INPUT ;
    USE SIGNAL ;
    PORT
      LAYER M1 ;
        RECT 0.072 0.07 0.09 0.236 ;
    END
  END A1
  PIN A2
    DIRECTION INPUT ;
    USE SIGNAL ;
    PORT
      LAYER M1 ;
        RECT 0.126 0.07 0.144 0.236 ;
    END
  END A2
  PIN A3
    DIRECTION INPUT ;
    USE SIGNAL ;
    PORT
      LAYER M1 ;
        RECT 0.18 0.07 0.198 0.2 ;
    END
  END A3
  PIN B1
    DIRECTION INPUT ;
    USE SIGNAL ;
    PORT
      LAYER M1 ;
        RECT 0.234 0.106 0.252 0.2 ;
    END
  END B1
  PIN B2
    DIRECTION INPUT ;
    USE SIGNAL ;
    PORT
      LAYER M1 ;
        RECT 0.288 0.106 0.306 0.2 ;
    END
  END B2
  PIN B3
    DIRECTION INPUT ;
    USE SIGNAL ;
    PORT
      LAYER M1 ;
        RECT 0.342 0.106 0.36 0.2 ;
    END
  END B3
  PIN VDD
    DIRECTION INOUT ;
    USE POWER ;
    SHAPE ABUTMENT ;
    PORT
      LAYER M1 ;
        RECT 0 0.261 0.432 0.279 ;
    END
  END VDD
  PIN VSS
    DIRECTION INOUT ;
    USE GROUND ;
    SHAPE ABUTMENT ;
    PORT
      LAYER M1 ;
        RECT 0 -0.009 0.432 0.009 ;
    END
  END VSS
  PIN Y
    DIRECTION OUTPUT ;
    USE SIGNAL ;
    PORT
      LAYER M1 ;
        RECT 0.201 0.225 0.414 0.243 ;
        RECT 0.396 0.063 0.414 0.243 ;
        RECT 0.256 0.063 0.414 0.081 ;
    END
  END Y
  OBS
    LAYER M1 ;
      RECT 0 0 0 0 ;
  END
END OAI33xp33_bottom

MACRO OR2x2_bottom
  CLASS CORE ;
  ORIGIN 0 0 ;
  FOREIGN OR2x2_bottom 0 0 ;
  SIZE 0.054 BY 0.270 ;
  SYMMETRY X Y ;
  SITE asap7sc7p5t ;
  PIN A
    DIRECTION INPUT ;
    USE SIGNAL ;
    PORT
      LAYER M1 ;
        RECT 0.107 0.189 0.144 0.207 ;
        RECT 0.126 0.063 0.144 0.207 ;
        RECT 0.107 0.063 0.144 0.081 ;
    END
  END A
  PIN B
    DIRECTION INPUT ;
    USE SIGNAL ;
    PORT
      LAYER M1 ;
        RECT 0.018 0.126 0.077 0.144 ;
        RECT 0.018 0.027 0.055 0.045 ;
        RECT 0.018 0.027 0.036 0.2 ;
    END
  END B
  PIN VDD
    DIRECTION INOUT ;
    USE POWER ;
    SHAPE ABUTMENT ;
    PORT
      LAYER M1 ;
        RECT 0 0.261 0.324 0.279 ;
    END
  END VDD
  PIN VSS
    DIRECTION INOUT ;
    USE GROUND ;
    SHAPE ABUTMENT ;
    PORT
      LAYER M1 ;
        RECT 0 -0.009 0.324 0.009 ;
    END
  END VSS
  PIN Y
    DIRECTION OUTPUT ;
    USE SIGNAL ;
    PORT
      LAYER M1 ;
        RECT 0.207 0.225 0.306 0.243 ;
        RECT 0.288 0.027 0.306 0.243 ;
        RECT 0.207 0.027 0.306 0.045 ;
        RECT 0.207 0.184 0.225 0.243 ;
        RECT 0.207 0.027 0.225 0.086 ;
    END
  END Y
  OBS
    LAYER M1 ;
      RECT 0 0 0 0 ;
  END
END OR2x2_bottom

MACRO OR2x4_bottom
  CLASS CORE ;
  ORIGIN 0 0 ;
  FOREIGN OR2x4_bottom 0 0 ;
  SIZE 0.054 BY 0.270 ;
  SYMMETRY X Y ;
  SITE asap7sc7p5t ;
  PIN A
    DIRECTION INPUT ;
    USE SIGNAL ;
    PORT
      LAYER M1 ;
        RECT 0.107 0.189 0.144 0.207 ;
        RECT 0.126 0.063 0.144 0.207 ;
        RECT 0.107 0.063 0.144 0.081 ;
    END
  END A
  PIN B
    DIRECTION INPUT ;
    USE SIGNAL ;
    PORT
      LAYER M1 ;
        RECT 0.018 0.126 0.077 0.144 ;
        RECT 0.018 0.027 0.055 0.045 ;
        RECT 0.018 0.027 0.036 0.2 ;
    END
  END B
  PIN VDD
    DIRECTION INOUT ;
    USE POWER ;
    SHAPE ABUTMENT ;
    PORT
      LAYER M1 ;
        RECT 0 0.261 0.432 0.279 ;
    END
  END VDD
  PIN VSS
    DIRECTION INOUT ;
    USE GROUND ;
    SHAPE ABUTMENT ;
    PORT
      LAYER M1 ;
        RECT 0 -0.009 0.432 0.009 ;
    END
  END VSS
  PIN Y
    DIRECTION OUTPUT ;
    USE SIGNAL ;
    PORT
      LAYER M1 ;
        RECT 0.207 0.225 0.414 0.243 ;
        RECT 0.396 0.027 0.414 0.243 ;
        RECT 0.207 0.027 0.414 0.045 ;
        RECT 0.315 0.184 0.333 0.243 ;
        RECT 0.315 0.027 0.333 0.086 ;
        RECT 0.207 0.184 0.225 0.243 ;
        RECT 0.207 0.027 0.225 0.086 ;
    END
  END Y
  OBS
    LAYER M1 ;
      RECT 0 0 0 0 ;
  END
END OR2x4_bottom

MACRO OR2x6_bottom
  CLASS CORE ;
  ORIGIN 0 0 ;
  FOREIGN OR2x6_bottom 0 0 ;
  SIZE 0.054 BY 0.270 ;
  SYMMETRY X Y ;
  SITE asap7sc7p5t ;
  PIN A
    DIRECTION INPUT ;
    USE SIGNAL ;
    PORT
      LAYER M1 ;
        RECT 0.126 0.063 0.144 0.122 ;
        RECT 0.018 0.063 0.144 0.081 ;
        RECT 0.018 0.063 0.036 0.236 ;
    END
  END A
  PIN B
    DIRECTION INPUT ;
    USE SIGNAL ;
    PORT
      LAYER M1 ;
        RECT 0.072 0.153 0.252 0.171 ;
        RECT 0.234 0.121 0.252 0.171 ;
        RECT 0.072 0.106 0.09 0.236 ;
    END
  END B
  PIN VDD
    DIRECTION INOUT ;
    USE POWER ;
    SHAPE ABUTMENT ;
    PORT
      LAYER M1 ;
        RECT 0 0.261 0.648 0.279 ;
    END
  END VDD
  PIN VSS
    DIRECTION INOUT ;
    USE GROUND ;
    SHAPE ABUTMENT ;
    PORT
      LAYER M1 ;
        RECT 0 -0.009 0.648 0.009 ;
    END
  END VSS
  PIN Y
    DIRECTION OUTPUT ;
    USE SIGNAL ;
    PORT
      LAYER M1 ;
        RECT 0.288 0.225 0.63 0.243 ;
        RECT 0.612 0.027 0.63 0.243 ;
        RECT 0.31 0.027 0.63 0.045 ;
    END
  END Y
  OBS
    LAYER M1 ;
      RECT 0 0 0 0 ;
  END
END OR2x6_bottom

MACRO OR3x1_bottom
  CLASS CORE ;
  ORIGIN 0 0 ;
  FOREIGN OR3x1_bottom 0 0 ;
  SIZE 0.054 BY 0.270 ;
  SYMMETRY X Y ;
  SITE asap7sc7p5t ;
  PIN A
    DIRECTION INPUT ;
    USE SIGNAL ;
    PORT
      LAYER M1 ;
        RECT 0.072 0.07 0.09 0.2 ;
    END
  END A
  PIN B
    DIRECTION INPUT ;
    USE SIGNAL ;
    PORT
      LAYER M1 ;
        RECT 0.126 0.07 0.144 0.2 ;
    END
  END B
  PIN C
    DIRECTION INPUT ;
    USE SIGNAL ;
    PORT
      LAYER M1 ;
        RECT 0.18 0.07 0.198 0.2 ;
    END
  END C
  PIN VDD
    DIRECTION INOUT ;
    USE POWER ;
    SHAPE ABUTMENT ;
    PORT
      LAYER M1 ;
        RECT 0 0.261 0.324 0.279 ;
    END
  END VDD
  PIN VSS
    DIRECTION INOUT ;
    USE GROUND ;
    SHAPE ABUTMENT ;
    PORT
      LAYER M1 ;
        RECT 0 -0.009 0.324 0.009 ;
    END
  END VSS
  PIN Y
    DIRECTION OUTPUT ;
    USE SIGNAL ;
    PORT
      LAYER M1 ;
        RECT 0.261 0.183 0.306 0.201 ;
        RECT 0.288 0.076 0.306 0.201 ;
        RECT 0.261 0.076 0.306 0.094 ;
        RECT 0.261 0.183 0.279 0.235 ;
        RECT 0.261 0.034 0.279 0.094 ;
    END
  END Y
  OBS
    LAYER M1 ;
      RECT 0 0 0 0 ;
  END
END OR3x1_bottom

MACRO OR3x2_bottom
  CLASS CORE ;
  ORIGIN 0 0 ;
  FOREIGN OR3x2_bottom 0 0 ;
  SIZE 0.054 BY 0.270 ;
  SYMMETRY X Y ;
  SITE asap7sc7p5t ;
  PIN A
    DIRECTION INPUT ;
    USE SIGNAL ;
    PORT
      LAYER M1 ;
        RECT 0.072 0.07 0.09 0.2 ;
    END
  END A
  PIN B
    DIRECTION INPUT ;
    USE SIGNAL ;
    PORT
      LAYER M1 ;
        RECT 0.126 0.07 0.144 0.2 ;
    END
  END B
  PIN C
    DIRECTION INPUT ;
    USE SIGNAL ;
    PORT
      LAYER M1 ;
        RECT 0.18 0.07 0.198 0.2 ;
    END
  END C
  PIN VDD
    DIRECTION INOUT ;
    USE POWER ;
    SHAPE ABUTMENT ;
    PORT
      LAYER M1 ;
        RECT 0 0.261 0.378 0.279 ;
    END
  END VDD
  PIN VSS
    DIRECTION INOUT ;
    USE GROUND ;
    SHAPE ABUTMENT ;
    PORT
      LAYER M1 ;
        RECT 0 -0.009 0.378 0.009 ;
    END
  END VSS
  PIN Y
    DIRECTION OUTPUT ;
    USE SIGNAL ;
    PORT
      LAYER M1 ;
        RECT 0.261 0.225 0.36 0.243 ;
        RECT 0.342 0.027 0.36 0.243 ;
        RECT 0.261 0.027 0.36 0.045 ;
        RECT 0.261 0.184 0.279 0.243 ;
        RECT 0.261 0.027 0.279 0.086 ;
    END
  END Y
  OBS
    LAYER M1 ;
      RECT 0 0 0 0 ;
  END
END OR3x2_bottom

MACRO OR3x4_bottom
  CLASS CORE ;
  ORIGIN 0 0 ;
  FOREIGN OR3x4_bottom 0 0 ;
  SIZE 0.054 BY 0.270 ;
  SYMMETRY X Y ;
  SITE asap7sc7p5t ;
  PIN A
    DIRECTION INPUT ;
    USE SIGNAL ;
    PORT
      LAYER M1 ;
        RECT 0.072 0.07 0.09 0.2 ;
    END
  END A
  PIN B
    DIRECTION INPUT ;
    USE SIGNAL ;
    PORT
      LAYER M1 ;
        RECT 0.126 0.07 0.144 0.2 ;
    END
  END B
  PIN C
    DIRECTION INPUT ;
    USE SIGNAL ;
    PORT
      LAYER M1 ;
        RECT 0.18 0.07 0.198 0.2 ;
    END
  END C
  PIN VDD
    DIRECTION INOUT ;
    USE POWER ;
    SHAPE ABUTMENT ;
    PORT
      LAYER M1 ;
        RECT 0 0.261 0.486 0.279 ;
    END
  END VDD
  PIN VSS
    DIRECTION INOUT ;
    USE GROUND ;
    SHAPE ABUTMENT ;
    PORT
      LAYER M1 ;
        RECT 0 -0.009 0.486 0.009 ;
    END
  END VSS
  PIN Y
    DIRECTION OUTPUT ;
    USE SIGNAL ;
    PORT
      LAYER M1 ;
        RECT 0.261 0.225 0.468 0.243 ;
        RECT 0.45 0.027 0.468 0.243 ;
        RECT 0.261 0.027 0.468 0.045 ;
        RECT 0.369 0.184 0.387 0.243 ;
        RECT 0.369 0.027 0.387 0.086 ;
        RECT 0.261 0.184 0.279 0.243 ;
        RECT 0.261 0.027 0.279 0.086 ;
    END
  END Y
  OBS
    LAYER M1 ;
      RECT 0 0 0 0 ;
  END
END OR3x4_bottom

MACRO OR4x1_bottom
  CLASS CORE ;
  ORIGIN 0 0 ;
  FOREIGN OR4x1_bottom 0 0 ;
  SIZE 0.054 BY 0.270 ;
  SYMMETRY X Y ;
  SITE asap7sc7p5t ;
  PIN A
    DIRECTION INPUT ;
    USE SIGNAL ;
    PORT
      LAYER M1 ;
        RECT 0.288 0.07 0.306 0.2 ;
    END
  END A
  PIN B
    DIRECTION INPUT ;
    USE SIGNAL ;
    PORT
      LAYER M1 ;
        RECT 0.234 0.07 0.252 0.236 ;
    END
  END B
  PIN C
    DIRECTION INPUT ;
    USE SIGNAL ;
    PORT
      LAYER M1 ;
        RECT 0.18 0.07 0.198 0.236 ;
    END
  END C
  PIN D
    DIRECTION INPUT ;
    USE SIGNAL ;
    PORT
      LAYER M1 ;
        RECT 0.126 0.106 0.144 0.236 ;
    END
  END D
  PIN VDD
    DIRECTION INOUT ;
    USE POWER ;
    SHAPE ABUTMENT ;
    PORT
      LAYER M1 ;
        RECT 0 0.261 0.378 0.279 ;
    END
  END VDD
  PIN VSS
    DIRECTION INOUT ;
    USE GROUND ;
    SHAPE ABUTMENT ;
    PORT
      LAYER M1 ;
        RECT 0 -0.009 0.378 0.009 ;
    END
  END VSS
  PIN Y
    DIRECTION OUTPUT ;
    USE SIGNAL ;
    PORT
      LAYER M1 ;
        RECT 0.018 0.225 0.068 0.243 ;
        RECT 0.018 0.027 0.068 0.045 ;
        RECT 0.018 0.027 0.036 0.243 ;
    END
  END Y
  OBS
    LAYER M1 ;
      RECT 0 0 0 0 ;
  END
END OR4x1_bottom

MACRO OR4x2_bottom
  CLASS CORE ;
  ORIGIN 0 0 ;
  FOREIGN OR4x2_bottom 0 0 ;
  SIZE 0.054 BY 0.270 ;
  SYMMETRY X Y ;
  SITE asap7sc7p5t ;
  PIN A
    DIRECTION INPUT ;
    USE SIGNAL ;
    PORT
      LAYER M1 ;
        RECT 0.342 0.07 0.36 0.2 ;
    END
  END A
  PIN B
    DIRECTION INPUT ;
    USE SIGNAL ;
    PORT
      LAYER M1 ;
        RECT 0.288 0.07 0.306 0.236 ;
    END
  END B
  PIN C
    DIRECTION INPUT ;
    USE SIGNAL ;
    PORT
      LAYER M1 ;
        RECT 0.234 0.07 0.252 0.236 ;
    END
  END C
  PIN D
    DIRECTION INPUT ;
    USE SIGNAL ;
    PORT
      LAYER M1 ;
        RECT 0.18 0.106 0.198 0.236 ;
    END
  END D
  PIN VDD
    DIRECTION INOUT ;
    USE POWER ;
    SHAPE ABUTMENT ;
    PORT
      LAYER M1 ;
        RECT 0 0.261 0.432 0.279 ;
    END
  END VDD
  PIN VSS
    DIRECTION INOUT ;
    USE GROUND ;
    SHAPE ABUTMENT ;
    PORT
      LAYER M1 ;
        RECT 0 -0.009 0.432 0.009 ;
    END
  END VSS
  PIN Y
    DIRECTION OUTPUT ;
    USE SIGNAL ;
    PORT
      LAYER M1 ;
        RECT 0.018 0.225 0.122 0.243 ;
        RECT 0.018 0.027 0.122 0.045 ;
        RECT 0.018 0.027 0.036 0.243 ;
    END
  END Y
  OBS
    LAYER M1 ;
      RECT 0 0 0 0 ;
  END
END OR4x2_bottom

MACRO OR5x1_bottom
  CLASS CORE ;
  ORIGIN 0 0 ;
  FOREIGN OR5x1_bottom 0 0 ;
  SIZE 0.054 BY 0.270 ;
  SYMMETRY X Y ;
  SITE asap7sc7p5t ;
  PIN A
    DIRECTION INPUT ;
    USE SIGNAL ;
    PORT
      LAYER M1 ;
        RECT 0.072 0.07 0.09 0.2 ;
    END
  END A
  PIN B
    DIRECTION INPUT ;
    USE SIGNAL ;
    PORT
      LAYER M1 ;
        RECT 0.126 0.07 0.144 0.236 ;
    END
  END B
  PIN C
    DIRECTION INPUT ;
    USE SIGNAL ;
    PORT
      LAYER M1 ;
        RECT 0.18 0.07 0.198 0.236 ;
    END
  END C
  PIN D
    DIRECTION INPUT ;
    USE SIGNAL ;
    PORT
      LAYER M1 ;
        RECT 0.234 0.07 0.252 0.236 ;
    END
  END D
  PIN E
    DIRECTION INPUT ;
    USE SIGNAL ;
    PORT
      LAYER M1 ;
        RECT 0.288 0.106 0.306 0.236 ;
    END
  END E
  PIN VDD
    DIRECTION INOUT ;
    USE POWER ;
    SHAPE ABUTMENT ;
    PORT
      LAYER M1 ;
        RECT 0 0.261 0.432 0.279 ;
    END
  END VDD
  PIN VSS
    DIRECTION INOUT ;
    USE GROUND ;
    SHAPE ABUTMENT ;
    PORT
      LAYER M1 ;
        RECT 0 -0.009 0.432 0.009 ;
    END
  END VSS
  PIN Y
    DIRECTION OUTPUT ;
    USE SIGNAL ;
    PORT
      LAYER M1 ;
        RECT 0.35 0.225 0.414 0.243 ;
        RECT 0.396 0.027 0.414 0.243 ;
        RECT 0.349 0.027 0.414 0.045 ;
    END
  END Y
  OBS
    LAYER M1 ;
      RECT 0 0 0 0 ;
  END
END OR5x1_bottom

MACRO OR5x2_bottom
  CLASS CORE ;
  ORIGIN 0 0 ;
  FOREIGN OR5x2_bottom 0 0 ;
  SIZE 0.054 BY 0.270 ;
  SYMMETRY X Y ;
  SITE asap7sc7p5t ;
  PIN A
    DIRECTION INPUT ;
    USE SIGNAL ;
    PORT
      LAYER M1 ;
        RECT 0.072 0.07 0.09 0.2 ;
    END
  END A
  PIN B
    DIRECTION INPUT ;
    USE SIGNAL ;
    PORT
      LAYER M1 ;
        RECT 0.126 0.07 0.144 0.236 ;
    END
  END B
  PIN C
    DIRECTION INPUT ;
    USE SIGNAL ;
    PORT
      LAYER M1 ;
        RECT 0.18 0.07 0.198 0.236 ;
    END
  END C
  PIN D
    DIRECTION INPUT ;
    USE SIGNAL ;
    PORT
      LAYER M1 ;
        RECT 0.234 0.07 0.252 0.236 ;
    END
  END D
  PIN E
    DIRECTION INPUT ;
    USE SIGNAL ;
    PORT
      LAYER M1 ;
        RECT 0.288 0.106 0.306 0.236 ;
    END
  END E
  PIN VDD
    DIRECTION INOUT ;
    USE POWER ;
    SHAPE ABUTMENT ;
    PORT
      LAYER M1 ;
        RECT 0 0.261 0.486 0.279 ;
    END
  END VDD
  PIN VSS
    DIRECTION INOUT ;
    USE GROUND ;
    SHAPE ABUTMENT ;
    PORT
      LAYER M1 ;
        RECT 0 -0.009 0.486 0.009 ;
    END
  END VSS
  PIN Y
    DIRECTION OUTPUT ;
    USE SIGNAL ;
    PORT
      LAYER M1 ;
        RECT 0.364 0.225 0.468 0.243 ;
        RECT 0.45 0.027 0.468 0.243 ;
        RECT 0.343 0.027 0.468 0.045 ;
    END
  END Y
  OBS
    LAYER M1 ;
      RECT 0 0 0 0 ;
  END
END OR5x2_bottom

MACRO SDFHx1_bottom
  CLASS CORE ;
  ORIGIN 0 0 ;
  FOREIGN SDFHx1_bottom 0 0 ;
  SIZE 0.054 BY 0.270 ;
  SYMMETRY X Y ;
  SITE asap7sc7p5t ;
  PIN CLK
    DIRECTION INPUT ;
    USE CLOCK ;
    PORT
      LAYER M1 ;
        RECT 0.099 0.185 0.117 0.236 ;
        RECT 0.072 0.081 0.117 0.099 ;
        RECT 0.099 0.034 0.117 0.099 ;
        RECT 0.072 0.185 0.117 0.203 ;
        RECT 0.072 0.081 0.09 0.203 ;
    END
  END CLK
  PIN QN
    DIRECTION OUTPUT ;
    USE SIGNAL ;
    PORT
      LAYER M1 ;
        RECT 1.282 0.225 1.332 0.243 ;
        RECT 1.314 0.027 1.332 0.243 ;
        RECT 1.282 0.027 1.332 0.045 ;
    END
  END QN
  PIN VDD
    DIRECTION INOUT ;
    USE POWER ;
    SHAPE ABUTMENT ;
    PORT
      LAYER M1 ;
        RECT 0 0.261 1.35 0.279 ;
    END
  END VDD
  PIN VSS
    DIRECTION INOUT ;
    USE GROUND ;
    SHAPE ABUTMENT ;
    PORT
      LAYER M1 ;
        RECT 0 -0.009 1.35 0.009 ;
    END
  END VSS
  PIN D
    DIRECTION INPUT ;
    USE SIGNAL ;
    PORT
      LAYER M2 ;
        RECT 0.284 0.108 0.436 0.126 ;
      LAYER M1 ;
        RECT 0.396 0.106 0.414 0.164 ;
      LAYER V1 ;
        RECT 0.396 0.108 0.414 0.126 ;
    END
  END D
  PIN SE
    DIRECTION INPUT ;
    USE SIGNAL ;
    PORT
      LAYER M2 ;
        RECT 0.211 0.036 1.229 0.054 ;
      LAYER M1 ;
        RECT 1.206 0.027 1.25 0.045 ;
        RECT 1.206 0.027 1.224 0.2 ;
        RECT 0.216 0.126 0.311 0.144 ;
        RECT 0.216 0.027 0.258 0.045 ;
        RECT 0.216 0.027 0.234 0.144 ;
      LAYER V1 ;
        RECT 0.216 0.036 0.234 0.054 ;
        RECT 1.206 0.036 1.224 0.054 ;
    END
  END SE
  PIN SI
    DIRECTION INPUT ;
    USE SIGNAL ;
    PORT
      LAYER M2 ;
        RECT 0.467 0.108 0.59 0.126 ;
      LAYER M1 ;
        RECT 0.485 0.189 0.522 0.207 ;
        RECT 0.504 0.106 0.522 0.207 ;
        RECT 0.461 0.126 0.522 0.144 ;
      LAYER V1 ;
        RECT 0.504 0.108 0.522 0.126 ;
    END
  END SI
  OBS
    LAYER M1 ;
      RECT 0 0 0 0 ;
  END
END SDFHx1_bottom

MACRO SDFHx2_bottom
  CLASS CORE ;
  ORIGIN 0 0 ;
  FOREIGN SDFHx2_bottom 0 0 ;
  SIZE 0.054 BY 0.270 ;
  SYMMETRY X Y ;
  SITE asap7sc7p5t ;
  PIN CLK
    DIRECTION INPUT ;
    USE CLOCK ;
    PORT
      LAYER M1 ;
        RECT 0.072 0.081 0.117 0.099 ;
        RECT 0.099 0.034 0.117 0.099 ;
        RECT 0.072 0.081 0.09 0.2 ;
    END
  END CLK
  PIN D
    DIRECTION INPUT ;
    USE SIGNAL ;
    PORT
      LAYER M1 ;
        RECT 0.396 0.099 0.433 0.117 ;
        RECT 0.396 0.099 0.414 0.164 ;
    END
  END D
  PIN QN
    DIRECTION OUTPUT ;
    USE SIGNAL ;
    PORT
      LAYER M1 ;
        RECT 1.282 0.225 1.386 0.243 ;
        RECT 1.368 0.027 1.386 0.243 ;
        RECT 1.282 0.027 1.386 0.045 ;
    END
  END QN
  PIN SE
    DIRECTION INPUT ;
    USE SIGNAL ;
    PORT
      LAYER M2 ;
        RECT 0.211 0.036 1.229 0.054 ;
      LAYER M1 ;
        RECT 1.206 0.027 1.25 0.045 ;
        RECT 1.206 0.027 1.224 0.2 ;
        RECT 0.216 0.126 0.311 0.144 ;
        RECT 0.216 0.027 0.258 0.045 ;
        RECT 0.216 0.027 0.234 0.144 ;
      LAYER V1 ;
        RECT 0.216 0.036 0.234 0.054 ;
        RECT 1.206 0.036 1.224 0.054 ;
    END
  END SE
  PIN SI
    DIRECTION INPUT ;
    USE SIGNAL ;
    PORT
      LAYER M1 ;
        RECT 0.485 0.189 0.522 0.207 ;
        RECT 0.504 0.106 0.522 0.207 ;
        RECT 0.461 0.126 0.522 0.144 ;
    END
  END SI
  PIN VDD
    DIRECTION INOUT ;
    USE POWER ;
    SHAPE ABUTMENT ;
    PORT
      LAYER M1 ;
        RECT 0 0.261 1.404 0.279 ;
    END
  END VDD
  PIN VSS
    DIRECTION INOUT ;
    USE GROUND ;
    SHAPE ABUTMENT ;
    PORT
      LAYER M1 ;
        RECT 0 -0.009 1.404 0.009 ;
    END
  END VSS
  OBS
    LAYER M1 ;
      RECT 0 0 0 0 ;
  END
END SDFHx2_bottom

MACRO SDFHx3_bottom
  CLASS CORE ;
  ORIGIN 0 0 ;
  FOREIGN SDFHx3_bottom 0 0 ;
  SIZE 0.054 BY 0.270 ;
  SYMMETRY X Y ;
  SITE asap7sc7p5t ;
  PIN CLK
    DIRECTION INPUT ;
    USE CLOCK ;
    PORT
      LAYER M1 ;
        RECT 0.072 0.081 0.117 0.099 ;
        RECT 0.099 0.034 0.117 0.099 ;
        RECT 0.072 0.081 0.09 0.2 ;
    END
  END CLK
  PIN D
    DIRECTION INPUT ;
    USE SIGNAL ;
    PORT
      LAYER M1 ;
        RECT 0.396 0.099 0.433 0.117 ;
        RECT 0.396 0.099 0.414 0.164 ;
    END
  END D
  PIN QN
    DIRECTION OUTPUT ;
    USE SIGNAL ;
    PORT
      LAYER M1 ;
        RECT 1.282 0.225 1.44 0.243 ;
        RECT 1.422 0.027 1.44 0.243 ;
        RECT 1.282 0.027 1.44 0.045 ;
    END
  END QN
  PIN SE
    DIRECTION INPUT ;
    USE SIGNAL ;
    PORT
      LAYER M2 ;
        RECT 0.211 0.036 1.229 0.054 ;
      LAYER M1 ;
        RECT 1.206 0.027 1.25 0.045 ;
        RECT 1.206 0.027 1.224 0.2 ;
        RECT 0.216 0.126 0.311 0.144 ;
        RECT 0.216 0.027 0.258 0.045 ;
        RECT 0.216 0.027 0.234 0.144 ;
      LAYER V1 ;
        RECT 0.216 0.036 0.234 0.054 ;
        RECT 1.206 0.036 1.224 0.054 ;
    END
  END SE
  PIN SI
    DIRECTION INPUT ;
    USE SIGNAL ;
    PORT
      LAYER M1 ;
        RECT 0.485 0.189 0.522 0.207 ;
        RECT 0.504 0.106 0.522 0.207 ;
        RECT 0.461 0.126 0.522 0.144 ;
    END
  END SI
  PIN VDD
    DIRECTION INOUT ;
    USE POWER ;
    SHAPE ABUTMENT ;
    PORT
      LAYER M1 ;
        RECT 0 0.261 1.458 0.279 ;
    END
  END VDD
  PIN VSS
    DIRECTION INOUT ;
    USE GROUND ;
    SHAPE ABUTMENT ;
    PORT
      LAYER M1 ;
        RECT 0 -0.009 1.458 0.009 ;
    END
  END VSS
  OBS
    LAYER M1 ;
      RECT 0 0 0 0 ;
  END
END SDFHx3_bottom

MACRO SDFHx4_bottom
  CLASS CORE ;
  ORIGIN 0 0 ;
  FOREIGN SDFHx4_bottom 0 0 ;
  SIZE 0.054 BY 0.270 ;
  SYMMETRY X Y ;
  SITE asap7sc7p5t ;
  PIN CLK
    DIRECTION INPUT ;
    USE CLOCK ;
    PORT
      LAYER M1 ;
        RECT 0.072 0.063 0.109 0.081 ;
        RECT 0.072 0.063 0.09 0.2 ;
    END
  END CLK
  PIN D
    DIRECTION INPUT ;
    USE SIGNAL ;
    PORT
      LAYER M1 ;
        RECT 0.45 0.099 0.468 0.164 ;
        RECT 0.378 0.225 0.459 0.243 ;
        RECT 0.378 0.099 0.468 0.117 ;
        RECT 0.378 0.099 0.396 0.243 ;
    END
  END D
  PIN QN
    DIRECTION OUTPUT ;
    USE SIGNAL ;
    PORT
      LAYER M1 ;
        RECT 1.444 0.225 1.656 0.243 ;
        RECT 1.637 0.027 1.656 0.243 ;
        RECT 1.444 0.027 1.656 0.045 ;
    END
  END QN
  PIN SE
    DIRECTION INPUT ;
    USE SIGNAL ;
    PORT
      LAYER M2 ;
        RECT 0.229 0.072 0.581 0.09 ;
      LAYER M1 ;
        RECT 0.558 0.063 0.599 0.081 ;
        RECT 0.558 0.063 0.576 0.164 ;
        RECT 0.234 0.126 0.289 0.144 ;
        RECT 0.234 0.225 0.271 0.243 ;
        RECT 0.234 0.027 0.271 0.045 ;
        RECT 0.234 0.027 0.252 0.243 ;
      LAYER V1 ;
        RECT 0.234 0.072 0.252 0.09 ;
        RECT 0.558 0.072 0.576 0.09 ;
    END
  END SE
  PIN SI
    DIRECTION INPUT ;
    USE SIGNAL ;
    PORT
      LAYER M1 ;
        RECT 0.693 0.027 0.767 0.045 ;
        RECT 0.639 0.063 0.711 0.081 ;
        RECT 0.693 0.027 0.711 0.081 ;
        RECT 0.612 0.106 0.657 0.124 ;
        RECT 0.639 0.063 0.657 0.124 ;
        RECT 0.612 0.106 0.63 0.164 ;
    END
  END SI
  PIN VDD
    DIRECTION INOUT ;
    USE POWER ;
    SHAPE ABUTMENT ;
    PORT
      LAYER M1 ;
        RECT 0 0.261 1.674 0.279 ;
    END
  END VDD
  PIN VSS
    DIRECTION INOUT ;
    USE GROUND ;
    SHAPE ABUTMENT ;
    PORT
      LAYER M1 ;
        RECT 0 -0.009 1.674 0.009 ;
    END
  END VSS
  OBS
    LAYER M1 ;
      RECT 0 0 0 0 ;
  END
END SDFHx4_bottom

MACRO SDFLx1_bottom
  CLASS CORE ;
  ORIGIN 0 0 ;
  FOREIGN SDFLx1_bottom 0 0 ;
  SIZE 0.054 BY 0.270 ;
  SYMMETRY X Y ;
  SITE asap7sc7p5t ;
  PIN CLK
    DIRECTION INPUT ;
    USE CLOCK ;
    PORT
      LAYER M1 ;
        RECT 0.072 0.081 0.117 0.099 ;
        RECT 0.099 0.034 0.117 0.099 ;
        RECT 0.072 0.081 0.09 0.164 ;
    END
  END CLK
  PIN D
    DIRECTION INPUT ;
    USE SIGNAL ;
    PORT
      LAYER M1 ;
        RECT 0.396 0.099 0.433 0.117 ;
        RECT 0.396 0.099 0.414 0.164 ;
    END
  END D
  PIN QN
    DIRECTION OUTPUT ;
    USE SIGNAL ;
    PORT
      LAYER M1 ;
        RECT 1.282 0.225 1.332 0.243 ;
        RECT 1.314 0.027 1.332 0.243 ;
        RECT 1.282 0.027 1.332 0.045 ;
    END
  END QN
  PIN SE
    DIRECTION INPUT ;
    USE SIGNAL ;
    PORT
      LAYER M2 ;
        RECT 0.211 0.036 1.229 0.054 ;
      LAYER M1 ;
        RECT 1.206 0.027 1.25 0.045 ;
        RECT 1.206 0.027 1.224 0.2 ;
        RECT 0.216 0.126 0.311 0.144 ;
        RECT 0.216 0.027 0.258 0.045 ;
        RECT 0.216 0.027 0.234 0.144 ;
      LAYER V1 ;
        RECT 0.216 0.036 0.234 0.054 ;
        RECT 1.206 0.036 1.224 0.054 ;
    END
  END SE
  PIN SI
    DIRECTION INPUT ;
    USE SIGNAL ;
    PORT
      LAYER M1 ;
        RECT 0.485 0.189 0.522 0.207 ;
        RECT 0.504 0.106 0.522 0.207 ;
        RECT 0.461 0.126 0.522 0.144 ;
    END
  END SI
  PIN VDD
    DIRECTION INOUT ;
    USE POWER ;
    SHAPE ABUTMENT ;
    PORT
      LAYER M1 ;
        RECT 0 0.261 1.35 0.279 ;
    END
  END VDD
  PIN VSS
    DIRECTION INOUT ;
    USE GROUND ;
    SHAPE ABUTMENT ;
    PORT
      LAYER M1 ;
        RECT 0 -0.009 1.35 0.009 ;
    END
  END VSS
  OBS
    LAYER M1 ;
      RECT 0 0 0 0 ;
  END
END SDFLx1_bottom

MACRO SDFLx2_bottom
  CLASS CORE ;
  ORIGIN 0 0 ;
  FOREIGN SDFLx2_bottom 0 0 ;
  SIZE 0.054 BY 0.270 ;
  SYMMETRY X Y ;
  SITE asap7sc7p5t ;
  PIN CLK
    DIRECTION INPUT ;
    USE CLOCK ;
    PORT
      LAYER M1 ;
        RECT 0.072 0.081 0.117 0.099 ;
        RECT 0.099 0.034 0.117 0.099 ;
        RECT 0.072 0.081 0.09 0.164 ;
    END
  END CLK
  PIN D
    DIRECTION INPUT ;
    USE SIGNAL ;
    PORT
      LAYER M1 ;
        RECT 0.396 0.099 0.433 0.117 ;
        RECT 0.396 0.099 0.414 0.164 ;
    END
  END D
  PIN QN
    DIRECTION OUTPUT ;
    USE SIGNAL ;
    PORT
      LAYER M1 ;
        RECT 1.282 0.225 1.386 0.243 ;
        RECT 1.368 0.027 1.386 0.243 ;
        RECT 1.282 0.027 1.386 0.045 ;
    END
  END QN
  PIN SE
    DIRECTION INPUT ;
    USE SIGNAL ;
    PORT
      LAYER M2 ;
        RECT 0.211 0.036 1.229 0.054 ;
      LAYER M1 ;
        RECT 1.206 0.027 1.25 0.045 ;
        RECT 1.206 0.027 1.224 0.2 ;
        RECT 0.216 0.126 0.311 0.144 ;
        RECT 0.216 0.027 0.258 0.045 ;
        RECT 0.216 0.027 0.234 0.144 ;
      LAYER V1 ;
        RECT 0.216 0.036 0.234 0.054 ;
        RECT 1.206 0.036 1.224 0.054 ;
    END
  END SE
  PIN SI
    DIRECTION INPUT ;
    USE SIGNAL ;
    PORT
      LAYER M1 ;
        RECT 0.485 0.189 0.522 0.207 ;
        RECT 0.504 0.106 0.522 0.207 ;
        RECT 0.461 0.126 0.522 0.144 ;
    END
  END SI
  PIN VDD
    DIRECTION INOUT ;
    USE POWER ;
    SHAPE ABUTMENT ;
    PORT
      LAYER M1 ;
        RECT 0 0.261 1.404 0.279 ;
    END
  END VDD
  PIN VSS
    DIRECTION INOUT ;
    USE GROUND ;
    SHAPE ABUTMENT ;
    PORT
      LAYER M1 ;
        RECT 0 -0.009 1.404 0.009 ;
    END
  END VSS
  OBS
    LAYER M1 ;
      RECT 0 0 0 0 ;
  END
END SDFLx2_bottom

MACRO SDFLx3_bottom
  CLASS CORE ;
  ORIGIN 0 0 ;
  FOREIGN SDFLx3_bottom 0 0 ;
  SIZE 0.054 BY 0.270 ;
  SYMMETRY X Y ;
  SITE asap7sc7p5t ;
  PIN CLK
    DIRECTION INPUT ;
    USE CLOCK ;
    PORT
      LAYER M1 ;
        RECT 0.072 0.081 0.117 0.099 ;
        RECT 0.099 0.034 0.117 0.099 ;
        RECT 0.072 0.081 0.09 0.164 ;
    END
  END CLK
  PIN D
    DIRECTION INPUT ;
    USE SIGNAL ;
    PORT
      LAYER M1 ;
        RECT 0.396 0.099 0.433 0.117 ;
        RECT 0.396 0.099 0.414 0.164 ;
    END
  END D
  PIN QN
    DIRECTION OUTPUT ;
    USE SIGNAL ;
    PORT
      LAYER M1 ;
        RECT 1.282 0.225 1.44 0.243 ;
        RECT 1.422 0.027 1.44 0.243 ;
        RECT 1.282 0.027 1.44 0.045 ;
    END
  END QN
  PIN SE
    DIRECTION INPUT ;
    USE SIGNAL ;
    PORT
      LAYER M2 ;
        RECT 0.211 0.036 1.229 0.054 ;
      LAYER M1 ;
        RECT 1.206 0.027 1.25 0.045 ;
        RECT 1.206 0.027 1.224 0.2 ;
        RECT 0.216 0.126 0.311 0.144 ;
        RECT 0.216 0.027 0.258 0.045 ;
        RECT 0.216 0.027 0.234 0.144 ;
      LAYER V1 ;
        RECT 0.216 0.036 0.234 0.054 ;
        RECT 1.206 0.036 1.224 0.054 ;
    END
  END SE
  PIN SI
    DIRECTION INPUT ;
    USE SIGNAL ;
    PORT
      LAYER M1 ;
        RECT 0.485 0.189 0.522 0.207 ;
        RECT 0.504 0.106 0.522 0.207 ;
        RECT 0.461 0.126 0.522 0.144 ;
    END
  END SI
  PIN VDD
    DIRECTION INOUT ;
    USE POWER ;
    SHAPE ABUTMENT ;
    PORT
      LAYER M1 ;
        RECT 0 0.261 1.458 0.279 ;
    END
  END VDD
  PIN VSS
    DIRECTION INOUT ;
    USE GROUND ;
    SHAPE ABUTMENT ;
    PORT
      LAYER M1 ;
        RECT 0 -0.009 1.458 0.009 ;
    END
  END VSS
  OBS
    LAYER M1 ;
      RECT 0 0 0 0 ;
  END
END SDFLx3_bottom

MACRO SDFLx4_bottom
  CLASS CORE ;
  ORIGIN 0 0 ;
  FOREIGN SDFLx4_bottom 0 0 ;
  SIZE 0.054 BY 0.270 ;
  SYMMETRY X Y ;
  SITE asap7sc7p5t ;
  PIN CLK
    DIRECTION INPUT ;
    USE CLOCK ;
    PORT
      LAYER M1 ;
        RECT 0.072 0.063 0.109 0.081 ;
        RECT 0.072 0.063 0.09 0.2 ;
    END
  END CLK
  PIN D
    DIRECTION INPUT ;
    USE SIGNAL ;
    PORT
      LAYER M1 ;
        RECT 0.45 0.099 0.468 0.164 ;
        RECT 0.378 0.225 0.459 0.243 ;
        RECT 0.378 0.099 0.468 0.117 ;
        RECT 0.378 0.099 0.396 0.243 ;
    END
  END D
  PIN QN
    DIRECTION OUTPUT ;
    USE SIGNAL ;
    PORT
      LAYER M1 ;
        RECT 1.444 0.225 1.656 0.243 ;
        RECT 1.637 0.027 1.656 0.243 ;
        RECT 1.444 0.027 1.656 0.045 ;
    END
  END QN
  PIN SE
    DIRECTION INPUT ;
    USE SIGNAL ;
    PORT
      LAYER M2 ;
        RECT 0.229 0.072 0.581 0.09 ;
      LAYER M1 ;
        RECT 0.558 0.063 0.599 0.081 ;
        RECT 0.558 0.063 0.576 0.164 ;
        RECT 0.234 0.126 0.289 0.144 ;
        RECT 0.234 0.225 0.271 0.243 ;
        RECT 0.234 0.027 0.271 0.045 ;
        RECT 0.234 0.027 0.252 0.243 ;
      LAYER V1 ;
        RECT 0.234 0.072 0.252 0.09 ;
        RECT 0.558 0.072 0.576 0.09 ;
    END
  END SE
  PIN SI
    DIRECTION INPUT ;
    USE SIGNAL ;
    PORT
      LAYER M1 ;
        RECT 0.693 0.027 0.767 0.045 ;
        RECT 0.639 0.063 0.711 0.081 ;
        RECT 0.693 0.027 0.711 0.081 ;
        RECT 0.612 0.106 0.657 0.124 ;
        RECT 0.639 0.063 0.657 0.124 ;
        RECT 0.612 0.106 0.63 0.164 ;
    END
  END SI
  PIN VDD
    DIRECTION INOUT ;
    USE POWER ;
    SHAPE ABUTMENT ;
    PORT
      LAYER M1 ;
        RECT 0 0.261 1.674 0.279 ;
    END
  END VDD
  PIN VSS
    DIRECTION INOUT ;
    USE GROUND ;
    SHAPE ABUTMENT ;
    PORT
      LAYER M1 ;
        RECT 0 -0.009 1.674 0.009 ;
    END
  END VSS
  OBS
    LAYER M1 ;
      RECT 0 0 0 0 ;
  END
END SDFLx4_bottom

MACRO TAPCELL_bottom
  CLASS CORE WELLTAP ;
  ORIGIN 0 0 ;
  FOREIGN TAPCELL_bottom 0 0 ;
  SIZE 0.054 BY 0.270 ;
  SYMMETRY X Y ;
  SITE asap7sc7p5t ;
  PIN VDD
    DIRECTION INOUT ;
    USE POWER ;
    SHAPE ABUTMENT ;
    PORT
      LAYER M1 ;
        RECT 0 0.261 0.108 0.279 ;
    END
  END VDD
  PIN VSS
    DIRECTION INOUT ;
    USE GROUND ;
    SHAPE ABUTMENT ;
    PORT
      LAYER M1 ;
        RECT 0 -0.009 0.108 0.009 ;
    END
  END VSS
END TAPCELL_bottom

MACRO TAPCELL_WITH_FILLER_bottom
  CLASS CORE WELLTAP ;
  ORIGIN 0 0 ;
  FOREIGN TAPCELL_WITH_FILLER_bottom 0 0 ;
  SIZE 0.054 BY 0.270 ;
  SYMMETRY X Y ;
  SITE asap7sc7p5t ;
  PIN VDD
    DIRECTION INOUT ;
    USE POWER ;
    SHAPE ABUTMENT ;
    PORT
      LAYER M1 ;
        RECT 0 0.261 0.162 0.279 ;
    END
  END VDD
  PIN VSS
    DIRECTION INOUT ;
    USE GROUND ;
    SHAPE ABUTMENT ;
    PORT
      LAYER M1 ;
        RECT 0 -0.009 0.162 0.009 ;
    END
  END VSS
END TAPCELL_WITH_FILLER_bottom

MACRO TIEHIx1_bottom
  CLASS CORE TIEHIGH ;
  ORIGIN 0 0 ;
  FOREIGN TIEHIx1_bottom 0 0 ;
  SIZE 0.054 BY 0.270 ;
  SYMMETRY X Y ;
  SITE asap7sc7p5t ;
  PIN H
    DIRECTION OUTPUT ;
    USE SIGNAL ;
    PORT
      LAYER M1 ;
        RECT 0.094 0.225 0.144 0.243 ;
        RECT 0.126 0.07 0.144 0.243 ;
        RECT 0.067 0.07 0.144 0.088 ;
    END
  END H
  PIN VDD
    DIRECTION INOUT ;
    USE POWER ;
    SHAPE ABUTMENT ;
    PORT
      LAYER M1 ;
        RECT 0 0.261 0.162 0.279 ;
    END
  END VDD
  PIN VSS
    DIRECTION INOUT ;
    USE GROUND ;
    SHAPE ABUTMENT ;
    PORT
      LAYER M1 ;
        RECT 0 -0.009 0.162 0.009 ;
    END
  END VSS
  OBS
    LAYER M1 ;
      RECT 0 0 0 0 ;
  END
END TIEHIx1_bottom

MACRO TIELOx1_bottom
  CLASS CORE TIELOW ;
  ORIGIN 0 0 ;
  FOREIGN TIELOx1_bottom 0 0 ;
  SIZE 0.054 BY 0.270 ;
  SYMMETRY X Y ;
  SITE asap7sc7p5t ;
  PIN L
    DIRECTION OUTPUT ;
    USE SIGNAL ;
    PORT
      LAYER M1 ;
        RECT 0.067 0.182 0.144 0.2 ;
        RECT 0.126 0.027 0.144 0.2 ;
        RECT 0.094 0.027 0.144 0.045 ;
    END
  END L
  PIN VDD
    DIRECTION INOUT ;
    USE POWER ;
    SHAPE ABUTMENT ;
    PORT
      LAYER M1 ;
        RECT 0 0.261 0.162 0.279 ;
    END
  END VDD
  PIN VSS
    DIRECTION INOUT ;
    USE GROUND ;
    SHAPE ABUTMENT ;
    PORT
      LAYER M1 ;
        RECT 0 -0.009 0.162 0.009 ;
    END
  END VSS
  OBS
    LAYER M1 ;
      RECT 0 0 0 0 ;
  END
END TIELOx1_bottom

MACRO XNOR2x1_bottom
  CLASS CORE ;
  ORIGIN 0 0 ;
  FOREIGN XNOR2x1_bottom 0 0 ;
  SIZE 0.054 BY 0.270 ;
  SYMMETRY X Y ;
  SITE asap7sc7p5t ;
  PIN B
    DIRECTION INPUT ;
    USE SIGNAL ;
    PORT
      LAYER M2 ;
        RECT 0.298 0.072 0.527 0.09 ;
      LAYER M1 ;
        RECT 0.504 0.07 0.522 0.152 ;
        RECT 0.305 0.126 0.365 0.144 ;
        RECT 0.305 0.067 0.323 0.144 ;
        RECT 0.213 0.067 0.323 0.085 ;
        RECT 0.213 0.027 0.231 0.085 ;
        RECT 0.018 0.027 0.231 0.045 ;
        RECT 0.018 0.126 0.078 0.144 ;
        RECT 0.018 0.027 0.036 0.236 ;
      LAYER V1 ;
        RECT 0.305 0.072 0.323 0.09 ;
        RECT 0.504 0.072 0.522 0.09 ;
    END
  END B
  PIN VDD
    DIRECTION INOUT ;
    USE POWER ;
    SHAPE ABUTMENT ;
    PORT
      LAYER M1 ;
        RECT 0 0.261 0.648 0.279 ;
    END
  END VDD
  PIN VSS
    DIRECTION INOUT ;
    USE GROUND ;
    SHAPE ABUTMENT ;
    PORT
      LAYER M1 ;
        RECT 0 -0.009 0.648 0.009 ;
    END
  END VSS
  PIN Y
    DIRECTION OUTPUT ;
    USE SIGNAL ;
    PORT
      LAYER M1 ;
        RECT 0.256 0.225 0.612 0.243 ;
        RECT 0.45 0.077 0.468 0.243 ;
        RECT 0.418 0.077 0.468 0.095 ;
    END
  END Y
  PIN A
    DIRECTION INPUT ;
    USE SIGNAL ;
    PORT
      LAYER M2 ;
        RECT 0.121 0.18 0.581 0.198 ;
      LAYER M1 ;
        RECT 0.526 0.189 0.576 0.207 ;
        RECT 0.558 0.121 0.576 0.207 ;
        RECT 0.107 0.189 0.144 0.207 ;
        RECT 0.126 0.121 0.144 0.207 ;
      LAYER V1 ;
        RECT 0.126 0.18 0.144 0.198 ;
        RECT 0.558 0.18 0.576 0.198 ;
    END
  END A
  OBS
    LAYER M1 ;
      RECT 0 0 0 0 ;
  END
END XNOR2x1_bottom

MACRO XNOR2x2_bottom
  CLASS CORE ;
  ORIGIN 0 0 ;
  FOREIGN XNOR2x2_bottom 0 0 ;
  SIZE 0.054 BY 0.270 ;
  SYMMETRY X Y ;
  SITE asap7sc7p5t ;
  PIN A
    DIRECTION INPUT ;
    USE SIGNAL ;
    PORT
      LAYER M1 ;
        RECT 0.261 0.225 0.44 0.243 ;
        RECT 0.422 0.126 0.44 0.243 ;
        RECT 0.391 0.126 0.44 0.144 ;
        RECT 0.261 0.183 0.279 0.243 ;
        RECT 0.126 0.183 0.279 0.201 ;
        RECT 0.126 0.12 0.144 0.201 ;
    END
  END A
  PIN B
    DIRECTION INPUT ;
    USE SIGNAL ;
    PORT
      LAYER M1 ;
        RECT 0.342 0.189 0.38 0.207 ;
        RECT 0.342 0.107 0.36 0.207 ;
    END
  END B
  PIN VDD
    DIRECTION INOUT ;
    USE POWER ;
    SHAPE ABUTMENT ;
    PORT
      LAYER M1 ;
        RECT 0 0.261 0.594 0.279 ;
    END
  END VDD
  PIN VSS
    DIRECTION INOUT ;
    USE GROUND ;
    SHAPE ABUTMENT ;
    PORT
      LAYER M1 ;
        RECT 0 -0.009 0.594 0.009 ;
    END
  END VSS
  PIN Y
    DIRECTION OUTPUT ;
    USE SIGNAL ;
    PORT
      LAYER M1 ;
        RECT 0.472 0.225 0.576 0.243 ;
        RECT 0.558 0.027 0.576 0.243 ;
        RECT 0.472 0.027 0.576 0.045 ;
    END
  END Y
  OBS
    LAYER M1 ;
      RECT 0 0 0 0 ;
  END
END XNOR2x2_bottom

MACRO XNOR2xp5_bottom
  CLASS CORE ;
  ORIGIN 0 0 ;
  FOREIGN XNOR2xp5_bottom 0 0 ;
  SIZE 0.054 BY 0.270 ;
  SYMMETRY X Y ;
  SITE asap7sc7p5t ;
  PIN A
    DIRECTION INPUT ;
    USE SIGNAL ;
    PORT
      LAYER M1 ;
        RECT 0.342 0.063 0.36 0.164 ;
        RECT 0.207 0.063 0.36 0.081 ;
        RECT 0.207 0.027 0.225 0.081 ;
        RECT 0.072 0.027 0.225 0.045 ;
        RECT 0.072 0.027 0.09 0.2 ;
    END
  END A
  PIN B
    DIRECTION INPUT ;
    USE SIGNAL ;
    PORT
      LAYER M1 ;
        RECT 0.126 0.07 0.144 0.2 ;
    END
  END B
  PIN VDD
    DIRECTION INOUT ;
    USE POWER ;
    SHAPE ABUTMENT ;
    PORT
      LAYER M1 ;
        RECT 0 0.261 0.486 0.279 ;
    END
  END VDD
  PIN VSS
    DIRECTION INOUT ;
    USE GROUND ;
    SHAPE ABUTMENT ;
    PORT
      LAYER M1 ;
        RECT 0 -0.009 0.486 0.009 ;
    END
  END VSS
  PIN Y
    DIRECTION OUTPUT ;
    USE SIGNAL ;
    PORT
      LAYER M1 ;
        RECT 0.256 0.225 0.468 0.243 ;
        RECT 0.45 0.027 0.468 0.243 ;
        RECT 0.423 0.027 0.468 0.045 ;
    END
  END Y
  OBS
    LAYER M1 ;
      RECT 0 0 0 0 ;
  END
END XNOR2xp5_bottom

MACRO XOR2x1_bottom
  CLASS CORE ;
  ORIGIN 0 0 ;
  FOREIGN XOR2x1_bottom 0 0 ;
  SIZE 0.054 BY 0.270 ;
  SYMMETRY X Y ;
  SITE asap7sc7p5t ;
  PIN A
    DIRECTION INPUT ;
    USE SIGNAL ;
    PORT
      LAYER M2 ;
        RECT 0.298 0.18 0.527 0.198 ;
      LAYER M1 ;
        RECT 0.504 0.118 0.522 0.2 ;
        RECT 0.305 0.126 0.365 0.144 ;
        RECT 0.213 0.185 0.323 0.203 ;
        RECT 0.305 0.126 0.323 0.203 ;
        RECT 0.018 0.225 0.231 0.243 ;
        RECT 0.213 0.185 0.231 0.243 ;
        RECT 0.018 0.126 0.078 0.144 ;
        RECT 0.018 0.034 0.036 0.243 ;
      LAYER V1 ;
        RECT 0.305 0.18 0.323 0.198 ;
        RECT 0.504 0.18 0.522 0.198 ;
    END
  END A
  PIN VDD
    DIRECTION INOUT ;
    USE POWER ;
    SHAPE ABUTMENT ;
    PORT
      LAYER M1 ;
        RECT 0 0.261 0.648 0.279 ;
    END
  END VDD
  PIN VSS
    DIRECTION INOUT ;
    USE GROUND ;
    SHAPE ABUTMENT ;
    PORT
      LAYER M1 ;
        RECT 0 -0.009 0.648 0.009 ;
    END
  END VSS
  PIN Y
    DIRECTION OUTPUT ;
    USE SIGNAL ;
    PORT
      LAYER M1 ;
        RECT 0.256 0.027 0.612 0.045 ;
        RECT 0.418 0.175 0.468 0.193 ;
        RECT 0.45 0.027 0.468 0.193 ;
    END
  END Y
  PIN B
    DIRECTION INPUT ;
    USE SIGNAL ;
    PORT
      LAYER M2 ;
        RECT 0.121 0.072 0.581 0.09 ;
      LAYER M1 ;
        RECT 0.558 0.063 0.576 0.149 ;
        RECT 0.526 0.063 0.576 0.081 ;
        RECT 0.126 0.063 0.144 0.149 ;
        RECT 0.107 0.063 0.144 0.081 ;
      LAYER V1 ;
        RECT 0.126 0.072 0.144 0.09 ;
        RECT 0.558 0.072 0.576 0.09 ;
    END
  END B
  OBS
    LAYER M1 ;
      RECT 0 0 0 0 ;
  END
END XOR2x1_bottom

MACRO XOR2x2_bottom
  CLASS CORE ;
  ORIGIN 0 0 ;
  FOREIGN XOR2x2_bottom 0 0 ;
  SIZE 0.054 BY 0.270 ;
  SYMMETRY X Y ;
  SITE asap7sc7p5t ;
  PIN A
    DIRECTION INPUT ;
    USE SIGNAL ;
    PORT
      LAYER M1 ;
        RECT 0.342 0.063 0.38 0.081 ;
        RECT 0.342 0.063 0.36 0.163 ;
    END
  END A
  PIN B
    DIRECTION INPUT ;
    USE SIGNAL ;
    PORT
      LAYER M1 ;
        RECT 0.422 0.027 0.44 0.163 ;
        RECT 0.391 0.126 0.44 0.144 ;
        RECT 0.261 0.027 0.44 0.045 ;
        RECT 0.126 0.069 0.279 0.087 ;
        RECT 0.261 0.027 0.279 0.087 ;
        RECT 0.126 0.069 0.144 0.15 ;
    END
  END B
  PIN VDD
    DIRECTION INOUT ;
    USE POWER ;
    SHAPE ABUTMENT ;
    PORT
      LAYER M1 ;
        RECT 0 0.261 0.594 0.279 ;
    END
  END VDD
  PIN VSS
    DIRECTION INOUT ;
    USE GROUND ;
    SHAPE ABUTMENT ;
    PORT
      LAYER M1 ;
        RECT 0 -0.009 0.594 0.009 ;
    END
  END VSS
  PIN Y
    DIRECTION OUTPUT ;
    USE SIGNAL ;
    PORT
      LAYER M1 ;
        RECT 0.472 0.225 0.576 0.243 ;
        RECT 0.558 0.027 0.576 0.243 ;
        RECT 0.472 0.027 0.576 0.045 ;
    END
  END Y
  OBS
    LAYER M1 ;
      RECT 0 0 0 0 ;
  END
END XOR2x2_bottom

MACRO XOR2xp5_bottom
  CLASS CORE ;
  ORIGIN 0 0 ;
  FOREIGN XOR2xp5_bottom 0 0 ;
  SIZE 0.054 BY 0.270 ;
  SYMMETRY X Y ;
  SITE asap7sc7p5t ;
  PIN A
    DIRECTION INPUT ;
    USE SIGNAL ;
    PORT
      LAYER M1 ;
        RECT 0.207 0.189 0.36 0.207 ;
        RECT 0.342 0.12 0.36 0.207 ;
        RECT 0.018 0.225 0.225 0.243 ;
        RECT 0.207 0.189 0.225 0.243 ;
        RECT 0.018 0.126 0.078 0.144 ;
        RECT 0.018 0.034 0.036 0.243 ;
    END
  END A
  PIN B
    DIRECTION INPUT ;
    USE SIGNAL ;
    PORT
      LAYER M1 ;
        RECT 0.106 0.189 0.144 0.207 ;
        RECT 0.126 0.063 0.144 0.207 ;
        RECT 0.107 0.063 0.144 0.081 ;
    END
  END B
  PIN VDD
    DIRECTION INOUT ;
    USE POWER ;
    SHAPE ABUTMENT ;
    PORT
      LAYER M1 ;
        RECT 0 0.261 0.486 0.279 ;
    END
  END VDD
  PIN VSS
    DIRECTION INOUT ;
    USE GROUND ;
    SHAPE ABUTMENT ;
    PORT
      LAYER M1 ;
        RECT 0 -0.009 0.486 0.009 ;
    END
  END VSS
  PIN Y
    DIRECTION OUTPUT ;
    USE SIGNAL ;
    PORT
      LAYER M1 ;
        RECT 0.423 0.225 0.468 0.243 ;
        RECT 0.45 0.027 0.468 0.243 ;
        RECT 0.256 0.027 0.468 0.045 ;
    END
  END Y
  OBS
    LAYER M1 ;
      RECT 0 0 0 0 ;
  END
END XOR2xp5_bottom

END LIBRARY
